<?xml version='1.0' encoding='utf-8'?>
<device schemaVersion="1.1" noNamespaceSchemaLocation="CMSIS-SVD.xsd">
  <vendor>PUYA Co.Ltd</vendor>
  <vendorID>PUYA</vendorID>
  <name>PY32E407xx</name>
  <series>PY32E4</series>
  <version>1.0.0</version>
  <cpu>
    <name>CM4</name>
    <revision>r0p1</revision>
    <endian>little</endian>
    <mpuPresent>true</mpuPresent>
    <fpuPresent>true</fpuPresent>
    <nvicPrioBits>4</nvicPrioBits>
    <vendorSystickConfig>false</vendorSystickConfig>
  </cpu>
  <addressUnitBits>8</addressUnitBits>
  <width>32</width>
  <size>32</size>
  <access>read-write</access>
  <resetValue>0x0</resetValue>
  <resetMask>0xFFFFFFFF</resetMask>
  <peripherals>
    <peripheral>
      <name>ADC1</name>
      <groupName>ADC</groupName>
      <baseAddress>0x40012400</baseAddress>
      <addressBlock>
        <offset>0x0</offset>
        <size>0x200</size>
        <usage>registers</usage>
      </addressBlock>
      <interrupt>
        <name>ADC1_2</name>
        <description>ADC1 and ADC2 global interrupt</description>
        <value>18</value>
      </interrupt>
      <registers>
        <register>
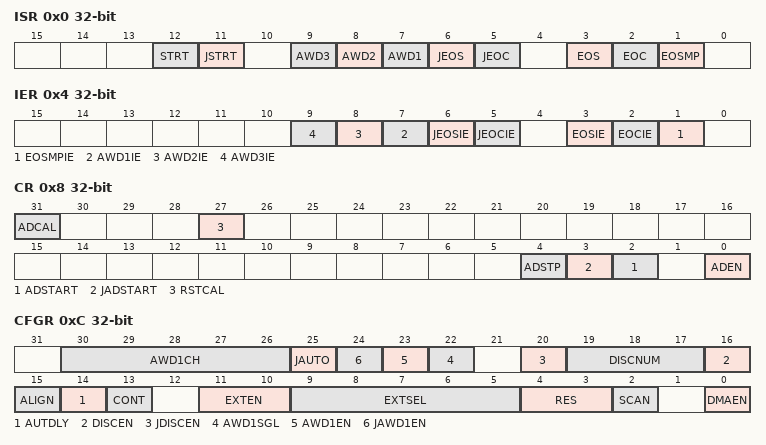
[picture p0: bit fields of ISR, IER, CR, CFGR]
          <name>ISR</name>
          <addressOffset>0x0</addressOffset>
          <fields>
            <field>
              <name>EOSMP</name>
              <bitRange>[1:1]</bitRange>
            </field>
            <field>
              <name>EOC</name>
              <bitRange>[2:2]</bitRange>
            </field>
            <field>
              <name>EOS</name>
              <bitRange>[3:3]</bitRange>
            </field>
            <field>
              <name>JEOC</name>
              <bitRange>[5:5]</bitRange>
            </field>
            <field>
              <name>JEOS</name>
              <bitRange>[6:6]</bitRange>
            </field>
            <field>
              <name>AWD1</name>
              <bitRange>[7:7]</bitRange>
            </field>
            <field>
              <name>AWD2</name>
              <bitRange>[8:8]</bitRange>
            </field>
            <field>
              <name>AWD3</name>
              <bitRange>[9:9]</bitRange>
            </field>
            <field>
              <name>JSTRT</name>
              <bitRange>[11:11]</bitRange>
            </field>
            <field>
              <name>STRT</name>
              <bitRange>[12:12]</bitRange>
            </field>
          </fields>
        </register>
        <register>
          <name>IER</name>
          <addressOffset>0x4</addressOffset>
          <fields>
            <field>
              <name>EOSMPIE</name>
              <bitRange>[1:1]</bitRange>
            </field>
            <field>
              <name>EOCIE</name>
              <bitRange>[2:2]</bitRange>
            </field>
            <field>
              <name>EOSIE</name>
              <bitRange>[3:3]</bitRange>
            </field>
            <field>
              <name>JEOCIE</name>
              <bitRange>[5:5]</bitRange>
            </field>
            <field>
              <name>JEOSIE</name>
              <bitRange>[6:6]</bitRange>
            </field>
            <field>
              <name>AWD1IE</name>
              <bitRange>[7:7]</bitRange>
            </field>
            <field>
              <name>AWD2IE</name>
              <bitRange>[8:8]</bitRange>
            </field>
            <field>
              <name>AWD3IE</name>
              <bitRange>[9:9]</bitRange>
            </field>
          </fields>
        </register>
        <register>
          <name>CR</name>
          <addressOffset>0x8</addressOffset>
          <fields>
            <field>
              <name>ADEN</name>
              <bitRange>[0:0]</bitRange>
            </field>
            <field>
              <name>ADSTART</name>
              <bitRange>[2:2]</bitRange>
            </field>
            <field>
              <name>JADSTART</name>
              <bitRange>[3:3]</bitRange>
            </field>
            <field>
              <name>ADSTP</name>
              <bitRange>[4:4]</bitRange>
            </field>
            <field>
              <name>RSTCAL</name>
              <bitRange>[27:27]</bitRange>
            </field>
            <field>
              <name>ADCAL</name>
              <bitRange>[31:31]</bitRange>
            </field>
          </fields>
        </register>
        <register>
          <name>CFGR</name>
          <addressOffset>0xC</addressOffset>
          <fields>
            <field>
              <name>DMAEN</name>
              <bitRange>[0:0]</bitRange>
            </field>
            <field>
              <name>SCAN</name>
              <bitRange>[2:2]</bitRange>
            </field>
            <field>
              <name>RES</name>
              <bitRange>[4:3]</bitRange>
            </field>
            <field>
              <name>EXTSEL</name>
              <bitRange>[9:5]</bitRange>
            </field>
            <field>
              <name>EXTEN</name>
              <bitRange>[11:10]</bitRange>
            </field>
            <field>
              <name>CONT</name>
              <bitRange>[13:13]</bitRange>
            </field>
            <field>
              <name>AUTDLY</name>
              <bitRange>[14:14]</bitRange>
            </field>
            <field>
              <name>ALIGN</name>
              <bitRange>[15:15]</bitRange>
            </field>
            <field>
              <name>DISCEN</name>
              <bitRange>[16:16]</bitRange>
            </field>
            <field>
              <name>DISCNUM</name>
              <bitRange>[19:17]</bitRange>
            </field>
            <field>
              <name>JDISCEN</name>
              <bitRange>[20:20]</bitRange>
            </field>
            <field>
              <name>AWD1SGL</name>
              <bitRange>[22:22]</bitRange>
            </field>
            <field>
              <name>AWD1EN</name>
              <bitRange>[23:23]</bitRange>
            </field>
            <field>
              <name>JAWD1EN</name>
              <bitRange>[24:24]</bitRange>
            </field>
            <field>
              <name>JAUTO</name>
              <bitRange>[25:25]</bitRange>
            </field>
            <field>
              <name>AWD1CH</name>
              <bitRange>[30:26]</bitRange>
            </field>
          </fields>
        </register>
        <register>
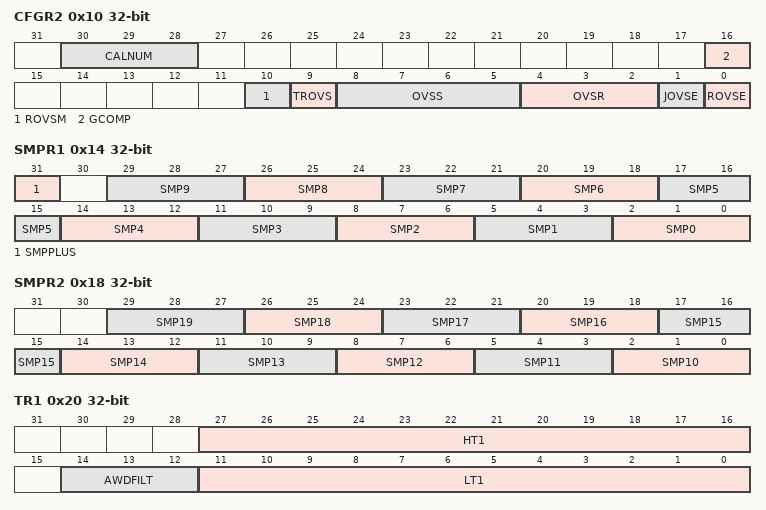
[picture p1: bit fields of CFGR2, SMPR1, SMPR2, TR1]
          <name>CFGR2</name>
          <addressOffset>0x10</addressOffset>
          <fields>
            <field>
              <name>ROVSE</name>
              <bitRange>[0:0]</bitRange>
            </field>
            <field>
              <name>JOVSE</name>
              <bitRange>[1:1]</bitRange>
            </field>
            <field>
              <name>OVSR</name>
              <bitRange>[4:2]</bitRange>
            </field>
            <field>
              <name>OVSS</name>
              <bitRange>[8:5]</bitRange>
            </field>
            <field>
              <name>TROVS</name>
              <bitRange>[9:9]</bitRange>
            </field>
            <field>
              <name>ROVSM</name>
              <bitRange>[10:10]</bitRange>
            </field>
            <field>
              <name>GCOMP</name>
              <bitRange>[16:16]</bitRange>
            </field>
            <field>
              <name>CALNUM</name>
              <bitRange>[30:28]</bitRange>
            </field>
          </fields>
        </register>
        <register>
          <name>SMPR1</name>
          <addressOffset>0x14</addressOffset>
          <fields>
            <field>
              <name>SMP0</name>
              <bitRange>[2:0]</bitRange>
            </field>
            <field>
              <name>SMP1</name>
              <bitRange>[5:3]</bitRange>
            </field>
            <field>
              <name>SMP2</name>
              <bitRange>[8:6]</bitRange>
            </field>
            <field>
              <name>SMP3</name>
              <bitRange>[11:9]</bitRange>
            </field>
            <field>
              <name>SMP4</name>
              <bitRange>[14:12]</bitRange>
            </field>
            <field>
              <name>SMP5</name>
              <bitRange>[17:15]</bitRange>
            </field>
            <field>
              <name>SMP6</name>
              <bitRange>[20:18]</bitRange>
            </field>
            <field>
              <name>SMP7</name>
              <bitRange>[23:21]</bitRange>
            </field>
            <field>
              <name>SMP8</name>
              <bitRange>[26:24]</bitRange>
            </field>
            <field>
              <name>SMP9</name>
              <bitRange>[29:27]</bitRange>
            </field>
          <field><name>SMPPLUS</name><description>SMPPLUS</description><bitRange>[31:31]</bitRange><access>read-write</access></field></fields>
        </register>
        <register>
          <name>SMPR2</name>
          <addressOffset>0x18</addressOffset>
          <fields>
            <field>
              <name>SMP10</name>
              <bitRange>[2:0]</bitRange>
            </field>
            <field>
              <name>SMP11</name>
              <bitRange>[5:3]</bitRange>
            </field>
            <field>
              <name>SMP12</name>
              <bitRange>[8:6]</bitRange>
            </field>
            <field>
              <name>SMP13</name>
              <bitRange>[11:9]</bitRange>
            </field>
            <field>
              <name>SMP14</name>
              <bitRange>[14:12]</bitRange>
            </field>
            <field>
              <name>SMP15</name>
              <bitRange>[17:15]</bitRange>
            </field>
            <field>
              <name>SMP16</name>
              <bitRange>[20:18]</bitRange>
            </field>
            <field>
              <name>SMP17</name>
              <bitRange>[23:21]</bitRange>
            </field>
            <field>
              <name>SMP18</name>
              <bitRange>[26:24]</bitRange>
            </field>
            <field>
              <name>SMP19</name>
              <bitRange>[29:27]</bitRange>
            </field>
          </fields>
        </register>
        <register>
          <name>TR1</name>
          <addressOffset>0x20</addressOffset>
          <fields>
            <field>
              <name>LT1</name>
              <bitRange>[11:0]</bitRange>
            </field>
            <field>
              <name>AWDFILT</name>
              <bitRange>[14:12]</bitRange>
            </field>
            <field>
              <name>HT1</name>
              <bitRange>[27:16]</bitRange>
            </field>
          </fields>
        </register>
        <register>
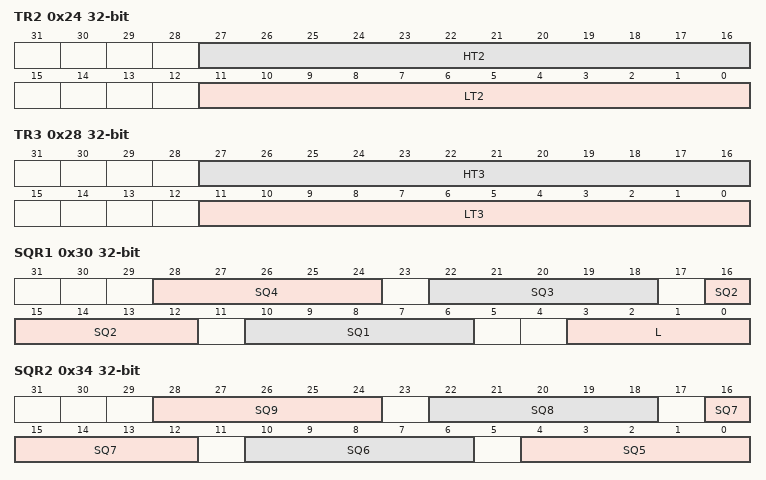
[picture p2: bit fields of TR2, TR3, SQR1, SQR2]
          <name>TR2</name>
          <addressOffset>0x24</addressOffset>
          <fields>
            <field>
              <name>LT2</name>
              <bitRange>[11:0]</bitRange>
            </field>
            <field>
              <name>HT2</name>
              <bitRange>[27:16]</bitRange>
            </field>
          </fields>
        </register>
        <register>
          <name>TR3</name>
          <addressOffset>0x28</addressOffset>
          <fields>
            <field>
              <name>LT3</name>
              <bitRange>[11:0]</bitRange>
            </field>
            <field>
              <name>HT3</name>
              <bitRange>[27:16]</bitRange>
            </field>
          </fields>
        </register>
        <register>
          <name>SQR1</name>
          <addressOffset>0x30</addressOffset>
          <fields>
            <field>
              <name>L</name>
              <bitRange>[3:0]</bitRange>
            </field>
            <field>
              <name>SQ1</name>
              <bitRange>[10:6]</bitRange>
            </field>
            <field>
              <name>SQ2</name>
              <bitRange>[16:12]</bitRange>
            </field>
            <field>
              <name>SQ3</name>
              <bitRange>[22:18]</bitRange>
            </field>
            <field>
              <name>SQ4</name>
              <bitRange>[28:24]</bitRange>
            </field>
          </fields>
        </register>
        <register>
          <name>SQR2</name>
          <addressOffset>0x34</addressOffset>
          <fields>
            <field>
              <name>SQ5</name>
              <bitRange>[4:0]</bitRange>
            </field>
            <field>
              <name>SQ6</name>
              <bitRange>[10:6]</bitRange>
            </field>
            <field>
              <name>SQ7</name>
              <bitRange>[16:12]</bitRange>
            </field>
            <field>
              <name>SQ8</name>
              <bitRange>[22:18]</bitRange>
            </field>
            <field>
              <name>SQ9</name>
              <bitRange>[28:24]</bitRange>
            </field>
          </fields>
        </register>
        <register>
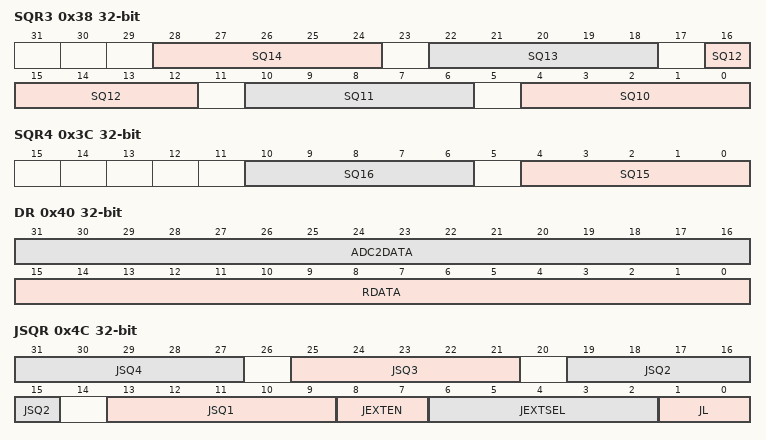
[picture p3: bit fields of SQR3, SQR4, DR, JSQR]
          <name>SQR3</name>
          <addressOffset>0x38</addressOffset>
          <fields>
            <field>
              <name>SQ10</name>
              <bitRange>[4:0]</bitRange>
            </field>
            <field>
              <name>SQ11</name>
              <bitRange>[10:6]</bitRange>
            </field>
            <field>
              <name>SQ12</name>
              <bitRange>[16:12]</bitRange>
            </field>
            <field>
              <name>SQ13</name>
              <bitRange>[22:18]</bitRange>
            </field>
            <field>
              <name>SQ14</name>
              <bitRange>[28:24]</bitRange>
            </field>
          </fields>
        </register>
        <register>
          <name>SQR4</name>
          <addressOffset>0x3C</addressOffset>
          <fields>
            <field>
              <name>SQ15</name>
              <bitRange>[4:0]</bitRange>
            </field>
            <field>
              <name>SQ16</name>
              <bitRange>[10:6]</bitRange>
            </field>
          </fields>
        </register>
        <register>
          <name>DR</name>
          <addressOffset>0x40</addressOffset>
          <fields>
            <field>
              <name>RDATA</name>
              <bitRange>[15:0]</bitRange>
              <access>read-only</access>
            </field>
            <field>
              <name>ADC2DATA</name>
              <bitRange>[31:16]</bitRange>
              <access>read-only</access>
            </field>
          </fields>
        </register>
        <register>
          <name>JSQR</name>
          <addressOffset>0x4C</addressOffset>
          <fields>
            <field>
              <name>JL</name>
              <bitRange>[1:0]</bitRange>
            </field>
            <field>
              <name>JEXTSEL</name>
              <bitRange>[6:2]</bitRange>
            </field>
            <field>
              <name>JSQ1</name>
              <bitRange>[13:9]</bitRange>
            </field>
            <field>
              <name>JSQ2</name>
              <bitRange>[19:15]</bitRange>
            </field>
            <field>
              <name>JSQ3</name>
              <bitRange>[25:21]</bitRange>
            </field>
            <field>
              <name>JSQ4</name>
              <bitRange>[31:27]</bitRange>
            </field>
          <field><name>JEXTEN</name><description>JEXTEN</description><bitRange>[8:7]</bitRange><access>read-write</access></field></fields>
        </register>
        <register>
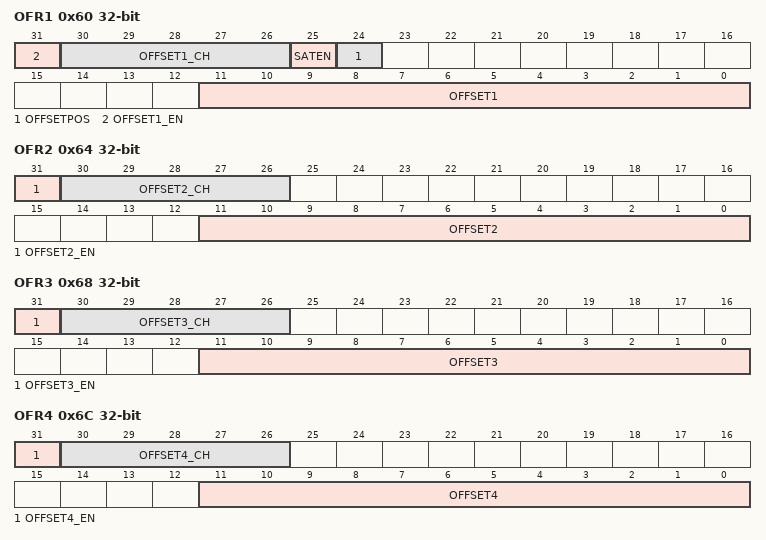
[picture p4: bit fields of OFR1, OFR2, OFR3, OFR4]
          <name>OFR1</name>
          <addressOffset>0x60</addressOffset>
          <fields>
            <field>
              <name>OFFSET1</name>
              <bitRange>[11:0]</bitRange>
            </field>
            <field>
              <name>OFFSETPOS</name>
              <bitRange>[24:24]</bitRange>
            </field>
            <field>
              <name>SATEN</name>
              <bitRange>[25:25]</bitRange>
            </field>
            <field>
              <name>OFFSET1_CH</name>
              <bitRange>[30:26]</bitRange>
            </field>
            <field>
              <name>OFFSET1_EN</name>
              <bitRange>[31:31]</bitRange>
            </field>
          </fields>
        </register>
        <register>
          <name>OFR2</name>
          <addressOffset>0x64</addressOffset>
          <fields>
            <field>
              <name>OFFSET2</name>
              <bitRange>[11:0]</bitRange>
            </field>
            <field>
              <name>OFFSET2_CH</name>
              <bitRange>[30:26]</bitRange>
            </field>
            <field>
              <name>OFFSET2_EN</name>
              <bitRange>[31:31]</bitRange>
            </field>
          </fields>
        </register>
        <register>
          <name>OFR3</name>
          <addressOffset>0x68</addressOffset>
          <fields>
            <field>
              <name>OFFSET3</name>
              <bitRange>[11:0]</bitRange>
            </field>
            <field>
              <name>OFFSET3_CH</name>
              <bitRange>[30:26]</bitRange>
            </field>
            <field>
              <name>OFFSET3_EN</name>
              <bitRange>[31:31]</bitRange>
            </field>
          </fields>
        </register>
        <register>
          <name>OFR4</name>
          <addressOffset>0x6C</addressOffset>
          <fields>
            <field>
              <name>OFFSET4</name>
              <bitRange>[11:0]</bitRange>
            </field>
            <field>
              <name>OFFSET4_CH</name>
              <bitRange>[30:26]</bitRange>
            </field>
            <field>
              <name>OFFSET4_EN</name>
              <bitRange>[31:31]</bitRange>
            </field>
          </fields>
        </register>
        <register>
          <name>JDR1</name>
          <addressOffset>0x80</addressOffset>
          <fields>
            <field>
              <name>JDATA</name>
              <bitRange>[15:0]</bitRange>
              <access>read-only</access>
            </field>
          </fields>
        </register>
        <register>
          <name>JDR2</name>
          <addressOffset>0x84</addressOffset>
          <fields>
            <field>
              <name>JDATA</name>
              <bitRange>[15:0]</bitRange>
              <access>read-only</access>
            </field>
          </fields>
        </register>
        <register>
          <name>JDR3</name>
          <addressOffset>0x88</addressOffset>
          <fields>
            <field>
              <name>JDATA</name>
              <bitRange>[15:0]</bitRange>
              <access>read-only</access>
            </field>
          </fields>
        </register>
        <register>
          <name>JDR4</name>
          <addressOffset>0x8C</addressOffset>
          <fields>
            <field>
              <name>JDATA</name>
              <bitRange>[15:0]</bitRange>
              <access>read-only</access>
            </field>
          </fields>
        </register>
        <register>
          <name>AWD2CR</name>
          <addressOffset>0xA0</addressOffset>
          <fields>
            <field>
              <name>AWD2CH</name>
              <bitRange>[19:0]</bitRange>
            </field>
          </fields>
        </register>
        <register>
          <name>AWD3CR</name>
          <addressOffset>0xA4</addressOffset>
          <fields>
            <field>
              <name>AWD3CH</name>
              <bitRange>[19:0]</bitRange>
            </field>
          </fields>
        </register>
        <register>
          <name>DIFSEL</name>
          <addressOffset>0xB0</addressOffset>
          <fields>
            <field>
              <name>DIFSEL</name>
              <bitRange>[19:0]</bitRange>
            </field>
          </fields>
        </register>
        <register>
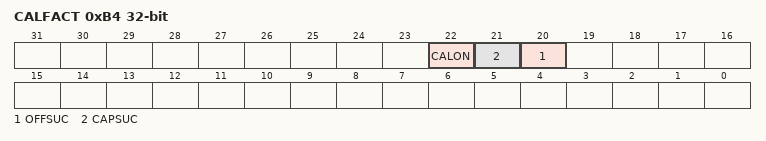
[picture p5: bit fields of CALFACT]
          <name>CALFACT</name>
          <addressOffset>0xB4</addressOffset>
          <fields>
            <field>
              <name>OFFSUC</name>
              <bitRange>[20:20]</bitRange>
            </field>
            <field>
              <name>CAPSUC</name>
              <bitRange>[21:21]</bitRange>
            </field>
            <field>
              <name>CALON</name>
              <bitRange>[22:22]</bitRange>
              <access>read-only</access>
            </field>
          </fields>
        </register>
        <register>
          <name>GCOMP</name>
          <addressOffset>0xC0</addressOffset>
          <fields>
            <field>
              <name>GCOMPCOEFF</name>
              <bitRange>[13:0]</bitRange>
            </field>
          </fields>
        </register>
      </registers>
    </peripheral>
    <peripheral derivedFrom="ADC1">
      <name>ADC2</name>
      <baseAddress>0x40012800</baseAddress>
    </peripheral>
    <peripheral derivedFrom="ADC1">
      <name>ADC3</name>
      <baseAddress>0x40013C00</baseAddress>
      <interrupt>
        <name>ADC3</name>
        <description>ADC3 global interrupt</description>
        <value>47</value>
      </interrupt>
    </peripheral>
    <peripheral>
      <name>ADC12_COMMON</name>
      <description>Analog-to-Digital Converter</description>
      <baseAddress>0x40012700</baseAddress>
      <addressBlock>
        <offset>0x0</offset>
        <size>0x10</size>
        <usage>registers</usage>
      </addressBlock>
      <registers>
        <register>
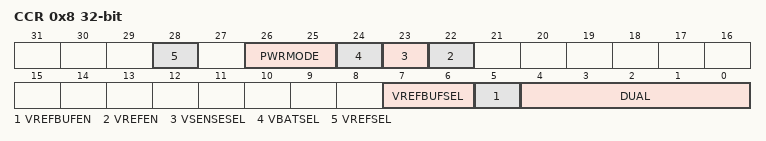
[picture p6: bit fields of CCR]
          <name>CCR</name>
          <description>ADC common control register</description>
          <addressOffset>0x8</addressOffset>
          <fields>
            <field>
              <name>DUAL</name>
              <description>Dual ADC mode selection</description>
              <bitRange>[4:0]</bitRange>
            </field>
            <field>
              <name>VREFBUFEN</name>
              <description>VrefBuffer enable</description>
              <bitRange>[5:5]</bitRange>
            </field>
            <field>
              <name>VREFBUFSEL</name>
              <description>VREFBUF output voltage select</description>
              <bitRange>[7:6]</bitRange>
            </field>
            <field>
              <name>VREFEN</name>
              <description>VREFINT enable</description>
              <bitRange>[22:22]</bitRange>
            </field>
            <field>
              <name>VSENSESEL</name>
              <description>VTS selection</description>
              <bitRange>[23:23]</bitRange>
            </field>
            <field>
              <name>VBATSEL</name>
              <description>VBAT selection</description>
              <bitRange>[24:24]</bitRange>
            </field>
            <field>
              <name>PWRMODE</name>
              <description>ADC power mode</description>
              <bitRange>[26:25]</bitRange>
            </field>
            <field>
              <name>VREFSEL</name>
              <description>ADC reference selection</description>
              <bitRange>[28:28]</bitRange>
            </field>
          </fields>
        </register>
      </registers>
    </peripheral>
    <peripheral>
      <name>AES</name>
      <baseAddress>0x48002400</baseAddress>
      <addressBlock>
        <offset>0x0</offset>
        <size>0xB0</size>
        <usage>registers</usage>
      </addressBlock>
      <interrupt>
        <name>AES</name>
        <description>AES global Interrupt</description>
        <value>70</value>
      </interrupt>
      <registers>
        <register>
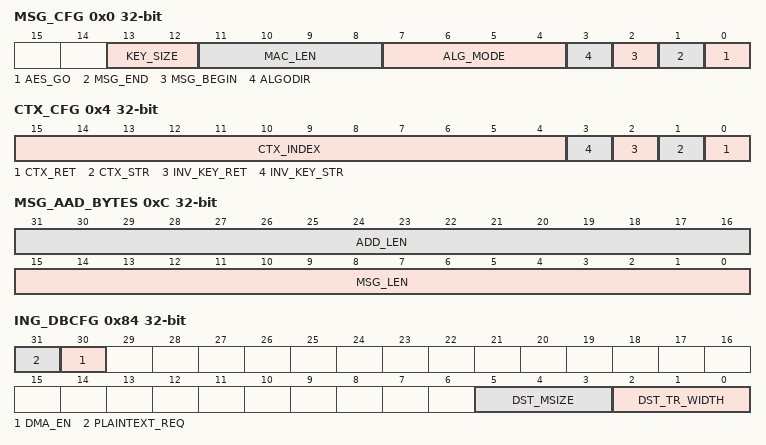
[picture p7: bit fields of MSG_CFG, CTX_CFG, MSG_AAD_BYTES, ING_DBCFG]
          <name>MSG_CFG</name>
          <addressOffset>0x0</addressOffset>
          <fields>
            <field>
              <name>AES_GO</name>
              <bitRange>[0:0]</bitRange>
            </field>
            <field>
              <name>MSG_END</name>
              <bitRange>[1:1]</bitRange>
            </field>
            <field>
              <name>MSG_BEGIN</name>
              <bitRange>[2:2]</bitRange>
            </field>
            <field>
              <name>ALGODIR</name>
              <bitRange>[3:3]</bitRange>
            </field>
            <field>
              <name>ALG_MODE</name>
              <bitRange>[7:4]</bitRange>
            </field>
            <field>
              <name>MAC_LEN</name>
              <bitRange>[11:8]</bitRange>
            </field>
            <field>
              <name>KEY_SIZE</name>
              <bitRange>[13:12]</bitRange>
            </field>
          </fields>
        </register>
        <register>
          <name>CTX_CFG</name>
          <addressOffset>0x4</addressOffset>
          <fields>
            <field>
              <name>CTX_RET</name>
              <bitRange>[0:0]</bitRange>
            </field>
            <field>
              <name>CTX_STR</name>
              <bitRange>[1:1]</bitRange>
            </field>
            <field>
              <name>INV_KEY_RET</name>
              <bitRange>[2:2]</bitRange>
            </field>
            <field>
              <name>INV_KEY_STR</name>
              <bitRange>[3:3]</bitRange>
            </field>
            <field>
              <name>CTX_INDEX</name>
              <bitRange>[15:4]</bitRange>
            </field>
          </fields>
        </register>
        <register>
          <name>MSG_TOTAL_BYTES</name>
          <addressOffset>0x8</addressOffset>
          <fields>
            <field>
              <name>TOTAL_BYTES</name>
              <bitRange>[27:0]</bitRange>
            </field>
          </fields>
        </register>
        <register>
          <name>MSG_AAD_BYTES</name>
          <addressOffset>0xC</addressOffset>
          <fields>
            <field>
              <name>MSG_LEN</name>
              <bitRange>[15:0]</bitRange>
            </field>
            <field>
              <name>ADD_LEN</name>
              <bitRange>[31:16]</bitRange>
            </field>
          </fields>
        </register>
        <register>
          <name>GCM_AAD_INFO</name>
          <addressOffset>0x10</addressOffset>
          <fields>
            <field>
              <name>ADD_LEN_TOT</name>
              <bitRange>[27:0]</bitRange>
            </field>
          </fields>
        </register>
        <register>
          <name>CTX_KEY0</name>
          <addressOffset>0x20</addressOffset>
          <fields>
            <field>
              <name>KEY0</name>
              <bitRange>[31:0]</bitRange>
            </field>
          </fields>
        </register>
        <register>
          <name>CTX_KEY1</name>
          <addressOffset>0x24</addressOffset>
          <fields>
            <field>
              <name>KEY1</name>
              <bitRange>[31:0]</bitRange>
            </field>
          </fields>
        </register>
        <register>
          <name>CTX_KEY2</name>
          <addressOffset>0x28</addressOffset>
          <fields>
            <field>
              <name>KEY2</name>
              <bitRange>[31:0]</bitRange>
            </field>
          </fields>
        </register>
        <register>
          <name>CTX_KEY3</name>
          <addressOffset>0x2C</addressOffset>
          <fields>
            <field>
              <name>KEY3</name>
              <bitRange>[31:0]</bitRange>
            </field>
          </fields>
        </register>
        <register>
          <name>CTX_KEY4</name>
          <addressOffset>0x30</addressOffset>
          <fields>
            <field>
              <name>KEY4</name>
              <bitRange>[31:0]</bitRange>
            </field>
          </fields>
        </register>
        <register>
          <name>CTX_KEY5</name>
          <addressOffset>0x34</addressOffset>
          <fields>
            <field>
              <name>KEY5</name>
              <bitRange>[31:0]</bitRange>
            </field>
          </fields>
        </register>
        <register>
          <name>CTX_KEY6</name>
          <addressOffset>0x38</addressOffset>
          <fields>
            <field>
              <name>KEY6</name>
              <bitRange>[31:0]</bitRange>
            </field>
          </fields>
        </register>
        <register>
          <name>CTX_KEY7</name>
          <addressOffset>0x3C</addressOffset>
          <fields>
            <field>
              <name>KEY7</name>
              <bitRange>[31:0]</bitRange>
            </field>
          </fields>
        </register>
        <register>
          <name>CTX_CBC_KEY0</name>
          <addressOffset>0x40</addressOffset>
          <fields>
            <field>
              <name>CBC_KEY0</name>
              <bitRange>[31:0]</bitRange>
            </field>
          </fields>
        </register>
        <register>
          <name>CTX_CBC_KEY1</name>
          <addressOffset>0x44</addressOffset>
          <fields>
            <field>
              <name>CBC_KEY1</name>
              <bitRange>[31:0]</bitRange>
            </field>
          </fields>
        </register>
        <register>
          <name>CTX_CBC_KEY2</name>
          <addressOffset>0x48</addressOffset>
          <fields>
            <field>
              <name>CBC_KEY2</name>
              <bitRange>[31:0]</bitRange>
            </field>
          </fields>
        </register>
        <register>
          <name>CTX_CBC_KEY3</name>
          <addressOffset>0x4C</addressOffset>
          <fields>
            <field>
              <name>CBC_KEY3</name>
              <bitRange>[31:0]</bitRange>
            </field>
          </fields>
        </register>
        <register>
          <name>CTX_CTR0</name>
          <addressOffset>0x50</addressOffset>
          <fields>
            <field>
              <name>CBC_KEY0</name>
              <bitRange>[31:0]</bitRange>
            </field>
          </fields>
        </register>
        <register>
          <name>CTX_CTR1</name>
          <addressOffset>0x54</addressOffset>
          <fields>
            <field>
              <name>CBC_KEY1</name>
              <bitRange>[31:0]</bitRange>
            </field>
          </fields>
        </register>
        <register>
          <name>CTX_CTR2</name>
          <addressOffset>0x58</addressOffset>
          <fields>
            <field>
              <name>CBC_KEY2</name>
              <bitRange>[31:0]</bitRange>
            </field>
          </fields>
        </register>
        <register>
          <name>CTX_CTR3</name>
          <addressOffset>0x5C</addressOffset>
          <fields>
            <field>
              <name>CBC_KEY3</name>
              <bitRange>[31:0]</bitRange>
            </field>
          </fields>
        </register>
        <register>
          <name>CTX_IV0</name>
          <addressOffset>0x60</addressOffset>
          <fields>
            <field>
              <name>IV0</name>
              <bitRange>[31:0]</bitRange>
            </field>
          </fields>
        </register>
        <register>
          <name>CTX_IV1</name>
          <addressOffset>0x64</addressOffset>
          <fields>
            <field>
              <name>IV1</name>
              <bitRange>[31:0]</bitRange>
            </field>
          </fields>
        </register>
        <register>
          <name>CTX_IV2</name>
          <addressOffset>0x68</addressOffset>
          <fields>
            <field>
              <name>IV2</name>
              <bitRange>[31:0]</bitRange>
            </field>
          </fields>
        </register>
        <register>
          <name>CTX_IV3</name>
          <addressOffset>0x6C</addressOffset>
          <fields>
            <field>
              <name>IV3</name>
              <bitRange>[31:0]</bitRange>
            </field>
          </fields>
        </register>
        <register>
          <name>CTX_MAC0</name>
          <addressOffset>0x70</addressOffset>
          <fields>
            <field>
              <name>MAC0</name>
              <bitRange>[31:0]</bitRange>
            </field>
          </fields>
        </register>
        <register>
          <name>CTX_MAC1</name>
          <addressOffset>0x74</addressOffset>
          <fields>
            <field>
              <name>MAC1</name>
              <bitRange>[31:0]</bitRange>
            </field>
          </fields>
        </register>
        <register>
          <name>CTX_MAC2</name>
          <addressOffset>0x78</addressOffset>
          <fields>
            <field>
              <name>MAC2</name>
              <bitRange>[31:0]</bitRange>
            </field>
          </fields>
        </register>
        <register>
          <name>CTX_MAC3</name>
          <addressOffset>0x7C</addressOffset>
          <fields>
            <field>
              <name>MAC3</name>
              <bitRange>[31:0]</bitRange>
            </field>
          </fields>
        </register>
        <register>
          <name>INGRESS_FIFO</name>
          <addressOffset>0x80</addressOffset>
          <fields>
            <field>
              <name>INGRESS_FIFO</name>
              <bitRange>[31:0]</bitRange>
            </field>
          </fields>
        </register>
        <register>
          <name>ING_DBCFG</name>
          <addressOffset>0x84</addressOffset>
          <fields>
            <field>
              <name>DST_TR_WIDTH</name>
              <bitRange>[2:0]</bitRange>
            </field>
            <field>
              <name>DST_MSIZE</name>
              <bitRange>[5:3]</bitRange>
            </field>
            <field>
              <name>DMA_EN</name>
              <bitRange>[30:30]</bitRange>
            </field>
            <field>
              <name>PLAINTEXT_REQ</name>
              <bitRange>[31:31]</bitRange>
            </field>
          </fields>
        </register>
        <register>
          <name>DMA_ENG_LEN</name>
          <addressOffset>0x88</addressOffset>
          <fields>
            <field>
              <name>ENGRESS_DMA_DATA_LENGTH</name>
              <bitRange>[31:0]</bitRange>
            </field>
          </fields>
        </register>
        <register>
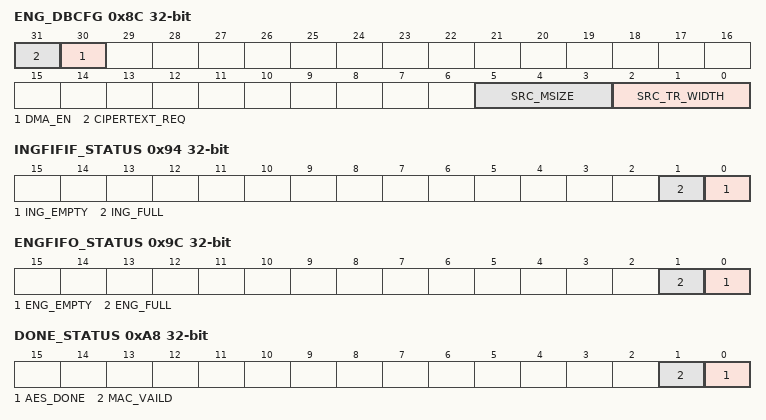
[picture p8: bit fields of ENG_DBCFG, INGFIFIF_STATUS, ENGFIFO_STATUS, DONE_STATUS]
          <name>ENG_DBCFG</name>
          <addressOffset>0x8C</addressOffset>
          <fields>
            <field>
              <name>SRC_TR_WIDTH</name>
              <bitRange>[2:0]</bitRange>
            </field>
            <field>
              <name>SRC_MSIZE</name>
              <bitRange>[5:3]</bitRange>
            </field>
            <field>
              <name>DMA_EN</name>
              <bitRange>[30:30]</bitRange>
            </field>
            <field>
              <name>CIPERTEXT_REQ</name>
              <bitRange>[31:31]</bitRange>
            </field>
          </fields>
        </register>
        <register>
          <name>DMA_ING_LEN</name>
          <addressOffset>0x90</addressOffset>
          <fields>
            <field>
              <name>INGRESS_DMA_DATA_LENGTH</name>
              <bitRange>[31:0]</bitRange>
            </field>
          </fields>
        </register>
        <register>
          <name>INGFIFIF_STATUS</name>
          <addressOffset>0x94</addressOffset>
          <fields>
            <field>
              <name>ING_EMPTY</name>
              <bitRange>[0:0]</bitRange>
              <access>read-only</access>
            </field>
            <field>
              <name>ING_FULL</name>
              <bitRange>[1:1]</bitRange>
              <access>read-only</access>
            </field>
          </fields>
        </register>
        <register>
          <name>ENGRESS_FIFO</name>
          <addressOffset>0x98</addressOffset>
          <fields>
            <field>
              <name>INGRESS_FIFO</name>
              <bitRange>[31:0]</bitRange>
              <access>read-only</access>
            </field>
          </fields>
        </register>
        <register>
          <name>ENGFIFO_STATUS</name>
          <addressOffset>0x9C</addressOffset>
          <fields>
            <field>
              <name>ENG_EMPTY</name>
              <bitRange>[0:0]</bitRange>
              <access>read-only</access>
            </field>
            <field>
              <name>ENG_FULL</name>
              <bitRange>[1:1]</bitRange>
              <access>read-only</access>
            </field>
          </fields>
        </register>
        <register>
          <name>ING_DMA_DONE</name>
          <addressOffset>0xA0</addressOffset>
          <fields>
            <field>
              <name>DMA_INGRESS_DONE</name>
              <bitRange>[0:0]</bitRange>
              <access>read-only</access>
            </field>
          </fields>
        </register>
        <register>
          <name>ENG_DMA_DONE</name>
          <addressOffset>0xA4</addressOffset>
          <fields>
            <field>
              <name>DMA_NGRESS_DONE</name>
              <bitRange>[0:0]</bitRange>
              <access>read-only</access>
            </field>
          </fields>
        </register>
        <register>
          <name>DONE_STATUS</name>
          <addressOffset>0xA8</addressOffset>
          <fields>
            <field>
              <name>AES_DONE</name>
              <bitRange>[0:0]</bitRange>
            </field>
            <field>
              <name>MAC_VAILD</name>
              <bitRange>[1:1]</bitRange>
            </field>
          </fields>
        </register>
      </registers>
    </peripheral>
    <peripheral>
      <name>BKP</name>
      <baseAddress>0x40006C00</baseAddress>
      <addressBlock>
        <offset>0x0</offset>
        <size>0x400</size>
        <usage>registers</usage>
      </addressBlock>
      <registers>
        <register>
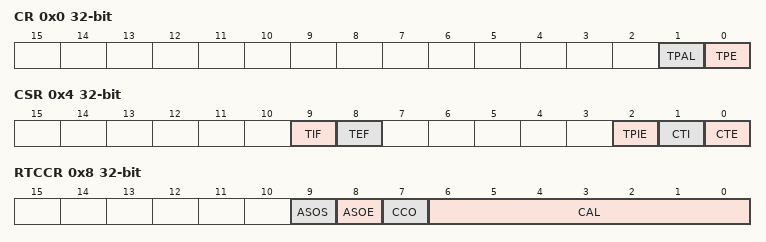
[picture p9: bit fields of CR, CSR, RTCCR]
          <name>CR</name>
          <addressOffset>0x0</addressOffset>
          <fields>
            <field>
              <name>TPE</name>
              <description>TAMP enable</description>
              <bitRange>[0:0]</bitRange>
            </field>
            <field>
              <name>TPAL</name>
              <description>TAMPER pin interrupt enable</description>
              <bitRange>[1:1]</bitRange>
            </field>
          </fields>
        </register>
        <register>
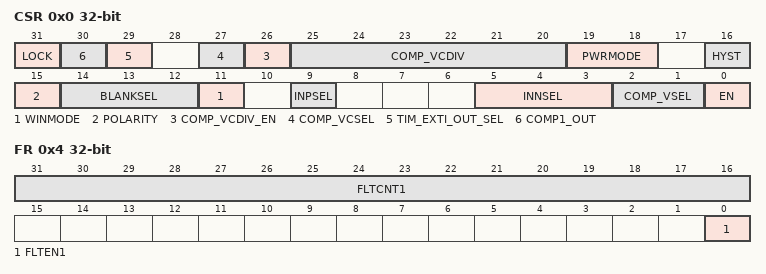
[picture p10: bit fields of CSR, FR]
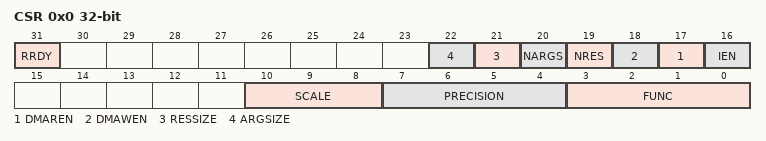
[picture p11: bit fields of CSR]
          <name>CSR</name>
          <addressOffset>0x4</addressOffset>
          <fields>
            <field>
              <name>CTE</name>
              <description>clear TAMP event</description>
              <bitRange>[0:0]</bitRange>
            </field>
            <field>
              <name>CTI</name>
              <description>clear TAMP interrupt</description>
              <bitRange>[1:1]</bitRange>
            </field>
            <field>
              <name>TPIE</name>
              <description>TAMP interrupt enable</description>
              <bitRange>[2:2]</bitRange>
            </field>
            <field>
              <name>TEF</name>
              <description>TAMP event flag</description>
              <bitRange>[8:8]</bitRange>
              <access>read-only</access>
            </field>
            <field>
              <name>TIF</name>
              <description>TAMP interrupt flag</description>
              <bitRange>[9:9]</bitRange>
              <access>read-only</access>
            </field>
          </fields>
        </register>
        <register>
          <name>RTCCR</name>
          <addressOffset>0x8</addressOffset>
          <fields>
            <field>
              <name>CAL</name>
              <description>RTC calibration value</description>
              <bitRange>[6:0]</bitRange>
            </field>
            <field>
              <name>CCO</name>
              <description>Calibration clock output</description>
              <bitRange>[7:7]</bitRange>
            </field>
            <field>
              <name>ASOE</name>
              <description>Alarm or second output enable</description>
              <bitRange>[8:8]</bitRange>
            </field>
            <field>
              <name>ASOS</name>
              <description>Alarm or second output selection</description>
              <bitRange>[9:9]</bitRange>
            </field>
          </fields>
        </register>
        <register>
          <name>DR0</name>
          <addressOffset>0x80</addressOffset>
          <fields>
            <field>
              <name>D</name>
              <description>bakeup data byte0</description>
              <bitRange>[31:0]</bitRange>
            </field>
          </fields>
        </register>
        <register>
          <name>DR1</name>
          <addressOffset>0x84</addressOffset>
          <fields>
            <field>
              <name>D</name>
              <description>bakeup data byte1</description>
              <bitRange>[31:0]</bitRange>
            </field>
          </fields>
        </register>
        <register>
          <name>DR2</name>
          <addressOffset>0x88</addressOffset>
          <fields>
            <field>
              <name>D</name>
              <description>bakeup data byte2</description>
              <bitRange>[31:0]</bitRange>
            </field>
          </fields>
        </register>
        <register>
          <name>DR3</name>
          <addressOffset>0x8C</addressOffset>
          <fields>
            <field>
              <name>D</name>
              <description>bakeup data byte3</description>
              <bitRange>[31:0]</bitRange>
            </field>
          </fields>
        </register>
        <register>
          <name>DR4</name>
          <addressOffset>0x90</addressOffset>
          <fields>
            <field>
              <name>D</name>
              <description>bakeup data byte4</description>
              <bitRange>[31:0]</bitRange>
            </field>
          </fields>
        </register>
        <register>
          <name>DR5</name>
          <addressOffset>0x94</addressOffset>
          <fields>
            <field>
              <name>D</name>
              <description>bakeup data byte5</description>
              <bitRange>[31:0]</bitRange>
            </field>
          </fields>
        </register>
        <register>
          <name>DR6</name>
          <addressOffset>0x98</addressOffset>
          <fields>
            <field>
              <name>D</name>
              <description>bakeup data byte6</description>
              <bitRange>[31:0]</bitRange>
            </field>
          </fields>
        </register>
        <register>
          <name>DR7</name>
          <addressOffset>0x9C</addressOffset>
          <fields>
            <field>
              <name>D</name>
              <description>bakeup data byte7</description>
              <bitRange>[31:0]</bitRange>
            </field>
          </fields>
        </register>
        <register>
          <name>DR8</name>
          <addressOffset>0xA0</addressOffset>
          <fields>
            <field>
              <name>D</name>
              <description>bakeup data byte8</description>
              <bitRange>[31:0]</bitRange>
            </field>
          </fields>
        </register>
        <register>
          <name>DR9</name>
          <addressOffset>0xA4</addressOffset>
          <fields>
            <field>
              <name>D</name>
              <description>bakeup data byte9</description>
              <bitRange>[31:0]</bitRange>
            </field>
          </fields>
        </register>
        <register>
          <name>DR10</name>
          <addressOffset>0xA8</addressOffset>
          <fields>
            <field>
              <name>D</name>
              <description>bakeup data byte10</description>
              <bitRange>[31:0]</bitRange>
            </field>
          </fields>
        </register>
        <register>
          <name>DR11</name>
          <addressOffset>0xAC</addressOffset>
          <fields>
            <field>
              <name>D</name>
              <description>bakeup data byte11</description>
              <bitRange>[31:0]</bitRange>
            </field>
          </fields>
        </register>
        <register>
          <name>DR12</name>
          <addressOffset>0xB0</addressOffset>
          <fields>
            <field>
              <name>D</name>
              <description>bakeup data byte12</description>
              <bitRange>[31:0]</bitRange>
            </field>
          </fields>
        </register>
        <register>
          <name>DR13</name>
          <addressOffset>0xB4</addressOffset>
          <fields>
            <field>
              <name>D</name>
              <description>bakeup data byte13</description>
              <bitRange>[31:0]</bitRange>
            </field>
          </fields>
        </register>
        <register>
          <name>DR14</name>
          <addressOffset>0xB8</addressOffset>
          <fields>
            <field>
              <name>D</name>
              <description>bakeup data byte14</description>
              <bitRange>[31:0]</bitRange>
            </field>
          </fields>
        </register>
        <register>
          <name>DR15</name>
          <addressOffset>0xBC</addressOffset>
          <fields>
            <field>
              <name>D</name>
              <description>bakeup data byte15</description>
              <bitRange>[31:0]</bitRange>
            </field>
          </fields>
        </register>
        <register>
          <name>DR16</name>
          <addressOffset>0xC0</addressOffset>
          <fields>
            <field>
              <name>D</name>
              <description>bakeup data byte16</description>
              <bitRange>[31:0]</bitRange>
            </field>
          </fields>
        </register>
        <register>
          <name>DR17</name>
          <addressOffset>0xC4</addressOffset>
          <fields>
            <field>
              <name>D</name>
              <description>bakeup data byte17</description>
              <bitRange>[31:0]</bitRange>
            </field>
          </fields>
        </register>
        <register>
          <name>DR18</name>
          <addressOffset>0xC8</addressOffset>
          <fields>
            <field>
              <name>D</name>
              <description>bakeup data byte18</description>
              <bitRange>[31:0]</bitRange>
            </field>
          </fields>
        </register>
        <register>
          <name>DR19</name>
          <addressOffset>0xCC</addressOffset>
          <fields>
            <field>
              <name>D</name>
              <description>bakeup data byte19</description>
              <bitRange>[31:0]</bitRange>
            </field>
          </fields>
        </register>
        <register>
          <name>DR20</name>
          <addressOffset>0xD0</addressOffset>
          <fields>
            <field>
              <name>D</name>
              <description>bakeup data byte20</description>
              <bitRange>[31:0]</bitRange>
            </field>
          </fields>
        </register>
        <register>
          <name>DR21</name>
          <addressOffset>0xD4</addressOffset>
          <fields>
            <field>
              <name>D</name>
              <description>bakeup data byte21</description>
              <bitRange>[31:0]</bitRange>
            </field>
          </fields>
        </register>
        <register>
          <name>DR22</name>
          <addressOffset>0xD8</addressOffset>
          <fields>
            <field>
              <name>D</name>
              <description>bakeup data byte22</description>
              <bitRange>[31:0]</bitRange>
            </field>
          </fields>
        </register>
        <register>
          <name>DR23</name>
          <addressOffset>0xDC</addressOffset>
          <fields>
            <field>
              <name>D</name>
              <description>bakeup data byte23</description>
              <bitRange>[31:0]</bitRange>
            </field>
          </fields>
        </register>
        <register>
          <name>DR24</name>
          <addressOffset>0xE0</addressOffset>
          <fields>
            <field>
              <name>D</name>
              <description>bakeup data byte24</description>
              <bitRange>[31:0]</bitRange>
            </field>
          </fields>
        </register>
        <register>
          <name>DR25</name>
          <addressOffset>0xE4</addressOffset>
          <fields>
            <field>
              <name>D</name>
              <description>bakeup data byte25</description>
              <bitRange>[31:0]</bitRange>
            </field>
          </fields>
        </register>
        <register>
          <name>DR26</name>
          <addressOffset>0xE8</addressOffset>
          <fields>
            <field>
              <name>D</name>
              <description>bakeup data byte26</description>
              <bitRange>[31:0]</bitRange>
            </field>
          </fields>
        </register>
        <register>
          <name>DR27</name>
          <addressOffset>0xEC</addressOffset>
          <fields>
            <field>
              <name>D</name>
              <description>bakeup data byte27</description>
              <bitRange>[31:0]</bitRange>
            </field>
          </fields>
        </register>
        <register>
          <name>DR28</name>
          <addressOffset>0xF0</addressOffset>
          <fields>
            <field>
              <name>D</name>
              <description>bakeup data byte28</description>
              <bitRange>[31:0]</bitRange>
            </field>
          </fields>
        </register>
        <register>
          <name>DR29</name>
          <addressOffset>0xF4</addressOffset>
          <fields>
            <field>
              <name>D</name>
              <description>bakeup data byte29</description>
              <bitRange>[31:0]</bitRange>
            </field>
          </fields>
        </register>
        <register>
          <name>DR30</name>
          <addressOffset>0xF8</addressOffset>
          <fields>
            <field>
              <name>D</name>
              <description>bakeup data byte30</description>
              <bitRange>[31:0]</bitRange>
            </field>
          </fields>
        </register>
        <register>
          <name>DR31</name>
          <addressOffset>0xFC</addressOffset>
          <fields>
            <field>
              <name>D</name>
              <description>bakeup data byte31</description>
              <bitRange>[31:0]</bitRange>
            </field>
          </fields>
        </register>
      </registers>
    </peripheral>
    <peripheral>
      <name>COMP1</name>
      <groupName>COMP</groupName>
      <baseAddress>0x40016C00</baseAddress>
      <addressBlock>
        <offset>0x0</offset>
        <size>0x10</size>
        <usage>registers</usage>
      </addressBlock>
      <interrupt>
        <name>COMP1</name>
        <description>COMP1 global Interrupt</description>
        <value>73</value>
      </interrupt>
      <registers>
        <register>
          <name>CSR</name>
          <addressOffset>0x0</addressOffset>
          <fields>
            <field>
              <name>EN</name>
              <description>COMP1 enable bit</description>
              <bitRange>[0:0]</bitRange>
            </field>
            <field>
              <name>COMP_VSEL</name>
              <description>VREFCMP DIV SOURCE voltage select</description>
              <bitRange>[2:1]</bitRange>
            </field>
            <field>
              <name>INNSEL</name>
              <description>COMP1 negative input select</description>
              <bitRange>[5:3]</bitRange>
            </field>
            <field>
              <name>INPSEL</name>
              <description>COMP1 positive input select</description>
              <bitRange>[9:9]</bitRange>
            </field>
            <field>
              <name>WINMODE</name>
              <description>COMP1 window mode enable</description>
              <bitRange>[11:11]</bitRange>
            </field>
            <field>
              <name>BLANKSEL</name>
              <description>Comparator 1 blanking signal selection</description>
              <bitRange>[14:12]</bitRange>
            </field>
            <field>
              <name>POLARITY</name>
              <description>COMP1 output polarity selection</description>
              <bitRange>[15:15]</bitRange>
            </field>
            <field>
              <name>HYST</name>
              <description>COMP1 hysteresis function enable control</description>
              <bitRange>[16:16]</bitRange>
            </field>
            <field>
              <name>PWRMODE</name>
              <description>COMP1 power mode selection</description>
              <bitRange>[19:18]</bitRange>
            </field>
            <field>
              <name>COMP_VCDIV</name>
              <description>COMP1, COMP2 partial voltage selection</description>
              <bitRange>[25:20]</bitRange>
            </field>
            <field>
              <name>COMP_VCDIV_EN</name>
              <description>VREFCMP voltage divider enable signal</description>
              <bitRange>[26:26]</bitRange>
            </field>
            <field>
              <name>COMP_VCSEL</name>
              <description>VREFCMP reference source selection</description>
              <bitRange>[27:27]</bitRange>
            </field>
            <field>
              <name>TIM_EXTI_OUT_SEL</name>
              <description>COMP1 output to TIM/EXTI selection</description>
              <bitRange>[29:29]</bitRange>
            </field>
            <field>
              <name>COMP1_OUT</name>
              <description>COMP1 output status</description>
              <bitRange>[30:30]</bitRange>
              <access>read-only</access>
            </field>
            <field>
              <name>LOCK</name>
              <description>COMP1_CSR registerlock</description>
              <bitRange>[31:31]</bitRange>
            </field>
          </fields>
        </register>
        <register>
          <name>FR</name>
          <addressOffset>0x4</addressOffset>
          <fields>
            <field>
              <name>FLTEN1</name>
              <description>Comparator 1 digital filter configuration</description>
              <bitRange>[0:0]</bitRange>
            </field>
            <field>
              <name>FLTCNT1</name>
              <description>Comparator 1 sampling filter counter</description>
              <bitRange>[31:16]</bitRange>
            </field>
          </fields>
        </register>
      </registers>
    </peripheral>
    <peripheral derivedFrom="COMP1">
      <name>COMP2</name>
      <baseAddress>0x40016C10</baseAddress>
      <interrupt>
        <name>COMP2</name>
        <description>COMP2 global Interrupt</description>
        <value>74</value>
      </interrupt>
    </peripheral>
    <peripheral derivedFrom="COMP1">
      <name>COMP3</name>
      <baseAddress>0x40016C20</baseAddress>
      <interrupt>
        <name>COMP3</name>
        <description>COMP3 global Interrupt</description>
        <value>75</value>
      </interrupt>
    </peripheral>
    <peripheral derivedFrom="COMP1">
      <name>COMP4</name>
      <baseAddress>0x40016C30</baseAddress>
      <interrupt>
        <name>COMP4</name>
        <description>COMP4 global Interrupt</description>
        <value>76</value>
      </interrupt>
    </peripheral>
    <peripheral>
      <name>CORDIC</name>
      <baseAddress>0x4002C000</baseAddress>
      <addressBlock>
        <offset>0x0</offset>
        <size>0x400</size>
        <usage>registers</usage>
      </addressBlock>
      <interrupt>
        <name>CORDIC</name>
        <description>CORDIC global Interrupt</description>
        <value>71</value>
      </interrupt>
      <registers>
        <register>
          <name>CSR</name>
          <addressOffset>0x0</addressOffset>
          <fields>
            <field>
              <name>FUNC</name>
              <description>Function</description>
              <bitRange>[3:0]</bitRange>
            </field>
            <field>
              <name>PRECISION</name>
              <description>Precision required (number of iterations)</description>
              <bitRange>[7:4]</bitRange>
            </field>
            <field>
              <name>SCALE</name>
              <description>Scaling factor</description>
              <bitRange>[10:8]</bitRange>
            </field>
            <field>
              <name>IEN</name>
              <description>Enable interrupt</description>
              <bitRange>[16:16]</bitRange>
            </field>
            <field>
              <name>DMAREN</name>
              <description>Enable DMA read channel</description>
              <bitRange>[17:17]</bitRange>
            </field>
            <field>
              <name>DMAWEN</name>
              <description>Enable DMA write channel</description>
              <bitRange>[18:18]</bitRange>
            </field>
            <field>
              <name>NRES</name>
              <description>Number of results in the CORDIC_RDATA register</description>
              <bitRange>[19:19]</bitRange>
            </field>
            <field>
              <name>NARGS</name>
              <description>Number of arguments expected by the CORDIC_WDATA register</description>
              <bitRange>[20:20]</bitRange>
            </field>
            <field>
              <name>RESSIZE</name>
              <description>Width of input data</description>
              <bitRange>[21:21]</bitRange>
            </field>
            <field>
              <name>ARGSIZE</name>
              <description>Width of input data</description>
              <bitRange>[22:22]</bitRange>
            </field>
            <field>
              <name>RRDY</name>
              <description>Result ready flag</description>
              <bitRange>[31:31]</bitRange>
              <access>read-only</access>
            </field>
          </fields>
        </register>
        <register>
          <name>WDATA</name>
          <addressOffset>0x4</addressOffset>
          <fields>
            <field>
              <name>ARG</name>
              <description>Function input arguments</description>
              <bitRange>[31:0]</bitRange>
            </field>
          </fields>
        </register>
        <register>
          <name>RDATA</name>
          <addressOffset>0x8</addressOffset>
          <fields>
            <field>
              <name>RES</name>
              <description>Function result</description>
              <bitRange>[31:0]</bitRange>
              <access>read-only</access>
            </field>
          </fields>
        </register>
      </registers>
    </peripheral>
    <peripheral>
      <name>CRC</name>
      <baseAddress>0x40023000</baseAddress>
      <addressBlock>
        <offset>0x0</offset>
        <size>0x400</size>
        <usage>registers</usage>
      </addressBlock>
      <registers>
        <register>
          <name>DR</name>
          <addressOffset>0x0</addressOffset>
          <fields>
            <field>
              <name>DR</name>
              <description>CRC data</description>
              <bitRange>[31:0]</bitRange>
            </field>
          </fields>
        </register>
        <register>
          <name>IDR</name>
          <addressOffset>0x4</addressOffset>
          <fields>
            <field>
              <name>IDR</name>
              <description>CRC independent data</description>
              <bitRange>[31:0]</bitRange>
            </field>
          </fields>
        </register>
        <register>
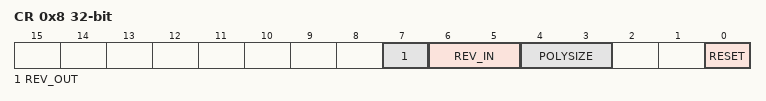
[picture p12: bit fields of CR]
          <name>CR</name>
          <addressOffset>0x8</addressOffset>
          <fields>
            <field>
              <name>RESET</name>
              <description>CRC software reset</description>
              <bitRange>[0:0]</bitRange>
            </field>
            <field>
              <name>POLYSIZE</name>
              <description>Polynomial size</description>
              <bitRange>[4:3]</bitRange>
            </field>
            <field>
              <name>REV_IN</name>
              <description>Reverse input data</description>
              <bitRange>[6:5]</bitRange>
            </field>
            <field>
              <name>REV_OUT</name>
              <description>Reverse output data</description>
              <bitRange>[7:7]</bitRange>
            </field>
          </fields>
        </register>
        <register>
          <name>INIT</name>
          <addressOffset>0x10</addressOffset>
          <fields>
            <field>
              <name>CRC_INIT</name>
              <description>initial value</description>
              <bitRange>[31:0]</bitRange>
            </field>
          </fields>
        </register>
        <register>
          <name>POL</name>
          <addressOffset>0x14</addressOffset>
          <fields>
            <field>
              <name>CRC_POL</name>
              <description>polynomial</description>
              <bitRange>[31:0]</bitRange>
            </field>
          </fields>
        </register>
      </registers>
    </peripheral>
    <peripheral>
      <name>CTC</name>
      <baseAddress>0x4000C800</baseAddress>
      <addressBlock>
        <offset>0x0</offset>
        <size>0x400</size>
        <usage>registers</usage>
      </addressBlock>
      <registers>
        <register>
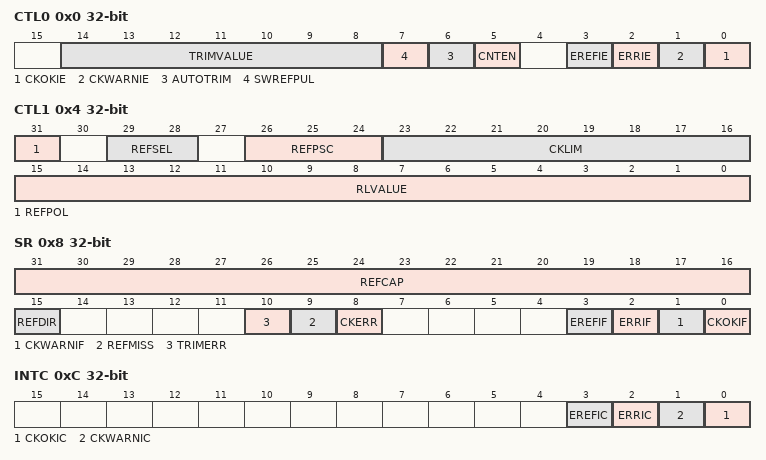
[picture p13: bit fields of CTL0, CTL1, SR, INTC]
          <name>CTL0</name>
          <addressOffset>0x0</addressOffset>
          <fields>
            <field>
              <name>CKOKIE</name>
              <description>Clock calibration completion interrupt enable</description>
              <bitRange>[0:0]</bitRange>
            </field>
            <field>
              <name>CKWARNIE</name>
              <description>Clock calibration warning interrupt enable</description>
              <bitRange>[1:1]</bitRange>
            </field>
            <field>
              <name>ERRIE</name>
              <description>Error interrupt enable</description>
              <bitRange>[2:2]</bitRange>
            </field>
            <field>
              <name>EREFIE</name>
              <description>Expected reference signal interrupt enable</description>
              <bitRange>[3:3]</bitRange>
            </field>
            <field>
              <name>CNTEN</name>
              <description>CTC count enable</description>
              <bitRange>[5:5]</bitRange>
            </field>
            <field>
              <name>AUTOTRIM</name>
              <description>Automatic trim mode</description>
              <bitRange>[6:6]</bitRange>
            </field>
            <field>
              <name>SWREFPUL</name>
              <description>Software generates synchronous reference signal pulses</description>
              <bitRange>[7:7]</bitRange>
            </field>
            <field>
              <name>TRIMVALUE</name>
              <description>Trim Value</description>
              <bitRange>[14:8]</bitRange>
            </field>
          </fields>
        </register>
        <register>
          <name>CTL1</name>
          <addressOffset>0x4</addressOffset>
          <fields>
            <field>
              <name>RLVALUE</name>
              <description>CTC counter reload value</description>
              <bitRange>[15:0]</bitRange>
            </field>
            <field>
              <name>CKLIM</name>
              <description>Clock calibration time base limit</description>
              <bitRange>[23:16]</bitRange>
            </field>
            <field>
              <name>REFPSC</name>
              <description>Reference signal source pre division</description>
              <bitRange>[26:24]</bitRange>
            </field>
            <field>
              <name>REFSEL</name>
              <description>Selection of reference signal source</description>
              <bitRange>[29:28]</bitRange>
            </field>
            <field>
              <name>REFPOL</name>
              <description>Reference signal source polarity</description>
              <bitRange>[31:31]</bitRange>
            </field>
          </fields>
        </register>
        <register>
          <name>SR</name>
          <addressOffset>0x8</addressOffset>
          <fields>
            <field>
              <name>CKOKIF</name>
              <description>Clock calibration successful interrupt flag bit</description>
              <bitRange>[0:0]</bitRange>
              <access>read-only</access>
            </field>
            <field>
              <name>CKWARNIF</name>
              <description>Clock calibration warning interrupt flag bit</description>
              <bitRange>[1:1]</bitRange>
              <access>read-only</access>
            </field>
            <field>
              <name>ERRIF</name>
              <description>Error interrupt flag bit</description>
              <bitRange>[2:2]</bitRange>
              <access>read-only</access>
            </field>
            <field>
              <name>EREFIF</name>
              <description>Expected reference interrupt flag bit</description>
              <bitRange>[3:3]</bitRange>
              <access>read-only</access>
            </field>
            <field>
              <name>CKERR</name>
              <description>Clock calibration error bit</description>
              <bitRange>[8:8]</bitRange>
              <access>read-only</access>
            </field>
            <field>
              <name>REFMISS</name>
              <description>Loss of synchronous reference pulse signal</description>
              <bitRange>[9:9]</bitRange>
              <access>read-only</access>
            </field>
            <field>
              <name>TRIMERR</name>
              <description>Calibration value error bit</description>
              <bitRange>[10:10]</bitRange>
              <access>read-only</access>
            </field>
            <field>
              <name>REFDIR</name>
              <description>CTC calibration clock counting direction</description>
              <bitRange>[15:15]</bitRange>
              <access>read-only</access>
            </field>
            <field>
              <name>REFCAP</name>
              <description>CTC counter capture value</description>
              <bitRange>[31:16]</bitRange>
              <access>read-only</access>
            </field>
          </fields>
        </register>
        <register>
          <name>INTC</name>
          <addressOffset>0xC</addressOffset>
          <fields>
            <field>
              <name>CKOKIC</name>
              <description>CKOKIF interrupt clear bit</description>
              <bitRange>[0:0]</bitRange>
            </field>
            <field>
              <name>CKWARNIC</name>
              <description>CKWARNIF interrupt clear bit</description>
              <bitRange>[1:1]</bitRange>
            </field>
            <field>
              <name>ERRIC</name>
              <description>ERRIF interrupt clear bit</description>
              <bitRange>[2:2]</bitRange>
            </field>
            <field>
              <name>EREFIC</name>
              <description>EREFIF interrupt clear bit</description>
              <bitRange>[3:3]</bitRange>
            </field>
          </fields>
        </register>
      </registers>
    </peripheral>
    <peripheral>
      <name>DAC</name>
      <baseAddress>0x40007400</baseAddress>
      <addressBlock>
        <offset>0x0</offset>
        <size>0x400</size>
        <usage>registers</usage>
      </addressBlock>
      <interrupt>
        <name>DAC</name>
        <description>DAC global Interrupt</description>
        <value>72</value>
      </interrupt>
      <registers>
        <register>
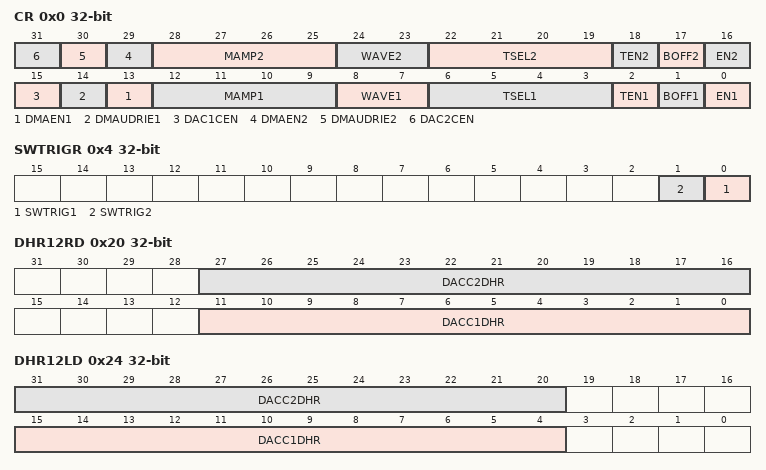
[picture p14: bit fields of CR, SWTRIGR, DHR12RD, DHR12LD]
          <name>CR</name>
          <addressOffset>0x0</addressOffset>
          <fields>
            <field>
              <name>EN1</name>
              <bitRange>[0:0]</bitRange>
            </field>
            <field>
              <name>BOFF1</name>
              <bitRange>[1:1]</bitRange>
            </field>
            <field>
              <name>TEN1</name>
              <bitRange>[2:2]</bitRange>
            </field>
            <field>
              <name>TSEL1</name>
              <bitRange>[6:3]</bitRange>
            </field>
            <field>
              <name>WAVE1</name>
              <bitRange>[8:7]</bitRange>
            </field>
            <field>
              <name>MAMP1</name>
              <bitRange>[12:9]</bitRange>
            </field>
            <field>
              <name>DMAEN1</name>
              <bitRange>[13:13]</bitRange>
            </field>
            <field>
              <name>DMAUDRIE1</name>
              <bitRange>[14:14]</bitRange>
            </field>
            <field>
              <name>DAC1CEN</name>
              <bitRange>[15:15]</bitRange>
            </field>
            <field>
              <name>EN2</name>
              <bitRange>[16:16]</bitRange>
            </field>
            <field>
              <name>BOFF2</name>
              <bitRange>[17:17]</bitRange>
            </field>
            <field>
              <name>TEN2</name>
              <bitRange>[18:18]</bitRange>
            </field>
            <field>
              <name>TSEL2</name>
              <bitRange>[22:19]</bitRange>
            </field>
            <field>
              <name>WAVE2</name>
              <bitRange>[24:23]</bitRange>
            </field>
            <field>
              <name>MAMP2</name>
              <bitRange>[28:25]</bitRange>
            </field>
            <field>
              <name>DMAEN2</name>
              <bitRange>[29:29]</bitRange>
            </field>
            <field>
              <name>DMAUDRIE2</name>
              <bitRange>[30:30]</bitRange>
            </field>
            <field>
              <name>DAC2CEN</name>
              <bitRange>[31:31]</bitRange>
            </field>
          </fields>
        </register>
        <register>
          <name>SWTRIGR</name>
          <addressOffset>0x4</addressOffset>
          <fields>
            <field>
              <name>SWTRIG1</name>
              <bitRange>[0:0]</bitRange>
            </field>
            <field>
              <name>SWTRIG2</name>
              <bitRange>[1:1]</bitRange>
            </field>
          </fields>
        </register>
        <register>
          <name>DHR12R1</name>
          <addressOffset>0x8</addressOffset>
          <fields>
            <field>
              <name>DACC1DHR</name>
              <bitRange>[11:0]</bitRange>
            </field>
          </fields>
        </register>
        <register>
          <name>DHR12L1</name>
          <addressOffset>0xC</addressOffset>
          <fields>
            <field>
              <name>DACC1DHR</name>
              <bitRange>[15:4]</bitRange>
            </field>
          </fields>
        </register>
        <register>
          <name>DHR8R1</name>
          <addressOffset>0x10</addressOffset>
          <fields>
            <field>
              <name>DACC1DHR</name>
              <bitRange>[7:0]</bitRange>
            </field>
          </fields>
        </register>
        <register>
          <name>DHR12R2</name>
          <addressOffset>0x14</addressOffset>
          <fields>
            <field>
              <name>DACC2DHR</name>
              <bitRange>[11:0]</bitRange>
            </field>
          </fields>
        </register>
        <register>
          <name>DHR12L2</name>
          <addressOffset>0x18</addressOffset>
          <fields>
            <field>
              <name>DACC2DHR</name>
              <bitRange>[15:4]</bitRange>
            </field>
          </fields>
        </register>
        <register>
          <name>DHR8R2</name>
          <addressOffset>0x1C</addressOffset>
          <fields>
            <field>
              <name>DACC2DHR</name>
              <bitRange>[7:0]</bitRange>
            </field>
          </fields>
        </register>
        <register>
          <name>DHR12RD</name>
          <addressOffset>0x20</addressOffset>
          <fields>
            <field>
              <name>DACC1DHR</name>
              <bitRange>[11:0]</bitRange>
            </field>
            <field>
              <name>DACC2DHR</name>
              <bitRange>[27:16]</bitRange>
            </field>
          </fields>
        </register>
        <register>
          <name>DHR12LD</name>
          <addressOffset>0x24</addressOffset>
          <fields>
            <field>
              <name>DACC1DHR</name>
              <bitRange>[15:4]</bitRange>
            </field>
            <field>
              <name>DACC2DHR</name>
              <bitRange>[31:20]</bitRange>
            </field>
          </fields>
        </register>
        <register>
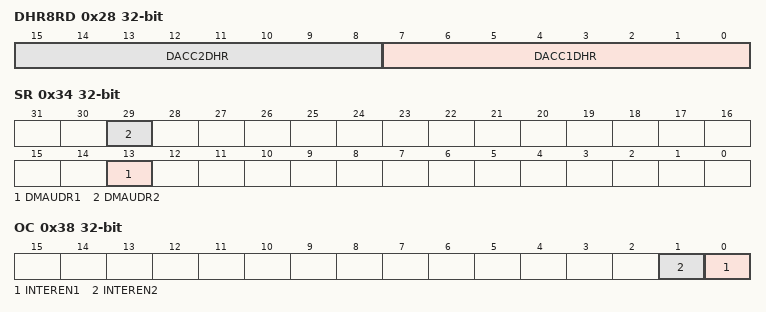
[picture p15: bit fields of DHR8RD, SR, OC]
          <name>DHR8RD</name>
          <addressOffset>0x28</addressOffset>
          <fields>
            <field>
              <name>DACC1DHR</name>
              <bitRange>[7:0]</bitRange>
            </field>
            <field>
              <name>DACC2DHR</name>
              <bitRange>[15:8]</bitRange>
            </field>
          </fields>
        </register>
        <register>
          <name>DOR1</name>
          <addressOffset>0x2C</addressOffset>
          <fields>
            <field>
              <name>DACC1DOR</name>
              <bitRange>[11:0]</bitRange>
            </field>
          </fields>
        </register>
        <register>
          <name>DOR2</name>
          <addressOffset>0x30</addressOffset>
          <fields>
            <field>
              <name>DACC2DOR</name>
              <bitRange>[11:0]</bitRange>
            </field>
          </fields>
        </register>
        <register>
          <name>SR</name>
          <addressOffset>0x34</addressOffset>
          <fields>
            <field>
              <name>DMAUDR1</name>
              <bitRange>[13:13]</bitRange>
            </field>
            <field>
              <name>DMAUDR2</name>
              <bitRange>[29:29]</bitRange>
            </field>
          </fields>
        </register>
        <register>
          <name>OC</name>
          <addressOffset>0x38</addressOffset>
          <fields>
            <field>
              <name>INTEREN1</name>
              <bitRange>[0:0]</bitRange>
            </field>
            <field>
              <name>INTEREN2</name>
              <bitRange>[1:1]</bitRange>
            </field>
          </fields>
        </register>
      </registers>
    </peripheral>
    <peripheral>
      <name>DBG</name>
      <baseAddress>0xE0042000</baseAddress>
      <addressBlock>
        <offset>0x0</offset>
        <size>0x400</size>
        <usage>registers</usage>
      </addressBlock>
      <registers>
        <register><name>IDCODE</name><description>DBGMCU IDCODE</description><addressOffset>0x0</addressOffset><fields><field><name>REV_ID</name><description>REV_ID</description><bitRange>[31:0]</bitRange><access>read-write</access></field></fields></register><register>
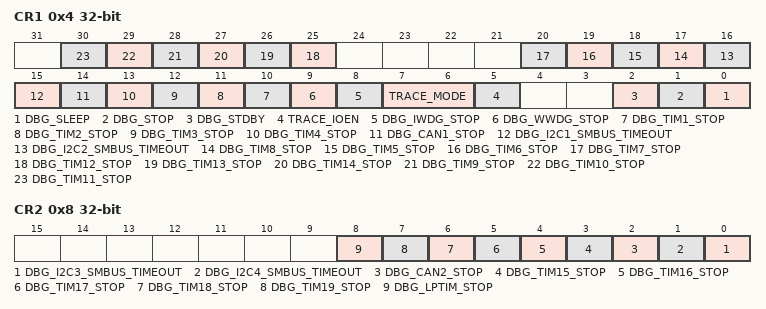
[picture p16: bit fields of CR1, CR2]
          <name>CR1</name>
          <addressOffset>0x4</addressOffset>
          <fields>
            <field>
              <name>DBG_SLEEP</name>
              <bitRange>[0:0]</bitRange>
            </field>
            <field>
              <name>DBG_STOP</name>
              <bitRange>[1:1]</bitRange>
            </field>
            <field>
              <name>DBG_STDBY</name>
              <bitRange>[2:2]</bitRange>
            </field>
            <field>
              <name>TRACE_IOEN</name>
              <bitRange>[5:5]</bitRange>
            </field>
            <field>
              <name>TRACE_MODE</name>
              <bitRange>[7:6]</bitRange>
            </field>
            <field>
              <name>DBG_IWDG_STOP</name>
              <bitRange>[8:8]</bitRange>
            </field>
            <field>
              <name>DBG_WWDG_STOP</name>
              <bitRange>[9:9]</bitRange>
            </field>
            <field>
              <name>DBG_TIM1_STOP</name>
              <bitRange>[10:10]</bitRange>
            </field>
            <field>
              <name>DBG_TIM2_STOP</name>
              <bitRange>[11:11]</bitRange>
            </field>
            <field>
              <name>DBG_TIM3_STOP</name>
              <bitRange>[12:12]</bitRange>
            </field>
            <field>
              <name>DBG_TIM4_STOP</name>
              <bitRange>[13:13]</bitRange>
            </field>
            <field>
              <name>DBG_CAN1_STOP</name>
              <bitRange>[14:14]</bitRange>
            </field>
            <field>
              <name>DBG_I2C1_SMBUS_TIMEOUT</name>
              <bitRange>[15:15]</bitRange>
            </field>
            <field>
              <name>DBG_I2C2_SMBUS_TIMEOUT</name>
              <bitRange>[16:16]</bitRange>
            </field>
            <field>
              <name>DBG_TIM8_STOP</name>
              <bitRange>[17:17]</bitRange>
            </field>
            <field>
              <name>DBG_TIM5_STOP</name>
              <bitRange>[18:18]</bitRange>
            </field>
            <field>
              <name>DBG_TIM6_STOP</name>
              <bitRange>[19:19]</bitRange>
            </field>
            <field>
              <name>DBG_TIM7_STOP</name>
              <bitRange>[20:20]</bitRange>
            </field>
            <field>
              <name>DBG_TIM12_STOP</name>
              <bitRange>[25:25]</bitRange>
            </field>
            <field>
              <name>DBG_TIM13_STOP</name>
              <bitRange>[26:26]</bitRange>
            </field>
            <field>
              <name>DBG_TIM14_STOP</name>
              <bitRange>[27:27]</bitRange>
            </field>
            <field>
              <name>DBG_TIM9_STOP</name>
              <bitRange>[28:28]</bitRange>
            </field>
            <field>
              <name>DBG_TIM10_STOP</name>
              <bitRange>[29:29]</bitRange>
            </field>
            <field>
              <name>DBG_TIM11_STOP</name>
              <bitRange>[30:30]</bitRange>
            </field>
          </fields>
        </register>
        <register>
          <name>CR2</name>
          <addressOffset>0x8</addressOffset>
          <fields>
            <field>
              <name>DBG_I2C3_SMBUS_TIMEOUT</name>
              <bitRange>[0:0]</bitRange>
            </field>
            <field>
              <name>DBG_I2C4_SMBUS_TIMEOUT</name>
              <bitRange>[1:1]</bitRange>
            </field>
            <field>
              <name>DBG_CAN2_STOP</name>
              <bitRange>[2:2]</bitRange>
            </field>
            <field>
              <name>DBG_TIM15_STOP</name>
              <bitRange>[3:3]</bitRange>
            </field>
            <field>
              <name>DBG_TIM16_STOP</name>
              <bitRange>[4:4]</bitRange>
            </field>
            <field>
              <name>DBG_TIM17_STOP</name>
              <bitRange>[5:5]</bitRange>
            </field>
            <field>
              <name>DBG_TIM18_STOP</name>
              <bitRange>[6:6]</bitRange>
            </field>
            <field>
              <name>DBG_TIM19_STOP</name>
              <bitRange>[7:7]</bitRange>
            </field>
            <field>
              <name>DBG_LPTIM_STOP</name>
              <bitRange>[8:8]</bitRange>
            </field>
          </fields>
        </register>
      </registers>
    </peripheral>
    <peripheral>
      <name>DMA1</name>
      <groupName>DMA</groupName>
      <baseAddress>0x40020000</baseAddress>
      <addressBlock>
        <offset>0x0</offset>
        <size>0x400</size>
        <usage>registers</usage>
      </addressBlock>
      <interrupt>
        <name>DMA1_Channel1</name>
        <description>DMA1 channel 1 global interrupt</description>
        <value>11</value>
      </interrupt>
      <interrupt>
        <name>DMA1_Channel2</name>
        <description>DMA1 channel 2 global interrupt</description>
        <value>12</value>
      </interrupt>
      <interrupt>
        <name>DMA1_Channel3</name>
        <description>DMA1 channel 3 global interrupt</description>
        <value>13</value>
      </interrupt>
      <interrupt>
        <name>DMA1_Channel4</name>
        <description>DMA1 channel 4 global interrupt</description>
        <value>14</value>
      </interrupt>
      <interrupt>
        <name>DMA1_Channel5</name>
        <description>DMA1 channel 5 global interrupt</description>
        <value>15</value>
      </interrupt>
      <interrupt>
        <name>DMA1_Channel6</name>
        <description>DMA1 channel 6 global interrupt</description>
        <value>16</value>
      </interrupt>
      <registers>
        <register>
          <name>EN</name>
          <addressOffset>0x0</addressOffset>
          <fields>
            <field>
              <name>DMA_EN</name>
              <description>DMA Enable bit</description>
              <bitRange>[0:0]</bitRange>
            </field>
          </fields>
        </register>
        <register>
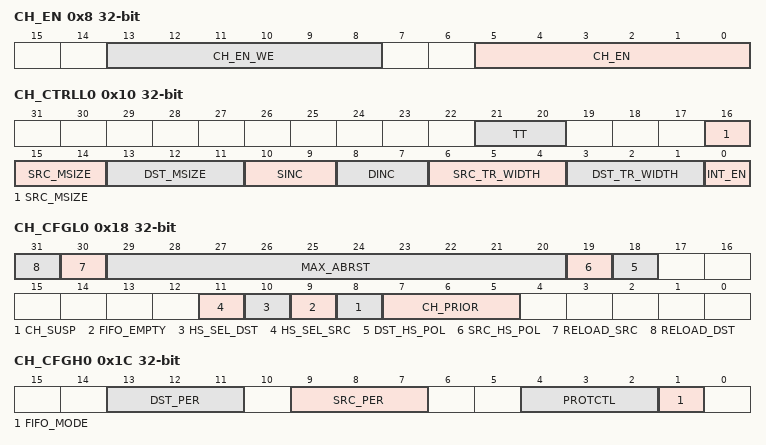
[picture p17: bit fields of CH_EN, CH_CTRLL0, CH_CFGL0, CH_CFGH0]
          <name>CH_EN</name>
          <addressOffset>0x8</addressOffset>
          <fields>
            <field>
              <name>CH_EN</name>
              <description>Channel enable</description>
              <bitRange>[5:0]</bitRange>
            </field>
            <field>
              <name>CH_EN_WE</name>
              <description>Channel enable register</description>
              <bitRange>[13:8]</bitRange>
            </field>
          </fields>
        </register>
        <register>
          <name>CH_CTRLL0</name>
          <addressOffset>0x10</addressOffset>
          <fields>
            <field>
              <name>INT_EN</name>
              <description>Interrupt Enable Bit</description>
              <bitRange>[0:0]</bitRange>
            </field>
            <field>
              <name>DST_TR_WIDTH</name>
              <description>Destination Transfer Width</description>
              <bitRange>[3:1]</bitRange>
            </field>
            <field>
              <name>SRC_TR_WIDTH</name>
              <description>Source Transfer Width</description>
              <bitRange>[6:4]</bitRange>
            </field>
            <field>
              <name>DINC</name>
              <description>Destination Address Increment</description>
              <bitRange>[8:7]</bitRange>
            </field>
            <field>
              <name>SINC</name>
              <description>Source Address Increment</description>
              <bitRange>[10:9]</bitRange>
            </field>
            <field>
              <name>DST_MSIZE</name>
              <description>Destination Burst Transaction Length</description>
              <bitRange>[13:11]</bitRange>
            </field>
            <field>
              <name>SRC_MSIZE</name>
              <description>Source Burst Transaction Length</description>
              <bitRange>[16:14]</bitRange>
            </field>
            <field>
              <name>TT</name>
              <description>Transfer Type</description>
              <bitRange>[21:20]</bitRange>
            </field>
          </fields>
        </register>
        <register>
          <name>CH_CTRLH0</name>
          <addressOffset>0x14</addressOffset>
          <fields>
            <field>
              <name>BLOCK_TS</name>
              <description>Block Transfer Size.</description>
              <bitRange>[11:0]</bitRange>
            </field>
          </fields>
        </register>
        <register>
          <name>CH_CFGL0</name>
          <addressOffset>0x18</addressOffset>
          <fields>
            <field>
              <name>CH_PRIOR</name>
              <description>Channel Priority</description>
              <bitRange>[7:5]</bitRange>
            </field>
            <field>
              <name>CH_SUSP</name>
              <description>Channel Suspend</description>
              <bitRange>[8:8]</bitRange>
            </field>
            <field>
              <name>FIFO_EMPTY</name>
              <description>Channel FIFO status</description>
              <bitRange>[9:9]</bitRange>
              <access>read-only</access>
            </field>
            <field>
              <name>HS_SEL_DST</name>
              <description>Destination Software or Hardware Handshaking Select</description>
              <bitRange>[10:10]</bitRange>
            </field>
            <field>
              <name>HS_SEL_SRC</name>
              <description>Source Software or Hardware Handshaking Select</description>
              <bitRange>[11:11]</bitRange>
            </field>
            <field>
              <name>DST_HS_POL</name>
              <description>Destination Handshaking Interface Polarity</description>
              <bitRange>[18:18]</bitRange>
            </field>
            <field>
              <name>SRC_HS_POL</name>
              <description>Source Handshaking Interface Polarity</description>
              <bitRange>[19:19]</bitRange>
            </field>
            <field>
              <name>MAX_ABRST</name>
              <description>Maximum AMBA Burst Length.</description>
              <bitRange>[29:20]</bitRange>
            </field>
            <field>
              <name>RELOAD_SRC</name>
              <description>Automatic Source Reload</description>
              <bitRange>[30:30]</bitRange>
            </field>
            <field>
              <name>RELOAD_DST</name>
              <description>Automatic Destination Reload</description>
              <bitRange>[31:31]</bitRange>
            </field>
          </fields>
        </register>
        <register>
          <name>CH_CFGH0</name>
          <addressOffset>0x1C</addressOffset>
          <fields>
            <field>
              <name>FIFO_MODE</name>
              <description>FIFO Mode Select</description>
              <bitRange>[1:1]</bitRange>
            </field>
            <field>
              <name>PROTCTL</name>
              <description>Protection Control</description>
              <bitRange>[4:2]</bitRange>
            </field>
            <field>
              <name>SRC_PER</name>
              <description>Source hardware interface</description>
              <bitRange>[9:7]</bitRange>
            </field>
            <field>
              <name>DST_PER</name>
              <description>Destination hardware interface</description>
              <bitRange>[13:11]</bitRange>
            </field>
          </fields>
        </register>
        <register>
          <name>SA0</name>
          <addressOffset>0x20</addressOffset>
          <fields>
            <field>
              <name>SA</name>
              <description>Source Address for Channel 0</description>
              <bitRange>[31:0]</bitRange>
            </field>
          </fields>
        </register>
        <register>
          <name>DA0</name>
          <addressOffset>0x28</addressOffset>
          <fields>
            <field>
              <name>DA</name>
              <description>Destination Address Register for Channel0</description>
              <bitRange>[31:0]</bitRange>
            </field>
          </fields>
        </register>
        <register>
          <name>CH_CTRLL1</name>
          <addressOffset>0x68</addressOffset>
          <fields>
            <field>
              <name>INT_EN</name>
              <description>Interrupt Enable Bit</description>
              <bitRange>[0:0]</bitRange>
            </field>
            <field>
              <name>DST_TR_WIDTH</name>
              <description>Destination Transfer Width</description>
              <bitRange>[3:1]</bitRange>
            </field>
            <field>
              <name>SRC_TR_WIDTH</name>
              <description>Source Transfer Width</description>
              <bitRange>[6:4]</bitRange>
            </field>
            <field>
              <name>DINC</name>
              <description>Destination Address Increment</description>
              <bitRange>[8:7]</bitRange>
            </field>
            <field>
              <name>SINC</name>
              <description>Source Address Increment</description>
              <bitRange>[10:9]</bitRange>
            </field>
            <field>
              <name>DST_MSIZE</name>
              <description>Destination Burst Transaction Length</description>
              <bitRange>[13:11]</bitRange>
            </field>
            <field>
              <name>SRC_MSIZE</name>
              <description>Source Burst Transaction Length</description>
              <bitRange>[16:14]</bitRange>
            </field>
            <field>
              <name>TT</name>
              <description>Transfer Type</description>
              <bitRange>[21:20]</bitRange>
            </field>
          </fields>
        </register>
        <register>
          <name>CH_CTRLH1</name>
          <addressOffset>0x6C</addressOffset>
          <fields>
            <field>
              <name>BLOCK_TS</name>
              <description>Block Transfer Size.</description>
              <bitRange>[11:0]</bitRange>
            </field>
          </fields>
        </register>
        <register>
          <name>CH_CFGL1</name>
          <addressOffset>0x70</addressOffset>
          <fields>
            <field>
              <name>CH_PRIOR</name>
              <description>Channel Priority</description>
              <bitRange>[7:5]</bitRange>
            </field>
            <field>
              <name>CH_SUSP</name>
              <description>Channel Suspend</description>
              <bitRange>[8:8]</bitRange>
            </field>
            <field>
              <name>FIFO_EMPTY</name>
              <description>Channel FIFO status</description>
              <bitRange>[9:9]</bitRange>
              <access>read-only</access>
            </field>
            <field>
              <name>HS_SEL_DST</name>
              <description>Destination Software or Hardware Handshaking Select</description>
              <bitRange>[10:10]</bitRange>
            </field>
            <field>
              <name>HS_SEL_SRC</name>
              <description>Source Software or Hardware Handshaking Select</description>
              <bitRange>[11:11]</bitRange>
            </field>
            <field>
              <name>DST_HS_POL</name>
              <description>Destination Handshaking Interface Polarity</description>
              <bitRange>[18:18]</bitRange>
            </field>
            <field>
              <name>SRC_HS_POL</name>
              <description>Source Handshaking Interface Polarity</description>
              <bitRange>[19:19]</bitRange>
            </field>
            <field>
              <name>MAX_ABRST</name>
              <description>Maximum AMBA Burst Length.</description>
              <bitRange>[29:20]</bitRange>
            </field>
            <field>
              <name>RELOAD_SRC</name>
              <description>Automatic Source Reload</description>
              <bitRange>[30:30]</bitRange>
            </field>
            <field>
              <name>RELOAD_DST</name>
              <description>Automatic Destination Reload</description>
              <bitRange>[31:31]</bitRange>
            </field>
          </fields>
        </register>
        <register>
          <name>CH_CFGH1</name>
          <addressOffset>0x74</addressOffset>
          <fields>
            <field>
              <name>FIFO_MODE</name>
              <description>FIFO Mode Select</description>
              <bitRange>[1:1]</bitRange>
            </field>
            <field>
              <name>PROTCTL</name>
              <description>Protection Control</description>
              <bitRange>[4:2]</bitRange>
            </field>
            <field>
              <name>SRC_PER</name>
              <description>Source hardware interface</description>
              <bitRange>[9:7]</bitRange>
            </field>
            <field>
              <name>DST_PER</name>
              <description>Destination hardware interface</description>
              <bitRange>[13:11]</bitRange>
            </field>
          </fields>
        </register>
        <register>
          <name>SA1</name>
          <addressOffset>0x78</addressOffset>
          <fields>
            <field>
              <name>SA</name>
              <description>Source Address for Channel 0</description>
              <bitRange>[31:0]</bitRange>
            </field>
          </fields>
        </register>
        <register>
          <name>DA1</name>
          <addressOffset>0x80</addressOffset>
          <fields>
            <field>
              <name>DA</name>
              <description>Destination Address Register for Channel0</description>
              <bitRange>[31:0]</bitRange>
            </field>
          </fields>
        </register>
        <register>
          <name>CH_CTRLL2</name>
          <addressOffset>0xC0</addressOffset>
          <fields>
            <field>
              <name>INT_EN</name>
              <description>Interrupt Enable Bit</description>
              <bitRange>[0:0]</bitRange>
            </field>
            <field>
              <name>DST_TR_WIDTH</name>
              <description>Destination Transfer Width</description>
              <bitRange>[3:1]</bitRange>
            </field>
            <field>
              <name>SRC_TR_WIDTH</name>
              <description>Source Transfer Width</description>
              <bitRange>[6:4]</bitRange>
            </field>
            <field>
              <name>DINC</name>
              <description>Destination Address Increment</description>
              <bitRange>[8:7]</bitRange>
            </field>
            <field>
              <name>SINC</name>
              <description>Source Address Increment</description>
              <bitRange>[10:9]</bitRange>
            </field>
            <field>
              <name>DST_MSIZE</name>
              <description>Destination Burst Transaction Length</description>
              <bitRange>[13:11]</bitRange>
            </field>
            <field>
              <name>SRC_MSIZE</name>
              <description>Source Burst Transaction Length</description>
              <bitRange>[16:14]</bitRange>
            </field>
            <field>
              <name>TT</name>
              <description>Transfer Type</description>
              <bitRange>[21:20]</bitRange>
            </field>
          </fields>
        </register>
        <register>
          <name>CH_CTRLH2</name>
          <addressOffset>0xC4</addressOffset>
          <fields>
            <field>
              <name>BLOCK_TS</name>
              <description>Block Transfer Size.</description>
              <bitRange>[11:0]</bitRange>
            </field>
          </fields>
        </register>
        <register>
          <name>CH_CFGL2</name>
          <addressOffset>0xC8</addressOffset>
          <fields>
            <field>
              <name>CH_PRIOR</name>
              <description>Channel Priority</description>
              <bitRange>[7:5]</bitRange>
            </field>
            <field>
              <name>CH_SUSP</name>
              <description>Channel Suspend</description>
              <bitRange>[8:8]</bitRange>
            </field>
            <field>
              <name>FIFO_EMPTY</name>
              <description>Channel FIFO status</description>
              <bitRange>[9:9]</bitRange>
              <access>read-only</access>
            </field>
            <field>
              <name>HS_SEL_DST</name>
              <description>Destination Software or Hardware Handshaking Select</description>
              <bitRange>[10:10]</bitRange>
            </field>
            <field>
              <name>HS_SEL_SRC</name>
              <description>Source Software or Hardware Handshaking Select</description>
              <bitRange>[11:11]</bitRange>
            </field>
            <field>
              <name>DST_HS_POL</name>
              <description>Destination Handshaking Interface Polarity</description>
              <bitRange>[18:18]</bitRange>
            </field>
            <field>
              <name>SRC_HS_POL</name>
              <description>Source Handshaking Interface Polarity</description>
              <bitRange>[19:19]</bitRange>
            </field>
            <field>
              <name>MAX_ABRST</name>
              <description>Maximum AMBA Burst Length.</description>
              <bitRange>[29:20]</bitRange>
            </field>
            <field>
              <name>RELOAD_SRC</name>
              <description>Automatic Source Reload</description>
              <bitRange>[30:30]</bitRange>
            </field>
            <field>
              <name>RELOAD_DST</name>
              <description>Automatic Destination Reload</description>
              <bitRange>[31:31]</bitRange>
            </field>
          </fields>
        </register>
        <register>
          <name>CH_CFGH2</name>
          <addressOffset>0xCC</addressOffset>
          <fields>
            <field>
              <name>FIFO_MODE</name>
              <description>FIFO Mode Select</description>
              <bitRange>[1:1]</bitRange>
            </field>
            <field>
              <name>PROTCTL</name>
              <description>Protection Control</description>
              <bitRange>[4:2]</bitRange>
            </field>
            <field>
              <name>SRC_PER</name>
              <description>Source hardware interface</description>
              <bitRange>[9:7]</bitRange>
            </field>
            <field>
              <name>DST_PER</name>
              <description>Destination hardware interface</description>
              <bitRange>[13:11]</bitRange>
            </field>
          </fields>
        </register>
        <register>
          <name>SA2</name>
          <addressOffset>0xD0</addressOffset>
          <fields>
            <field>
              <name>SA</name>
              <description>Source Address for Channel 0</description>
              <bitRange>[31:0]</bitRange>
            </field>
          </fields>
        </register>
        <register>
          <name>DA2</name>
          <addressOffset>0xD8</addressOffset>
          <fields>
            <field>
              <name>DA</name>
              <description>Destination Address Register for Channel0</description>
              <bitRange>[31:0]</bitRange>
            </field>
          </fields>
        </register>
        <register>
          <name>CH_CTRLL3</name>
          <addressOffset>0x118</addressOffset>
          <fields>
            <field>
              <name>INT_EN</name>
              <description>Interrupt Enable Bit</description>
              <bitRange>[0:0]</bitRange>
            </field>
            <field>
              <name>DST_TR_WIDTH</name>
              <description>Destination Transfer Width</description>
              <bitRange>[3:1]</bitRange>
            </field>
            <field>
              <name>SRC_TR_WIDTH</name>
              <description>Source Transfer Width</description>
              <bitRange>[6:4]</bitRange>
            </field>
            <field>
              <name>DINC</name>
              <description>Destination Address Increment</description>
              <bitRange>[8:7]</bitRange>
            </field>
            <field>
              <name>SINC</name>
              <description>Source Address Increment</description>
              <bitRange>[10:9]</bitRange>
            </field>
            <field>
              <name>DST_MSIZE</name>
              <description>Destination Burst Transaction Length</description>
              <bitRange>[13:11]</bitRange>
            </field>
            <field>
              <name>SRC_MSIZE</name>
              <description>Source Burst Transaction Length</description>
              <bitRange>[16:14]</bitRange>
            </field>
            <field>
              <name>TT</name>
              <description>Transfer Type</description>
              <bitRange>[21:20]</bitRange>
            </field>
          </fields>
        </register>
        <register>
          <name>CH_CTRLH3</name>
          <addressOffset>0x11C</addressOffset>
          <fields>
            <field>
              <name>BLOCK_TS</name>
              <description>Block Transfer Size.</description>
              <bitRange>[11:0]</bitRange>
            </field>
          </fields>
        </register>
        <register>
          <name>CH_CFGL3</name>
          <addressOffset>0x120</addressOffset>
          <fields>
            <field>
              <name>CH_PRIOR</name>
              <description>Channel Priority</description>
              <bitRange>[7:5]</bitRange>
            </field>
            <field>
              <name>CH_SUSP</name>
              <description>Channel Suspend</description>
              <bitRange>[8:8]</bitRange>
            </field>
            <field>
              <name>FIFO_EMPTY</name>
              <description>Channel FIFO status</description>
              <bitRange>[9:9]</bitRange>
              <access>read-only</access>
            </field>
            <field>
              <name>HS_SEL_DST</name>
              <description>Destination Software or Hardware Handshaking Select</description>
              <bitRange>[10:10]</bitRange>
            </field>
            <field>
              <name>HS_SEL_SRC</name>
              <description>Source Software or Hardware Handshaking Select</description>
              <bitRange>[11:11]</bitRange>
            </field>
            <field>
              <name>DST_HS_POL</name>
              <description>Destination Handshaking Interface Polarity</description>
              <bitRange>[18:18]</bitRange>
            </field>
            <field>
              <name>SRC_HS_POL</name>
              <description>Source Handshaking Interface Polarity</description>
              <bitRange>[19:19]</bitRange>
            </field>
            <field>
              <name>MAX_ABRST</name>
              <description>Maximum AMBA Burst Length.</description>
              <bitRange>[29:20]</bitRange>
            </field>
            <field>
              <name>RELOAD_SRC</name>
              <description>Automatic Source Reload</description>
              <bitRange>[30:30]</bitRange>
            </field>
            <field>
              <name>RELOAD_DST</name>
              <description>Automatic Destination Reload</description>
              <bitRange>[31:31]</bitRange>
            </field>
          </fields>
        </register>
        <register>
          <name>CH_CFGH3</name>
          <addressOffset>0x124</addressOffset>
          <fields>
            <field>
              <name>FIFO_MODE</name>
              <description>FIFO Mode Select</description>
              <bitRange>[1:1]</bitRange>
            </field>
            <field>
              <name>PROTCTL</name>
              <description>Protection Control</description>
              <bitRange>[4:2]</bitRange>
            </field>
            <field>
              <name>SRC_PER</name>
              <description>Source hardware interface</description>
              <bitRange>[9:7]</bitRange>
            </field>
            <field>
              <name>DST_PER</name>
              <description>Destination hardware interface</description>
              <bitRange>[13:11]</bitRange>
            </field>
          </fields>
        </register>
        <register>
          <name>SA3</name>
          <addressOffset>0x128</addressOffset>
          <fields>
            <field>
              <name>SA</name>
              <description>Source Address for Channel 0</description>
              <bitRange>[31:0]</bitRange>
            </field>
          </fields>
        </register>
        <register>
          <name>DA3</name>
          <addressOffset>0x130</addressOffset>
          <fields>
            <field>
              <name>DA</name>
              <description>Destination Address Register for Channel0</description>
              <bitRange>[31:0]</bitRange>
            </field>
          </fields>
        </register>
        <register>
          <name>CH_CTRLL4</name>
          <addressOffset>0x170</addressOffset>
          <fields>
            <field>
              <name>INT_EN</name>
              <description>Interrupt Enable Bit</description>
              <bitRange>[0:0]</bitRange>
            </field>
            <field>
              <name>DST_TR_WIDTH</name>
              <description>Destination Transfer Width</description>
              <bitRange>[3:1]</bitRange>
            </field>
            <field>
              <name>SRC_TR_WIDTH</name>
              <description>Source Transfer Width</description>
              <bitRange>[6:4]</bitRange>
            </field>
            <field>
              <name>DINC</name>
              <description>Destination Address Increment</description>
              <bitRange>[8:7]</bitRange>
            </field>
            <field>
              <name>SINC</name>
              <description>Source Address Increment</description>
              <bitRange>[10:9]</bitRange>
            </field>
            <field>
              <name>DST_MSIZE</name>
              <description>Destination Burst Transaction Length</description>
              <bitRange>[13:11]</bitRange>
            </field>
            <field>
              <name>SRC_MSIZE</name>
              <description>Source Burst Transaction Length</description>
              <bitRange>[16:14]</bitRange>
            </field>
            <field>
              <name>TT</name>
              <description>Transfer Type</description>
              <bitRange>[21:20]</bitRange>
            </field>
          </fields>
        </register>
        <register>
          <name>CH_CTRLH4</name>
          <addressOffset>0x174</addressOffset>
          <fields>
            <field>
              <name>BLOCK_TS</name>
              <description>Block Transfer Size.</description>
              <bitRange>[11:0]</bitRange>
            </field>
          </fields>
        </register>
        <register>
          <name>CH_CFGL4</name>
          <addressOffset>0x178</addressOffset>
          <fields>
            <field>
              <name>CH_PRIOR</name>
              <description>Channel Priority</description>
              <bitRange>[7:5]</bitRange>
            </field>
            <field>
              <name>CH_SUSP</name>
              <description>Channel Suspend</description>
              <bitRange>[8:8]</bitRange>
            </field>
            <field>
              <name>FIFO_EMPTY</name>
              <description>Channel FIFO status</description>
              <bitRange>[9:9]</bitRange>
              <access>read-only</access>
            </field>
            <field>
              <name>HS_SEL_DST</name>
              <description>Destination Software or Hardware Handshaking Select</description>
              <bitRange>[10:10]</bitRange>
            </field>
            <field>
              <name>HS_SEL_SRC</name>
              <description>Source Software or Hardware Handshaking Select</description>
              <bitRange>[11:11]</bitRange>
            </field>
            <field>
              <name>DST_HS_POL</name>
              <description>Destination Handshaking Interface Polarity</description>
              <bitRange>[18:18]</bitRange>
            </field>
            <field>
              <name>SRC_HS_POL</name>
              <description>Source Handshaking Interface Polarity</description>
              <bitRange>[19:19]</bitRange>
            </field>
            <field>
              <name>MAX_ABRST</name>
              <description>Maximum AMBA Burst Length.</description>
              <bitRange>[29:20]</bitRange>
            </field>
            <field>
              <name>RELOAD_SRC</name>
              <description>Automatic Source Reload</description>
              <bitRange>[30:30]</bitRange>
            </field>
            <field>
              <name>RELOAD_DST</name>
              <description>Automatic Destination Reload</description>
              <bitRange>[31:31]</bitRange>
            </field>
          </fields>
        </register>
        <register>
          <name>CH_CFGH4</name>
          <addressOffset>0x17C</addressOffset>
          <fields>
            <field>
              <name>FIFO_MODE</name>
              <description>FIFO Mode Select</description>
              <bitRange>[1:1]</bitRange>
            </field>
            <field>
              <name>PROTCTL</name>
              <description>Protection Control</description>
              <bitRange>[4:2]</bitRange>
            </field>
            <field>
              <name>SRC_PER</name>
              <description>Source hardware interface</description>
              <bitRange>[9:7]</bitRange>
            </field>
            <field>
              <name>DST_PER</name>
              <description>Destination hardware interface</description>
              <bitRange>[13:11]</bitRange>
            </field>
          </fields>
        </register>
        <register>
          <name>SA4</name>
          <addressOffset>0x180</addressOffset>
          <fields>
            <field>
              <name>SA</name>
              <description>Source Address for Channel 0</description>
              <bitRange>[31:0]</bitRange>
            </field>
          </fields>
        </register>
        <register>
          <name>DA4</name>
          <addressOffset>0x188</addressOffset>
          <fields>
            <field>
              <name>DA</name>
              <description>Destination Address Register for Channel0</description>
              <bitRange>[31:0]</bitRange>
            </field>
          </fields>
        </register>
        <register>
          <name>CH_CTRLL5</name>
          <addressOffset>0x1C8</addressOffset>
          <fields>
            <field>
              <name>INT_EN</name>
              <description>Interrupt Enable Bit</description>
              <bitRange>[0:0]</bitRange>
            </field>
            <field>
              <name>DST_TR_WIDTH</name>
              <description>Destination Transfer Width</description>
              <bitRange>[3:1]</bitRange>
            </field>
            <field>
              <name>SRC_TR_WIDTH</name>
              <description>Source Transfer Width</description>
              <bitRange>[6:4]</bitRange>
            </field>
            <field>
              <name>DINC</name>
              <description>Destination Address Increment</description>
              <bitRange>[8:7]</bitRange>
            </field>
            <field>
              <name>SINC</name>
              <description>Source Address Increment</description>
              <bitRange>[10:9]</bitRange>
            </field>
            <field>
              <name>DST_MSIZE</name>
              <description>Destination Burst Transaction Length</description>
              <bitRange>[13:11]</bitRange>
            </field>
            <field>
              <name>SRC_MSIZE</name>
              <description>Source Burst Transaction Length</description>
              <bitRange>[16:14]</bitRange>
            </field>
            <field>
              <name>TT</name>
              <description>Transfer Type</description>
              <bitRange>[21:20]</bitRange>
            </field>
          </fields>
        </register>
        <register>
          <name>CH_CTRLH5</name>
          <addressOffset>0x1CC</addressOffset>
          <fields>
            <field>
              <name>BLOCK_TS</name>
              <description>Block Transfer Size.</description>
              <bitRange>[11:0]</bitRange>
            </field>
          </fields>
        </register>
        <register>
          <name>CH_CFGL5</name>
          <addressOffset>0x1D0</addressOffset>
          <fields>
            <field>
              <name>CH_PRIOR</name>
              <description>Channel Priority</description>
              <bitRange>[7:5]</bitRange>
            </field>
            <field>
              <name>CH_SUSP</name>
              <description>Channel Suspend</description>
              <bitRange>[8:8]</bitRange>
            </field>
            <field>
              <name>FIFO_EMPTY</name>
              <description>Channel FIFO status</description>
              <bitRange>[9:9]</bitRange>
              <access>read-only</access>
            </field>
            <field>
              <name>HS_SEL_DST</name>
              <description>Destination Software or Hardware Handshaking Select</description>
              <bitRange>[10:10]</bitRange>
            </field>
            <field>
              <name>HS_SEL_SRC</name>
              <description>Source Software or Hardware Handshaking Select</description>
              <bitRange>[11:11]</bitRange>
            </field>
            <field>
              <name>DST_HS_POL</name>
              <description>Destination Handshaking Interface Polarity</description>
              <bitRange>[18:18]</bitRange>
            </field>
            <field>
              <name>SRC_HS_POL</name>
              <description>Source Handshaking Interface Polarity</description>
              <bitRange>[19:19]</bitRange>
            </field>
            <field>
              <name>MAX_ABRST</name>
              <description>Maximum AMBA Burst Length.</description>
              <bitRange>[29:20]</bitRange>
            </field>
            <field>
              <name>RELOAD_SRC</name>
              <description>Automatic Source Reload</description>
              <bitRange>[30:30]</bitRange>
            </field>
            <field>
              <name>RELOAD_DST</name>
              <description>Automatic Destination Reload</description>
              <bitRange>[31:31]</bitRange>
            </field>
          </fields>
        </register>
        <register>
          <name>CH_CFGH5</name>
          <addressOffset>0x1D4</addressOffset>
          <fields>
            <field>
              <name>FIFO_MODE</name>
              <description>FIFO Mode Select</description>
              <bitRange>[1:1]</bitRange>
            </field>
            <field>
              <name>PROTCTL</name>
              <description>Protection Control</description>
              <bitRange>[4:2]</bitRange>
            </field>
            <field>
              <name>SRC_PER</name>
              <description>Source hardware interface</description>
              <bitRange>[9:7]</bitRange>
            </field>
            <field>
              <name>DST_PER</name>
              <description>Destination hardware interface</description>
              <bitRange>[13:11]</bitRange>
            </field>
          </fields>
        </register>
        <register>
          <name>SA5</name>
          <addressOffset>0x1D8</addressOffset>
          <fields>
            <field>
              <name>SA</name>
              <description>Source Address for Channel 0</description>
              <bitRange>[31:0]</bitRange>
            </field>
          </fields>
        </register>
        <register>
          <name>DA5</name>
          <addressOffset>0x1E0</addressOffset>
          <fields>
            <field>
              <name>DA</name>
              <description>Destination Address Register for Channel0</description>
              <bitRange>[31:0]</bitRange>
            </field>
          </fields>
        </register>
        <register>
          <name>RAWHALFBLOCK</name>
          <addressOffset>0x2A0</addressOffset>
          <fields>
            <field>
              <name>RAW</name>
              <description>Raw Status for IntHalfBlock Interrupt</description>
              <bitRange>[5:0]</bitRange>
            </field>
          </fields>
        </register>
        <register>
          <name>STATUSHALFBLOCK</name>
          <addressOffset>0x2A8</addressOffset>
          <fields>
            <field>
              <name>STATUS</name>
              <description>Status for IntHalfBlock Interrupt</description>
              <bitRange>[5:0]</bitRange>
              <access>read-only</access>
            </field>
          </fields>
        </register>
        <register>
          <name>MASKHALFBLOCK</name>
          <addressOffset>0x2B0</addressOffset>
          <fields>
            <field>
              <name>INT_MASK</name>
              <description>Mask for IntHalfBlock Interrupt</description>
              <bitRange>[5:0]</bitRange>
            </field>
            <field>
              <name>INT_MASK_WE</name>
              <description>Interrupt Mask Write Enable</description>
              <bitRange>[13:8]</bitRange>
            </field>
          </fields>
        </register>
        <register>
          <name>CLEARHALFBLOCK</name>
          <addressOffset>0x2B8</addressOffset>
          <fields>
            <field>
              <name>CLEAR</name>
              <description>Clear for IntHalfBlock Interrupt</description>
              <bitRange>[5:0]</bitRange>
            </field>
          </fields>
        </register>
        <register>
          <name>RAWTFR</name>
          <addressOffset>0x2C0</addressOffset>
          <fields>
            <field>
              <name>RAW</name>
              <description>Raw Status for IntTfr Interrupt</description>
              <bitRange>[5:0]</bitRange>
            </field>
          </fields>
        </register>
        <register>
          <name>RAWBLOCK</name>
          <addressOffset>0x2C8</addressOffset>
          <fields>
            <field>
              <name>RAW</name>
              <description>Raw Status for IntBlock Interrupt</description>
              <bitRange>[5:0]</bitRange>
            </field>
          </fields>
        </register>
        <register>
          <name>RAWSRCTRAN</name>
          <addressOffset>0x2D0</addressOffset>
          <fields>
            <field>
              <name>RAW</name>
              <description>Raw Status for IntSrcTran Interrupt</description>
              <bitRange>[5:0]</bitRange>
            </field>
          </fields>
        </register>
        <register>
          <name>RAWDSTTRAN</name>
          <addressOffset>0x2D8</addressOffset>
          <fields>
            <field>
              <name>RAW</name>
              <description>Raw Status for IntDstTran Interrupt</description>
              <bitRange>[5:0]</bitRange>
            </field>
          </fields>
        </register>
        <register>
          <name>RAWERR</name>
          <addressOffset>0x2E0</addressOffset>
          <fields>
            <field>
              <name>RAW</name>
              <description>Raw Status for IntErr Interrupt</description>
              <bitRange>[5:0]</bitRange>
            </field>
          </fields>
        </register>
        <register>
          <name>STATUSTFR</name>
          <addressOffset>0x2E8</addressOffset>
          <fields>
            <field>
              <name>STATUS</name>
              <description>Status for IntTfr Interrupt</description>
              <bitRange>[5:0]</bitRange>
              <access>read-only</access>
            </field>
          </fields>
        </register>
        <register>
          <name>STATUSBLOCK</name>
          <addressOffset>0x2F0</addressOffset>
          <fields>
            <field>
              <name>STATUS</name>
              <description>Status for IntBlock Interrupt</description>
              <bitRange>[5:0]</bitRange>
              <access>read-only</access>
            </field>
          </fields>
        </register>
        <register>
          <name>STATUSSRCTRAN</name>
          <addressOffset>0x2F8</addressOffset>
          <fields>
            <field>
              <name>STATUS</name>
              <description>Status for IntSrcTran Interrupt</description>
              <bitRange>[5:0]</bitRange>
              <access>read-only</access>
            </field>
          </fields>
        </register>
        <register>
          <name>STATUSDSTTRAN</name>
          <addressOffset>0x300</addressOffset>
          <fields>
            <field>
              <name>STATUS</name>
              <description>Status for IntDstTran Interrupt</description>
              <bitRange>[5:0]</bitRange>
              <access>read-only</access>
            </field>
          </fields>
        </register>
        <register>
          <name>STATUSERR</name>
          <addressOffset>0x308</addressOffset>
          <fields>
            <field>
              <name>STATUS</name>
              <description>Status for IntErr Interrupt</description>
              <bitRange>[5:0]</bitRange>
              <access>read-only</access>
            </field>
          </fields>
        </register>
        <register>
          <name>MASKTFR</name>
          <addressOffset>0x310</addressOffset>
          <fields>
            <field>
              <name>INT_MASK</name>
              <description>Mask for IntTfr Interrupt</description>
              <bitRange>[5:0]</bitRange>
            </field>
            <field>
              <name>INT_MASK_WE</name>
              <description>Interrupt Mask Write Enable</description>
              <bitRange>[13:8]</bitRange>
            </field>
          </fields>
        </register>
        <register>
          <name>MASKBLOCK</name>
          <addressOffset>0x318</addressOffset>
          <fields>
            <field>
              <name>INT_MASK</name>
              <description>Mask for IntBlock Interrupt</description>
              <bitRange>[5:0]</bitRange>
            </field>
            <field>
              <name>INT_MASK_WE</name>
              <description>Interrupt Mask Write Enable</description>
              <bitRange>[13:8]</bitRange>
            </field>
          </fields>
        </register>
        <register>
          <name>MASKSRCTRAN</name>
          <addressOffset>0x320</addressOffset>
          <fields>
            <field>
              <name>INT_MASK</name>
              <description>Mask for IntSrcTran Interrupt</description>
              <bitRange>[5:0]</bitRange>
            </field>
            <field>
              <name>INT_MASK_WE</name>
              <description>Interrupt Mask Write Enable</description>
              <bitRange>[13:8]</bitRange>
            </field>
          </fields>
        </register>
        <register>
          <name>MASKDSTTRAN</name>
          <addressOffset>0x328</addressOffset>
          <fields>
            <field>
              <name>INT_MASK</name>
              <description>Mask for IntDstTran Interrupt</description>
              <bitRange>[5:0]</bitRange>
            </field>
            <field>
              <name>INT_MASK_WE</name>
              <description>Interrupt Mask Write Enable</description>
              <bitRange>[13:8]</bitRange>
            </field>
          </fields>
        </register>
        <register>
          <name>MASKERR</name>
          <addressOffset>0x330</addressOffset>
          <fields>
            <field>
              <name>INT_MASK</name>
              <description>Mask for IntErr Interrupt</description>
              <bitRange>[5:0]</bitRange>
            </field>
            <field>
              <name>INT_MASK_WE</name>
              <description>Interrupt Mask Write Enable</description>
              <bitRange>[13:8]</bitRange>
            </field>
          </fields>
        </register>
        <register>
          <name>CLEARTFR</name>
          <addressOffset>0x338</addressOffset>
          <fields>
            <field>
              <name>CLEAR</name>
              <description>Clear for IntTfr Interrupt</description>
              <bitRange>[5:0]</bitRange>
            </field>
          </fields>
        </register>
        <register>
          <name>CLEARBLOCK</name>
          <addressOffset>0x340</addressOffset>
          <fields>
            <field>
              <name>CLEAR</name>
              <description>Clear for IntBlock Interrupt</description>
              <bitRange>[5:0]</bitRange>
            </field>
          </fields>
        </register>
        <register>
          <name>CLEARSRCTRAN</name>
          <addressOffset>0x348</addressOffset>
          <fields>
            <field>
              <name>CLEAR</name>
              <description>Clear for IntSrcTran Interrupt</description>
              <bitRange>[5:0]</bitRange>
            </field>
          </fields>
        </register>
        <register>
          <name>CLEARDSTTRAN</name>
          <addressOffset>0x350</addressOffset>
          <fields>
            <field>
              <name>CLEAR</name>
              <description>Clear for IntDstTran Interrupt</description>
              <bitRange>[5:0]</bitRange>
            </field>
          </fields>
        </register>
        <register>
          <name>CLEARERR</name>
          <addressOffset>0x358</addressOffset>
          <fields>
            <field>
              <name>CLEAR</name>
              <description>Clear for IntErr Interrupt</description>
              <bitRange>[5:0]</bitRange>
            </field>
          </fields>
        </register>
        <register>
          <name>STATUSINT</name>
          <addressOffset>0x360</addressOffset>
          <fields>
            <field>
              <name>TFR</name>
              <description>OR of the contents of StatusTfr</description>
              <bitRange>[0:0]</bitRange>
              <access>read-only</access>
            </field>
            <field>
              <name>BLOCK</name>
              <description>OR of the contents of StatusBlock</description>
              <bitRange>[1:1]</bitRange>
              <access>read-only</access>
            </field>
            <field>
              <name>SRCT</name>
              <description>OR of the contents of StatusSrcTran</description>
              <bitRange>[2:2]</bitRange>
              <access>read-only</access>
            </field>
            <field>
              <name>DSTT</name>
              <description>OR of the contents of StatusDstTran</description>
              <bitRange>[3:3]</bitRange>
              <access>read-only</access>
            </field>
            <field>
              <name>ERR</name>
              <description>OR of the contents of StatusErr</description>
              <bitRange>[4:4]</bitRange>
              <access>read-only</access>
            </field>
            <field>
              <name>HALFBLOCK</name>
              <description>OR of the contents of StatusHalfBlock</description>
              <bitRange>[5:5]</bitRange>
              <access>read-only</access>
            </field>
          </fields>
        </register>
        <register>
          <name>REQSRC</name>
          <addressOffset>0x368</addressOffset>
          <fields>
            <field>
              <name>SRC_REQ</name>
              <description>Source Software Transaction Request</description>
              <bitRange>[5:0]</bitRange>
            </field>
            <field>
              <name>SRC_REQ_WE</name>
              <description>Source Software Transaction Request write enable</description>
              <bitRange>[13:8]</bitRange>
            </field>
          </fields>
        </register>
        <register>
          <name>REQDST</name>
          <addressOffset>0x370</addressOffset>
          <fields>
            <field>
              <name>DST_REQ</name>
              <description>Destination Software Transaction Request</description>
              <bitRange>[5:0]</bitRange>
            </field>
            <field>
              <name>DST_REQ_WE</name>
              <description>Destination Software Transaction Request write enable</description>
              <bitRange>[13:8]</bitRange>
            </field>
          </fields>
        </register>
        <register>
          <name>SGLRQSRC</name>
          <addressOffset>0x378</addressOffset>
          <fields>
            <field>
              <name>SRC_SGLREQ</name>
              <description>Source Single Transaction Request</description>
              <bitRange>[5:0]</bitRange>
            </field>
            <field>
              <name>SRC_SGLREQ_WE</name>
              <description>Source Single Transaction Request write enable</description>
              <bitRange>[13:8]</bitRange>
            </field>
          </fields>
        </register>
        <register>
          <name>SGLRQDST</name>
          <addressOffset>0x380</addressOffset>
          <fields>
            <field>
              <name>DST_SGLREQ</name>
              <description>Destination Single Transaction Request</description>
              <bitRange>[5:0]</bitRange>
            </field>
            <field>
              <name>DST_SGLREQ_WE</name>
              <description>Destination Single Transaction Request write enable</description>
              <bitRange>[13:8]</bitRange>
            </field>
          </fields>
        </register>
      </registers>
    </peripheral>
    <peripheral derivedFrom="DMA1">
      <name>DMA2</name>
      <baseAddress>0x40020400</baseAddress>
      <interrupt>
        <name>DMA2_Channel6</name>
        <description>DMA2 channel 6 global interrupt</description>
        <value>17</value>
      </interrupt>
      <interrupt>
        <name>DMA2_Channel1</name>
        <description>DMA2 channel 1 global interrupt</description>
        <value>56</value>
      </interrupt>
      <interrupt>
        <name>DMA2_Channel2</name>
        <description>DMA2 channel 2 global interrupt</description>
        <value>57</value>
      </interrupt>
      <interrupt>
        <name>DMA2_Channel3</name>
        <description>DMA2 channel 3 global interrupt</description>
        <value>58</value>
      </interrupt>
      <interrupt>
        <name>DMA2_Channel4_5</name>
        <description>DMA2 channel 4_5 global interrupt</description>
        <value>59</value>
      </interrupt>
    </peripheral>
    <peripheral>
      <name>ESMC</name>
      <baseAddress>0xA0001000</baseAddress>
      <addressBlock>
        <offset>0x0</offset>
        <size>0x400</size>
        <usage>registers</usage>
      </addressBlock>
      <interrupt>
        <name>ESMC</name>
        <description>ESMC global interrupt</description>
        <value>48</value>
      </interrupt>
      <registers>
        <register>
          <name>CR</name>
          <addressOffset>0x0</addressOffset>
          <size>8</size>
          <fields>
            <field>
              <name>SOFTRST</name>
              <description>Software Reset</description>
              <bitRange>[0:0]</bitRange>
            </field>
            <field>
              <name>2QSPI</name>
              <description>Dual Flash Mode</description>
              <bitRange>[2:2]</bitRange>
            </field>
            <field>
              <name>DMAEN</name>
              <description>dma en</description>
              <bitRange>[3:3]</bitRange>
            </field>
            <field>
              <name>GIE</name>
              <description>globle interrupt enable</description>
              <bitRange>[4:4]</bitRange>
            </field>
            <field>
              <name>XIPEN</name>
              <description>xip mode en</description>
              <bitRange>[6:6]</bitRange>
            </field>
            <field>
              <name>SPIEN</name>
              <description>spi en</description>
              <bitRange>[7:7]</bitRange>
            </field>
          </fields>
        </register>
        <register>
          <name>CR2</name>
          <addressOffset>0x1</addressOffset>
          <size>8</size>
          <fields>
            <field>
              <name>CPHA</name>
              <description>clock phase</description>
              <bitRange>[0:0]</bitRange>
            </field>
            <field>
              <name>CPOL</name>
              <description>clock polarity</description>
              <bitRange>[1:1]</bitRange>
            </field>
            <field>
              <name>TXFIFO_CLR</name>
              <description>txfifo clear</description>
              <bitRange>[3:3]</bitRange>
            </field>
            <field>
              <name>RXFIFO_CLR</name>
              <description>rxfifo clear</description>
              <bitRange>[4:4]</bitRange>
            </field>
            <field>
              <name>XSPI_DUAL_LAT_OFF</name>
              <description>xspi dual latency off enable</description>
              <bitRange>[7:7]</bitRange>
            </field>
          </fields>
        </register>
        <register>
          <name>TCR</name>
          <addressOffset>0x2</addressOffset>
          <size>8</size>
          <fields>
            <field>
              <name>HOLD</name>
              <description>setup/hold time</description>
              <bitRange>[3:0]</bitRange>
            </field>
            <field>
              <name>HIGH</name>
              <description>high time</description>
              <bitRange>[7:4]</bitRange>
            </field>
          </fields>
        </register>
        <register>
          <name>BAUD</name>
          <addressOffset>0x3</addressOffset>
          <size>8</size>
          <fields>
            <field>
              <name>BAUD</name>
              <description>baud set</description>
              <bitRange>[7:0]</bitRange>
            </field>
          </fields>
        </register>
        <register>
          <name>SFCR</name>
          <addressOffset>0x4</addressOffset>
          <size>8</size>
          <fields>
            <field>
              <name>SFCR0</name>
              <description>Command Only</description>
              <bitRange>[7:0]</bitRange>
            </field>
          </fields>
        </register>
        <register>
          <name>SOCR</name>
          <addressOffset>0x5</addressOffset>
          <size>8</size>
          <fields>
            <field>
              <name>SPIMODE</name>
              <description>spi mode</description>
              <bitRange>[1:0]</bitRange>
            </field>
            <field>
              <name>SENM</name>
              <description>send mode enable</description>
              <bitRange>[2:2]</bitRange>
            </field>
            <field>
              <name>MULTICMD</name>
              <description>muti command</description>
              <bitRange>[3:3]</bitRange>
            </field>
            <field>
              <name>MULTIADDR</name>
              <description>muti address</description>
              <bitRange>[4:4]</bitRange>
            </field>
            <field>
              <name>DDRCMD</name>
              <description>ddr command</description>
              <bitRange>[5:5]</bitRange>
            </field>
            <field>
              <name>DDRADDR</name>
              <description>ddr address</description>
              <bitRange>[6:6]</bitRange>
            </field>
            <field>
              <name>DDRDATA</name>
              <description>ddr data</description>
              <bitRange>[7:7]</bitRange>
            </field>
          </fields>
        </register>
        <register>
          <name>DCR</name>
          <addressOffset>0x6</addressOffset>
          <size>8</size>
          <fields>
            <field>
              <name>DUMMY</name>
              <description>dummy cycyle set</description>
              <bitRange>[5:0]</bitRange>
            </field>
            <field>
              <name>NO_CMD</name>
              <description>no command</description>
              <bitRange>[6:6]</bitRange>
            </field>
            <field>
              <name>REC</name>
              <description>receive enable</description>
              <bitRange>[7:7]</bitRange>
            </field>
          </fields>
        </register>
        <register>
          <name>CR3</name>
          <addressOffset>0x7</addressOffset>
          <size>8</size>
          <fields>
            <field>
              <name>ADDR8BIT</name>
              <description>8bit address</description>
              <bitRange>[0:0]</bitRange>
            </field>
            <field>
              <name>ADDR16BIT</name>
              <description>16bit address</description>
              <bitRange>[1:1]</bitRange>
            </field>
            <field>
              <name>ADDR32BIT</name>
              <description>32bit address</description>
              <bitRange>[2:2]</bitRange>
            </field>
            <field>
              <name>NO_ADDR</name>
              <description>no address enable</description>
              <bitRange>[3:3]</bitRange>
            </field>
            <field>
              <name>XSPI_RWDS</name>
              <description>xSPI RWDS enable</description>
              <bitRange>[4:4]</bitRange>
            </field>
            <field>
              <name>CMD_EXT</name>
              <description>command extend enable</description>
              <bitRange>[5:5]</bitRange>
            </field>
            <field>
              <name>NO_DATA</name>
              <description>no data enable</description>
              <bitRange>[7:7]</bitRange>
            </field>
          </fields>
        </register>
        <register>
          <name>ADDR24</name>
          <addressOffset>0x8</addressOffset>
          <fields>
            <field>
              <name>INS1</name>
              <description>command1</description>
              <bitRange>[7:0]</bitRange>
            </field>
            <field>
              <name>ADDR0</name>
              <description>address0</description>
              <bitRange>[15:8]</bitRange>
            </field>
            <field>
              <name>ADDR1</name>
              <description>address1</description>
              <bitRange>[23:16]</bitRange>
            </field>
            <field>
              <name>ADDR2</name>
              <description>address2</description>
              <bitRange>[31:24]</bitRange>
            </field>
          </fields>
        </register>
        <register>
          <name>ADDR32</name>
          <addressOffset>0xC</addressOffset>
          <fields>
            <field>
              <name>ADDR3</name>
              <description>address3</description>
              <bitRange>[7:0]</bitRange>
            </field>
            <field>
              <name>MREG</name>
              <description>Mode register</description>
              <bitRange>[15:8]</bitRange>
            </field>
            <field>
              <name>SSXO</name>
              <description>Slave select enable</description>
              <bitRange>[21:16]</bitRange>
            </field>
            <field>
              <name>SS_CLR</name>
              <description>Slave select clear</description>
              <bitRange>[22:22]</bitRange>
            </field>
            <field>
              <name>SS_SET</name>
              <description>Slave select set</description>
              <bitRange>[23:23]</bitRange>
            </field>
          </fields>
        </register>
        <register>
          <name>DATA</name>
          <addressOffset>0x10</addressOffset>
          <fields>
            <field>
              <name>DATA0</name>
              <description>data0</description>
              <bitRange>[7:0]</bitRange>
            </field>
            <field>
              <name>DATA1</name>
              <description>data1</description>
              <bitRange>[15:8]</bitRange>
            </field>
            <field>
              <name>DATA2</name>
              <description>data2</description>
              <bitRange>[23:16]</bitRange>
            </field>
            <field>
              <name>DATA3</name>
              <description>data3</description>
              <bitRange>[31:24]</bitRange>
            </field>
          </fields>
        </register>
        <register>
          <name>SR</name>
          <addressOffset>0x14</addressOffset>
          <size>8</size>
          <fields>
            <field>
              <name>SSACTIVE</name>
              <description>slave select active</description>
              <bitRange>[0:0]</bitRange>
              <access>read-only</access>
            </field>
            <field>
              <name>RXBUSY</name>
              <description>rx busy state</description>
              <bitRange>[1:1]</bitRange>
              <access>read-only</access>
            </field>
            <field>
              <name>TXBUSY</name>
              <description>tx busy state</description>
              <bitRange>[2:2]</bitRange>
              <access>read-only</access>
            </field>
            <field>
              <name>XIPBUSY</name>
              <description>xip busy state</description>
              <bitRange>[3:3]</bitRange>
              <access>read-only</access>
            </field>
            <field>
              <name>IDLE_STATE</name>
              <description>idle state</description>
              <bitRange>[4:4]</bitRange>
              <access>read-only</access>
            </field>
            <field>
              <name>TXFIFOOV</name>
              <description>txfifo overflow state</description>
              <bitRange>[5:5]</bitRange>
              <access>read-only</access>
            </field>
            <field>
              <name>DATAWAIT</name>
              <description>data wait</description>
              <bitRange>[6:6]</bitRange>
              <access>read-only</access>
            </field>
            <field>
              <name>SPIF</name>
              <description>spi interrupt flag</description>
              <bitRange>[7:7]</bitRange>
              <access>read-only</access>
            </field>
          </fields>
        </register>
        <register>
          <name>SR1</name>
          <addressOffset>0x15</addressOffset>
          <size>8</size>
          <fields>
            <field>
              <name>RWDSI_ND</name>
              <description>rwdsi not detect</description>
              <bitRange>[0:0]</bitRange>
              <access>read-only</access>
            </field>
            <field>
              <name>XSPI_DUAL_LATENCY</name>
              <description>xspi dual latency flag</description>
              <bitRange>[1:1]</bitRange>
            </field>
          </fields>
        </register>
        <register>
          <name>RXSTAT</name>
          <addressOffset>0x16</addressOffset>
          <size>8</size>
          <fields>
            <field>
              <name>RXSTAT</name>
              <description>rx state</description>
              <bitRange>[7:0]</bitRange>
              <access>read-only</access>
            </field>
          </fields>
        </register>
        <register>
          <name>IFR1</name>
          <addressOffset>0x18</addressOffset>
          <size>8</size>
          <fields>
            <field>
              <name>CMDIF</name>
              <description>command done interrupt flag</description>
              <bitRange>[0:0]</bitRange>
            </field>
            <field>
              <name>RXFIFONEIF</name>
              <description>rxfifo not empty interrupt flag</description>
              <bitRange>[1:1]</bitRange>
              <access>read-only</access>
            </field>
            <field>
              <name>RXFIFOHFIF</name>
              <description>rxfifo half full interrupt flag</description>
              <bitRange>[2:2]</bitRange>
              <access>read-only</access>
            </field>
            <field>
              <name>RXFIFOFIF</name>
              <description>rxfifo full interrupt flag</description>
              <bitRange>[3:3]</bitRange>
              <access>read-only</access>
            </field>
            <field>
              <name>IDLEDONEIF</name>
              <description>idle interrupt flag</description>
              <bitRange>[4:4]</bitRange>
              <access>read-only</access>
            </field>
            <field>
              <name>DATAWAITIF</name>
              <description>data wait interrupt flag</description>
              <bitRange>[5:5]</bitRange>
              <access>read-only</access>
            </field>
            <field>
              <name>RXFIFOWIF</name>
              <description>rx fifo word interrupt flag</description>
              <bitRange>[6:6]</bitRange>
              <access>read-only</access>
            </field>
            <field>
              <name>ADDRDONEIF</name>
              <description>address done interrupt flag</description>
              <bitRange>[7:7]</bitRange>
            </field>
          </fields>
        </register>
        <register>
          <name>IER1</name>
          <addressOffset>0x19</addressOffset>
          <size>8</size>
          <fields>
            <field>
              <name>CMDIE</name>
              <description>command done interrupt enable</description>
              <bitRange>[0:0]</bitRange>
            </field>
            <field>
              <name>RXFIFONEIE</name>
              <description>rx fifo not empty interrupt enable</description>
              <bitRange>[1:1]</bitRange>
            </field>
            <field>
              <name>RXFIFOHFIE</name>
              <description>rx fifo half interrupt enable</description>
              <bitRange>[2:2]</bitRange>
            </field>
            <field>
              <name>RXFIFOFIE</name>
              <description>rx fifo full interrupt enable</description>
              <bitRange>[3:3]</bitRange>
            </field>
            <field>
              <name>IDLEDONEIE</name>
              <description>idle interrupt enable</description>
              <bitRange>[4:4]</bitRange>
            </field>
            <field>
              <name>DATAWAITIE</name>
              <description>busy interrupt enable</description>
              <bitRange>[5:5]</bitRange>
            </field>
            <field>
              <name>RXFIFOWIE</name>
              <description>rx fifo word interrupt enable</description>
              <bitRange>[6:6]</bitRange>
            </field>
            <field>
              <name>ADDRDONEIE</name>
              <description>address done interrupt enable</description>
              <bitRange>[7:7]</bitRange>
            </field>
          </fields>
        </register>
        <register>
          <name>IFR2</name>
          <addressOffset>0x1A</addressOffset>
          <size>8</size>
          <fields>
            <field>
              <name>XIPRDINSTRSETIF</name>
              <description>xip read instr set interrupt flag</description>
              <bitRange>[0:0]</bitRange>
              <access>read-only</access>
            </field>
            <field>
              <name>TXFIFOEIF</name>
              <description>tx fifo empty interrupt flag</description>
              <bitRange>[1:1]</bitRange>
              <access>read-only</access>
            </field>
            <field>
              <name>TXFIFOHEIF</name>
              <description>tx fifo half empty interrupt flag</description>
              <bitRange>[2:2]</bitRange>
              <access>read-only</access>
            </field>
            <field>
              <name>TXFIFOFIF</name>
              <description>tx fifo full interrupt flag</description>
              <bitRange>[3:3]</bitRange>
              <access>read-only</access>
            </field>
            <field>
              <name>TXFIFOOVIF</name>
              <description>tx fifo overflow interrupt flag</description>
              <bitRange>[4:4]</bitRange>
              <access>read-only</access>
            </field>
            <field>
              <name>TXWORDOVIF</name>
              <description>txfifo word interrupt flag</description>
              <bitRange>[5:5]</bitRange>
            </field>
            <field>
              <name>XIPWEINSTRSETIF</name>
              <description>xip write instr set interrupt flag</description>
              <bitRange>[6:6]</bitRange>
              <access>read-only</access>
            </field>
            <field>
              <name>RXTOUTIF</name>
              <description>rx timeout interrupt flag</description>
              <bitRange>[7:7]</bitRange>
              <access>read-only</access>
            </field>
          </fields>
        </register>
        <register>
          <name>IER2</name>
          <addressOffset>0x1B</addressOffset>
          <size>8</size>
          <fields>
            <field>
              <name>TXFIFOEIE</name>
              <description>tx fifo empty interrupt enable</description>
              <bitRange>[1:1]</bitRange>
            </field>
            <field>
              <name>TXFIFOHEIE</name>
              <description>tx fifo half full interrupt enable</description>
              <bitRange>[2:2]</bitRange>
            </field>
            <field>
              <name>TXFIFOFIE</name>
              <description>tx fifo full interrupt enable</description>
              <bitRange>[3:3]</bitRange>
            </field>
            <field>
              <name>TXFIFOOVIE</name>
              <description>tx fifo overflow interrupt enable</description>
              <bitRange>[4:4]</bitRange>
            </field>
            <field>
              <name>TXWORDOVIE</name>
              <description>txfifo word interrupt enable</description>
              <bitRange>[5:5]</bitRange>
            </field>
          </fields>
        </register>
        <register>
          <name>STRR</name>
          <addressOffset>0x1C</addressOffset>
          <size>8</size>
          <fields>
            <field>
              <name>SMP</name>
              <description>sample</description>
              <bitRange>[5:0]</bitRange>
            </field>
          </fields>
        </register>
        <register>
          <name>XSFCR</name>
          <addressOffset>0x20</addressOffset>
          <size>8</size>
          <fields>
            <field>
              <name>XINS</name>
              <description>XIP read command</description>
              <bitRange>[7:0]</bitRange>
            </field>
          </fields>
        </register>
        <register>
          <name>XSOCR</name>
          <addressOffset>0x21</addressOffset>
          <size>8</size>
          <fields>
            <field>
              <name>SPI_MODE</name>
              <description>xip read spi mode</description>
              <bitRange>[1:0]</bitRange>
            </field>
            <field>
              <name>SEND_M</name>
              <description>xip read send mode enable</description>
              <bitRange>[2:2]</bitRange>
            </field>
            <field>
              <name>MULTICMD</name>
              <description>xip read muti command</description>
              <bitRange>[3:3]</bitRange>
            </field>
            <field>
              <name>MULTIADDR</name>
              <description>xip read muti address</description>
              <bitRange>[4:4]</bitRange>
            </field>
            <field>
              <name>DDRCMD</name>
              <description>xip read ddr command</description>
              <bitRange>[5:5]</bitRange>
            </field>
            <field>
              <name>DDRADDR</name>
              <description>xip read ddr address</description>
              <bitRange>[6:6]</bitRange>
            </field>
            <field>
              <name>DDRDATA</name>
              <description>xip read ddr data</description>
              <bitRange>[7:7]</bitRange>
            </field>
          </fields>
        </register>
        <register>
          <name>XDCR</name>
          <addressOffset>0x22</addressOffset>
          <size>8</size>
          <fields>
            <field>
              <name>XDUMMY</name>
              <description>xip read dummy cycle set</description>
              <bitRange>[5:0]</bitRange>
            </field>
            <field>
              <name>NO_CMD</name>
              <description>xip read no command</description>
              <bitRange>[6:6]</bitRange>
            </field>
          </fields>
        </register>
        <register>
          <name>XCR3</name>
          <addressOffset>0x23</addressOffset>
          <size>8</size>
          <fields>
            <field>
              <name>ADDR8BIT</name>
              <description>xip read 8bit address</description>
              <bitRange>[0:0]</bitRange>
            </field>
            <field>
              <name>ADDR16BIT</name>
              <description>xip read 16bit address</description>
              <bitRange>[1:1]</bitRange>
            </field>
            <field>
              <name>ADDR32BIT</name>
              <description>xip read 32bit address</description>
              <bitRange>[2:2]</bitRange>
            </field>
            <field>
              <name>NO_ADDR</name>
              <description>xip read no address enable</description>
              <bitRange>[3:3]</bitRange>
            </field>
            <field>
              <name>XSPI_RWDS</name>
              <description>xip read xSPI RWDS enable</description>
              <bitRange>[4:4]</bitRange>
            </field>
            <field>
              <name>CMD_EXT</name>
              <description>xip read command extend enable</description>
              <bitRange>[5:5]</bitRange>
            </field>
          </fields>
        </register>
        <register>
          <name>XMODE</name>
          <addressOffset>0x24</addressOffset>
          <size>8</size>
          <fields>
            <field>
              <name>XMODE</name>
              <description>xip send modereg</description>
              <bitRange>[7:0]</bitRange>
            </field>
          </fields>
        </register>
        <register>
          <name>XMODE_WE</name>
          <addressOffset>0x25</addressOffset>
          <size>8</size>
          <fields>
            <field>
              <name>XMODE_WE</name>
              <description>xip send modereg_we</description>
              <bitRange>[7:0]</bitRange>
            </field>
          </fields>
        </register>
        <register>
          <name>XSSOCR</name>
          <addressOffset>0x26</addressOffset>
          <size>8</size>
          <fields>
            <field>
              <name>SSXO</name>
              <description>xip read Slave select enable</description>
              <bitRange>[5:0]</bitRange>
            </field>
            <field>
              <name>SS_CLR_RQ</name>
              <description>xip read Slave select clear</description>
              <bitRange>[6:6]</bitRange>
            </field>
          </fields>
        </register>
        <register>
          <name>XSSOCR_WE</name>
          <addressOffset>0x27</addressOffset>
          <size>8</size>
          <fields>
            <field>
              <name>SSXO</name>
              <description>xip write Slave select enable</description>
              <bitRange>[5:0]</bitRange>
            </field>
            <field>
              <name>SS_CLR_RQ</name>
              <description>xip write Slave select clear</description>
              <bitRange>[6:6]</bitRange>
            </field>
          </fields>
        </register>
        <register>
          <name>XSFCR_WE</name>
          <addressOffset>0x28</addressOffset>
          <size>8</size>
          <fields>
            <field>
              <name>XINS_WE</name>
              <description>XIP write command</description>
              <bitRange>[7:0]</bitRange>
            </field>
          </fields>
        </register>
        <register>
          <name>XSOCR_WE</name>
          <addressOffset>0x29</addressOffset>
          <size>8</size>
          <fields>
            <field>
              <name>SPI_MODE</name>
              <description>xip write spi mode</description>
              <bitRange>[1:0]</bitRange>
            </field>
            <field>
              <name>SEND_M</name>
              <description>xip write send mode enable</description>
              <bitRange>[2:2]</bitRange>
            </field>
            <field>
              <name>MULTICMD</name>
              <description>xip write muti command</description>
              <bitRange>[3:3]</bitRange>
            </field>
            <field>
              <name>MULTIADDR</name>
              <description>xip write muti address</description>
              <bitRange>[4:4]</bitRange>
            </field>
            <field>
              <name>DDRCMD</name>
              <description>xip write ddr command</description>
              <bitRange>[5:5]</bitRange>
            </field>
            <field>
              <name>DDRADDR</name>
              <description>xip write ddr address</description>
              <bitRange>[6:6]</bitRange>
            </field>
            <field>
              <name>DDRDATA</name>
              <description>xip write ddr data</description>
              <bitRange>[7:7]</bitRange>
            </field>
          </fields>
        </register>
        <register>
          <name>XDCR_WE</name>
          <addressOffset>0x2A</addressOffset>
          <size>8</size>
          <fields>
            <field>
              <name>XDUMMY</name>
              <description>xip write dummy cycle set</description>
              <bitRange>[5:0]</bitRange>
            </field>
            <field>
              <name>NO_CMD</name>
              <description>xip write no command</description>
              <bitRange>[6:6]</bitRange>
            </field>
          </fields>
        </register>
        <register>
          <name>XCR3_WE</name>
          <addressOffset>0x2B</addressOffset>
          <size>8</size>
          <fields>
            <field>
              <name>ADDR8BIT</name>
              <description>xip write 8bit address</description>
              <bitRange>[0:0]</bitRange>
            </field>
            <field>
              <name>ADDR16BIT</name>
              <description>xip write 16bit address</description>
              <bitRange>[1:1]</bitRange>
            </field>
            <field>
              <name>ADDR32BIT</name>
              <description>xip write 32bit address</description>
              <bitRange>[2:2]</bitRange>
            </field>
            <field>
              <name>NO_ADDR</name>
              <description>xip write no address enable</description>
              <bitRange>[3:3]</bitRange>
            </field>
            <field>
              <name>XSPI_RWDS</name>
              <description>xip write xSPI RWDS enable</description>
              <bitRange>[4:4]</bitRange>
            </field>
            <field>
              <name>CMD_EXT</name>
              <description>xip write command extend enable</description>
              <bitRange>[5:5]</bitRange>
            </field>
          </fields>
        </register>
        <register>
          <name>BCR</name>
          <addressOffset>0x2C</addressOffset>
          <fields>
            <field>
              <name>BCR</name>
              <description>bit control register</description>
              <bitRange>[31:0]</bitRange>
            </field>
          </fields>
        </register>
        <register>
          <name>RXTOUT</name>
          <addressOffset>0x30</addressOffset>
          <size>8</size>
          <fields>
            <field>
              <name>RXTOUT</name>
              <description>rx timeout</description>
              <bitRange>[7:0]</bitRange>
            </field>
          </fields>
        </register>
        <register>
          <name>XSTRR</name>
          <addressOffset>0x31</addressOffset>
          <size>8</size>
          <fields>
            <field>
              <name>XSMP</name>
              <description>xip sample sample</description>
              <bitRange>[5:0]</bitRange>
            </field>
          </fields>
        </register>
      </registers>
    </peripheral>
    <peripheral>
      <name>ETHERNET_DMA</name>
      <description>Ethernet: DMA controller operation</description>
      <baseAddress>0x480C1000</baseAddress>
      <addressBlock>
        <offset>0x0</offset>
        <size>0x400</size>
        <usage>registers</usage>
      </addressBlock>
      <registers>
        <register>
          <name>DMABMR</name>
          <description>Ethernet DMA bus mode register</description>
          <addressOffset>0x0</addressOffset>
          <fields>
            <field>
              <name>SR</name>
              <description>Software reset</description>
              <bitRange>[0:0]</bitRange>
            </field>
            <field>
              <name>DA</name>
              <description>DMA Arbitration</description>
              <bitRange>[1:1]</bitRange>
            </field>
            <field>
              <name>DSL</name>
              <description>Descriptor skip length</description>
              <bitRange>[6:2]</bitRange>
            </field>
            <field>
              <name>PBL</name>
              <description>Programmable burst length</description>
              <bitRange>[13:8]</bitRange>
            </field>
            <field>
              <name>RTPR</name>
              <description>Rx Tx priority ratio</description>
              <bitRange>[15:14]</bitRange>
            </field>
            <field>
              <name>FB</name>
              <description>Fixed burst</description>
              <bitRange>[16:16]</bitRange>
            </field>
            <field>
              <name>RDP</name>
              <description>Rx DMA PBL</description>
              <bitRange>[22:17]</bitRange>
            </field>
            <field>
              <name>USP</name>
              <description>Use separate PBL</description>
              <bitRange>[23:23]</bitRange>
            </field>
            <field>
              <name>FPM</name>
              <description>4xPBL mode</description>
              <bitRange>[24:24]</bitRange>
            </field>
            <field>
              <name>AAB</name>
              <description>Address-aligned beats</description>
              <bitRange>[25:25]</bitRange>
            </field>
          </fields>
        </register>
        <register>
          <name>DMATPDR</name>
          <description>Ethernet DMA transmit poll demand register</description>
          <addressOffset>0x4</addressOffset>
          <fields>
            <field>
              <name>TPD</name>
              <description>Transmit poll demand</description>
              <bitRange>[31:0]</bitRange>
            </field>
          </fields>
        </register>
        <register>
          <name>DMARPDR</name>
          <description>EHERNET DMA receive poll demand register</description>
          <addressOffset>0x8</addressOffset>
          <fields>
            <field>
              <name>RPD</name>
              <description>Receive poll demand</description>
              <bitRange>[31:0]</bitRange>
            </field>
          </fields>
        </register>
        <register>
          <name>DMARDLAR</name>
          <description>Ethernet DMA receive descriptor list address register</description>
          <addressOffset>0xC</addressOffset>
          <fields>
            <field>
              <name>SRL</name>
              <description>Start of receive list</description>
              <bitRange>[31:0]</bitRange>
            </field>
          </fields>
        </register>
        <register>
          <name>DMATDLAR</name>
          <description>Ethernet DMA transmit descriptor list address register</description>
          <addressOffset>0x10</addressOffset>
          <fields>
            <field>
              <name>STL</name>
              <description>Start of transmit list</description>
              <bitRange>[31:0]</bitRange>
            </field>
          </fields>
        </register>
        <register>
          <name>DMASR</name>
          <description>Ethernet DMA status register</description>
          <addressOffset>0x14</addressOffset>
          <fields>
            <field>
              <name>TS</name>
              <description>Transmit status</description>
              <bitRange>[0:0]</bitRange>
            </field>
            <field>
              <name>TPSS</name>
              <description>Transmit process stopped status</description>
              <bitRange>[1:1]</bitRange>
            </field>
            <field>
              <name>TBUS</name>
              <description>Transmit buffer unavailable status</description>
              <bitRange>[2:2]</bitRange>
            </field>
            <field>
              <name>TJTS</name>
              <description>Transmit jabber timeout status</description>
              <bitRange>[3:3]</bitRange>
            </field>
            <field>
              <name>ROS</name>
              <description>Receive overflow status</description>
              <bitRange>[4:4]</bitRange>
            </field>
            <field>
              <name>TUS</name>
              <description>Transmit underflow status</description>
              <bitRange>[5:5]</bitRange>
            </field>
            <field>
              <name>RS</name>
              <description>Receive status</description>
              <bitRange>[6:6]</bitRange>
            </field>
            <field>
              <name>RBUS</name>
              <description>Receive buffer unavailable status</description>
              <bitRange>[7:7]</bitRange>
            </field>
            <field>
              <name>RPSS</name>
              <description>Receive process stopped status</description>
              <bitRange>[8:8]</bitRange>
            </field>
            <field>
              <name>PWTS</name>
              <description>Receive watchdog timeout status</description>
              <bitRange>[9:9]</bitRange>
            </field>
            <field>
              <name>ETS</name>
              <description>Early transmit status</description>
              <bitRange>[10:10]</bitRange>
            </field>
            <field>
              <name>FBES</name>
              <description>Fatal bus error status</description>
              <bitRange>[13:13]</bitRange>
            </field>
            <field>
              <name>ERS</name>
              <description>Early receive status</description>
              <bitRange>[14:14]</bitRange>
            </field>
            <field>
              <name>AIS</name>
              <description>Abnormal interrupt summary</description>
              <bitRange>[15:15]</bitRange>
            </field>
            <field>
              <name>NIS</name>
              <description>Normal interrupt summary</description>
              <bitRange>[16:16]</bitRange>
            </field>
            <field>
              <name>RPS</name>
              <description>Receive process state</description>
              <bitRange>[19:17]</bitRange>
              <access>read-only</access>
            </field>
            <field>
              <name>TPS</name>
              <description>Transmit process state</description>
              <bitRange>[22:20]</bitRange>
              <access>read-only</access>
            </field>
            <field>
              <name>EBS</name>
              <description>Error bits status</description>
              <bitRange>[25:23]</bitRange>
              <access>read-only</access>
            </field>
            <field>
              <name>MMCS</name>
              <description>MMC status</description>
              <bitRange>[27:27]</bitRange>
              <access>read-only</access>
            </field>
            <field>
              <name>PMTS</name>
              <description>PMT status</description>
              <bitRange>[28:28]</bitRange>
              <access>read-only</access>
            </field>
            <field>
              <name>TSTS</name>
              <description>Time stamp trigger status</description>
              <bitRange>[29:29]</bitRange>
              <access>read-only</access>
            </field>
          </fields>
        </register>
        <register>
          <name>DMAOMR</name>
          <description>Ethernet DMA operation mode register</description>
          <addressOffset>0x18</addressOffset>
          <fields>
            <field>
              <name>SR</name>
              <description>SR</description>
              <bitRange>[1:1]</bitRange>
            </field>
            <field>
              <name>OSF</name>
              <description>OSF</description>
              <bitRange>[2:2]</bitRange>
            </field>
            <field>
              <name>RTC</name>
              <description>RTC</description>
              <bitRange>[4:3]</bitRange>
            </field>
            <field>
              <name>FUGF</name>
              <description>FUGF</description>
              <bitRange>[6:6]</bitRange>
            </field>
            <field>
              <name>FEF</name>
              <description>FEF</description>
              <bitRange>[7:7]</bitRange>
            </field>
            <field>
              <name>ST</name>
              <description>ST</description>
              <bitRange>[13:13]</bitRange>
            </field>
            <field>
              <name>TTC</name>
              <description>TTC</description>
              <bitRange>[16:14]</bitRange>
            </field>
            <field>
              <name>FTF</name>
              <description>FTF</description>
              <bitRange>[20:20]</bitRange>
            </field>
            <field>
              <name>TSF</name>
              <description>TSF</description>
              <bitRange>[21:21]</bitRange>
            </field>
            <field>
              <name>DFRF</name>
              <description>DFRF</description>
              <bitRange>[24:24]</bitRange>
            </field>
            <field>
              <name>RSF</name>
              <description>RSF</description>
              <bitRange>[25:25]</bitRange>
            </field>
            <field>
              <name>DTCEFD</name>
              <description>DTCEFD</description>
              <bitRange>[26:26]</bitRange>
            </field>
          </fields>
        </register>
        <register>
          <name>DMAIER</name>
          <description>Ethernet DMA interrupt enable register</description>
          <addressOffset>0x1C</addressOffset>
          <fields>
            <field>
              <name>TIE</name>
              <description>Transmit interrupt enable</description>
              <bitRange>[0:0]</bitRange>
            </field>
            <field>
              <name>TPSIE</name>
              <description>Transmit process stopped interrupt enable</description>
              <bitRange>[1:1]</bitRange>
            </field>
            <field>
              <name>TBUIE</name>
              <description>Transmit buffer unavailable interrupt enable</description>
              <bitRange>[2:2]</bitRange>
            </field>
            <field>
              <name>TJTIE</name>
              <description>Transmit jabber timeout interrupt enable</description>
              <bitRange>[3:3]</bitRange>
            </field>
            <field>
              <name>ROIE</name>
              <description>Overflow interrupt enable</description>
              <bitRange>[4:4]</bitRange>
            </field>
            <field>
              <name>TUIE</name>
              <description>Underflow interrupt enable</description>
              <bitRange>[5:5]</bitRange>
            </field>
            <field>
              <name>RIE</name>
              <description>Receive interrupt enable</description>
              <bitRange>[6:6]</bitRange>
            </field>
            <field>
              <name>RBUIE</name>
              <description>Receive buffer unavailable interrupt enable</description>
              <bitRange>[7:7]</bitRange>
            </field>
            <field>
              <name>RPSIE</name>
              <description>Receive process stopped interrupt enable</description>
              <bitRange>[8:8]</bitRange>
            </field>
            <field>
              <name>RWTIE</name>
              <description>receive watchdog timeout interrupt enable</description>
              <bitRange>[9:9]</bitRange>
            </field>
            <field>
              <name>ETIE</name>
              <description>Early transmit interrupt enable</description>
              <bitRange>[10:10]</bitRange>
            </field>
            <field>
              <name>FBEIE</name>
              <description>Fatal bus error interrupt enable</description>
              <bitRange>[13:13]</bitRange>
            </field>
            <field>
              <name>ERIE</name>
              <description>Early receive interrupt enable</description>
              <bitRange>[14:14]</bitRange>
            </field>
            <field>
              <name>AISE</name>
              <description>Abnormal interrupt summary enable</description>
              <bitRange>[15:15]</bitRange>
            </field>
            <field>
              <name>NISE</name>
              <description>Normal interrupt summary enable</description>
              <bitRange>[16:16]</bitRange>
            </field>
          </fields>
        </register>
        <register>
          <name>DMAMFBOCR</name>
          <description>Ethernet DMA missed frame and buffer overflow counter register</description>
          <addressOffset>0x20</addressOffset>
          <fields>
            <field>
              <name>MFC</name>
              <description>Missed frames by the controller</description>
              <bitRange>[15:0]</bitRange>
              <access>read-only</access>
            </field>
            <field>
              <name>OMFC</name>
              <description>Overflow bit for missed frame counter</description>
              <bitRange>[16:16]</bitRange>
              <access>read-only</access>
            </field>
            <field>
              <name>MFA</name>
              <description>Missed frames by the application</description>
              <bitRange>[27:17]</bitRange>
              <access>read-only</access>
            </field>
            <field>
              <name>OFOC</name>
              <description>Overflow bit for FIFO overflow counter</description>
              <bitRange>[28:28]</bitRange>
              <access>read-only</access>
            </field>
          </fields>
        </register>
        <register><name>DMARIWT</name><description>ETH DMA receive interrupt watchdog timer</description><addressOffset>0x24</addressOffset><fields><field><name>RIWT</name><description>RIWT</description><bitRange>[7:0]</bitRange><access>read-write</access></field></fields></register><register>
          <name>DMACHTDR</name>
          <description>Ethernet DMA current host transmit descriptor register</description>
          <addressOffset>0x48</addressOffset>
          <fields>
            <field>
              <name>HTDAP</name>
              <description>Host transmit descriptor address pointer</description>
              <bitRange>[31:0]</bitRange>
              <access>read-only</access>
            </field>
          </fields>
        </register>
        <register>
          <name>DMACHRDR</name>
          <description>Ethernet DMA current host receive descriptor register</description>
          <addressOffset>0x4C</addressOffset>
          <fields>
            <field>
              <name>HRDAP</name>
              <description>Host receive descriptor address pointer</description>
              <bitRange>[31:0]</bitRange>
              <access>read-only</access>
            </field>
          </fields>
        </register>
        <register>
          <name>DMACHTBAR</name>
          <description>Ethernet DMA current host transmit buffer address register</description>
          <addressOffset>0x50</addressOffset>
          <fields>
            <field>
              <name>HTBAP</name>
              <description>Host transmit buffer address pointer</description>
              <bitRange>[31:0]</bitRange>
              <access>read-only</access>
            </field>
          </fields>
        </register>
        <register>
          <name>DMACHRBAR</name>
          <description>Ethernet DMA current host receive buffer address register</description>
          <addressOffset>0x54</addressOffset>
          <fields>
            <field>
              <name>HRBAP</name>
              <description>Host receive buffer address pointer</description>
              <bitRange>[31:0]</bitRange>
              <access>read-only</access>
            </field>
          </fields>
        </register>
      </registers>
    </peripheral>
    <peripheral>
      <name>ETHERNET_MAC</name>
      <description>Ethernet: media access control</description>
      <baseAddress>0x480C0000</baseAddress>
      <addressBlock>
        <offset>0x0</offset>
        <size>0x100</size>
        <usage>registers</usage>
      </addressBlock>
      <interrupt>
        <name>ETH</name>
        <description>Ethernet global interrupt</description>
        <value>67</value>
      </interrupt>
      <interrupt>
        <name>ETH_WKUP</name>
        <description>Ethernet Wakeup through EXTI line
        interrupt</description>
        <value>68</value>
      </interrupt>
      <registers>
        <register>
          <name>MACCR</name>
          <description>Ethernet MAC configuration register (ETH_MACCR)</description>
          <addressOffset>0x0</addressOffset>
          <fields>
            <field>
              <name>RE</name>
              <description>Receiver enable</description>
              <bitRange>[2:2]</bitRange>
            </field>
            <field>
              <name>TE</name>
              <description>Transmitter enable</description>
              <bitRange>[3:3]</bitRange>
            </field>
            <field>
              <name>DC</name>
              <description>Deferral check</description>
              <bitRange>[4:4]</bitRange>
            </field>
            <field>
              <name>BL</name>
              <description>Back-off limit</description>
              <bitRange>[6:5]</bitRange>
            </field>
            <field>
              <name>APCS</name>
              <description>Automatic pad/CRC stripping</description>
              <bitRange>[7:7]</bitRange>
            </field>
            <field>
              <name>RD</name>
              <description>Retry disable</description>
              <bitRange>[9:9]</bitRange>
            </field>
            <field>
              <name>IPCO</name>
              <description>IPv4 checksum offload</description>
              <bitRange>[10:10]</bitRange>
            </field>
            <field>
              <name>DM</name>
              <description>Duplex mode</description>
              <bitRange>[11:11]</bitRange>
            </field>
            <field>
              <name>LM</name>
              <description>Loopback mode</description>
              <bitRange>[12:12]</bitRange>
            </field>
            <field>
              <name>ROD</name>
              <description>Receive own disable</description>
              <bitRange>[13:13]</bitRange>
            </field>
            <field>
              <name>FES</name>
              <description>Fast Ethernet speed</description>
              <bitRange>[14:14]</bitRange>
            </field>
            <field>
              <name>CSD</name>
              <description>Carrier sense disable</description>
              <bitRange>[16:16]</bitRange>
            </field>
            <field>
              <name>IFG</name>
              <description>Interframe gap</description>
              <bitRange>[19:17]</bitRange>
            </field>
            <field>
              <name>JD</name>
              <description>Jabber disable</description>
              <bitRange>[22:22]</bitRange>
            </field>
            <field>
              <name>WD</name>
              <description>Watchdog disable</description>
              <bitRange>[23:23]</bitRange>
            </field>
          </fields>
        </register>
        <register>
          <name>MACFFR</name>
          <description>Ethernet MAC frame filter register (ETH_MACCFFR)</description>
          <addressOffset>0x4</addressOffset>
          <fields>
            <field>
              <name>PM</name>
              <description>Promiscuous mode</description>
              <bitRange>[0:0]</bitRange>
            </field>
            <field>
              <name>HU</name>
              <description>Hash unicast</description>
              <bitRange>[1:1]</bitRange>
            </field>
            <field>
              <name>HM</name>
              <description>Hash multicast</description>
              <bitRange>[2:2]</bitRange>
            </field>
            <field>
              <name>DAIF</name>
              <description>Destination address inverse filtering</description>
              <bitRange>[3:3]</bitRange>
            </field>
            <field>
              <name>PAM</name>
              <description>Pass all multicast</description>
              <bitRange>[4:4]</bitRange>
            </field>
            <field>
              <name>BFD</name>
              <description>Broadcast frames disable</description>
              <bitRange>[5:5]</bitRange>
            </field>
            <field>
              <name>PCF</name>
              <description>Pass control frames</description>
              <bitRange>[7:6]</bitRange>
            </field>
            <field>
              <name>SAIF</name>
              <description>Source address inverse filtering</description>
              <bitRange>[8:8]</bitRange>
            </field>
            <field>
              <name>SAF</name>
              <description>Source address filter</description>
              <bitRange>[9:9]</bitRange>
            </field>
            <field>
              <name>HPF</name>
              <description>Hash or perfect filter</description>
              <bitRange>[10:10]</bitRange>
            </field>
            <field>
              <name>RA</name>
              <description>Receive all</description>
              <bitRange>[31:31]</bitRange>
            </field>
          <field><name>VTFE</name><description>VTFE</description><bitRange>[16:16]</bitRange><access>read-write</access></field></fields>
        </register>
        <register>
          <name>MACHTHR</name>
          <description>Ethernet MAC hash table high register</description>
          <addressOffset>0x8</addressOffset>
          <fields>
            <field>
              <name>HTH</name>
              <description>Hash table high</description>
              <bitRange>[31:0]</bitRange>
            </field>
          </fields>
        </register>
        <register>
          <name>MACHTLR</name>
          <description>Ethernet MAC hash table low register</description>
          <addressOffset>0xC</addressOffset>
          <fields>
            <field>
              <name>HTL</name>
              <description>Hash table low</description>
              <bitRange>[31:0]</bitRange>
            </field>
          </fields>
        </register>
        <register>
          <name>MACMIIAR</name>
          <description>Ethernet MAC MII address register (ETH_MACMIIAR)</description>
          <addressOffset>0x10</addressOffset>
          <fields>
            <field>
              <name>MB</name>
              <description>MII busy</description>
              <bitRange>[0:0]</bitRange>
            </field>
            <field>
              <name>MW</name>
              <description>MII write</description>
              <bitRange>[1:1]</bitRange>
            </field>
            <field>
              <name>CR</name>
              <description>Clock range</description>
              <bitRange>[4:2]</bitRange>
            </field>
            <field>
              <name>MR</name>
              <description>MII register</description>
              <bitRange>[10:6]</bitRange>
            </field>
            <field>
              <name>PA</name>
              <description>PHY address</description>
              <bitRange>[15:11]</bitRange>
            </field>
          </fields>
        </register>
        <register>
          <name>MACMIIDR</name>
          <description>Ethernet MAC MII data register (ETH_MACMIIDR)</description>
          <addressOffset>0x14</addressOffset>
          <fields>
            <field>
              <name>MD</name>
              <description>MII data</description>
              <bitRange>[15:0]</bitRange>
            </field>
          </fields>
        </register>
        <register>
          <name>MACFCR</name>
          <description>Ethernet MAC flow control register (ETH_MACFCR)</description>
          <addressOffset>0x18</addressOffset>
          <fields>
            <field>
              <name>FCB_BPA</name>
              <description>Flow control busy/back pressure activate</description>
              <bitRange>[0:0]</bitRange>
            </field>
            <field>
              <name>TFCE</name>
              <description>Transmit flow control enable</description>
              <bitRange>[1:1]</bitRange>
            </field>
            <field>
              <name>RFCE</name>
              <description>Receive flow control enable</description>
              <bitRange>[2:2]</bitRange>
            </field>
            <field>
              <name>UPFD</name>
              <description>Unicast pause frame detect</description>
              <bitRange>[3:3]</bitRange>
            </field>
            <field>
              <name>PLT</name>
              <description>Pause low threshold</description>
              <bitRange>[5:4]</bitRange>
            </field>
            <field>
              <name>ZQPD</name>
              <description>Zero-quanta pause disable</description>
              <bitRange>[7:7]</bitRange>
            </field>
            <field>
              <name>PT</name>
              <description>Pass control frames</description>
              <bitRange>[31:16]</bitRange>
            </field>
          </fields>
        </register>
        <register>
          <name>MACVLANTR</name>
          <description>Ethernet MAC VLAN tag register (ETH_MACVLANTR)</description>
          <addressOffset>0x1C</addressOffset>
          <fields>
            <field>
              <name>VLANTI</name>
              <description>VLAN tag identifier (for receive frames)</description>
              <bitRange>[15:0]</bitRange>
            </field>
            <field>
              <name>VLANTC</name>
              <description>12-bit VLAN tag comparison</description>
              <bitRange>[16:16]</bitRange>
            </field>
          </fields>
        </register>
        <register><name>MACRWUFFR</name><description>ETH remote wakeup frame filter register</description><addressOffset>0x28</addressOffset><fields><field><name>D</name><description>D</description><bitRange>[31:0]</bitRange><access>read-write</access></field></fields></register><register>
          <name>MACPMTCSR</name>
          <description>Ethernet MAC PMT control and status register (ETH_MACPMTCSR)</description>
          <addressOffset>0x2C</addressOffset>
          <fields>
            <field>
              <name>PD</name>
              <description>Power down</description>
              <bitRange>[0:0]</bitRange>
            </field>
            <field>
              <name>MPE</name>
              <description>Magic Packet enable</description>
              <bitRange>[1:1]</bitRange>
            </field>
            <field>
              <name>WFE</name>
              <description>Wakeup frame enable</description>
              <bitRange>[2:2]</bitRange>
            </field>
            <field>
              <name>MPR</name>
              <description>Magic packet received</description>
              <bitRange>[5:5]</bitRange>
            </field>
            <field>
              <name>WFR</name>
              <description>Wakeup frame received</description>
              <bitRange>[6:6]</bitRange>
            </field>
            <field>
              <name>GU</name>
              <description>Global unicast</description>
              <bitRange>[9:9]</bitRange>
            </field>
            <field>
              <name>WFFRPR</name>
              <description>Wakeup frame filter register pointer reset</description>
              <bitRange>[31:31]</bitRange>
            </field>
          </fields>
        </register>
        <register>
          <name>MACSR</name>
          <description>Ethernet MAC interrupt status register (ETH_MACSR)</description>
          <addressOffset>0x38</addressOffset>
          <fields>
            <field>
              <name>PMTS</name>
              <description>PMT status</description>
              <bitRange>[3:3]</bitRange>
            </field>
            <field>
              <name>MMCS</name>
              <description>MMC status</description>
              <bitRange>[4:4]</bitRange>
            </field>
            <field>
              <name>MMCRS</name>
              <description>MMC receive status</description>
              <bitRange>[5:5]</bitRange>
            </field>
            <field>
              <name>MMCTS</name>
              <description>MMC transmit status</description>
              <bitRange>[6:6]</bitRange>
            </field>
            <field>
              <name>TSTS</name>
              <description>Time stamp trigger status</description>
              <bitRange>[9:9]</bitRange>
            </field>
          </fields>
        </register>
        <register>
          <name>MACIMR</name>
          <description>Ethernet MAC interrupt mask register (ETH_MACIMR)</description>
          <addressOffset>0x3C</addressOffset>
          <fields>
            <field>
              <name>PMTIM</name>
              <description>PMT interrupt mask</description>
              <bitRange>[3:3]</bitRange>
            </field>
            <field>
              <name>TSTIM</name>
              <description>Time stamp trigger interrupt mask</description>
              <bitRange>[9:9]</bitRange>
            </field>
          </fields>
        </register>
        <register>
          <name>MACA0HR</name>
          <description>Ethernet MAC address 0 high register (ETH_MACA0HR)</description>
          <addressOffset>0x40</addressOffset>
          <fields>
            <field>
              <name>MACA0H</name>
              <description>MAC address0 high</description>
              <bitRange>[15:0]</bitRange>
            </field>
            <field>
              <name>MO</name>
              <description>Always 1</description>
              <bitRange>[31:31]</bitRange>
              <access>read-only</access>
            </field>
          </fields>
        </register>
        <register>
          <name>MACA0LR</name>
          <description>Ethernet MAC address 0 low register</description>
          <addressOffset>0x44</addressOffset>
          <fields>
            <field>
              <name>MACA0L</name>
              <description>MAC address0 low</description>
              <bitRange>[31:0]</bitRange>
            </field>
          </fields>
        </register>
        <register>
          <name>MACA1HR</name>
          <description>Ethernet MAC address 1 high register (ETH_MACA1HR)</description>
          <addressOffset>0x48</addressOffset>
          <fields>
            <field>
              <name>MACA1H</name>
              <description>MAC address1 high</description>
              <bitRange>[15:0]</bitRange>
            </field>
            <field>
              <name>MBC</name>
              <description>Mask byte control</description>
              <bitRange>[29:24]</bitRange>
            </field>
            <field>
              <name>SA</name>
              <description>Source address</description>
              <bitRange>[30:30]</bitRange>
            </field>
            <field>
              <name>AE</name>
              <description>Address enable</description>
              <bitRange>[31:31]</bitRange>
            </field>
          </fields>
        </register>
        <register>
          <name>MACA1LR</name>
          <description>Ethernet MAC address1 low register</description>
          <addressOffset>0x4C</addressOffset>
          <fields>
            <field>
              <name>MACA1L</name>
              <description>MAC address1 low</description>
              <bitRange>[31:0]</bitRange>
            </field>
          </fields>
        </register>
        <register>
          <name>MACA2HR</name>
          <description>Ethernet MAC address 2 high register (ETH_MACA2HR)</description>
          <addressOffset>0x50</addressOffset>
          <fields>
            <field>
              <name>ETH_MACA2HR</name>
              <description>Ethernet MAC address 2 high register</description>
              <bitRange>[15:0]</bitRange>
            </field>
            <field>
              <name>MBC</name>
              <description>Mask byte control</description>
              <bitRange>[29:24]</bitRange>
            </field>
            <field>
              <name>SA</name>
              <description>Source address</description>
              <bitRange>[30:30]</bitRange>
            </field>
            <field>
              <name>AE</name>
              <description>Address enable</description>
              <bitRange>[31:31]</bitRange>
            </field>
          </fields>
        </register>
        <register>
          <name>MACA2LR</name>
          <description>Ethernet MAC address 2 low register</description>
          <addressOffset>0x54</addressOffset>
          <fields>
            <field>
              <name>MACA2L</name>
              <description>MAC address2 low</description>
              <bitRange>[30:0]</bitRange>
            </field>
          </fields>
        </register>
        <register>
          <name>MACA3HR</name>
          <description>Ethernet MAC address 3 high register (ETH_MACA3HR)</description>
          <addressOffset>0x58</addressOffset>
          <fields>
            <field>
              <name>MACA3H</name>
              <description>MAC address3 high</description>
              <bitRange>[15:0]</bitRange>
            </field>
            <field>
              <name>MBC</name>
              <description>Mask byte control</description>
              <bitRange>[29:24]</bitRange>
            </field>
            <field>
              <name>SA</name>
              <description>Source address</description>
              <bitRange>[30:30]</bitRange>
            </field>
            <field>
              <name>AE</name>
              <description>Address enable</description>
              <bitRange>[31:31]</bitRange>
            </field>
          </fields>
        </register>
        <register>
          <name>MACA3LR</name>
          <description>Ethernet MAC address 3 low register</description>
          <addressOffset>0x5C</addressOffset>
          <fields>
            <field>
              <name>MBCA3L</name>
              <description>MAC address3 low</description>
              <bitRange>[31:0]</bitRange>
            </field>
          </fields>
        </register>
      </registers>
    </peripheral>
    <peripheral>
      <name>ETHERNET_MMC</name>
      <description>Ethernet: MAC management counters</description>
      <baseAddress>0x480C0100</baseAddress>
      <addressBlock>
        <offset>0x0</offset>
        <size>0x400</size>
        <usage>registers</usage>
      </addressBlock>
      <registers>
        <register>
          <name>MMCCR</name>
          <description>Ethernet MMC control register (ETH_MMCCR)</description>
          <addressOffset>0x0</addressOffset>
          <fields>
            <field>
              <name>CR</name>
              <description>Counter reset</description>
              <bitRange>[0:0]</bitRange>
            </field>
            <field>
              <name>CSR</name>
              <description>Counter stop rollover</description>
              <bitRange>[1:1]</bitRange>
            </field>
            <field>
              <name>ROR</name>
              <description>Reset on read</description>
              <bitRange>[2:2]</bitRange>
            </field>
            <field>
              <name>MCF</name>
              <description>MMC counter freeze</description>
              <bitRange>[31:31]</bitRange>
            </field>
          </fields>
        </register>
        <register>
          <name>MMCRIR</name>
          <description>Ethernet MMC receive interrupt register (ETH_MMCRIR)</description>
          <addressOffset>0x4</addressOffset>
          <fields>
            <field>
              <name>RFCES</name>
              <description>Received frames CRC error status</description>
              <bitRange>[5:5]</bitRange>
            </field>
            <field>
              <name>RFAES</name>
              <description>Received frames alignment error status</description>
              <bitRange>[6:6]</bitRange>
            </field>
            <field>
              <name>RGUFS</name>
              <description>Received Good Unicast Frames Status</description>
              <bitRange>[17:17]</bitRange>
            </field>
          </fields>
        </register>
        <register>
          <name>MMCTIR</name>
          <description>Ethernet MMC transmit interrupt register (ETH_MMCTIR)</description>
          <addressOffset>0x8</addressOffset>
          <fields>
            <field>
              <name>TGFSCS</name>
              <description>Transmitted good frames single collision status</description>
              <bitRange>[14:14]</bitRange>
            </field>
            <field>
              <name>TGFMSCS</name>
              <description>Transmitted good frames more single collision status</description>
              <bitRange>[15:15]</bitRange>
            </field>
            <field>
              <name>TGFS</name>
              <description>Transmitted good frames status</description>
              <bitRange>[21:21]</bitRange>
            </field>
          </fields>
        </register>
        <register>
          <name>MMCRIMR</name>
          <description>Ethernet MMC receive interrupt mask register (ETH_MMCRIMR)</description>
          <addressOffset>0xC</addressOffset>
          <fields>
            <field>
              <name>RFCEM</name>
              <description>Received frame CRC error mask</description>
              <bitRange>[5:5]</bitRange>
            </field>
            <field>
              <name>RFAEM</name>
              <description>Received frames alignment error mask</description>
              <bitRange>[6:6]</bitRange>
            </field>
            <field>
              <name>RGUFM</name>
              <description>Received good unicast frames mask</description>
              <bitRange>[17:17]</bitRange>
            </field>
          </fields>
        </register>
        <register>
          <name>MMCTIMR</name>
          <description>Ethernet MMC transmit interrupt mask register (ETH_MMCTIMR)</description>
          <addressOffset>0x10</addressOffset>
          <fields>
            <field>
              <name>TGFSCM</name>
              <description>Transmitted good frames single collision mask</description>
              <bitRange>[14:14]</bitRange>
            </field>
            <field>
              <name>TGFMSCM</name>
              <description>Transmitted good frames more single collision mask</description>
              <bitRange>[15:15]</bitRange>
            </field>
            <field>
              <name>TGFM</name>
              <description>Transmitted good frames mask</description>
              <bitRange>[21:21]</bitRange>
            </field>
          </fields>
        </register>
        <register>
          <name>MMCTGFSCCR</name>
          <description>Ethernet MMC transmitted good frames after a single collision counter</description>
          <addressOffset>0x4C</addressOffset>
          <fields>
            <field>
              <name>TGFSCC</name>
              <description>Transmitted good frames after a single collision counter</description>
              <bitRange>[31:0]</bitRange>
              <access>read-only</access>
            </field>
          </fields>
        </register>
        <register>
          <name>MMCTGFMSCCR</name>
          <description>Ethernet MMC transmitted good frames after more than a single collision</description>
          <addressOffset>0x50</addressOffset>
          <fields>
            <field>
              <name>TGFMSCC</name>
              <description>Transmitted good frames after more than a single collision counter</description>
              <bitRange>[31:0]</bitRange>
              <access>read-only</access>
            </field>
          </fields>
        </register>
        <register>
          <name>MMCTGFCR</name>
          <description>Ethernet MMC transmitted good frames counter register</description>
          <addressOffset>0x68</addressOffset>
          <fields>
            <field>
              <name>TGFC</name>
              <description>Transmitted good frames counter</description>
              <bitRange>[31:0]</bitRange>
              <access>read-only</access>
            </field>
          </fields>
        </register>
        <register>
          <name>MMCRFCECR</name>
          <description>Ethernet MMC received frames with CRC error counter register</description>
          <addressOffset>0x94</addressOffset>
          <fields>
            <field>
              <name>RFCFC</name>
              <description>Received frames with CRC error counter</description>
              <bitRange>[31:0]</bitRange>
              <access>read-only</access>
            </field>
          </fields>
        </register>
        <register>
          <name>MMCRFAECR</name>
          <description>Ethernet MMC received frames with alignment error counter register</description>
          <addressOffset>0x98</addressOffset>
          <fields>
            <field>
              <name>RFAEC</name>
              <description>Received frames with alignment error counter</description>
              <bitRange>[31:0]</bitRange>
              <access>read-only</access>
            </field>
          </fields>
        </register>
        <register>
          <name>MMCRGUFCR</name>
          <description>MMC received good unicast frames counter register</description>
          <addressOffset>0xC4</addressOffset>
          <fields>
            <field>
              <name>RGUFC</name>
              <description>Received good unicast frames counter</description>
              <bitRange>[31:0]</bitRange>
              <access>read-only</access>
            </field>
          </fields>
        </register>
      </registers>
    </peripheral>
    <peripheral>
      <name>ETHERNET_PTP</name>
      <description>Ethernet: Precision time protocol</description>
      <baseAddress>0x480C0700</baseAddress>
      <addressBlock>
        <offset>0x0</offset>
        <size>0x400</size>
        <usage>registers</usage>
      </addressBlock>
      <registers>
        <register>
          <name>PTPTSCR</name>
          <description>Ethernet PTP time stamp control register (ETH_PTPTSCR)</description>
          <addressOffset>0x0</addressOffset>
          <fields>
            <field>
              <name>TSE</name>
              <description>Time stamp enable</description>
              <bitRange>[0:0]</bitRange>
            </field>
            <field>
              <name>TSFCU</name>
              <description>Time stamp fine or coarse update</description>
              <bitRange>[1:1]</bitRange>
            </field>
            <field>
              <name>TSSTI</name>
              <description>Time stamp system time initialize</description>
              <bitRange>[2:2]</bitRange>
            </field>
            <field>
              <name>TSSTU</name>
              <description>Time stamp system time update</description>
              <bitRange>[3:3]</bitRange>
            </field>
            <field>
              <name>TSITE</name>
              <description>Time stamp interrupt trigger enable</description>
              <bitRange>[4:4]</bitRange>
            </field>
            <field>
              <name>TSARU</name>
              <description>Time stamp addend register update</description>
              <bitRange>[5:5]</bitRange>
            </field>
          </fields>
        </register>
        <register>
          <name>PTPSSIR</name>
          <description>Ethernet PTP subsecond increment register</description>
          <addressOffset>0x4</addressOffset>
          <fields>
            <field>
              <name>STSSI</name>
              <description>System time subsecond increment</description>
              <bitRange>[7:0]</bitRange>
            </field>
          </fields>
        </register>
        <register>
          <name>PTPTSHR</name>
          <description>Ethernet PTP time stamp high register</description>
          <addressOffset>0x8</addressOffset>
          <fields>
            <field>
              <name>STS</name>
              <description>System time second</description>
              <bitRange>[31:0]</bitRange>
              <access>read-only</access>
            </field>
          </fields>
        </register>
        <register>
          <name>PTPTSLR</name>
          <description>Ethernet PTP time stamp low register (ETH_PTPTSLR)</description>
          <addressOffset>0xC</addressOffset>
          <fields>
            <field>
              <name>STSS</name>
              <description>System time subseconds</description>
              <bitRange>[30:0]</bitRange>
              <access>read-only</access>
            </field>
            <field>
              <name>STPNS</name>
              <description>System time positive or negative sign</description>
              <bitRange>[31:31]</bitRange>
              <access>read-only</access>
            </field>
          </fields>
        </register>
        <register>
          <name>PTPTSHUR</name>
          <description>Ethernet PTP time stamp high update register</description>
          <addressOffset>0x10</addressOffset>
          <fields>
            <field>
              <name>TSUS</name>
              <description>Time stamp update second</description>
              <bitRange>[31:0]</bitRange>
            </field>
          </fields>
        </register>
        <register>
          <name>PTPTSLUR</name>
          <description>Ethernet PTP time stamp low update register (ETH_PTPTSLUR)</description>
          <addressOffset>0x14</addressOffset>
          <fields>
            <field>
              <name>TSUSS</name>
              <description>Time stamp update subseconds</description>
              <bitRange>[30:0]</bitRange>
            </field>
            <field>
              <name>TSUPNS</name>
              <description>Time stamp update positive or negative sign</description>
              <bitRange>[31:31]</bitRange>
            </field>
          </fields>
        </register>
        <register>
          <name>PTPTSAR</name>
          <description>Ethernet PTP time stamp addend register</description>
          <addressOffset>0x18</addressOffset>
          <fields>
            <field>
              <name>TSA</name>
              <description>Time stamp addend</description>
              <bitRange>[31:0]</bitRange>
            </field>
          </fields>
        </register>
        <register>
          <name>PTPTTHR</name>
          <description>Ethernet PTP target time high register</description>
          <addressOffset>0x1C</addressOffset>
          <fields>
            <field>
              <name>TTSH</name>
              <description>Target time stamp high</description>
              <bitRange>[31:0]</bitRange>
            </field>
          </fields>
        </register>
        <register>
          <name>PTPTTLR</name>
          <description>Ethernet PTP target time low register</description>
          <addressOffset>0x20</addressOffset>
          <fields>
            <field>
              <name>TTSL</name>
              <description>Target time stamp low</description>
              <bitRange>[31:0]</bitRange>
            </field>
          </fields>
        </register>
      </registers>
    </peripheral>
    <peripheral>
      <name>EXTI</name>
      <baseAddress>0x40010400</baseAddress>
      <addressBlock>
        <offset>0x0</offset>
        <size>0x400</size>
        <usage>registers</usage>
      </addressBlock>
      <interrupt>
        <name>EXTI0</name>
        <description>EXTI Line0 interrupt</description>
        <value>6</value>
      </interrupt>
      <interrupt>
        <name>EXTI1</name>
        <description>EXTI Line1 interrupt</description>
        <value>7</value>
      </interrupt>
      <interrupt>
        <name>EXTI2</name>
        <description>EXTI Line2 interrupt</description>
        <value>8</value>
      </interrupt>
      <interrupt>
        <name>EXTI3</name>
        <description>EXTI Line3 interrupt</description>
        <value>9</value>
      </interrupt>
      <interrupt>
        <name>EXTI4</name>
        <description>EXTI Line4 interrupt</description>
        <value>10</value>
      </interrupt>
      <interrupt>
        <name>OTG1_FS_WKUP</name>
        <description>USB1 OTG FS wakeup via EXTI interrupt</description>
        <value>19</value>
      </interrupt>
      <interrupt>
        <name>EXTI9_5</name>
        <description>EXTI Line9_5 interrupt</description>
        <value>23</value>
      </interrupt>
      <interrupt>
        <name>EXTI15_10</name>
        <description>EXTI Line15_10 interrupt</description>
        <value>40</value>
      </interrupt>
      <interrupt>
        <name>RTC_Alarm</name>
        <description>RTC_Alarm EXTI interrupt</description>
        <value>41</value>
      </interrupt>
      <registers>
        <register>
          <name>IMR1</name>
          <addressOffset>0x0</addressOffset>
          <fields>
            <field>
              <name>IMR0</name>
              <bitRange>[0:0]</bitRange>
            </field>
            <field>
              <name>IMR1</name>
              <bitRange>[1:1]</bitRange>
            </field>
            <field>
              <name>IMR2</name>
              <bitRange>[2:2]</bitRange>
            </field>
            <field>
              <name>IMR3</name>
              <bitRange>[3:3]</bitRange>
            </field>
            <field>
              <name>IMR4</name>
              <bitRange>[4:4]</bitRange>
            </field>
            <field>
              <name>IMR5</name>
              <bitRange>[5:5]</bitRange>
            </field>
            <field>
              <name>IMR6</name>
              <bitRange>[6:6]</bitRange>
            </field>
            <field>
              <name>IMR7</name>
              <bitRange>[7:7]</bitRange>
            </field>
            <field>
              <name>IMR8</name>
              <bitRange>[8:8]</bitRange>
            </field>
            <field>
              <name>IMR9</name>
              <bitRange>[9:9]</bitRange>
            </field>
            <field>
              <name>IMR10</name>
              <bitRange>[10:10]</bitRange>
            </field>
            <field>
              <name>IMR11</name>
              <bitRange>[11:11]</bitRange>
            </field>
            <field>
              <name>IMR12</name>
              <bitRange>[12:12]</bitRange>
            </field>
            <field>
              <name>IMR13</name>
              <bitRange>[13:13]</bitRange>
            </field>
            <field>
              <name>IMR14</name>
              <bitRange>[14:14]</bitRange>
            </field>
            <field>
              <name>IMR15</name>
              <bitRange>[15:15]</bitRange>
            </field>
            <field>
              <name>IMR16</name>
              <bitRange>[16:16]</bitRange>
            </field>
            <field>
              <name>IMR17</name>
              <bitRange>[17:17]</bitRange>
            </field>
            <field>
              <name>IMR18</name>
              <bitRange>[18:18]</bitRange>
            </field>
            <field>
              <name>IMR19</name>
              <bitRange>[19:19]</bitRange>
            </field>
            <field>
              <name>IMR20</name>
              <bitRange>[20:20]</bitRange>
            </field>
            <field>
              <name>IMR21</name>
              <bitRange>[21:21]</bitRange>
            </field>
            <field>
              <name>IMR22</name>
              <bitRange>[22:22]</bitRange>
            </field>
            <field>
              <name>IMR23</name>
              <bitRange>[23:23]</bitRange>
            </field>
            <field>
              <name>IMR24</name>
              <bitRange>[24:24]</bitRange>
            </field>
            <field>
              <name>IMR25</name>
              <bitRange>[25:25]</bitRange>
            </field>
            <field>
              <name>IMR26</name>
              <bitRange>[26:26]</bitRange>
            </field>
            <field>
              <name>IMR27</name>
              <bitRange>[27:27]</bitRange>
            </field>
            <field>
              <name>IMR28</name>
              <bitRange>[28:28]</bitRange>
            </field>
            <field>
              <name>IMR29</name>
              <bitRange>[29:29]</bitRange>
            </field>
            <field>
              <name>IMR30</name>
              <bitRange>[30:30]</bitRange>
            </field>
            <field>
              <name>IMR31</name>
              <bitRange>[31:31]</bitRange>
            </field>
          </fields>
        </register>
        <register>
          <name>EMR1</name>
          <addressOffset>0x4</addressOffset>
          <fields>
            <field>
              <name>EMR0</name>
              <bitRange>[0:0]</bitRange>
            </field>
            <field>
              <name>EMR1</name>
              <bitRange>[1:1]</bitRange>
            </field>
            <field>
              <name>EMR2</name>
              <bitRange>[2:2]</bitRange>
            </field>
            <field>
              <name>EMR3</name>
              <bitRange>[3:3]</bitRange>
            </field>
            <field>
              <name>EMR4</name>
              <bitRange>[4:4]</bitRange>
            </field>
            <field>
              <name>EMR5</name>
              <bitRange>[5:5]</bitRange>
            </field>
            <field>
              <name>EMR6</name>
              <bitRange>[6:6]</bitRange>
            </field>
            <field>
              <name>EMR7</name>
              <bitRange>[7:7]</bitRange>
            </field>
            <field>
              <name>EMR8</name>
              <bitRange>[8:8]</bitRange>
            </field>
            <field>
              <name>EMR9</name>
              <bitRange>[9:9]</bitRange>
            </field>
            <field>
              <name>EMR10</name>
              <bitRange>[10:10]</bitRange>
            </field>
            <field>
              <name>EMR11</name>
              <bitRange>[11:11]</bitRange>
            </field>
            <field>
              <name>EMR12</name>
              <bitRange>[12:12]</bitRange>
            </field>
            <field>
              <name>EMR13</name>
              <bitRange>[13:13]</bitRange>
            </field>
            <field>
              <name>EMR14</name>
              <bitRange>[14:14]</bitRange>
            </field>
            <field>
              <name>EMR15</name>
              <bitRange>[15:15]</bitRange>
            </field>
            <field>
              <name>EMR16</name>
              <bitRange>[16:16]</bitRange>
            </field>
            <field>
              <name>EMR17</name>
              <bitRange>[17:17]</bitRange>
            </field>
            <field>
              <name>EMR18</name>
              <bitRange>[18:18]</bitRange>
            </field>
            <field>
              <name>EMR19</name>
              <bitRange>[19:19]</bitRange>
            </field>
            <field>
              <name>EMR20</name>
              <bitRange>[20:20]</bitRange>
            </field>
            <field>
              <name>EMR21</name>
              <bitRange>[21:21]</bitRange>
            </field>
            <field>
              <name>EMR22</name>
              <bitRange>[22:22]</bitRange>
            </field>
            <field>
              <name>EMR23</name>
              <bitRange>[23:23]</bitRange>
            </field>
            <field>
              <name>EMR24</name>
              <bitRange>[24:24]</bitRange>
            </field>
            <field>
              <name>EMR25</name>
              <bitRange>[25:25]</bitRange>
            </field>
            <field>
              <name>EMR26</name>
              <bitRange>[26:26]</bitRange>
            </field>
            <field>
              <name>EMR27</name>
              <bitRange>[27:27]</bitRange>
            </field>
            <field>
              <name>EMR28</name>
              <bitRange>[28:28]</bitRange>
            </field>
            <field>
              <name>EMR29</name>
              <bitRange>[29:29]</bitRange>
            </field>
            <field>
              <name>EMR30</name>
              <bitRange>[30:30]</bitRange>
            </field>
            <field>
              <name>EMR31</name>
              <bitRange>[31:31]</bitRange>
            </field>
          </fields>
        </register>
        <register>
          <name>RTSR</name>
          <addressOffset>0x8</addressOffset>
          <fields>
            <field>
              <name>RTSR0</name>
              <bitRange>[0:0]</bitRange>
            </field>
            <field>
              <name>RTSR1</name>
              <bitRange>[1:1]</bitRange>
            </field>
            <field>
              <name>RTSR2</name>
              <bitRange>[2:2]</bitRange>
            </field>
            <field>
              <name>RTSR3</name>
              <bitRange>[3:3]</bitRange>
            </field>
            <field>
              <name>RTSR4</name>
              <bitRange>[4:4]</bitRange>
            </field>
            <field>
              <name>RTSR5</name>
              <bitRange>[5:5]</bitRange>
            </field>
            <field>
              <name>RTSR6</name>
              <bitRange>[6:6]</bitRange>
            </field>
            <field>
              <name>RTSR7</name>
              <bitRange>[7:7]</bitRange>
            </field>
            <field>
              <name>RTSR8</name>
              <bitRange>[8:8]</bitRange>
            </field>
            <field>
              <name>RTSR9</name>
              <bitRange>[9:9]</bitRange>
            </field>
            <field>
              <name>RTSR10</name>
              <bitRange>[10:10]</bitRange>
            </field>
            <field>
              <name>RTSR11</name>
              <bitRange>[11:11]</bitRange>
            </field>
            <field>
              <name>RTSR12</name>
              <bitRange>[12:12]</bitRange>
            </field>
            <field>
              <name>RTSR13</name>
              <bitRange>[13:13]</bitRange>
            </field>
            <field>
              <name>RTSR14</name>
              <bitRange>[14:14]</bitRange>
            </field>
            <field>
              <name>RTSR15</name>
              <bitRange>[15:15]</bitRange>
            </field>
            <field>
              <name>RTSR16</name>
              <bitRange>[16:16]</bitRange>
            </field>
            <field>
              <name>RTSR17</name>
              <bitRange>[17:17]</bitRange>
            </field>
            <field>
              <name>RTSR18</name>
              <bitRange>[18:18]</bitRange>
            </field>
            <field>
              <name>RTSR19</name>
              <bitRange>[19:19]</bitRange>
            </field>
            <field>
              <name>RTSR20</name>
              <bitRange>[20:20]</bitRange>
            </field>
            <field>
              <name>RTSR21</name>
              <bitRange>[21:21]</bitRange>
            </field>
          </fields>
        </register>
        <register>
          <name>FTSR</name>
          <addressOffset>0xC</addressOffset>
          <fields>
            <field>
              <name>FTSR0</name>
              <bitRange>[0:0]</bitRange>
            </field>
            <field>
              <name>FTSR1</name>
              <bitRange>[1:1]</bitRange>
            </field>
            <field>
              <name>FTSR2</name>
              <bitRange>[2:2]</bitRange>
            </field>
            <field>
              <name>FTSR3</name>
              <bitRange>[3:3]</bitRange>
            </field>
            <field>
              <name>FTSR4</name>
              <bitRange>[4:4]</bitRange>
            </field>
            <field>
              <name>FTSR5</name>
              <bitRange>[5:5]</bitRange>
            </field>
            <field>
              <name>FTSR6</name>
              <bitRange>[6:6]</bitRange>
            </field>
            <field>
              <name>FTSR7</name>
              <bitRange>[7:7]</bitRange>
            </field>
            <field>
              <name>FTSR8</name>
              <bitRange>[8:8]</bitRange>
            </field>
            <field>
              <name>FTSR9</name>
              <bitRange>[9:9]</bitRange>
            </field>
            <field>
              <name>FTSR10</name>
              <bitRange>[10:10]</bitRange>
            </field>
            <field>
              <name>FTSR11</name>
              <bitRange>[11:11]</bitRange>
            </field>
            <field>
              <name>FTSR12</name>
              <bitRange>[12:12]</bitRange>
            </field>
            <field>
              <name>FTSR13</name>
              <bitRange>[13:13]</bitRange>
            </field>
            <field>
              <name>FTSR14</name>
              <bitRange>[14:14]</bitRange>
            </field>
            <field>
              <name>FTSR15</name>
              <bitRange>[15:15]</bitRange>
            </field>
            <field>
              <name>FTSR16</name>
              <bitRange>[16:16]</bitRange>
            </field>
            <field>
              <name>FTSR17</name>
              <bitRange>[17:17]</bitRange>
            </field>
            <field>
              <name>FTSR18</name>
              <bitRange>[18:18]</bitRange>
            </field>
            <field>
              <name>FTSR19</name>
              <bitRange>[19:19]</bitRange>
            </field>
            <field>
              <name>FTSR20</name>
              <bitRange>[20:20]</bitRange>
            </field>
            <field>
              <name>FTSR21</name>
              <bitRange>[21:21]</bitRange>
            </field>
          </fields>
        </register>
        <register>
          <name>SWIER</name>
          <addressOffset>0x10</addressOffset>
          <fields>
            <field>
              <name>SWIER0</name>
              <bitRange>[0:0]</bitRange>
            </field>
            <field>
              <name>SWIER1</name>
              <bitRange>[1:1]</bitRange>
            </field>
            <field>
              <name>SWIER2</name>
              <bitRange>[2:2]</bitRange>
            </field>
            <field>
              <name>SWIER3</name>
              <bitRange>[3:3]</bitRange>
            </field>
            <field>
              <name>SWIER4</name>
              <bitRange>[4:4]</bitRange>
            </field>
            <field>
              <name>SWIER5</name>
              <bitRange>[5:5]</bitRange>
            </field>
            <field>
              <name>SWIER6</name>
              <bitRange>[6:6]</bitRange>
            </field>
            <field>
              <name>SWIER7</name>
              <bitRange>[7:7]</bitRange>
            </field>
            <field>
              <name>SWIER8</name>
              <bitRange>[8:8]</bitRange>
            </field>
            <field>
              <name>SWIER9</name>
              <bitRange>[9:9]</bitRange>
            </field>
            <field>
              <name>SWIER10</name>
              <bitRange>[10:10]</bitRange>
            </field>
            <field>
              <name>SWIER11</name>
              <bitRange>[11:11]</bitRange>
            </field>
            <field>
              <name>SWIER12</name>
              <bitRange>[12:12]</bitRange>
            </field>
            <field>
              <name>SWIER13</name>
              <bitRange>[13:13]</bitRange>
            </field>
            <field>
              <name>SWIER14</name>
              <bitRange>[14:14]</bitRange>
            </field>
            <field>
              <name>SWIER15</name>
              <bitRange>[15:15]</bitRange>
            </field>
            <field>
              <name>SWIER16</name>
              <bitRange>[16:16]</bitRange>
            </field>
            <field>
              <name>SWIER17</name>
              <bitRange>[17:17]</bitRange>
            </field>
            <field>
              <name>SWIER18</name>
              <bitRange>[18:18]</bitRange>
            </field>
            <field>
              <name>SWIER19</name>
              <bitRange>[19:19]</bitRange>
            </field>
            <field>
              <name>SWIER20</name>
              <bitRange>[20:20]</bitRange>
            </field>
            <field>
              <name>SWIER21</name>
              <bitRange>[21:21]</bitRange>
            </field>
          </fields>
        </register>
        <register>
          <name>PR</name>
          <addressOffset>0x14</addressOffset>
          <fields>
            <field>
              <name>PR0</name>
              <bitRange>[0:0]</bitRange>
            </field>
            <field>
              <name>PR1</name>
              <bitRange>[1:1]</bitRange>
            </field>
            <field>
              <name>PR2</name>
              <bitRange>[2:2]</bitRange>
            </field>
            <field>
              <name>PR3</name>
              <bitRange>[3:3]</bitRange>
            </field>
            <field>
              <name>PR4</name>
              <bitRange>[4:4]</bitRange>
            </field>
            <field>
              <name>PR5</name>
              <bitRange>[5:5]</bitRange>
            </field>
            <field>
              <name>PR6</name>
              <bitRange>[6:6]</bitRange>
            </field>
            <field>
              <name>PR7</name>
              <bitRange>[7:7]</bitRange>
            </field>
            <field>
              <name>PR8</name>
              <bitRange>[8:8]</bitRange>
            </field>
            <field>
              <name>PR9</name>
              <bitRange>[9:9]</bitRange>
            </field>
            <field>
              <name>PR10</name>
              <bitRange>[10:10]</bitRange>
            </field>
            <field>
              <name>PR11</name>
              <bitRange>[11:11]</bitRange>
            </field>
            <field>
              <name>PR12</name>
              <bitRange>[12:12]</bitRange>
            </field>
            <field>
              <name>PR13</name>
              <bitRange>[13:13]</bitRange>
            </field>
            <field>
              <name>PR14</name>
              <bitRange>[14:14]</bitRange>
            </field>
            <field>
              <name>PR15</name>
              <bitRange>[15:15]</bitRange>
            </field>
            <field>
              <name>PR16</name>
              <bitRange>[16:16]</bitRange>
            </field>
            <field>
              <name>PR17</name>
              <bitRange>[17:17]</bitRange>
            </field>
            <field>
              <name>PR18</name>
              <bitRange>[18:18]</bitRange>
            </field>
            <field>
              <name>PR19</name>
              <bitRange>[19:19]</bitRange>
            </field>
            <field>
              <name>PR20</name>
              <bitRange>[20:20]</bitRange>
            </field>
            <field>
              <name>PR21</name>
              <bitRange>[21:21]</bitRange>
            </field>
          </fields>
        </register>
        <register>
          <name>IMR2</name>
          <addressOffset>0x18</addressOffset>
          <fields>
            <field>
              <name>IMR32</name>
              <bitRange>[0:0]</bitRange>
            </field>
            <field>
              <name>IMR33</name>
              <bitRange>[1:1]</bitRange>
            </field>
            <field>
              <name>IMR34</name>
              <bitRange>[2:2]</bitRange>
            </field>
          </fields>
        </register>
        <register>
          <name>EMR2</name>
          <addressOffset>0x1C</addressOffset>
          <fields>
            <field>
              <name>EMR32</name>
              <bitRange>[0:0]</bitRange>
            </field>
            <field>
              <name>EMR33</name>
              <bitRange>[1:1]</bitRange>
            </field>
            <field>
              <name>EMR34</name>
              <bitRange>[2:2]</bitRange>
            </field>
          </fields>
        </register>
      </registers>
    </peripheral>
    <peripheral>
      <name>FDCAN1</name>
      <groupName>FDCAN</groupName>
      <baseAddress>0x4000CC00</baseAddress>
      <addressBlock>
        <offset>0x0</offset>
        <size>0x400</size>
        <usage>registers</usage>
      </addressBlock>
      <interrupt>
        <name>CAN1_INT0</name>
        <description>CAN1_INT0 interrupt</description>
        <value>20</value>
      </interrupt>
      <interrupt>
        <name>CAN1_INT1</name>
        <description>CAN1_INT1 interrupt</description>
        <value>83</value>
      </interrupt>
      <registers>
        <register>
          <name>CREL</name>
          <addressOffset>0x0</addressOffset>
          <fields>
            <field>
              <name>DAY</name>
              <description>-</description>
              <bitRange>[7:0]</bitRange>
              <access>read-only</access>
            </field>
            <field>
              <name>MON</name>
              <description>-</description>
              <bitRange>[15:8]</bitRange>
              <access>read-only</access>
            </field>
            <field>
              <name>YEAR</name>
              <description>-</description>
              <bitRange>[19:16]</bitRange>
              <access>read-only</access>
            </field>
            <field>
              <name>SUBSTEP</name>
              <description>-</description>
              <bitRange>[23:20]</bitRange>
              <access>read-only</access>
            </field>
            <field>
              <name>STEP</name>
              <description>-</description>
              <bitRange>[27:24]</bitRange>
              <access>read-only</access>
            </field>
            <field>
              <name>REL</name>
              <description>-</description>
              <bitRange>[31:28]</bitRange>
              <access>read-only</access>
            </field>
          </fields>
        </register>
        <register>
          <name>ENDN</name>
          <addressOffset>0x4</addressOffset>
          <fields>
            <field>
              <name>ETV</name>
              <description>Endian Register</description>
              <bitRange>[31:0]</bitRange>
              <access>read-only</access>
            </field>
          </fields>
        </register>
        <register>
          <name>DBTP</name>
          <addressOffset>0xC</addressOffset>
          <fields>
            <field>
              <name>DSJW</name>
              <description>Data (Re)Synchronization Jump Width</description>
              <bitRange>[3:0]</bitRange>
            </field>
            <field>
              <name>DTSEG2</name>
              <description>Data time segment after sample point</description>
              <bitRange>[7:4]</bitRange>
            </field>
            <field>
              <name>DTSEG1</name>
              <description>Data time segment before sample point</description>
              <bitRange>[12:8]</bitRange>
            </field>
            <field>
              <name>DBRP</name>
              <description>Data Bit Rate Prescaler</description>
              <bitRange>[20:16]</bitRange>
            </field>
            <field>
              <name>TDC</name>
              <description>Transmitter Delay Compensation</description>
              <bitRange>[23:23]</bitRange>
            </field>
          </fields>
        </register>
        <register>
          <name>TEST</name>
          <addressOffset>0x10</addressOffset>
          <fields>
            <field>
              <name>LBCK</name>
              <description>Loop Back Mode</description>
              <bitRange>[4:4]</bitRange>
            </field>
            <field>
              <name>TX</name>
              <description>Control of Transmit Pin</description>
              <bitRange>[6:5]</bitRange>
            </field>
            <field>
              <name>RX</name>
              <description>Receive Pin</description>
              <bitRange>[7:7]</bitRange>
            </field>
            <field>
              <name>TXBNP</name>
              <description>Tx Buffer Number Prepared</description>
              <bitRange>[12:8]</bitRange>
            </field>
            <field>
              <name>PVAL</name>
              <description>Prepared Valid</description>
              <bitRange>[13:13]</bitRange>
            </field>
            <field>
              <name>TXBNS</name>
              <description>Tx Buffer Number Started</description>
              <bitRange>[20:16]</bitRange>
            </field>
            <field>
              <name>SVAL</name>
              <description>Started Valid</description>
              <bitRange>[21:21]</bitRange>
            </field>
          </fields>
        </register>
        <register>
          <name>RWD</name>
          <addressOffset>0x14</addressOffset>
          <fields>
            <field>
              <name>WDC</name>
              <description>Watchdog Configuration</description>
              <bitRange>[7:0]</bitRange>
            </field>
            <field>
              <name>WDV</name>
              <description>Watchdog Value</description>
              <bitRange>[15:8]</bitRange>
            </field>
          </fields>
        </register>
        <register>
          <name>CCCR</name>
          <addressOffset>0x18</addressOffset>
          <fields>
            <field>
              <name>INIT</name>
              <description>Initialization</description>
              <bitRange>[0:0]</bitRange>
            </field>
            <field>
              <name>CCE</name>
              <description>Configuration Change Enable</description>
              <bitRange>[1:1]</bitRange>
            </field>
            <field>
              <name>ASM</name>
              <description>Restricted Operation Mode</description>
              <bitRange>[2:2]</bitRange>
            </field>
            <field>
              <name>CSA</name>
              <description>Clock Stop Acknowledge</description>
              <bitRange>[3:3]</bitRange>
            </field>
            <field>
              <name>CSR</name>
              <description>Clock Stop Request</description>
              <bitRange>[4:4]</bitRange>
            </field>
            <field>
              <name>MON</name>
              <description>Bus Monitoring Mode</description>
              <bitRange>[5:5]</bitRange>
            </field>
            <field>
              <name>DAR</name>
              <description>Disable Automatic Retransmission</description>
              <bitRange>[6:6]</bitRange>
            </field>
            <field>
              <name>TEST</name>
              <description>Test Mode Enable</description>
              <bitRange>[7:7]</bitRange>
            </field>
            <field>
              <name>FDOE</name>
              <description>FD Operation Enable</description>
              <bitRange>[8:8]</bitRange>
            </field>
            <field>
              <name>BRSE</name>
              <description>Bit Rate Switch Enable</description>
              <bitRange>[9:9]</bitRange>
            </field>
            <field>
              <name>WMM</name>
              <description>Wide Message Marker</description>
              <bitRange>[11:11]</bitRange>
            </field>
            <field>
              <name>PXHD</name>
              <description>Protocol Exception Handling Disable</description>
              <bitRange>[12:12]</bitRange>
            </field>
            <field>
              <name>EFBI</name>
              <description>Edge Filtering during Bus Integration</description>
              <bitRange>[13:13]</bitRange>
            </field>
            <field>
              <name>TXP</name>
              <description>Transmit Pause</description>
              <bitRange>[14:14]</bitRange>
            </field>
            <field>
              <name>NISO</name>
              <description>Non ISO Operation</description>
              <bitRange>[15:15]</bitRange>
            </field>
          </fields>
        </register>
        <register>
          <name>NBTP</name>
          <addressOffset>0x1C</addressOffset>
          <fields>
            <field>
              <name>NTSEG2</name>
              <description>Nominal Time segment after sample point</description>
              <bitRange>[6:0]</bitRange>
              <access>read-only</access>
            </field>
            <field>
              <name>NTSEG1</name>
              <description>Nominal Time segment before sample point</description>
              <bitRange>[15:8]</bitRange>
              <access>read-only</access>
            </field>
            <field>
              <name>NBRP</name>
              <description>Nominal Bit Rate Prescaler</description>
              <bitRange>[24:16]</bitRange>
              <access>read-only</access>
            </field>
            <field>
              <name>NSJW</name>
              <description>Nominal (Re)Synchronization Jump Width</description>
              <bitRange>[31:25]</bitRange>
              <access>read-only</access>
            </field>
          </fields>
        </register>
        <register>
          <name>TSCC</name>
          <addressOffset>0x20</addressOffset>
          <fields>
            <field>
              <name>TSS</name>
              <description>Timestamp Select</description>
              <bitRange>[1:0]</bitRange>
            </field>
            <field>
              <name>TCP</name>
              <description>Timestamp Counter Prescaler</description>
              <bitRange>[19:16]</bitRange>
            </field>
          </fields>
        </register>
        <register>
          <name>TSCV</name>
          <addressOffset>0x24</addressOffset>
          <fields>
            <field>
              <name>TSC</name>
              <description>Timestamp Counter</description>
              <bitRange>[15:0]</bitRange>
            </field>
          </fields>
        </register>
        <register>
          <name>TOCC</name>
          <addressOffset>0x28</addressOffset>
          <fields>
            <field>
              <name>ETOC</name>
              <description>Enable Timeout Counter</description>
              <bitRange>[0:0]</bitRange>
            </field>
            <field>
              <name>TOS</name>
              <description>Timeout Select</description>
              <bitRange>[2:1]</bitRange>
            </field>
            <field>
              <name>TOP</name>
              <description>Timeout Period</description>
              <bitRange>[31:16]</bitRange>
            </field>
          </fields>
        </register>
        <register>
          <name>TOCV</name>
          <addressOffset>0x2C</addressOffset>
          <fields>
            <field>
              <name>TOC</name>
              <description>Timeout Counter</description>
              <bitRange>[15:0]</bitRange>
            </field>
          </fields>
        </register>
        <register>
          <name>ECR</name>
          <addressOffset>0x40</addressOffset>
          <fields>
            <field>
              <name>TEC</name>
              <description>Transmit Error Counter</description>
              <bitRange>[7:0]</bitRange>
            </field>
            <field>
              <name>REC</name>
              <description>Receive Error Counter</description>
              <bitRange>[14:8]</bitRange>
            </field>
            <field>
              <name>RP</name>
              <description>Receive Error Passive</description>
              <bitRange>[15:15]</bitRange>
            </field>
            <field>
              <name>CEL</name>
              <description>CAN Error Logging</description>
              <bitRange>[23:16]</bitRange>
            </field>
          </fields>
        </register>
        <register>
          <name>PSR</name>
          <addressOffset>0x44</addressOffset>
          <fields>
            <field>
              <name>LEC</name>
              <description>Last Error Code</description>
              <bitRange>[2:0]</bitRange>
            </field>
            <field>
              <name>ACT</name>
              <description>Activity</description>
              <bitRange>[4:3]</bitRange>
            </field>
            <field>
              <name>EP</name>
              <description>Error Passive</description>
              <bitRange>[5:5]</bitRange>
            </field>
            <field>
              <name>EW</name>
              <description>Warning Status</description>
              <bitRange>[6:6]</bitRange>
            </field>
            <field>
              <name>BO</name>
              <description>Bus_Off Status</description>
              <bitRange>[7:7]</bitRange>
            </field>
            <field>
              <name>DLEC</name>
              <description>Data Phase Last Error Code</description>
              <bitRange>[10:8]</bitRange>
            </field>
            <field>
              <name>RESI</name>
              <description>ESI flag of last received CAN FD Message</description>
              <bitRange>[11:11]</bitRange>
            </field>
            <field>
              <name>RBRS</name>
              <description>BRS flag of last received CAN FD Message</description>
              <bitRange>[12:12]</bitRange>
            </field>
            <field>
              <name>RFDF</name>
              <description>Received a CAN FD Message</description>
              <bitRange>[13:13]</bitRange>
            </field>
            <field>
              <name>PXE</name>
              <description>Protocol Exception Event</description>
              <bitRange>[14:14]</bitRange>
            </field>
            <field>
              <name>TDCV</name>
              <description>Transmitter Delay Compensation Value</description>
              <bitRange>[22:16]</bitRange>
            </field>
          </fields>
        </register>
        <register>
          <name>TDCR</name>
          <addressOffset>0x48</addressOffset>
          <fields>
            <field>
              <name>TDCF</name>
              <description>Transmitter Delay Compensation Filter Window Length</description>
              <bitRange>[6:0]</bitRange>
            </field>
            <field>
              <name>TDCO</name>
              <description>Transmitter Delay Compensation SSP Offset</description>
              <bitRange>[14:8]</bitRange>
            </field>
          </fields>
        </register>
        <register>
          <name>IR</name>
          <addressOffset>0x50</addressOffset>
          <fields>
            <field>
              <name>RF0N</name>
              <description>Rx FIFO 0 New Message</description>
              <bitRange>[0:0]</bitRange>
            </field>
            <field>
              <name>RF0W</name>
              <description>Rx FIFO 0 Watermark Reached</description>
              <bitRange>[1:1]</bitRange>
            </field>
            <field>
              <name>RF0F</name>
              <description>Rx FIFO 0 Full</description>
              <bitRange>[2:2]</bitRange>
            </field>
            <field>
              <name>RF0L</name>
              <description>Rx FIFO 0 Message Lost</description>
              <bitRange>[3:3]</bitRange>
            </field>
            <field>
              <name>RF1N</name>
              <description>Rx FIFO 1 New Message</description>
              <bitRange>[4:4]</bitRange>
            </field>
            <field>
              <name>RF1W</name>
              <description>Rx FIFO 1 Watermark Reached</description>
              <bitRange>[5:5]</bitRange>
            </field>
            <field>
              <name>RF1F</name>
              <description>Rx FIFO 1 Full</description>
              <bitRange>[6:6]</bitRange>
            </field>
            <field>
              <name>RF1L</name>
              <description>Rx FIFO 1 Message Lost</description>
              <bitRange>[7:7]</bitRange>
            </field>
            <field>
              <name>HPM</name>
              <description>High Priority Message</description>
              <bitRange>[8:8]</bitRange>
            </field>
            <field>
              <name>TC</name>
              <description>Transmission Completed</description>
              <bitRange>[9:9]</bitRange>
            </field>
            <field>
              <name>TCF</name>
              <description>Transmission Cancellation Finished</description>
              <bitRange>[10:10]</bitRange>
            </field>
            <field>
              <name>TFE</name>
              <description>Tx FIFO Empty</description>
              <bitRange>[11:11]</bitRange>
            </field>
            <field>
              <name>TEFN</name>
              <description>Tx Event FIFO New Entry</description>
              <bitRange>[12:12]</bitRange>
            </field>
            <field>
              <name>TEFW</name>
              <description>Tx Event FIFO Watermark Reached</description>
              <bitRange>[13:13]</bitRange>
            </field>
            <field>
              <name>TEFF</name>
              <description>Tx Event FIFO Full</description>
              <bitRange>[14:14]</bitRange>
            </field>
            <field>
              <name>TEFL</name>
              <description>Tx Event FIFO Element Lost</description>
              <bitRange>[15:15]</bitRange>
            </field>
            <field>
              <name>TSW</name>
              <description>Timestamp Wraparound</description>
              <bitRange>[16:16]</bitRange>
            </field>
            <field>
              <name>MRAF</name>
              <description>Message RAM Access Failure</description>
              <bitRange>[17:17]</bitRange>
            </field>
            <field>
              <name>TOO</name>
              <description>Timeout Occurred</description>
              <bitRange>[18:18]</bitRange>
            </field>
            <field>
              <name>DRX</name>
              <description>Message stored to Dedicated Rx Buffer</description>
              <bitRange>[19:19]</bitRange>
            </field>
            <field>
              <name>BEC</name>
              <description>Bit Error Corrected</description>
              <bitRange>[20:20]</bitRange>
            </field>
            <field>
              <name>BEU</name>
              <description>Bit Error Uncorrected</description>
              <bitRange>[21:21]</bitRange>
            </field>
            <field>
              <name>ELO</name>
              <description>Error Logging Overflow</description>
              <bitRange>[22:22]</bitRange>
            </field>
            <field>
              <name>EP</name>
              <description>Error Passive</description>
              <bitRange>[23:23]</bitRange>
            </field>
            <field>
              <name>EW</name>
              <description>Warning Status</description>
              <bitRange>[24:24]</bitRange>
            </field>
            <field>
              <name>BO</name>
              <description>Bus_Off Status</description>
              <bitRange>[25:25]</bitRange>
            </field>
            <field>
              <name>WDI</name>
              <description>Watchdog Interrupt</description>
              <bitRange>[26:26]</bitRange>
            </field>
            <field>
              <name>PEA</name>
              <description>Protocol Error in Arbitration Phase</description>
              <bitRange>[27:27]</bitRange>
            </field>
            <field>
              <name>PED</name>
              <description>Protocol Error in Data Phase (Data Bit Time is used)</description>
              <bitRange>[28:28]</bitRange>
            </field>
            <field>
              <name>ARA</name>
              <description>Access to Reserved Address</description>
              <bitRange>[29:29]</bitRange>
            </field>
          </fields>
        </register>
        <register>
          <name>IE</name>
          <addressOffset>0x54</addressOffset>
          <fields>
            <field>
              <name>RF0NE</name>
              <description>Rx FIFO 1 New Message Interrupt Enable</description>
              <bitRange>[0:0]</bitRange>
            </field>
            <field>
              <name>RF0WE</name>
              <description>Rx FIFO 1 Watermark Reached Interrupt Enable</description>
              <bitRange>[1:1]</bitRange>
            </field>
            <field>
              <name>RF0FE</name>
              <description>Rx FIFO 1 Full Interrupt Enable</description>
              <bitRange>[2:2]</bitRange>
            </field>
            <field>
              <name>RF0LE</name>
              <description>Rx FIFO 1 Message Lost Interrupt Enable</description>
              <bitRange>[3:3]</bitRange>
            </field>
            <field>
              <name>RF1NE</name>
              <description>Rx FIFO 2 New Message Interrupt Enable</description>
              <bitRange>[4:4]</bitRange>
            </field>
            <field>
              <name>RF1WE</name>
              <description>Rx FIFO 2 Watermark Reached Interrupt Enable</description>
              <bitRange>[5:5]</bitRange>
            </field>
            <field>
              <name>RF1FE</name>
              <description>Rx FIFO 2 Full Interrupt Enable</description>
              <bitRange>[6:6]</bitRange>
            </field>
            <field>
              <name>RF1LE</name>
              <description>Rx FIFO 2 Message Lost Interrupt Enable</description>
              <bitRange>[7:7]</bitRange>
            </field>
            <field>
              <name>HPME</name>
              <description>High Priority Message Interrupt Enable</description>
              <bitRange>[8:8]</bitRange>
            </field>
            <field>
              <name>TCE</name>
              <description>Transmission Completed Interrupt Enable</description>
              <bitRange>[9:9]</bitRange>
            </field>
            <field>
              <name>TCFE</name>
              <description>Transmission Cancellation Finished Interrupt Enable</description>
              <bitRange>[10:10]</bitRange>
            </field>
            <field>
              <name>TFEE</name>
              <description>Tx FIFO Empty Interrupt Enable</description>
              <bitRange>[11:11]</bitRange>
            </field>
            <field>
              <name>TEFNE</name>
              <description>Tx Event FIFO New Entry Interrupt Enable</description>
              <bitRange>[12:12]</bitRange>
            </field>
            <field>
              <name>TEFWE</name>
              <description>Tx Event FIFO Watermark Reached Interrupt Enable</description>
              <bitRange>[13:13]</bitRange>
            </field>
            <field>
              <name>TEFFE</name>
              <description>Tx Event FIFO Full Interrupt Enable</description>
              <bitRange>[14:14]</bitRange>
            </field>
            <field>
              <name>TEFLE</name>
              <description>Tx Event FIFO Event Lost Interrupt Enable</description>
              <bitRange>[15:15]</bitRange>
            </field>
            <field>
              <name>TSWE</name>
              <description>Timestamp Wraparound Interrupt Enable</description>
              <bitRange>[16:16]</bitRange>
            </field>
            <field>
              <name>MRAFE</name>
              <description>Message RAM Access Failure Interrupt Enable</description>
              <bitRange>[17:17]</bitRange>
            </field>
            <field>
              <name>TOOE</name>
              <description>Timeout Occurred Interrupt Enable</description>
              <bitRange>[18:18]</bitRange>
            </field>
            <field>
              <name>DRXE</name>
              <description>Message stored to Dedicated Rx Buffer Interrupt Enable</description>
              <bitRange>[19:19]</bitRange>
            </field>
            <field>
              <name>BECE</name>
              <description>Bit Error Corrected Interrupt Enable</description>
              <bitRange>[20:20]</bitRange>
            </field>
            <field>
              <name>BEUE</name>
              <description>Bit Error Uncorrected Interrupt Enable</description>
              <bitRange>[21:21]</bitRange>
            </field>
            <field>
              <name>ELOE</name>
              <description>Error Logging Overflow Interrupt Enable</description>
              <bitRange>[22:22]</bitRange>
            </field>
            <field>
              <name>EPE</name>
              <description>Error Passive Interrupt Enable</description>
              <bitRange>[23:23]</bitRange>
            </field>
            <field>
              <name>EWE</name>
              <description>Warning Status Interrupt Enable</description>
              <bitRange>[24:24]</bitRange>
            </field>
            <field>
              <name>BOE</name>
              <description>Bus_Off Status Interrupt Enable</description>
              <bitRange>[25:25]</bitRange>
            </field>
            <field>
              <name>WDIE</name>
              <description>Watchdog Interrupt Enable</description>
              <bitRange>[26:26]</bitRange>
            </field>
            <field>
              <name>PEAE</name>
              <description>Protocol Error in Arbitration Phase Enable</description>
              <bitRange>[27:27]</bitRange>
            </field>
            <field>
              <name>PEDE</name>
              <description>Protocol Error in Data Phase Enable</description>
              <bitRange>[28:28]</bitRange>
            </field>
            <field>
              <name>ARAE</name>
              <description>Access to Reserved Address Enable</description>
              <bitRange>[29:29]</bitRange>
            </field>
          </fields>
        </register>
        <register>
          <name>ILS</name>
          <addressOffset>0x58</addressOffset>
          <fields>
            <field>
              <name>RF0NL</name>
              <description>Rx FIFO 1 New Message Interrupt Line</description>
              <bitRange>[0:0]</bitRange>
            </field>
            <field>
              <name>RF0WL</name>
              <description>Rx FIFO 1 Watermark Reached Interrupt Line</description>
              <bitRange>[1:1]</bitRange>
            </field>
            <field>
              <name>RF0FL</name>
              <description>Rx FIFO 1 Full Interrupt Line</description>
              <bitRange>[2:2]</bitRange>
            </field>
            <field>
              <name>RF0LL</name>
              <description>Rx FIFO 1 Message Lost Interrupt Line</description>
              <bitRange>[3:3]</bitRange>
            </field>
            <field>
              <name>RF1NL</name>
              <description>Rx FIFO 2 New Message Interrupt Line</description>
              <bitRange>[4:4]</bitRange>
            </field>
            <field>
              <name>RF1WL</name>
              <description>Rx FIFO 2 Watermark Reached Interrupt Line</description>
              <bitRange>[5:5]</bitRange>
            </field>
            <field>
              <name>RF1FL</name>
              <description>Rx FIFO 2 Full Interrupt Line</description>
              <bitRange>[6:6]</bitRange>
            </field>
            <field>
              <name>RF1LL</name>
              <description>Rx FIFO 2 Message Lost Interrupt Line</description>
              <bitRange>[7:7]</bitRange>
            </field>
            <field>
              <name>HPML</name>
              <description>High Priority Message Interrupt Line</description>
              <bitRange>[8:8]</bitRange>
            </field>
            <field>
              <name>TCL</name>
              <description>Transmission Completed Interrupt Line</description>
              <bitRange>[9:9]</bitRange>
            </field>
            <field>
              <name>TCFL</name>
              <description>Transmission Cancellation Finished Interrupt Line</description>
              <bitRange>[10:10]</bitRange>
            </field>
            <field>
              <name>TFEL</name>
              <description>Tx FIFO Empty Interrupt Line</description>
              <bitRange>[11:11]</bitRange>
            </field>
            <field>
              <name>TEFNL</name>
              <description>Tx Event FIFO New Entry Interrupt Line</description>
              <bitRange>[12:12]</bitRange>
            </field>
            <field>
              <name>TEFWL</name>
              <description>Tx Event FIFO Watermark Reached Interrupt Line</description>
              <bitRange>[13:13]</bitRange>
            </field>
            <field>
              <name>TEFFL</name>
              <description>Tx Event FIFO Full Interrupt Line</description>
              <bitRange>[14:14]</bitRange>
            </field>
            <field>
              <name>TEFLL</name>
              <description>Tx Event FIFO Event Lost Interrupt Line</description>
              <bitRange>[15:15]</bitRange>
            </field>
            <field>
              <name>TSWL</name>
              <description>Timestamp Wraparound Interrupt Line</description>
              <bitRange>[16:16]</bitRange>
            </field>
            <field>
              <name>MRAFL</name>
              <description>Message RAM Access Failure Interrupt Line</description>
              <bitRange>[17:17]</bitRange>
            </field>
            <field>
              <name>TOOL</name>
              <description>Timeout Occurred Interrupt Line</description>
              <bitRange>[18:18]</bitRange>
            </field>
            <field>
              <name>DRXL</name>
              <description>Message stored to Dedicated Rx Buffer Interrupt Line</description>
              <bitRange>[19:19]</bitRange>
            </field>
            <field>
              <name>BECL</name>
              <description>Bit Error Corrected Interrupt Line</description>
              <bitRange>[20:20]</bitRange>
            </field>
            <field>
              <name>BEUL</name>
              <description>Bit Error Uncorrected Interrupt Line</description>
              <bitRange>[21:21]</bitRange>
            </field>
            <field>
              <name>ELOL</name>
              <description>Error Logging Overflow Interrupt Line</description>
              <bitRange>[22:22]</bitRange>
            </field>
            <field>
              <name>EPL</name>
              <description>Error Passive Interrupt Line</description>
              <bitRange>[23:23]</bitRange>
            </field>
            <field>
              <name>EWL</name>
              <description>Warning Status Interrupt Line</description>
              <bitRange>[24:24]</bitRange>
            </field>
            <field>
              <name>BOL</name>
              <description>Bus_Off Status Interrupt Line</description>
              <bitRange>[25:25]</bitRange>
            </field>
            <field>
              <name>WDIL</name>
              <description>Watchdog Interrupt Line</description>
              <bitRange>[26:26]</bitRange>
            </field>
            <field>
              <name>PEAL</name>
              <description>Protocol Error in Arbitration Phase Line</description>
              <bitRange>[27:27]</bitRange>
            </field>
            <field>
              <name>PEDL</name>
              <description>Protocol Error in Data Phase Line</description>
              <bitRange>[28:28]</bitRange>
            </field>
            <field>
              <name>ARAL</name>
              <description>Access to Reserved Address Line</description>
              <bitRange>[29:29]</bitRange>
            </field>
          </fields>
        </register>
        <register>
          <name>ILE</name>
          <addressOffset>0x5C</addressOffset>
          <fields>
            <field>
              <name>EINT0</name>
              <description>Enable Interrupt Line 0</description>
              <bitRange>[0:0]</bitRange>
              <access>read-only</access>
            </field>
            <field>
              <name>EINT1</name>
              <description>Enable Interrupt Line 1</description>
              <bitRange>[1:1]</bitRange>
            </field>
          </fields>
        </register>
        <register>
          <name>GFC</name>
          <addressOffset>0x80</addressOffset>
          <fields>
            <field>
              <name>RRFE</name>
              <description>Reject Remote Frames Extended</description>
              <bitRange>[0:0]</bitRange>
            </field>
            <field>
              <name>RRFS</name>
              <description>Reject Remote Frames Standard</description>
              <bitRange>[1:1]</bitRange>
            </field>
            <field>
              <name>ANFE</name>
              <description>Accept Non-matching Frames Extended</description>
              <bitRange>[3:2]</bitRange>
            </field>
            <field>
              <name>ANFS</name>
              <description>Accept Non-matching Frames Standard</description>
              <bitRange>[5:4]</bitRange>
            </field>
          </fields>
        </register>
        <register>
          <name>SIDFC</name>
          <addressOffset>0x84</addressOffset>
          <fields>
            <field>
              <name>FLSSA</name>
              <description>Filter List Standard Start Address</description>
              <bitRange>[15:2]</bitRange>
            </field>
            <field>
              <name>LSS</name>
              <description>List Size Standard</description>
              <bitRange>[23:16]</bitRange>
            </field>
          </fields>
        </register>
        <register>
          <name>XIDFC</name>
          <addressOffset>0x88</addressOffset>
          <fields>
            <field>
              <name>FLESA</name>
              <description>Filter List Extended Start Address</description>
              <bitRange>[15:2]</bitRange>
            </field>
            <field>
              <name>LSE</name>
              <description>List Size Extended</description>
              <bitRange>[22:16]</bitRange>
            </field>
          </fields>
        </register>
        <register>
          <name>XIDAM</name>
          <addressOffset>0x90</addressOffset>
          <fields>
            <field>
              <name>EIDM</name>
              <description>Extended ID Mask</description>
              <bitRange>[28:0]</bitRange>
            </field>
          </fields>
        </register>
        <register>
          <name>HPMS</name>
          <addressOffset>0x94</addressOffset>
          <fields>
            <field>
              <name>BIDX</name>
              <description>Buffer Index</description>
              <bitRange>[5:0]</bitRange>
              <access>read-only</access>
            </field>
            <field>
              <name>MSI</name>
              <description>Message Storage Indicator</description>
              <bitRange>[7:6]</bitRange>
              <access>read-only</access>
            </field>
            <field>
              <name>FIDX</name>
              <description>Filter Index</description>
              <bitRange>[14:8]</bitRange>
              <access>read-only</access>
            </field>
            <field>
              <name>FLST</name>
              <description>Filter List</description>
              <bitRange>[15:15]</bitRange>
              <access>read-only</access>
            </field>
          </fields>
        </register>
        <register>
          <name>NDAT1</name>
          <addressOffset>0x98</addressOffset>
          <fields>
            <field>
              <name>ND0</name>
              <description>New Data0</description>
              <bitRange>[0:0]</bitRange>
            </field>
            <field>
              <name>ND1</name>
              <description>New Data1</description>
              <bitRange>[1:1]</bitRange>
            </field>
            <field>
              <name>ND2</name>
              <description>New Data2</description>
              <bitRange>[2:2]</bitRange>
            </field>
            <field>
              <name>ND3</name>
              <description>New Data3</description>
              <bitRange>[3:3]</bitRange>
            </field>
            <field>
              <name>ND4</name>
              <description>New Data4</description>
              <bitRange>[4:4]</bitRange>
            </field>
            <field>
              <name>ND5</name>
              <description>New Data5</description>
              <bitRange>[5:5]</bitRange>
            </field>
            <field>
              <name>ND6</name>
              <description>New Data6</description>
              <bitRange>[6:6]</bitRange>
            </field>
            <field>
              <name>ND7</name>
              <description>New Data7</description>
              <bitRange>[7:7]</bitRange>
            </field>
            <field>
              <name>ND8</name>
              <description>New Data8</description>
              <bitRange>[8:8]</bitRange>
            </field>
            <field>
              <name>ND9</name>
              <description>New Data9</description>
              <bitRange>[9:9]</bitRange>
            </field>
            <field>
              <name>ND10</name>
              <description>New Data10</description>
              <bitRange>[10:10]</bitRange>
            </field>
            <field>
              <name>ND11</name>
              <description>New Data11</description>
              <bitRange>[11:11]</bitRange>
            </field>
            <field>
              <name>ND12</name>
              <description>New Data12</description>
              <bitRange>[12:12]</bitRange>
            </field>
            <field>
              <name>ND13</name>
              <description>New Data13</description>
              <bitRange>[13:13]</bitRange>
            </field>
            <field>
              <name>ND14</name>
              <description>New Data14</description>
              <bitRange>[14:14]</bitRange>
            </field>
            <field>
              <name>ND15</name>
              <description>New Data15</description>
              <bitRange>[15:15]</bitRange>
            </field>
            <field>
              <name>ND16</name>
              <description>New Data16</description>
              <bitRange>[16:16]</bitRange>
            </field>
            <field>
              <name>ND17</name>
              <description>New Data17</description>
              <bitRange>[17:17]</bitRange>
            </field>
            <field>
              <name>ND18</name>
              <description>New Data18</description>
              <bitRange>[18:18]</bitRange>
            </field>
            <field>
              <name>ND19</name>
              <description>New Data19</description>
              <bitRange>[19:19]</bitRange>
            </field>
            <field>
              <name>ND20</name>
              <description>New Data20</description>
              <bitRange>[20:20]</bitRange>
            </field>
            <field>
              <name>ND21</name>
              <description>New Data21</description>
              <bitRange>[21:21]</bitRange>
            </field>
            <field>
              <name>ND22</name>
              <description>New Data22</description>
              <bitRange>[22:22]</bitRange>
            </field>
            <field>
              <name>ND23</name>
              <description>New Data23</description>
              <bitRange>[23:23]</bitRange>
            </field>
            <field>
              <name>ND24</name>
              <description>New Data24</description>
              <bitRange>[24:24]</bitRange>
            </field>
            <field>
              <name>ND25</name>
              <description>New Data25</description>
              <bitRange>[25:25]</bitRange>
            </field>
            <field>
              <name>ND26</name>
              <description>New Data26</description>
              <bitRange>[26:26]</bitRange>
            </field>
            <field>
              <name>ND27</name>
              <description>New Data27</description>
              <bitRange>[27:27]</bitRange>
            </field>
            <field>
              <name>ND28</name>
              <description>New Data28</description>
              <bitRange>[28:28]</bitRange>
            </field>
            <field>
              <name>ND29</name>
              <description>New Data29</description>
              <bitRange>[29:29]</bitRange>
            </field>
            <field>
              <name>ND30</name>
              <description>New Data30</description>
              <bitRange>[30:30]</bitRange>
            </field>
            <field>
              <name>ND31</name>
              <description>New Data31</description>
              <bitRange>[31:31]</bitRange>
            </field>
          </fields>
        </register>
        <register>
          <name>NDAT2</name>
          <addressOffset>0x9C</addressOffset>
          <fields>
            <field>
              <name>ND32</name>
              <description>New Data32</description>
              <bitRange>[0:0]</bitRange>
            </field>
            <field>
              <name>ND33</name>
              <description>New Data33</description>
              <bitRange>[1:1]</bitRange>
            </field>
            <field>
              <name>ND34</name>
              <description>New Data34</description>
              <bitRange>[2:2]</bitRange>
            </field>
            <field>
              <name>ND35</name>
              <description>New Data35</description>
              <bitRange>[3:3]</bitRange>
            </field>
            <field>
              <name>ND36</name>
              <description>New Data36</description>
              <bitRange>[4:4]</bitRange>
            </field>
            <field>
              <name>ND37</name>
              <description>New Data37</description>
              <bitRange>[5:5]</bitRange>
            </field>
            <field>
              <name>ND38</name>
              <description>New Data38</description>
              <bitRange>[6:6]</bitRange>
            </field>
            <field>
              <name>ND39</name>
              <description>New Data39</description>
              <bitRange>[7:7]</bitRange>
            </field>
            <field>
              <name>ND40</name>
              <description>New Data40</description>
              <bitRange>[8:8]</bitRange>
            </field>
            <field>
              <name>ND41</name>
              <description>New Data41</description>
              <bitRange>[9:9]</bitRange>
            </field>
            <field>
              <name>ND42</name>
              <description>New Data42</description>
              <bitRange>[10:10]</bitRange>
            </field>
            <field>
              <name>ND43</name>
              <description>New Data43</description>
              <bitRange>[11:11]</bitRange>
            </field>
            <field>
              <name>ND44</name>
              <description>New Data44</description>
              <bitRange>[12:12]</bitRange>
            </field>
            <field>
              <name>ND45</name>
              <description>New Data45</description>
              <bitRange>[13:13]</bitRange>
            </field>
            <field>
              <name>ND46</name>
              <description>New Data46</description>
              <bitRange>[14:14]</bitRange>
            </field>
            <field>
              <name>ND47</name>
              <description>New Data47</description>
              <bitRange>[15:15]</bitRange>
            </field>
            <field>
              <name>ND48</name>
              <description>New Data48</description>
              <bitRange>[16:16]</bitRange>
            </field>
            <field>
              <name>ND49</name>
              <description>New Data49</description>
              <bitRange>[17:17]</bitRange>
            </field>
            <field>
              <name>ND50</name>
              <description>New Data50</description>
              <bitRange>[18:18]</bitRange>
            </field>
            <field>
              <name>ND51</name>
              <description>New Data51</description>
              <bitRange>[19:19]</bitRange>
            </field>
            <field>
              <name>ND52</name>
              <description>New Data52</description>
              <bitRange>[20:20]</bitRange>
            </field>
            <field>
              <name>ND53</name>
              <description>New Data53</description>
              <bitRange>[21:21]</bitRange>
            </field>
            <field>
              <name>ND54</name>
              <description>New Data54</description>
              <bitRange>[22:22]</bitRange>
            </field>
            <field>
              <name>ND55</name>
              <description>New Data55</description>
              <bitRange>[23:23]</bitRange>
            </field>
            <field>
              <name>ND56</name>
              <description>New Data56</description>
              <bitRange>[24:24]</bitRange>
            </field>
            <field>
              <name>ND57</name>
              <description>New Data57</description>
              <bitRange>[25:25]</bitRange>
            </field>
            <field>
              <name>ND58</name>
              <description>New Data58</description>
              <bitRange>[26:26]</bitRange>
            </field>
            <field>
              <name>ND59</name>
              <description>New Data59</description>
              <bitRange>[27:27]</bitRange>
            </field>
            <field>
              <name>ND60</name>
              <description>New Data60</description>
              <bitRange>[28:28]</bitRange>
            </field>
            <field>
              <name>ND61</name>
              <description>New Data61</description>
              <bitRange>[29:29]</bitRange>
            </field>
            <field>
              <name>ND62</name>
              <description>New Data62</description>
              <bitRange>[30:30]</bitRange>
            </field>
            <field>
              <name>ND63</name>
              <description>New Data63</description>
              <bitRange>[31:31]</bitRange>
            </field>
          </fields>
        </register>
        <register>
          <name>RXF0C</name>
          <addressOffset>0xA0</addressOffset>
          <fields>
            <field>
              <name>F0SA</name>
              <description>Rx FIFO 0 Start Address</description>
              <bitRange>[5:2]</bitRange>
              <access>read-only</access>
            </field>
            <field>
              <name>F0S</name>
              <description>Rx FIFO 0 Size</description>
              <bitRange>[22:16]</bitRange>
              <access>read-only</access>
            </field>
            <field>
              <name>F0WM</name>
              <description>Rx FIFO 0 Watermark</description>
              <bitRange>[30:24]</bitRange>
              <access>read-only</access>
            </field>
            <field>
              <name>F0OM</name>
              <description>FIFO 0 Operation Mode</description>
              <bitRange>[31:31]</bitRange>
              <access>read-only</access>
            </field>
          </fields>
        </register>
        <register>
          <name>RXF0S</name>
          <addressOffset>0xA4</addressOffset>
          <fields>
            <field>
              <name>F0FL</name>
              <description>Rx FIFO 0 Fill Level</description>
              <bitRange>[6:0]</bitRange>
              <access>read-only</access>
            </field>
            <field>
              <name>F0GI</name>
              <description>Rx FIFO 0 Get Index</description>
              <bitRange>[13:8]</bitRange>
              <access>read-only</access>
            </field>
            <field>
              <name>F0PI</name>
              <description>Rx FIFO 0 Put Index</description>
              <bitRange>[21:16]</bitRange>
              <access>read-only</access>
            </field>
            <field>
              <name>F0F</name>
              <description>Rx FIFO 0 Full</description>
              <bitRange>[24:24]</bitRange>
              <access>read-only</access>
            </field>
            <field>
              <name>RF0L</name>
              <description>Rx FIFO 0 Message Lost</description>
              <bitRange>[25:25]</bitRange>
              <access>read-only</access>
            </field>
          </fields>
        </register>
        <register>
          <name>RXF0A</name>
          <addressOffset>0xA8</addressOffset>
          <fields>
            <field>
              <name>F0AI</name>
              <description>Rx FIFO 0 Acknowledge Index</description>
              <bitRange>[5:0]</bitRange>
              <access>read-only</access>
            </field>
          </fields>
        </register>
        <register>
          <name>RXBC</name>
          <addressOffset>0xAC</addressOffset>
          <fields>
            <field>
              <name>RBSA</name>
              <description>Rx Buffer Start Address</description>
              <bitRange>[15:2]</bitRange>
              <access>read-only</access>
            </field>
          </fields>
        </register>
        <register>
          <name>RXF1C</name>
          <addressOffset>0xB0</addressOffset>
          <fields>
            <field>
              <name>F1SA</name>
              <description>Rx FIFO 1 Start Address</description>
              <bitRange>[5:2]</bitRange>
              <access>read-only</access>
            </field>
            <field>
              <name>F1S</name>
              <description>Rx FIFO 1 Size</description>
              <bitRange>[22:16]</bitRange>
              <access>read-only</access>
            </field>
            <field>
              <name>F1WM</name>
              <description>Rx FIFO 1 Watermark</description>
              <bitRange>[30:24]</bitRange>
              <access>read-only</access>
            </field>
            <field>
              <name>F1OM</name>
              <description>FIFO 1 Operation Mode</description>
              <bitRange>[31:31]</bitRange>
              <access>read-only</access>
            </field>
          </fields>
        </register>
        <register>
          <name>RXF1S</name>
          <addressOffset>0xB4</addressOffset>
          <fields>
            <field>
              <name>F1FL</name>
              <description>Rx FIFO 1 Fill Level</description>
              <bitRange>[6:0]</bitRange>
              <access>read-only</access>
            </field>
            <field>
              <name>F1GI</name>
              <description>Rx FIFO 1 Get Index</description>
              <bitRange>[13:8]</bitRange>
              <access>read-only</access>
            </field>
            <field>
              <name>F1PI</name>
              <description>Rx FIFO 1 Put Index</description>
              <bitRange>[21:16]</bitRange>
              <access>read-only</access>
            </field>
            <field>
              <name>F1F</name>
              <description>Rx FIFO 1 Full</description>
              <bitRange>[24:24]</bitRange>
              <access>read-only</access>
            </field>
            <field>
              <name>RF1L</name>
              <description>Rx FIFO 1 Message Lost</description>
              <bitRange>[25:25]</bitRange>
              <access>read-only</access>
            </field>
            <field>
              <name>DMS</name>
              <description>Debug Message Status</description>
              <bitRange>[31:30]</bitRange>
              <access>read-only</access>
            </field>
          </fields>
        </register>
        <register>
          <name>RXF1A</name>
          <addressOffset>0xB8</addressOffset>
          <fields>
            <field>
              <name>F1AI</name>
              <description>Rx FIFO 1 Acknowledge Index</description>
              <bitRange>[5:0]</bitRange>
              <access>read-only</access>
            </field>
          </fields>
        </register>
        <register>
          <name>RXESC</name>
          <addressOffset>0xBC</addressOffset>
          <fields>
            <field>
              <name>F0DS</name>
              <description>Rx FIFO 0 Data Field Size</description>
              <bitRange>[2:0]</bitRange>
              <access>read-only</access>
            </field>
            <field>
              <name>F1DS</name>
              <description>Rx FIFO 1 Data Field Size</description>
              <bitRange>[6:4]</bitRange>
              <access>read-only</access>
            </field>
            <field>
              <name>RBDS</name>
              <description>Rx Buffer Data Field Size</description>
              <bitRange>[10:8]</bitRange>
              <access>read-only</access>
            </field>
          </fields>
        </register>
        <register>
          <name>TXBC</name>
          <addressOffset>0xC0</addressOffset>
          <fields>
            <field>
              <name>TBSA</name>
              <description>Tx Buffers Start Address</description>
              <bitRange>[15:2]</bitRange>
              <access>read-only</access>
            </field>
            <field>
              <name>NDTB</name>
              <description>Number of Dedicated Transmit Buffers</description>
              <bitRange>[21:16]</bitRange>
              <access>read-only</access>
            </field>
            <field>
              <name>TFQS</name>
              <description>Transmit FIFO/Queue Size</description>
              <bitRange>[29:24]</bitRange>
              <access>read-only</access>
            </field>
            <field>
              <name>TFQM</name>
              <description>Tx FIFO/Queue Mode</description>
              <bitRange>[30:30]</bitRange>
              <access>read-only</access>
            </field>
          </fields>
        </register>
        <register>
          <name>TXFQS</name>
          <addressOffset>0xC4</addressOffset>
          <fields>
            <field>
              <name>TFFL</name>
              <description>Tx FIFO Free Level</description>
              <bitRange>[5:0]</bitRange>
              <access>read-only</access>
            </field>
            <field>
              <name>TFGI</name>
              <description>Tx FIFO Get Index</description>
              <bitRange>[12:8]</bitRange>
              <access>read-only</access>
            </field>
            <field>
              <name>TFQPI</name>
              <description>Tx FIFO/Queue Put Index</description>
              <bitRange>[20:16]</bitRange>
              <access>read-only</access>
            </field>
            <field>
              <name>TFQF</name>
              <description>Tx FIFO/Queue Full</description>
              <bitRange>[21:21]</bitRange>
              <access>read-only</access>
            </field>
          </fields>
        </register>
        <register>
          <name>TXESC</name>
          <addressOffset>0xC8</addressOffset>
          <fields>
            <field>
              <name>TBDS</name>
              <description>Tx Buffer Data Field Size</description>
              <bitRange>[2:0]</bitRange>
              <access>read-only</access>
            </field>
          </fields>
        </register>
        <register>
          <name>TXBRP</name>
          <addressOffset>0xCC</addressOffset>
          <fields>
            <field>
              <name>TRP0</name>
              <description>Transmission Request Pending</description>
              <bitRange>[0:0]</bitRange>
              <access>read-only</access>
            </field>
            <field>
              <name>TRP1</name>
              <description>Transmission Request Pending</description>
              <bitRange>[1:1]</bitRange>
              <access>read-only</access>
            </field>
            <field>
              <name>TRP2</name>
              <description>Transmission Request Pending</description>
              <bitRange>[2:2]</bitRange>
              <access>read-only</access>
            </field>
            <field>
              <name>TRP3</name>
              <description>Transmission Request Pending</description>
              <bitRange>[3:3]</bitRange>
              <access>read-only</access>
            </field>
            <field>
              <name>TRP4</name>
              <description>Transmission Request Pending</description>
              <bitRange>[4:4]</bitRange>
              <access>read-only</access>
            </field>
            <field>
              <name>TRP5</name>
              <description>Transmission Request Pending</description>
              <bitRange>[5:5]</bitRange>
              <access>read-only</access>
            </field>
            <field>
              <name>TRP6</name>
              <description>Transmission Request Pending</description>
              <bitRange>[6:6]</bitRange>
              <access>read-only</access>
            </field>
            <field>
              <name>TRP7</name>
              <description>Transmission Request Pending</description>
              <bitRange>[7:7]</bitRange>
              <access>read-only</access>
            </field>
            <field>
              <name>TRP8</name>
              <description>Transmission Request Pending</description>
              <bitRange>[8:8]</bitRange>
              <access>read-only</access>
            </field>
            <field>
              <name>TRP9</name>
              <description>Transmission Request Pending</description>
              <bitRange>[9:9]</bitRange>
              <access>read-only</access>
            </field>
            <field>
              <name>TRP10</name>
              <description>Transmission Request Pending</description>
              <bitRange>[10:10]</bitRange>
              <access>read-only</access>
            </field>
            <field>
              <name>TRP11</name>
              <description>Transmission Request Pending</description>
              <bitRange>[11:11]</bitRange>
              <access>read-only</access>
            </field>
            <field>
              <name>TRP12</name>
              <description>Transmission Request Pending</description>
              <bitRange>[12:12]</bitRange>
              <access>read-only</access>
            </field>
            <field>
              <name>TRP13</name>
              <description>Transmission Request Pending</description>
              <bitRange>[13:13]</bitRange>
              <access>read-only</access>
            </field>
            <field>
              <name>TRP14</name>
              <description>Transmission Request Pending</description>
              <bitRange>[14:14]</bitRange>
              <access>read-only</access>
            </field>
            <field>
              <name>TRP15</name>
              <description>Transmission Request Pending</description>
              <bitRange>[15:15]</bitRange>
              <access>read-only</access>
            </field>
            <field>
              <name>TRP16</name>
              <description>Transmission Request Pending</description>
              <bitRange>[16:16]</bitRange>
              <access>read-only</access>
            </field>
            <field>
              <name>TRP17</name>
              <description>Transmission Request Pending</description>
              <bitRange>[17:17]</bitRange>
              <access>read-only</access>
            </field>
            <field>
              <name>TRP18</name>
              <description>Transmission Request Pending</description>
              <bitRange>[18:18]</bitRange>
              <access>read-only</access>
            </field>
            <field>
              <name>TRP19</name>
              <description>Transmission Request Pending</description>
              <bitRange>[19:19]</bitRange>
              <access>read-only</access>
            </field>
            <field>
              <name>TRP20</name>
              <description>Transmission Request Pending</description>
              <bitRange>[20:20]</bitRange>
              <access>read-only</access>
            </field>
            <field>
              <name>TRP21</name>
              <description>Transmission Request Pending</description>
              <bitRange>[21:21]</bitRange>
              <access>read-only</access>
            </field>
            <field>
              <name>TRP22</name>
              <description>Transmission Request Pending</description>
              <bitRange>[22:22]</bitRange>
              <access>read-only</access>
            </field>
            <field>
              <name>TRP23</name>
              <description>Transmission Request Pending</description>
              <bitRange>[23:23]</bitRange>
              <access>read-only</access>
            </field>
            <field>
              <name>TRP24</name>
              <description>Transmission Request Pending</description>
              <bitRange>[24:24]</bitRange>
              <access>read-only</access>
            </field>
            <field>
              <name>TRP25</name>
              <description>Transmission Request Pending</description>
              <bitRange>[25:25]</bitRange>
              <access>read-only</access>
            </field>
            <field>
              <name>TRP26</name>
              <description>Transmission Request Pending</description>
              <bitRange>[26:26]</bitRange>
              <access>read-only</access>
            </field>
            <field>
              <name>TRP27</name>
              <description>Transmission Request Pending</description>
              <bitRange>[27:27]</bitRange>
              <access>read-only</access>
            </field>
            <field>
              <name>TRP28</name>
              <description>Transmission Request Pending</description>
              <bitRange>[28:28]</bitRange>
              <access>read-only</access>
            </field>
            <field>
              <name>TRP29</name>
              <description>Transmission Request Pending</description>
              <bitRange>[29:29]</bitRange>
              <access>read-only</access>
            </field>
            <field>
              <name>TRP30</name>
              <description>Transmission Request Pending</description>
              <bitRange>[30:30]</bitRange>
              <access>read-only</access>
            </field>
            <field>
              <name>TRP31</name>
              <description>Transmission Request Pending</description>
              <bitRange>[31:31]</bitRange>
              <access>read-only</access>
            </field>
          </fields>
        </register>
        <register>
          <name>TXBAR</name>
          <addressOffset>0xD0</addressOffset>
          <fields>
            <field>
              <name>AR0</name>
              <description>Add Request</description>
              <bitRange>[0:0]</bitRange>
            </field>
            <field>
              <name>AR1</name>
              <description>Add Request</description>
              <bitRange>[1:1]</bitRange>
            </field>
            <field>
              <name>AR2</name>
              <description>Add Request</description>
              <bitRange>[2:2]</bitRange>
            </field>
            <field>
              <name>AR3</name>
              <description>Add Request</description>
              <bitRange>[3:3]</bitRange>
            </field>
            <field>
              <name>AR4</name>
              <description>Add Request</description>
              <bitRange>[4:4]</bitRange>
            </field>
            <field>
              <name>AR5</name>
              <description>Add Request</description>
              <bitRange>[5:5]</bitRange>
            </field>
            <field>
              <name>AR6</name>
              <description>Add Request</description>
              <bitRange>[6:6]</bitRange>
            </field>
            <field>
              <name>AR7</name>
              <description>Add Request</description>
              <bitRange>[7:7]</bitRange>
            </field>
            <field>
              <name>AR8</name>
              <description>Add Request</description>
              <bitRange>[8:8]</bitRange>
            </field>
            <field>
              <name>AR9</name>
              <description>Add Request</description>
              <bitRange>[9:9]</bitRange>
            </field>
            <field>
              <name>AR10</name>
              <description>Add Request</description>
              <bitRange>[10:10]</bitRange>
            </field>
            <field>
              <name>AR11</name>
              <description>Add Request</description>
              <bitRange>[11:11]</bitRange>
            </field>
            <field>
              <name>AR12</name>
              <description>Add Request</description>
              <bitRange>[12:12]</bitRange>
            </field>
            <field>
              <name>AR13</name>
              <description>Add Request</description>
              <bitRange>[13:13]</bitRange>
            </field>
            <field>
              <name>AR14</name>
              <description>Add Request</description>
              <bitRange>[14:14]</bitRange>
            </field>
            <field>
              <name>AR15</name>
              <description>Add Request</description>
              <bitRange>[15:15]</bitRange>
            </field>
            <field>
              <name>AR16</name>
              <description>Add Request</description>
              <bitRange>[16:16]</bitRange>
            </field>
            <field>
              <name>AR17</name>
              <description>Add Request</description>
              <bitRange>[17:17]</bitRange>
            </field>
            <field>
              <name>AR18</name>
              <description>Add Request</description>
              <bitRange>[18:18]</bitRange>
            </field>
            <field>
              <name>AR19</name>
              <description>Add Request</description>
              <bitRange>[19:19]</bitRange>
            </field>
            <field>
              <name>AR20</name>
              <description>Add Request</description>
              <bitRange>[20:20]</bitRange>
            </field>
            <field>
              <name>AR21</name>
              <description>Add Request</description>
              <bitRange>[21:21]</bitRange>
            </field>
            <field>
              <name>AR22</name>
              <description>Add Request</description>
              <bitRange>[22:22]</bitRange>
            </field>
            <field>
              <name>AR23</name>
              <description>Add Request</description>
              <bitRange>[23:23]</bitRange>
            </field>
            <field>
              <name>AR24</name>
              <description>Add Request</description>
              <bitRange>[24:24]</bitRange>
            </field>
            <field>
              <name>AR25</name>
              <description>Add Request</description>
              <bitRange>[25:25]</bitRange>
            </field>
            <field>
              <name>AR26</name>
              <description>Add Request</description>
              <bitRange>[26:26]</bitRange>
            </field>
            <field>
              <name>AR27</name>
              <description>Add Request</description>
              <bitRange>[27:27]</bitRange>
            </field>
            <field>
              <name>AR28</name>
              <description>Add Request</description>
              <bitRange>[28:28]</bitRange>
            </field>
            <field>
              <name>AR29</name>
              <description>Add Request</description>
              <bitRange>[29:29]</bitRange>
            </field>
            <field>
              <name>AR30</name>
              <description>Add Request</description>
              <bitRange>[30:30]</bitRange>
            </field>
            <field>
              <name>AR31</name>
              <description>Add Request</description>
              <bitRange>[31:31]</bitRange>
            </field>
          </fields>
        </register>
        <register>
          <name>TXBCR</name>
          <addressOffset>0xD4</addressOffset>
          <fields>
            <field>
              <name>CR0</name>
              <description>Cancellation Request</description>
              <bitRange>[0:0]</bitRange>
            </field>
            <field>
              <name>CR1</name>
              <description>Cancellation Request</description>
              <bitRange>[1:1]</bitRange>
            </field>
            <field>
              <name>CR2</name>
              <description>Cancellation Request</description>
              <bitRange>[2:2]</bitRange>
            </field>
            <field>
              <name>CR3</name>
              <description>Cancellation Request</description>
              <bitRange>[3:3]</bitRange>
            </field>
            <field>
              <name>CR4</name>
              <description>Cancellation Request</description>
              <bitRange>[4:4]</bitRange>
            </field>
            <field>
              <name>CR5</name>
              <description>Cancellation Request</description>
              <bitRange>[5:5]</bitRange>
            </field>
            <field>
              <name>CR6</name>
              <description>Cancellation Request</description>
              <bitRange>[6:6]</bitRange>
            </field>
            <field>
              <name>CR7</name>
              <description>Cancellation Request</description>
              <bitRange>[7:7]</bitRange>
            </field>
            <field>
              <name>CR8</name>
              <description>Cancellation Request</description>
              <bitRange>[8:8]</bitRange>
            </field>
            <field>
              <name>CR9</name>
              <description>Cancellation Request</description>
              <bitRange>[9:9]</bitRange>
            </field>
            <field>
              <name>CR10</name>
              <description>Cancellation Request</description>
              <bitRange>[10:10]</bitRange>
            </field>
            <field>
              <name>CR11</name>
              <description>Cancellation Request</description>
              <bitRange>[11:11]</bitRange>
            </field>
            <field>
              <name>CR12</name>
              <description>Cancellation Request</description>
              <bitRange>[12:12]</bitRange>
            </field>
            <field>
              <name>CR13</name>
              <description>Cancellation Request</description>
              <bitRange>[13:13]</bitRange>
            </field>
            <field>
              <name>CR14</name>
              <description>Cancellation Request</description>
              <bitRange>[14:14]</bitRange>
            </field>
            <field>
              <name>CR15</name>
              <description>Cancellation Request</description>
              <bitRange>[15:15]</bitRange>
            </field>
            <field>
              <name>CR16</name>
              <description>Cancellation Request</description>
              <bitRange>[16:16]</bitRange>
            </field>
            <field>
              <name>CR17</name>
              <description>Cancellation Request</description>
              <bitRange>[17:17]</bitRange>
            </field>
            <field>
              <name>CR18</name>
              <description>Cancellation Request</description>
              <bitRange>[18:18]</bitRange>
            </field>
            <field>
              <name>CR19</name>
              <description>Cancellation Request</description>
              <bitRange>[19:19]</bitRange>
            </field>
            <field>
              <name>CR20</name>
              <description>Cancellation Request</description>
              <bitRange>[20:20]</bitRange>
            </field>
            <field>
              <name>CR21</name>
              <description>Cancellation Request</description>
              <bitRange>[21:21]</bitRange>
            </field>
            <field>
              <name>CR22</name>
              <description>Cancellation Request</description>
              <bitRange>[22:22]</bitRange>
            </field>
            <field>
              <name>CR23</name>
              <description>Cancellation Request</description>
              <bitRange>[23:23]</bitRange>
            </field>
            <field>
              <name>CR24</name>
              <description>Cancellation Request</description>
              <bitRange>[24:24]</bitRange>
            </field>
            <field>
              <name>CR25</name>
              <description>Cancellation Request</description>
              <bitRange>[25:25]</bitRange>
            </field>
            <field>
              <name>CR26</name>
              <description>Cancellation Request</description>
              <bitRange>[26:26]</bitRange>
            </field>
            <field>
              <name>CR27</name>
              <description>Cancellation Request</description>
              <bitRange>[27:27]</bitRange>
            </field>
            <field>
              <name>CR28</name>
              <description>Cancellation Request</description>
              <bitRange>[28:28]</bitRange>
            </field>
            <field>
              <name>CR29</name>
              <description>Cancellation Request</description>
              <bitRange>[29:29]</bitRange>
            </field>
            <field>
              <name>CR30</name>
              <description>Cancellation Request</description>
              <bitRange>[30:30]</bitRange>
            </field>
            <field>
              <name>CR31</name>
              <description>Cancellation Request</description>
              <bitRange>[31:31]</bitRange>
            </field>
          </fields>
        </register>
        <register>
          <name>TXBTO</name>
          <addressOffset>0xD8</addressOffset>
          <fields>
            <field>
              <name>TO0</name>
              <description>Transmission Occurred</description>
              <bitRange>[0:0]</bitRange>
              <access>read-only</access>
            </field>
            <field>
              <name>TO1</name>
              <description>Transmission Occurred</description>
              <bitRange>[1:1]</bitRange>
              <access>read-only</access>
            </field>
            <field>
              <name>TO2</name>
              <description>Transmission Occurred</description>
              <bitRange>[2:2]</bitRange>
              <access>read-only</access>
            </field>
            <field>
              <name>TO3</name>
              <description>Transmission Occurred</description>
              <bitRange>[3:3]</bitRange>
              <access>read-only</access>
            </field>
            <field>
              <name>TO4</name>
              <description>Transmission Occurred</description>
              <bitRange>[4:4]</bitRange>
              <access>read-only</access>
            </field>
            <field>
              <name>TO5</name>
              <description>Transmission Occurred</description>
              <bitRange>[5:5]</bitRange>
              <access>read-only</access>
            </field>
            <field>
              <name>TO6</name>
              <description>Transmission Occurred</description>
              <bitRange>[6:6]</bitRange>
              <access>read-only</access>
            </field>
            <field>
              <name>TO7</name>
              <description>Transmission Occurred</description>
              <bitRange>[7:7]</bitRange>
              <access>read-only</access>
            </field>
            <field>
              <name>TO8</name>
              <description>Transmission Occurred</description>
              <bitRange>[8:8]</bitRange>
              <access>read-only</access>
            </field>
            <field>
              <name>TO9</name>
              <description>Transmission Occurred</description>
              <bitRange>[9:9]</bitRange>
              <access>read-only</access>
            </field>
            <field>
              <name>TO10</name>
              <description>Transmission Occurred</description>
              <bitRange>[10:10]</bitRange>
              <access>read-only</access>
            </field>
            <field>
              <name>TO11</name>
              <description>Transmission Occurred</description>
              <bitRange>[11:11]</bitRange>
              <access>read-only</access>
            </field>
            <field>
              <name>TO12</name>
              <description>Transmission Occurred</description>
              <bitRange>[12:12]</bitRange>
              <access>read-only</access>
            </field>
            <field>
              <name>TO13</name>
              <description>Transmission Occurred</description>
              <bitRange>[13:13]</bitRange>
              <access>read-only</access>
            </field>
            <field>
              <name>TO14</name>
              <description>Transmission Occurred</description>
              <bitRange>[14:14]</bitRange>
              <access>read-only</access>
            </field>
            <field>
              <name>TO15</name>
              <description>Transmission Occurred</description>
              <bitRange>[15:15]</bitRange>
              <access>read-only</access>
            </field>
            <field>
              <name>TO16</name>
              <description>Transmission Occurred</description>
              <bitRange>[16:16]</bitRange>
              <access>read-only</access>
            </field>
            <field>
              <name>TO17</name>
              <description>Transmission Occurred</description>
              <bitRange>[17:17]</bitRange>
              <access>read-only</access>
            </field>
            <field>
              <name>TO18</name>
              <description>Transmission Occurred</description>
              <bitRange>[18:18]</bitRange>
              <access>read-only</access>
            </field>
            <field>
              <name>TO19</name>
              <description>Transmission Occurred</description>
              <bitRange>[19:19]</bitRange>
              <access>read-only</access>
            </field>
            <field>
              <name>TO20</name>
              <description>Transmission Occurred</description>
              <bitRange>[20:20]</bitRange>
              <access>read-only</access>
            </field>
            <field>
              <name>TO21</name>
              <description>Transmission Occurred</description>
              <bitRange>[21:21]</bitRange>
              <access>read-only</access>
            </field>
            <field>
              <name>TO22</name>
              <description>Transmission Occurred</description>
              <bitRange>[22:22]</bitRange>
              <access>read-only</access>
            </field>
            <field>
              <name>TO23</name>
              <description>Transmission Occurred</description>
              <bitRange>[23:23]</bitRange>
              <access>read-only</access>
            </field>
            <field>
              <name>TO24</name>
              <description>Transmission Occurred</description>
              <bitRange>[24:24]</bitRange>
              <access>read-only</access>
            </field>
            <field>
              <name>TO25</name>
              <description>Transmission Occurred</description>
              <bitRange>[25:25]</bitRange>
              <access>read-only</access>
            </field>
            <field>
              <name>TO26</name>
              <description>Transmission Occurred</description>
              <bitRange>[26:26]</bitRange>
              <access>read-only</access>
            </field>
            <field>
              <name>TO27</name>
              <description>Transmission Occurred</description>
              <bitRange>[27:27]</bitRange>
              <access>read-only</access>
            </field>
            <field>
              <name>TO28</name>
              <description>Transmission Occurred</description>
              <bitRange>[28:28]</bitRange>
              <access>read-only</access>
            </field>
            <field>
              <name>TO29</name>
              <description>Transmission Occurred</description>
              <bitRange>[29:29]</bitRange>
              <access>read-only</access>
            </field>
            <field>
              <name>TO30</name>
              <description>Transmission Occurred</description>
              <bitRange>[30:30]</bitRange>
              <access>read-only</access>
            </field>
            <field>
              <name>TO31</name>
              <description>Transmission Occurred</description>
              <bitRange>[31:31]</bitRange>
              <access>read-only</access>
            </field>
          </fields>
        </register>
        <register>
          <name>TXBCF</name>
          <addressOffset>0xDC</addressOffset>
          <fields>
            <field>
              <name>CF0</name>
              <description>Cancellation Finished</description>
              <bitRange>[0:0]</bitRange>
              <access>read-only</access>
            </field>
            <field>
              <name>CF1</name>
              <description>Cancellation Finished</description>
              <bitRange>[1:1]</bitRange>
              <access>read-only</access>
            </field>
            <field>
              <name>CF2</name>
              <description>Cancellation Finished</description>
              <bitRange>[2:2]</bitRange>
              <access>read-only</access>
            </field>
            <field>
              <name>CF3</name>
              <description>Cancellation Finished</description>
              <bitRange>[3:3]</bitRange>
              <access>read-only</access>
            </field>
            <field>
              <name>CF4</name>
              <description>Cancellation Finished</description>
              <bitRange>[4:4]</bitRange>
              <access>read-only</access>
            </field>
            <field>
              <name>CF5</name>
              <description>Cancellation Finished</description>
              <bitRange>[5:5]</bitRange>
              <access>read-only</access>
            </field>
            <field>
              <name>CF6</name>
              <description>Cancellation Finished</description>
              <bitRange>[6:6]</bitRange>
              <access>read-only</access>
            </field>
            <field>
              <name>CF7</name>
              <description>Cancellation Finished</description>
              <bitRange>[7:7]</bitRange>
              <access>read-only</access>
            </field>
            <field>
              <name>CF8</name>
              <description>Cancellation Finished</description>
              <bitRange>[8:8]</bitRange>
              <access>read-only</access>
            </field>
            <field>
              <name>CF9</name>
              <description>Cancellation Finished</description>
              <bitRange>[9:9]</bitRange>
              <access>read-only</access>
            </field>
            <field>
              <name>CF10</name>
              <description>Cancellation Finished</description>
              <bitRange>[10:10]</bitRange>
              <access>read-only</access>
            </field>
            <field>
              <name>CF11</name>
              <description>Cancellation Finished</description>
              <bitRange>[11:11]</bitRange>
              <access>read-only</access>
            </field>
            <field>
              <name>CF12</name>
              <description>Cancellation Finished</description>
              <bitRange>[12:12]</bitRange>
              <access>read-only</access>
            </field>
            <field>
              <name>CF13</name>
              <description>Cancellation Finished</description>
              <bitRange>[13:13]</bitRange>
              <access>read-only</access>
            </field>
            <field>
              <name>CF14</name>
              <description>Cancellation Finished</description>
              <bitRange>[14:14]</bitRange>
              <access>read-only</access>
            </field>
            <field>
              <name>CF15</name>
              <description>Cancellation Finished</description>
              <bitRange>[15:15]</bitRange>
              <access>read-only</access>
            </field>
            <field>
              <name>CF16</name>
              <description>Cancellation Finished</description>
              <bitRange>[16:16]</bitRange>
              <access>read-only</access>
            </field>
            <field>
              <name>CF17</name>
              <description>Cancellation Finished</description>
              <bitRange>[17:17]</bitRange>
              <access>read-only</access>
            </field>
            <field>
              <name>CF18</name>
              <description>Cancellation Finished</description>
              <bitRange>[18:18]</bitRange>
              <access>read-only</access>
            </field>
            <field>
              <name>CF19</name>
              <description>Cancellation Finished</description>
              <bitRange>[19:19]</bitRange>
              <access>read-only</access>
            </field>
            <field>
              <name>CF20</name>
              <description>Cancellation Finished</description>
              <bitRange>[20:20]</bitRange>
              <access>read-only</access>
            </field>
            <field>
              <name>CF21</name>
              <description>Cancellation Finished</description>
              <bitRange>[21:21]</bitRange>
              <access>read-only</access>
            </field>
            <field>
              <name>CF22</name>
              <description>Cancellation Finished</description>
              <bitRange>[22:22]</bitRange>
              <access>read-only</access>
            </field>
            <field>
              <name>CF23</name>
              <description>Cancellation Finished</description>
              <bitRange>[23:23]</bitRange>
              <access>read-only</access>
            </field>
            <field>
              <name>CF24</name>
              <description>Cancellation Finished</description>
              <bitRange>[24:24]</bitRange>
              <access>read-only</access>
            </field>
            <field>
              <name>CF25</name>
              <description>Cancellation Finished</description>
              <bitRange>[25:25]</bitRange>
              <access>read-only</access>
            </field>
            <field>
              <name>CF26</name>
              <description>Cancellation Finished</description>
              <bitRange>[26:26]</bitRange>
              <access>read-only</access>
            </field>
            <field>
              <name>CF27</name>
              <description>Cancellation Finished</description>
              <bitRange>[27:27]</bitRange>
              <access>read-only</access>
            </field>
            <field>
              <name>CF28</name>
              <description>Cancellation Finished</description>
              <bitRange>[28:28]</bitRange>
              <access>read-only</access>
            </field>
            <field>
              <name>CF29</name>
              <description>Cancellation Finished</description>
              <bitRange>[29:29]</bitRange>
              <access>read-only</access>
            </field>
            <field>
              <name>CF30</name>
              <description>Cancellation Finished</description>
              <bitRange>[30:30]</bitRange>
              <access>read-only</access>
            </field>
            <field>
              <name>CF31</name>
              <description>Cancellation Finished</description>
              <bitRange>[31:31]</bitRange>
              <access>read-only</access>
            </field>
          </fields>
        </register>
        <register>
          <name>TXBTIE</name>
          <addressOffset>0xE0</addressOffset>
          <fields>
            <field>
              <name>TIE0</name>
              <description>Transmission Interrupt Enable</description>
              <bitRange>[0:0]</bitRange>
            </field>
            <field>
              <name>TIE1</name>
              <description>Transmission Interrupt Enable</description>
              <bitRange>[1:1]</bitRange>
            </field>
            <field>
              <name>TIE2</name>
              <description>Transmission Interrupt Enable</description>
              <bitRange>[2:2]</bitRange>
            </field>
            <field>
              <name>TIE3</name>
              <description>Transmission Interrupt Enable</description>
              <bitRange>[3:3]</bitRange>
            </field>
            <field>
              <name>TIE4</name>
              <description>Transmission Interrupt Enable</description>
              <bitRange>[4:4]</bitRange>
            </field>
            <field>
              <name>TIE5</name>
              <description>Transmission Interrupt Enable</description>
              <bitRange>[5:5]</bitRange>
            </field>
            <field>
              <name>TIE6</name>
              <description>Transmission Interrupt Enable</description>
              <bitRange>[6:6]</bitRange>
            </field>
            <field>
              <name>TIE7</name>
              <description>Transmission Interrupt Enable</description>
              <bitRange>[7:7]</bitRange>
            </field>
            <field>
              <name>TIE8</name>
              <description>Transmission Interrupt Enable</description>
              <bitRange>[8:8]</bitRange>
            </field>
            <field>
              <name>TIE9</name>
              <description>Transmission Interrupt Enable</description>
              <bitRange>[9:9]</bitRange>
            </field>
            <field>
              <name>TIE10</name>
              <description>Transmission Interrupt Enable</description>
              <bitRange>[10:10]</bitRange>
            </field>
            <field>
              <name>TIE11</name>
              <description>Transmission Interrupt Enable</description>
              <bitRange>[11:11]</bitRange>
            </field>
            <field>
              <name>TIE12</name>
              <description>Transmission Interrupt Enable</description>
              <bitRange>[12:12]</bitRange>
            </field>
            <field>
              <name>TIE13</name>
              <description>Transmission Interrupt Enable</description>
              <bitRange>[13:13]</bitRange>
            </field>
            <field>
              <name>TIE14</name>
              <description>Transmission Interrupt Enable</description>
              <bitRange>[14:14]</bitRange>
            </field>
            <field>
              <name>TIE15</name>
              <description>Transmission Interrupt Enable</description>
              <bitRange>[15:15]</bitRange>
            </field>
            <field>
              <name>TIE16</name>
              <description>Transmission Interrupt Enable</description>
              <bitRange>[16:16]</bitRange>
            </field>
            <field>
              <name>TIE17</name>
              <description>Transmission Interrupt Enable</description>
              <bitRange>[17:17]</bitRange>
            </field>
            <field>
              <name>TIE18</name>
              <description>Transmission Interrupt Enable</description>
              <bitRange>[18:18]</bitRange>
            </field>
            <field>
              <name>TIE19</name>
              <description>Transmission Interrupt Enable</description>
              <bitRange>[19:19]</bitRange>
            </field>
            <field>
              <name>TIE20</name>
              <description>Transmission Interrupt Enable</description>
              <bitRange>[20:20]</bitRange>
            </field>
            <field>
              <name>TIE21</name>
              <description>Transmission Interrupt Enable</description>
              <bitRange>[21:21]</bitRange>
            </field>
            <field>
              <name>TIE22</name>
              <description>Transmission Interrupt Enable</description>
              <bitRange>[22:22]</bitRange>
            </field>
            <field>
              <name>TIE23</name>
              <description>Transmission Interrupt Enable</description>
              <bitRange>[23:23]</bitRange>
            </field>
            <field>
              <name>TIE24</name>
              <description>Transmission Interrupt Enable</description>
              <bitRange>[24:24]</bitRange>
            </field>
            <field>
              <name>TIE25</name>
              <description>Transmission Interrupt Enable</description>
              <bitRange>[25:25]</bitRange>
            </field>
            <field>
              <name>TIE26</name>
              <description>Transmission Interrupt Enable</description>
              <bitRange>[26:26]</bitRange>
            </field>
            <field>
              <name>TIE27</name>
              <description>Transmission Interrupt Enable</description>
              <bitRange>[27:27]</bitRange>
            </field>
            <field>
              <name>TIE28</name>
              <description>Transmission Interrupt Enable</description>
              <bitRange>[28:28]</bitRange>
            </field>
            <field>
              <name>TIE29</name>
              <description>Transmission Interrupt Enable</description>
              <bitRange>[29:29]</bitRange>
            </field>
            <field>
              <name>TIE30</name>
              <description>Transmission Interrupt Enable</description>
              <bitRange>[30:30]</bitRange>
            </field>
            <field>
              <name>TIE31</name>
              <description>Transmission Interrupt Enable</description>
              <bitRange>[31:31]</bitRange>
            </field>
          </fields>
        </register>
        <register>
          <name>TXBCIE</name>
          <addressOffset>0xE4</addressOffset>
          <fields>
            <field>
              <name>CFIE0</name>
              <description>Cancellation Finished Interrupt Enable</description>
              <bitRange>[0:0]</bitRange>
            </field>
            <field>
              <name>CFIE1</name>
              <description>Cancellation Finished Interrupt Enable</description>
              <bitRange>[1:1]</bitRange>
            </field>
            <field>
              <name>CFIE2</name>
              <description>Cancellation Finished Interrupt Enable</description>
              <bitRange>[2:2]</bitRange>
            </field>
            <field>
              <name>CFIE3</name>
              <description>Cancellation Finished Interrupt Enable</description>
              <bitRange>[3:3]</bitRange>
            </field>
            <field>
              <name>CFIE4</name>
              <description>Cancellation Finished Interrupt Enable</description>
              <bitRange>[4:4]</bitRange>
            </field>
            <field>
              <name>CFIE5</name>
              <description>Cancellation Finished Interrupt Enable</description>
              <bitRange>[5:5]</bitRange>
            </field>
            <field>
              <name>CFIE6</name>
              <description>Cancellation Finished Interrupt Enable</description>
              <bitRange>[6:6]</bitRange>
            </field>
            <field>
              <name>CFIE7</name>
              <description>Cancellation Finished Interrupt Enable</description>
              <bitRange>[7:7]</bitRange>
            </field>
            <field>
              <name>CFIE8</name>
              <description>Cancellation Finished Interrupt Enable</description>
              <bitRange>[8:8]</bitRange>
            </field>
            <field>
              <name>CFIE9</name>
              <description>Cancellation Finished Interrupt Enable</description>
              <bitRange>[9:9]</bitRange>
            </field>
            <field>
              <name>CFIE10</name>
              <description>Cancellation Finished Interrupt Enable</description>
              <bitRange>[10:10]</bitRange>
            </field>
            <field>
              <name>CFIE11</name>
              <description>Cancellation Finished Interrupt Enable</description>
              <bitRange>[11:11]</bitRange>
            </field>
            <field>
              <name>CFIE12</name>
              <description>Cancellation Finished Interrupt Enable</description>
              <bitRange>[12:12]</bitRange>
            </field>
            <field>
              <name>CFIE13</name>
              <description>Cancellation Finished Interrupt Enable</description>
              <bitRange>[13:13]</bitRange>
            </field>
            <field>
              <name>CFIE14</name>
              <description>Cancellation Finished Interrupt Enable</description>
              <bitRange>[14:14]</bitRange>
            </field>
            <field>
              <name>CFIE15</name>
              <description>Cancellation Finished Interrupt Enable</description>
              <bitRange>[15:15]</bitRange>
            </field>
            <field>
              <name>CFIE16</name>
              <description>Cancellation Finished Interrupt Enable</description>
              <bitRange>[16:16]</bitRange>
            </field>
            <field>
              <name>CFIE17</name>
              <description>Cancellation Finished Interrupt Enable</description>
              <bitRange>[17:17]</bitRange>
            </field>
            <field>
              <name>CFIE18</name>
              <description>Cancellation Finished Interrupt Enable</description>
              <bitRange>[18:18]</bitRange>
            </field>
            <field>
              <name>CFIE19</name>
              <description>Cancellation Finished Interrupt Enable</description>
              <bitRange>[19:19]</bitRange>
            </field>
            <field>
              <name>CFIE20</name>
              <description>Cancellation Finished Interrupt Enable</description>
              <bitRange>[20:20]</bitRange>
            </field>
            <field>
              <name>CFIE21</name>
              <description>Cancellation Finished Interrupt Enable</description>
              <bitRange>[21:21]</bitRange>
            </field>
            <field>
              <name>CFIE22</name>
              <description>Cancellation Finished Interrupt Enable</description>
              <bitRange>[22:22]</bitRange>
            </field>
            <field>
              <name>CFIE23</name>
              <description>Cancellation Finished Interrupt Enable</description>
              <bitRange>[23:23]</bitRange>
            </field>
            <field>
              <name>CFIE24</name>
              <description>Cancellation Finished Interrupt Enable</description>
              <bitRange>[24:24]</bitRange>
            </field>
            <field>
              <name>CFIE25</name>
              <description>Cancellation Finished Interrupt Enable</description>
              <bitRange>[25:25]</bitRange>
            </field>
            <field>
              <name>CFIE26</name>
              <description>Cancellation Finished Interrupt Enable</description>
              <bitRange>[26:26]</bitRange>
            </field>
            <field>
              <name>CFIE27</name>
              <description>Cancellation Finished Interrupt Enable</description>
              <bitRange>[27:27]</bitRange>
            </field>
            <field>
              <name>CFIE28</name>
              <description>Cancellation Finished Interrupt Enable</description>
              <bitRange>[28:28]</bitRange>
            </field>
            <field>
              <name>CFIE29</name>
              <description>Cancellation Finished Interrupt Enable</description>
              <bitRange>[29:29]</bitRange>
            </field>
            <field>
              <name>CFIE30</name>
              <description>Cancellation Finished Interrupt Enable</description>
              <bitRange>[30:30]</bitRange>
            </field>
            <field>
              <name>CFIE31</name>
              <description>Cancellation Finished Interrupt Enable</description>
              <bitRange>[31:31]</bitRange>
            </field>
          </fields>
        </register>
        <register>
          <name>TXEFC</name>
          <addressOffset>0xF0</addressOffset>
          <fields>
            <field>
              <name>EFSA</name>
              <description>Event FIFO Start Address</description>
              <bitRange>[15:2]</bitRange>
              <access>read-only</access>
            </field>
            <field>
              <name>EFS</name>
              <description>Event FIFO Size</description>
              <bitRange>[21:16]</bitRange>
              <access>read-only</access>
            </field>
            <field>
              <name>EFWM</name>
              <description>Event FIFO Watermark</description>
              <bitRange>[29:24]</bitRange>
              <access>read-only</access>
            </field>
          </fields>
        </register>
        <register>
          <name>TXEFS</name>
          <addressOffset>0xF4</addressOffset>
          <fields>
            <field>
              <name>EFFL</name>
              <description>Event FIFO Fill Level</description>
              <bitRange>[5:0]</bitRange>
              <access>read-only</access>
            </field>
            <field>
              <name>EFGI</name>
              <description>Event FIFO Get Index</description>
              <bitRange>[12:8]</bitRange>
              <access>read-only</access>
            </field>
            <field>
              <name>EFPI</name>
              <description>Event FIFO Put Index</description>
              <bitRange>[20:16]</bitRange>
              <access>read-only</access>
            </field>
            <field>
              <name>EFF</name>
              <description>Event FIFO Full</description>
              <bitRange>[24:24]</bitRange>
              <access>read-only</access>
            </field>
            <field>
              <name>TEFL</name>
              <description>Tx Event FIFO Element Lost</description>
              <bitRange>[25:25]</bitRange>
              <access>read-only</access>
            </field>
          </fields>
        </register>
        <register>
          <name>TXEFA</name>
          <addressOffset>0xF8</addressOffset>
          <fields>
            <field>
              <name>EFAI</name>
              <description>Event FIFO Acknowledge Index</description>
              <bitRange>[4:0]</bitRange>
            </field>
          </fields>
        </register>
      </registers>
    </peripheral>
    <peripheral derivedFrom="FDCAN1">
      <name>FDCAN2</name>
      <baseAddress>0x4000E000</baseAddress>
      <interrupt>
        <name>CAN2_INT0</name>
        <description>CAN2_INT0 interrupt</description>
        <value>84</value>
      </interrupt>
      <interrupt>
        <name>CAN2_INT1</name>
        <description>CAN2_INT1 interrupt</description>
        <value>85</value>
      </interrupt>
    </peripheral>
    <peripheral>
      <name>FLASH</name>
      <baseAddress>0x40022000</baseAddress>
      <addressBlock>
        <offset>0x0</offset>
        <size>0x400</size>
        <usage>registers</usage>
      </addressBlock>
      <interrupt>
        <name>FLASH</name>
        <description>FLASH global Interrupt</description>
        <value>4</value>
      </interrupt>
      <registers>
        <register>
          <name>ACR</name>
          <addressOffset>0x0</addressOffset>
          <fields>
            <field>
              <name>LATENCY</name>
              <description>Latency</description>
              <bitRange>[3:0]</bitRange>
            </field>
          </fields>
        </register>
        <register>
          <name>KEYR</name>
          <addressOffset>0x8</addressOffset>
          <fields>
            <field>
              <name>KEY</name>
              <description>Flash CR key</description>
              <bitRange>[31:0]</bitRange>
            </field>
          </fields>
        </register>
        <register>
          <name>OPTKEYR</name>
          <addressOffset>0xC</addressOffset>
          <fields>
            <field>
              <name>OPTKEY</name>
              <description>Flash Option key</description>
              <bitRange>[31:0]</bitRange>
            </field>
          </fields>
        </register>
        <register>
          <name>SR</name>
          <addressOffset>0x10</addressOffset>
          <fields>
            <field>
              <name>EOP</name>
              <description>End of operation</description>
              <bitRange>[0:0]</bitRange>
            </field>
            <field>
              <name>WRPERR</name>
              <description>Write protection error</description>
              <bitRange>[4:4]</bitRange>
            </field>
            <field>
              <name>USRLOCK</name>
              <description>Userdata Lock</description>
              <bitRange>[13:13]</bitRange>
              <access>read-only</access>
            </field>
            <field>
              <name>RDERR</name>
              <bitRange>[14:14]</bitRange>
            </field>
            <field>
              <name>OPTVERR</name>
              <description>Option and trimming bits loading validity error</description>
              <bitRange>[15:15]</bitRange>
            </field>
            <field>
              <name>BSY0</name>
              <description>Bank0 Busy</description>
              <bitRange>[16:16]</bitRange>
              <access>read-only</access>
            </field>
            <field>
              <name>BSY1</name>
              <description>Bank1 Busy</description>
              <bitRange>[17:17]</bitRange>
              <access>read-only</access>
            </field>
          </fields>
        </register>
        <register>
          <name>CR</name>
          <addressOffset>0x14</addressOffset>
          <fields>
            <field>
              <name>PG</name>
              <description>Page Program</description>
              <bitRange>[0:0]</bitRange>
            </field>
            <field>
              <name>PER</name>
              <description>Page Erase</description>
              <bitRange>[1:1]</bitRange>
            </field>
            <field>
              <name>MER0</name>
              <description>Bank 0 Mass Erase</description>
              <bitRange>[2:2]</bitRange>
            </field>
            <field>
              <name>MER1</name>
              <description>Bank 1 Mass Erase</description>
              <bitRange>[3:3]</bitRange>
            </field>
            <field>
              <name>SER</name>
              <description>Sector Erase</description>
              <bitRange>[11:11]</bitRange>
            </field>
            <field>
              <name>BER</name>
              <description>Block Erase</description>
              <bitRange>[12:12]</bitRange>
            </field>
            <field>
              <name>OPTSTRT</name>
              <description>Option bytes Programming Start</description>
              <bitRange>[17:17]</bitRange>
            </field>
            <field>
              <name>PGSTRT</name>
              <description>Programming Start</description>
              <bitRange>[19:19]</bitRange>
            </field>
            <field>
              <name>EOPIE</name>
              <description>End of operation interrupt enable</description>
              <bitRange>[24:24]</bitRange>
            </field>
            <field>
              <name>ERRIE</name>
              <description>Error interrupt enable</description>
              <bitRange>[25:25]</bitRange>
            </field>
            <field>
              <name>RDERRIE</name>
              <bitRange>[26:26]</bitRange>
            </field>
            <field>
              <name>OBL_LAUNCH</name>
              <description>Force the option bytes loading</description>
              <bitRange>[27:27]</bitRange>
            </field>
            <field>
              <name>OPTLOCK</name>
              <description>Option Lock</description>
              <bitRange>[30:30]</bitRange>
            </field>
            <field>
              <name>LOCK</name>
              <description>Lock</description>
              <bitRange>[31:31]</bitRange>
            </field>
          </fields>
        </register>
        <register>
          <name>ECCR</name>
          <addressOffset>0x18</addressOffset>
          <fields>
            <field>
              <name>ADDR_ECC</name>
              <bitRange>[17:0]</bitRange>
              <access>read-only</access>
            </field>
            <field>
              <name>BK_ECC</name>
              <bitRange>[21:21]</bitRange>
              <access>read-only</access>
            </field>
            <field>
              <name>SYSF_ECC</name>
              <bitRange>[22:22]</bitRange>
              <access>read-only</access>
            </field>
            <field>
              <name>ECCCIE</name>
              <bitRange>[24:24]</bitRange>
            </field>
            <field>
              <name>ECCC</name>
              <bitRange>[30:30]</bitRange>
            </field>
            <field>
              <name>ECCD</name>
              <bitRange>[31:31]</bitRange>
            </field>
          </fields>
        </register>
        <register>
          <name>OPTR1</name>
          <addressOffset>0x20</addressOffset>
          <fields>
            <field>
              <name>RDP</name>
              <description>Read Protection</description>
              <bitRange>[7:0]</bitRange>
            </field>
            <field>
              <name>BFB</name>
              <bitRange>[11:11]</bitRange>
            </field>
            <field>
              <name>IWDG_SW</name>
              <description>IWDG Software Enable</description>
              <bitRange>[12:12]</bitRange>
            </field>
            <field>
              <name>NRST_STOP</name>
              <bitRange>[13:13]</bitRange>
            </field>
            <field>
              <name>NRST_STDBY</name>
              <bitRange>[14:14]</bitRange>
            </field>
          <field><name>IWDG_STOP</name><description>IWDG_STOP</description><bitRange>[9:9]</bitRange><access>read-write</access></field><field><name>IWDG_STDBY</name><description>IWDG_STDBY</description><bitRange>[10:10]</bitRange><access>read-write</access></field><field><name>WWDG_SW</name><description>WWDG_SW</description><bitRange>[15:15]</bitRange><access>read-write</access></field></fields>
        </register>
        <register>
          <name>OPTR2</name>
          <addressOffset>0x24</addressOffset>
          <fields>
            <field>
              <name>NBOOT1</name>
              <bitRange>[8:8]</bitRange>
            </field>
            <field>
              <name>NRST_MODE</name>
              <bitRange>[10:9]</bitRange>
            </field>
            <field>
              <name>SRAM_PE</name>
              <bitRange>[11:11]</bitRange>
            </field>
            <field>
              <name>CCMSRAM_RST</name>
              <bitRange>[12:12]</bitRange>
            </field>
            <field>
              <name>NSWBOOT0</name>
              <bitRange>[13:13]</bitRange>
            </field>
            <field>
              <name>NBOOT0</name>
              <bitRange>[14:14]</bitRange>
            </field>
            <field>
              <name>BOOT_LOCK</name>
              <bitRange>[15:15]</bitRange>
              <access>read-only</access>
            </field>
          </fields>
        </register>
        <register>
          <name>WRPR</name>
          <addressOffset>0x2C</addressOffset>
          <fields>
            <field>
              <name>WRP</name>
              <description>Write Protection Disable</description>
              <bitRange>[7:0]</bitRange>
            </field>
          </fields>
        </register>
        <register>
          <name>PCROP0SR</name>
          <addressOffset>0x30</addressOffset>
          <fields>
            <field>
              <name>PCROP0SR</name>
              <bitRange>[8:0]</bitRange>
            </field>
          </fields>
        </register>
        <register>
          <name>PCROP0ER</name>
          <addressOffset>0x34</addressOffset>
          <fields>
            <field>
              <name>PCROP0ER</name>
              <bitRange>[8:0]</bitRange>
            </field>
          </fields>
        </register>
        <register>
          <name>PCROP1SR</name>
          <addressOffset>0x38</addressOffset>
          <fields>
            <field>
              <name>PCROP1SR</name>
              <bitRange>[8:0]</bitRange>
            </field>
          </fields>
        </register>
        <register>
          <name>PCROP1ER</name>
          <addressOffset>0x3C</addressOffset>
          <fields>
            <field>
              <name>PCROP1ER</name>
              <bitRange>[8:0]</bitRange>
            </field>
          </fields>
        </register>
      </registers>
    </peripheral>
    <peripheral>
      <name>GPIOA</name>
      <baseAddress>0x48000000</baseAddress>
      <addressBlock>
        <offset>0x0</offset>
        <size>0x400</size>
        <usage>registers</usage>
      </addressBlock>
      <registers>
        <register>
          <name>MODER</name>
          <addressOffset>0x0</addressOffset>
          <fields>
            <field>
              <name>MODER0</name>
              <description>GPIOA0 MODE</description>
              <bitRange>[1:0]</bitRange>
            </field>
            <field>
              <name>MODER1</name>
              <description>GPIOA1 MODE</description>
              <bitRange>[3:2]</bitRange>
            </field>
            <field>
              <name>MODER2</name>
              <description>GPIOA2 MODE</description>
              <bitRange>[5:4]</bitRange>
            </field>
            <field>
              <name>MODER3</name>
              <description>GPIOA3 MODE</description>
              <bitRange>[7:6]</bitRange>
            </field>
            <field>
              <name>MODER4</name>
              <description>GPIOA4 MODE</description>
              <bitRange>[9:8]</bitRange>
            </field>
            <field>
              <name>MODER5</name>
              <description>GPIOA5 MODE</description>
              <bitRange>[11:10]</bitRange>
            </field>
            <field>
              <name>MODER6</name>
              <description>GPIOA6 MODE</description>
              <bitRange>[13:12]</bitRange>
            </field>
            <field>
              <name>MODER7</name>
              <description>GPIOA7 MODE</description>
              <bitRange>[15:14]</bitRange>
            </field>
            <field>
              <name>MODER8</name>
              <description>GPIOA8 MODE</description>
              <bitRange>[17:16]</bitRange>
            </field>
            <field>
              <name>MODER9</name>
              <description>GPIOA9 MODE</description>
              <bitRange>[19:18]</bitRange>
            </field>
            <field>
              <name>MODER10</name>
              <description>GPIOA10 MODE</description>
              <bitRange>[21:20]</bitRange>
            </field>
            <field>
              <name>MODER11</name>
              <description>GPIOA11 MODE</description>
              <bitRange>[23:22]</bitRange>
            </field>
            <field>
              <name>MODER12</name>
              <description>GPIOA12 MODE</description>
              <bitRange>[25:24]</bitRange>
            </field>
            <field>
              <name>MODER13</name>
              <description>GPIOA13 MODE</description>
              <bitRange>[27:26]</bitRange>
            </field>
            <field>
              <name>MODER14</name>
              <description>GPIOA14 MODE</description>
              <bitRange>[29:28]</bitRange>
            </field>
            <field>
              <name>MODER15</name>
              <description>GPIOA15 MODE</description>
              <bitRange>[31:30]</bitRange>
            </field>
          </fields>
        </register>
        <register>
          <name>OTYPER</name>
          <addressOffset>0x4</addressOffset>
          <fields>
            <field>
              <name>OT0</name>
              <description>GPIOA0 Output type</description>
              <bitRange>[0:0]</bitRange>
            </field>
            <field>
              <name>OT1</name>
              <description>GPIOA1 Output type</description>
              <bitRange>[1:1]</bitRange>
            </field>
            <field>
              <name>OT2</name>
              <description>GPIOA2 Output type</description>
              <bitRange>[2:2]</bitRange>
            </field>
            <field>
              <name>OT3</name>
              <description>GPIOA3 Output type</description>
              <bitRange>[3:3]</bitRange>
            </field>
            <field>
              <name>OT4</name>
              <description>GPIOA4 Output type</description>
              <bitRange>[4:4]</bitRange>
            </field>
            <field>
              <name>OT5</name>
              <description>GPIOA5 Output type</description>
              <bitRange>[5:5]</bitRange>
            </field>
            <field>
              <name>OT6</name>
              <description>GPIOA6 Output type</description>
              <bitRange>[6:6]</bitRange>
            </field>
            <field>
              <name>OT7</name>
              <description>GPIOA7 Output type</description>
              <bitRange>[7:7]</bitRange>
            </field>
            <field>
              <name>OT8</name>
              <description>GPIOA8 Output type</description>
              <bitRange>[8:8]</bitRange>
            </field>
            <field>
              <name>OT9</name>
              <description>GPIOA9 Output type</description>
              <bitRange>[9:9]</bitRange>
            </field>
            <field>
              <name>OT10</name>
              <description>GPIOA10 Output type</description>
              <bitRange>[10:10]</bitRange>
            </field>
            <field>
              <name>OT11</name>
              <description>GPIOA11 Output type</description>
              <bitRange>[11:11]</bitRange>
            </field>
            <field>
              <name>OT12</name>
              <description>GPIOA12 Output type</description>
              <bitRange>[12:12]</bitRange>
            </field>
            <field>
              <name>OT13</name>
              <description>GPIOA13 Output type</description>
              <bitRange>[13:13]</bitRange>
            </field>
            <field>
              <name>OT14</name>
              <description>GPIOA14 Output type</description>
              <bitRange>[14:14]</bitRange>
            </field>
            <field>
              <name>OT15</name>
              <description>GPIOA15 Output type</description>
              <bitRange>[15:15]</bitRange>
            </field>
          </fields>
        </register>
        <register>
          <name>OSPDDER</name>
          <addressOffset>0x8</addressOffset>
          <fields>
            <field>
              <name>OSPEED0</name>
              <description>GPIOA0 output speed</description>
              <bitRange>[1:0]</bitRange>
            </field>
            <field>
              <name>OSPEED1</name>
              <description>GPIOA1 output speed</description>
              <bitRange>[3:2]</bitRange>
            </field>
            <field>
              <name>OSPEED2</name>
              <description>GPIOA2 output speed</description>
              <bitRange>[5:4]</bitRange>
            </field>
            <field>
              <name>OSPEED3</name>
              <description>GPIOA3 output speed</description>
              <bitRange>[7:6]</bitRange>
            </field>
            <field>
              <name>OSPEED4</name>
              <description>GPIOA4 output speed</description>
              <bitRange>[9:8]</bitRange>
            </field>
            <field>
              <name>OSPEED5</name>
              <description>GPIOA5 output speed</description>
              <bitRange>[11:10]</bitRange>
            </field>
            <field>
              <name>OSPEED6</name>
              <description>GPIOA6 output speed</description>
              <bitRange>[13:12]</bitRange>
            </field>
            <field>
              <name>OSPEED7</name>
              <description>GPIOA7 output speed</description>
              <bitRange>[15:14]</bitRange>
            </field>
            <field>
              <name>OSPEED8</name>
              <description>GPIOA8 output speed</description>
              <bitRange>[17:16]</bitRange>
            </field>
            <field>
              <name>OSPEED9</name>
              <description>GPIOA9 output speed</description>
              <bitRange>[19:18]</bitRange>
            </field>
            <field>
              <name>OSPEED10</name>
              <description>GPIOA10 output speed</description>
              <bitRange>[21:20]</bitRange>
            </field>
            <field>
              <name>OSPEED11</name>
              <description>GPIOA11 output speed</description>
              <bitRange>[23:22]</bitRange>
            </field>
            <field>
              <name>OSPEED12</name>
              <description>GPIOA12 output speed</description>
              <bitRange>[25:24]</bitRange>
            </field>
            <field>
              <name>OSPEED13</name>
              <description>GPIOA13 output speed</description>
              <bitRange>[27:26]</bitRange>
            </field>
            <field>
              <name>OSPEED14</name>
              <description>GPIOA14 output speed</description>
              <bitRange>[29:28]</bitRange>
            </field>
            <field>
              <name>OSPEED15</name>
              <description>GPIOA15 output speed</description>
              <bitRange>[31:30]</bitRange>
            </field>
          </fields>
        </register>
        <register>
          <name>PUPDR</name>
          <addressOffset>0xC</addressOffset>
          <fields>
            <field>
              <name>PUPD0</name>
              <description>GPIOA0 pull up/pull down</description>
              <bitRange>[1:0]</bitRange>
            </field>
            <field>
              <name>PUPD1</name>
              <description>GPIOA1 pull up/pull down</description>
              <bitRange>[3:2]</bitRange>
            </field>
            <field>
              <name>PUPD2</name>
              <description>GPIOA2 pull up/pull down</description>
              <bitRange>[5:4]</bitRange>
            </field>
            <field>
              <name>PUPD3</name>
              <description>GPIOA3 pull up/pull down</description>
              <bitRange>[7:6]</bitRange>
            </field>
            <field>
              <name>PUPD4</name>
              <description>GPIOA4 pull up/pull down</description>
              <bitRange>[9:8]</bitRange>
            </field>
            <field>
              <name>PUPD5</name>
              <description>GPIOA5 pull up/pull down</description>
              <bitRange>[11:10]</bitRange>
            </field>
            <field>
              <name>PUPD6</name>
              <description>GPIOA6 pull up/pull down</description>
              <bitRange>[13:12]</bitRange>
            </field>
            <field>
              <name>PUPD7</name>
              <description>GPIOA7 pull up/pull down</description>
              <bitRange>[15:14]</bitRange>
            </field>
            <field>
              <name>PUPD8</name>
              <description>GPIOA8 pull up/pull down</description>
              <bitRange>[17:16]</bitRange>
            </field>
            <field>
              <name>PUPD9</name>
              <description>GPIOA9 pull up/pull down</description>
              <bitRange>[19:18]</bitRange>
            </field>
            <field>
              <name>PUPD10</name>
              <description>GPIOA10 pull up/pull down</description>
              <bitRange>[21:20]</bitRange>
            </field>
            <field>
              <name>PUPD11</name>
              <description>GPIOA11 pull up/pull down</description>
              <bitRange>[23:22]</bitRange>
            </field>
            <field>
              <name>PUPD12</name>
              <description>GPIOA12 pull up/pull down</description>
              <bitRange>[25:24]</bitRange>
            </field>
            <field>
              <name>PUPD13</name>
              <description>GPIOA13 pull up/pull down</description>
              <bitRange>[27:26]</bitRange>
            </field>
            <field>
              <name>PUPD14</name>
              <description>GPIOA14 pull up/pull down</description>
              <bitRange>[29:28]</bitRange>
            </field>
            <field>
              <name>PUPD15</name>
              <description>GPIOA15 pull up/pull down</description>
              <bitRange>[31:30]</bitRange>
            </field>
          </fields>
        </register>
        <register>
          <name>IDR</name>
          <addressOffset>0x10</addressOffset>
          <fields>
            <field>
              <name>ID0</name>
              <description>GPIOA0 input data</description>
              <bitRange>[0:0]</bitRange>
              <access>read-only</access>
            </field>
            <field>
              <name>ID1</name>
              <description>GPIOA1 input data</description>
              <bitRange>[1:1]</bitRange>
              <access>read-only</access>
            </field>
            <field>
              <name>ID2</name>
              <description>GPIOA2 input data</description>
              <bitRange>[2:2]</bitRange>
              <access>read-only</access>
            </field>
            <field>
              <name>ID3</name>
              <description>GPIOA3 input data</description>
              <bitRange>[3:3]</bitRange>
              <access>read-only</access>
            </field>
            <field>
              <name>ID4</name>
              <description>GPIOA4 input data</description>
              <bitRange>[4:4]</bitRange>
              <access>read-only</access>
            </field>
            <field>
              <name>ID5</name>
              <description>GPIOA5 input data</description>
              <bitRange>[5:5]</bitRange>
              <access>read-only</access>
            </field>
            <field>
              <name>ID6</name>
              <description>GPIOA6 input data</description>
              <bitRange>[6:6]</bitRange>
              <access>read-only</access>
            </field>
            <field>
              <name>ID7</name>
              <description>GPIOA7 input data</description>
              <bitRange>[7:7]</bitRange>
              <access>read-only</access>
            </field>
            <field>
              <name>ID8</name>
              <description>GPIOA8 input data</description>
              <bitRange>[8:8]</bitRange>
              <access>read-only</access>
            </field>
            <field>
              <name>ID9</name>
              <description>GPIOA9 input data</description>
              <bitRange>[9:9]</bitRange>
              <access>read-only</access>
            </field>
            <field>
              <name>ID10</name>
              <description>GPIOA10 input data</description>
              <bitRange>[10:10]</bitRange>
              <access>read-only</access>
            </field>
            <field>
              <name>ID11</name>
              <description>GPIOA11 input data</description>
              <bitRange>[11:11]</bitRange>
              <access>read-only</access>
            </field>
            <field>
              <name>ID12</name>
              <description>GPIOA12 input data</description>
              <bitRange>[12:12]</bitRange>
              <access>read-only</access>
            </field>
            <field>
              <name>ID13</name>
              <description>GPIOA13 input data</description>
              <bitRange>[13:13]</bitRange>
              <access>read-only</access>
            </field>
            <field>
              <name>ID14</name>
              <description>GPIOA14 input data</description>
              <bitRange>[14:14]</bitRange>
              <access>read-only</access>
            </field>
            <field>
              <name>ID15</name>
              <description>GPIOA15 input data</description>
              <bitRange>[15:15]</bitRange>
              <access>read-only</access>
            </field>
          </fields>
        </register>
        <register>
          <name>ODR</name>
          <addressOffset>0x14</addressOffset>
          <fields>
            <field>
              <name>OD0</name>
              <description>GPIOA0 output data</description>
              <bitRange>[0:0]</bitRange>
            </field>
            <field>
              <name>OD1</name>
              <description>GPIOA1 output data</description>
              <bitRange>[1:1]</bitRange>
            </field>
            <field>
              <name>OD2</name>
              <description>GPIOA2 output data</description>
              <bitRange>[2:2]</bitRange>
            </field>
            <field>
              <name>OD3</name>
              <description>GPIOA3 output data</description>
              <bitRange>[3:3]</bitRange>
            </field>
            <field>
              <name>OD4</name>
              <description>GPIOA4 output data</description>
              <bitRange>[4:4]</bitRange>
            </field>
            <field>
              <name>OD5</name>
              <description>GPIOA5 output data</description>
              <bitRange>[5:5]</bitRange>
            </field>
            <field>
              <name>OD6</name>
              <description>GPIOA6 output data</description>
              <bitRange>[6:6]</bitRange>
            </field>
            <field>
              <name>OD7</name>
              <description>GPIOA7 output data</description>
              <bitRange>[7:7]</bitRange>
            </field>
            <field>
              <name>OD8</name>
              <description>GPIOA8 output data</description>
              <bitRange>[8:8]</bitRange>
            </field>
            <field>
              <name>OD9</name>
              <description>GPIOA9 output data</description>
              <bitRange>[9:9]</bitRange>
            </field>
            <field>
              <name>OD10</name>
              <description>GPIOA10 output data</description>
              <bitRange>[10:10]</bitRange>
            </field>
            <field>
              <name>OD11</name>
              <description>GPIOA11 output data</description>
              <bitRange>[11:11]</bitRange>
            </field>
            <field>
              <name>OD12</name>
              <description>GPIOA12 output data</description>
              <bitRange>[12:12]</bitRange>
            </field>
            <field>
              <name>OD13</name>
              <description>GPIOA13 output data</description>
              <bitRange>[13:13]</bitRange>
            </field>
            <field>
              <name>OD14</name>
              <description>GPIOA14 output data</description>
              <bitRange>[14:14]</bitRange>
            </field>
            <field>
              <name>OD15</name>
              <description>GPIOA15 output data</description>
              <bitRange>[15:15]</bitRange>
            </field>
          </fields>
        </register>
        <register>
          <name>BSRR</name>
          <addressOffset>0x18</addressOffset>
          <fields>
            <field>
              <name>BS0</name>
              <description>GPIOA0 output set</description>
              <bitRange>[0:0]</bitRange>
            </field>
            <field>
              <name>BS1</name>
              <description>GPIOA1 output set</description>
              <bitRange>[1:1]</bitRange>
            </field>
            <field>
              <name>BS2</name>
              <description>GPIOA2 output set</description>
              <bitRange>[2:2]</bitRange>
            </field>
            <field>
              <name>BS3</name>
              <description>GPIOA3 output set</description>
              <bitRange>[3:3]</bitRange>
            </field>
            <field>
              <name>BS4</name>
              <description>GPIOA4 output set</description>
              <bitRange>[4:4]</bitRange>
            </field>
            <field>
              <name>BS5</name>
              <description>GPIOA5 output set</description>
              <bitRange>[5:5]</bitRange>
            </field>
            <field>
              <name>BS6</name>
              <description>GPIOA6 output set</description>
              <bitRange>[6:6]</bitRange>
            </field>
            <field>
              <name>BS7</name>
              <description>GPIOA7 output set</description>
              <bitRange>[7:7]</bitRange>
            </field>
            <field>
              <name>BS8</name>
              <description>GPIOA8 output set</description>
              <bitRange>[8:8]</bitRange>
            </field>
            <field>
              <name>BS9</name>
              <description>GPIOA9 output set</description>
              <bitRange>[9:9]</bitRange>
            </field>
            <field>
              <name>BS10</name>
              <description>GPIOA10 output set</description>
              <bitRange>[10:10]</bitRange>
            </field>
            <field>
              <name>BS11</name>
              <description>GPIOA11 output set</description>
              <bitRange>[11:11]</bitRange>
            </field>
            <field>
              <name>BS12</name>
              <description>GPIOA12 output set</description>
              <bitRange>[12:12]</bitRange>
            </field>
            <field>
              <name>BS13</name>
              <description>GPIOA13 output set</description>
              <bitRange>[13:13]</bitRange>
            </field>
            <field>
              <name>BS14</name>
              <description>GPIOA14 output set</description>
              <bitRange>[14:14]</bitRange>
            </field>
            <field>
              <name>BS15</name>
              <description>GPIOA15 output set</description>
              <bitRange>[15:15]</bitRange>
            </field>
            <field>
              <name>BR0</name>
              <description>GPIOA0 outut reset</description>
              <bitRange>[16:16]</bitRange>
            </field>
            <field>
              <name>BR1</name>
              <description>GPIOA1 outut reset</description>
              <bitRange>[17:17]</bitRange>
            </field>
            <field>
              <name>BR2</name>
              <description>GPIOA2 outut reset</description>
              <bitRange>[18:18]</bitRange>
            </field>
            <field>
              <name>BR3</name>
              <description>GPIOA3 outut reset</description>
              <bitRange>[19:19]</bitRange>
            </field>
            <field>
              <name>BR4</name>
              <description>GPIOA4 outut reset</description>
              <bitRange>[20:20]</bitRange>
            </field>
            <field>
              <name>BR5</name>
              <description>GPIOA5 outut reset</description>
              <bitRange>[21:21]</bitRange>
            </field>
            <field>
              <name>BR6</name>
              <description>GPIOA6 outut reset</description>
              <bitRange>[22:22]</bitRange>
            </field>
            <field>
              <name>BR7</name>
              <description>GPIOA7 outut reset</description>
              <bitRange>[23:23]</bitRange>
            </field>
            <field>
              <name>BR8</name>
              <description>GPIOA8 outut reset</description>
              <bitRange>[24:24]</bitRange>
            </field>
            <field>
              <name>BR9</name>
              <description>GPIOA9 outut reset</description>
              <bitRange>[25:25]</bitRange>
            </field>
            <field>
              <name>BR10</name>
              <description>GPIOA10 outut reset</description>
              <bitRange>[26:26]</bitRange>
            </field>
            <field>
              <name>BR11</name>
              <description>GPIOA11 outut reset</description>
              <bitRange>[27:27]</bitRange>
            </field>
            <field>
              <name>BR12</name>
              <description>GPIOA12 outut reset</description>
              <bitRange>[28:28]</bitRange>
            </field>
            <field>
              <name>BR13</name>
              <description>GPIOA13 outut reset</description>
              <bitRange>[29:29]</bitRange>
            </field>
            <field>
              <name>BR14</name>
              <description>GPIOA14 outut reset</description>
              <bitRange>[30:30]</bitRange>
            </field>
            <field>
              <name>BR15</name>
              <description>GPIOA15 outut reset</description>
              <bitRange>[31:31]</bitRange>
            </field>
          </fields>
        </register>
        <register>
          <name>LCKR</name>
          <addressOffset>0x1C</addressOffset>
          <fields>
            <field>
              <name>LCK0</name>
              <description>GPIOA lock(bit0)</description>
              <bitRange>[0:0]</bitRange>
            </field>
            <field>
              <name>LCK1</name>
              <description>GPIOA lock(bit1)</description>
              <bitRange>[1:1]</bitRange>
            </field>
            <field>
              <name>LCK2</name>
              <description>GPIOA lock(bit2)</description>
              <bitRange>[2:2]</bitRange>
            </field>
            <field>
              <name>LCK3</name>
              <description>GPIOA lock(bit3)</description>
              <bitRange>[3:3]</bitRange>
            </field>
            <field>
              <name>LCK4</name>
              <description>GPIOA lock(bit4)</description>
              <bitRange>[4:4]</bitRange>
            </field>
            <field>
              <name>LCK5</name>
              <description>GPIOA lock(bit5)</description>
              <bitRange>[5:5]</bitRange>
            </field>
            <field>
              <name>LCK6</name>
              <description>GPIOA lock(bit6)</description>
              <bitRange>[6:6]</bitRange>
            </field>
            <field>
              <name>LCK7</name>
              <description>GPIOA lock(bit7)</description>
              <bitRange>[7:7]</bitRange>
            </field>
            <field>
              <name>LCK8</name>
              <description>GPIOA lock(bit8)</description>
              <bitRange>[8:8]</bitRange>
            </field>
            <field>
              <name>LCK9</name>
              <description>GPIOA lock(bit9)</description>
              <bitRange>[9:9]</bitRange>
            </field>
            <field>
              <name>LCK10</name>
              <description>GPIOA lock(bit10)</description>
              <bitRange>[10:10]</bitRange>
            </field>
            <field>
              <name>LCK11</name>
              <description>GPIOA lock(bit11)</description>
              <bitRange>[11:11]</bitRange>
            </field>
            <field>
              <name>LCK12</name>
              <description>GPIOA lock(bit12)</description>
              <bitRange>[12:12]</bitRange>
            </field>
            <field>
              <name>LCK13</name>
              <description>GPIOA lock(bit13)</description>
              <bitRange>[13:13]</bitRange>
            </field>
            <field>
              <name>LCK14</name>
              <description>GPIOA lock(bit14)</description>
              <bitRange>[14:14]</bitRange>
            </field>
            <field>
              <name>LCK15</name>
              <description>GPIOA lock(bit15)</description>
              <bitRange>[15:15]</bitRange>
            </field>
            <field>
              <name>LCKK</name>
              <description>GPIOA lock key</description>
              <bitRange>[16:16]</bitRange>
            </field>
          </fields>
        </register>
        <register>
          <name>AFRL</name>
          <addressOffset>0x20</addressOffset>
          <fields>
            <field>
              <name>AFSEL0</name>
              <description>GPIOA0 AF select</description>
              <bitRange>[3:0]</bitRange>
            </field>
            <field>
              <name>AFSEL1</name>
              <description>GPIOA1 AF select</description>
              <bitRange>[7:4]</bitRange>
            </field>
            <field>
              <name>AFSEL2</name>
              <description>GPIOA2 AF select</description>
              <bitRange>[11:8]</bitRange>
            </field>
            <field>
              <name>AFSEL3</name>
              <description>GPIOA3 AF select</description>
              <bitRange>[15:12]</bitRange>
            </field>
            <field>
              <name>AFSEL4</name>
              <description>GPIOA4 AF select</description>
              <bitRange>[19:16]</bitRange>
            </field>
            <field>
              <name>AFSEL5</name>
              <description>GPIOA5 AF select</description>
              <bitRange>[23:20]</bitRange>
            </field>
            <field>
              <name>AFSEL6</name>
              <description>GPIOA6 AF select</description>
              <bitRange>[27:24]</bitRange>
            </field>
            <field>
              <name>AFSEL7</name>
              <description>GPIOA7 AF select</description>
              <bitRange>[31:28]</bitRange>
            </field>
          </fields>
        </register>
        <register>
          <name>AFRH</name>
          <addressOffset>0x24</addressOffset>
          <fields>
            <field>
              <name>AFSEL8</name>
              <description>GPIOA8 AF select</description>
              <bitRange>[3:0]</bitRange>
            </field>
            <field>
              <name>AFSEL9</name>
              <description>GPIOA9 AF select</description>
              <bitRange>[7:4]</bitRange>
            </field>
            <field>
              <name>AFSEL10</name>
              <description>GPIOA10 AF select</description>
              <bitRange>[11:8]</bitRange>
            </field>
            <field>
              <name>AFSEL11</name>
              <description>GPIOA11 AF select</description>
              <bitRange>[15:12]</bitRange>
            </field>
            <field>
              <name>AFSEL12</name>
              <description>GPIOA12 AF select</description>
              <bitRange>[19:16]</bitRange>
            </field>
            <field>
              <name>AFSEL13</name>
              <description>GPIOA13 AF select</description>
              <bitRange>[23:20]</bitRange>
            </field>
            <field>
              <name>AFSEL14</name>
              <description>GPIOA14 AF select</description>
              <bitRange>[27:24]</bitRange>
            </field>
            <field>
              <name>AFSEL15</name>
              <description>GPIOA15 AF select</description>
              <bitRange>[31:28]</bitRange>
            </field>
          </fields>
        </register>
        <register>
          <name>BRR</name>
          <addressOffset>0x28</addressOffset>
          <fields>
            <field>
              <name>BR0</name>
              <description>GPIOA 0 output pin reset</description>
              <bitRange>[0:0]</bitRange>
            </field>
            <field>
              <name>BR1</name>
              <description>GPIOA 1 output pin reset</description>
              <bitRange>[1:1]</bitRange>
            </field>
            <field>
              <name>BR2</name>
              <description>GPIOA 2 output pin reset</description>
              <bitRange>[2:2]</bitRange>
            </field>
            <field>
              <name>BR3</name>
              <description>GPIOA 3 output pin reset</description>
              <bitRange>[3:3]</bitRange>
            </field>
            <field>
              <name>BR4</name>
              <description>GPIOA 4 output pin reset</description>
              <bitRange>[4:4]</bitRange>
            </field>
            <field>
              <name>BR5</name>
              <description>GPIOA 5 output pin reset</description>
              <bitRange>[5:5]</bitRange>
            </field>
            <field>
              <name>BR6</name>
              <description>GPIOA 6 output pin reset</description>
              <bitRange>[6:6]</bitRange>
            </field>
            <field>
              <name>BR7</name>
              <description>GPIOA 7 output pin reset</description>
              <bitRange>[7:7]</bitRange>
            </field>
            <field>
              <name>BR8</name>
              <description>GPIOA 8 output pin reset</description>
              <bitRange>[8:8]</bitRange>
            </field>
            <field>
              <name>BR9</name>
              <description>GPIOA 9 output pin reset</description>
              <bitRange>[9:9]</bitRange>
            </field>
            <field>
              <name>BR10</name>
              <description>GPIOA 10 output pin reset</description>
              <bitRange>[10:10]</bitRange>
            </field>
            <field>
              <name>BR11</name>
              <description>GPIOA 11 output pin reset</description>
              <bitRange>[11:11]</bitRange>
            </field>
            <field>
              <name>BR12</name>
              <description>GPIOA 12 output pin reset</description>
              <bitRange>[12:12]</bitRange>
            </field>
            <field>
              <name>BR13</name>
              <description>GPIOA 13 output pin reset</description>
              <bitRange>[13:13]</bitRange>
            </field>
            <field>
              <name>BR14</name>
              <description>GPIOA 14 output pin reset</description>
              <bitRange>[14:14]</bitRange>
            </field>
            <field>
              <name>BR15</name>
              <description>GPIOA 15 output pin reset</description>
              <bitRange>[15:15]</bitRange>
            </field>
          </fields>
        </register>
      </registers>
    </peripheral>
    <peripheral>
      <name>GPIOB</name>
      <baseAddress>0x48000400</baseAddress>
      <addressBlock>
        <offset>0x0</offset>
        <size>0x400</size>
        <usage>registers</usage>
      </addressBlock>
      <registers>
        <register>
          <name>MODER</name>
          <addressOffset>0x0</addressOffset>
          <fields>
            <field>
              <name>MODER0</name>
              <description>GPIOB0 MODE</description>
              <bitRange>[1:0]</bitRange>
            </field>
            <field>
              <name>MODER1</name>
              <description>GPIOB1 MODE</description>
              <bitRange>[3:2]</bitRange>
            </field>
            <field>
              <name>MODER2</name>
              <description>GPIOB2 MODE</description>
              <bitRange>[5:4]</bitRange>
            </field>
            <field>
              <name>MODER3</name>
              <description>GPIOB3 MODE</description>
              <bitRange>[7:6]</bitRange>
            </field>
            <field>
              <name>MODER4</name>
              <description>GPIOB4 MODE</description>
              <bitRange>[9:8]</bitRange>
            </field>
            <field>
              <name>MODER5</name>
              <description>GPIOB5 MODE</description>
              <bitRange>[11:10]</bitRange>
            </field>
            <field>
              <name>MODER6</name>
              <description>GPIOB6 MODE</description>
              <bitRange>[13:12]</bitRange>
            </field>
            <field>
              <name>MODER7</name>
              <description>GPIOB7 MODE</description>
              <bitRange>[15:14]</bitRange>
            </field>
            <field>
              <name>MODER8</name>
              <description>GPIOB8 MODE</description>
              <bitRange>[17:16]</bitRange>
            </field>
            <field>
              <name>MODER9</name>
              <description>GPIOB9 MODE</description>
              <bitRange>[19:18]</bitRange>
            </field>
            <field>
              <name>MODER10</name>
              <description>GPIOB10 MODE</description>
              <bitRange>[21:20]</bitRange>
            </field>
            <field>
              <name>MODER11</name>
              <description>GPIOB11 MODE</description>
              <bitRange>[23:22]</bitRange>
            </field>
            <field>
              <name>MODER12</name>
              <description>GPIOB12 MODE</description>
              <bitRange>[25:24]</bitRange>
            </field>
            <field>
              <name>MODER13</name>
              <description>GPIOB13 MODE</description>
              <bitRange>[27:26]</bitRange>
            </field>
            <field>
              <name>MODER14</name>
              <description>GPIOB14 MODE</description>
              <bitRange>[29:28]</bitRange>
            </field>
            <field>
              <name>MODER15</name>
              <description>GPIOB15 MODE</description>
              <bitRange>[31:30]</bitRange>
            </field>
          </fields>
        </register>
        <register>
          <name>OTYPER</name>
          <addressOffset>0x4</addressOffset>
          <fields>
            <field>
              <name>OT0</name>
              <description>GPIOB0 Output type</description>
              <bitRange>[0:0]</bitRange>
            </field>
            <field>
              <name>OT1</name>
              <description>GPIOB1 Output type</description>
              <bitRange>[1:1]</bitRange>
            </field>
            <field>
              <name>OT2</name>
              <description>GPIOB2 Output type</description>
              <bitRange>[2:2]</bitRange>
            </field>
            <field>
              <name>OT3</name>
              <description>GPIOB3 Output type</description>
              <bitRange>[3:3]</bitRange>
            </field>
            <field>
              <name>OT4</name>
              <description>GPIOB4 Output type</description>
              <bitRange>[4:4]</bitRange>
            </field>
            <field>
              <name>OT5</name>
              <description>GPIOB5 Output type</description>
              <bitRange>[5:5]</bitRange>
            </field>
            <field>
              <name>OT6</name>
              <description>GPIOB6 Output type</description>
              <bitRange>[6:6]</bitRange>
            </field>
            <field>
              <name>OT7</name>
              <description>GPIOB7 Output type</description>
              <bitRange>[7:7]</bitRange>
            </field>
            <field>
              <name>OT8</name>
              <description>GPIOB8 Output type</description>
              <bitRange>[8:8]</bitRange>
            </field>
            <field>
              <name>OT9</name>
              <description>GPIOB9 Output type</description>
              <bitRange>[9:9]</bitRange>
            </field>
            <field>
              <name>OT10</name>
              <description>GPIOB10 Output type</description>
              <bitRange>[10:10]</bitRange>
            </field>
            <field>
              <name>OT11</name>
              <description>GPIOB11 Output type</description>
              <bitRange>[11:11]</bitRange>
            </field>
            <field>
              <name>OT12</name>
              <description>GPIOB12 Output type</description>
              <bitRange>[12:12]</bitRange>
            </field>
            <field>
              <name>OT13</name>
              <description>GPIOB13 Output type</description>
              <bitRange>[13:13]</bitRange>
            </field>
            <field>
              <name>OT14</name>
              <description>GPIOB14 Output type</description>
              <bitRange>[14:14]</bitRange>
            </field>
            <field>
              <name>OT15</name>
              <description>GPIOB15 Output type</description>
              <bitRange>[15:15]</bitRange>
            </field>
          </fields>
        </register>
        <register>
          <name>OSPDDER</name>
          <addressOffset>0x8</addressOffset>
          <fields>
            <field>
              <name>OSPEED0</name>
              <description>GPIOB0 output speed</description>
              <bitRange>[1:0]</bitRange>
            </field>
            <field>
              <name>OSPEED1</name>
              <description>GPIOB1 output speed</description>
              <bitRange>[3:2]</bitRange>
            </field>
            <field>
              <name>OSPEED2</name>
              <description>GPIOB2 output speed</description>
              <bitRange>[5:4]</bitRange>
            </field>
            <field>
              <name>OSPEED3</name>
              <description>GPIOB3 output speed</description>
              <bitRange>[7:6]</bitRange>
            </field>
            <field>
              <name>OSPEED4</name>
              <description>GPIOB4 output speed</description>
              <bitRange>[9:8]</bitRange>
            </field>
            <field>
              <name>OSPEED5</name>
              <description>GPIOB5 output speed</description>
              <bitRange>[11:10]</bitRange>
            </field>
            <field>
              <name>OSPEED6</name>
              <description>GPIOB6 output speed</description>
              <bitRange>[13:12]</bitRange>
            </field>
            <field>
              <name>OSPEED7</name>
              <description>GPIOB7 output speed</description>
              <bitRange>[15:14]</bitRange>
            </field>
            <field>
              <name>OSPEED8</name>
              <description>GPIOB8 output speed</description>
              <bitRange>[17:16]</bitRange>
            </field>
            <field>
              <name>OSPEED9</name>
              <description>GPIOB9 output speed</description>
              <bitRange>[19:18]</bitRange>
            </field>
            <field>
              <name>OSPEED10</name>
              <description>GPIOB10 output speed</description>
              <bitRange>[21:20]</bitRange>
            </field>
            <field>
              <name>OSPEED11</name>
              <description>GPIOB11 output speed</description>
              <bitRange>[23:22]</bitRange>
            </field>
            <field>
              <name>OSPEED12</name>
              <description>GPIOB12 output speed</description>
              <bitRange>[25:24]</bitRange>
            </field>
            <field>
              <name>OSPEED13</name>
              <description>GPIOB13 output speed</description>
              <bitRange>[27:26]</bitRange>
            </field>
            <field>
              <name>OSPEED14</name>
              <description>GPIOB14 output speed</description>
              <bitRange>[29:28]</bitRange>
            </field>
            <field>
              <name>OSPEED15</name>
              <description>GPIOB15 output speed</description>
              <bitRange>[31:30]</bitRange>
            </field>
          </fields>
        </register>
        <register>
          <name>PUPDR</name>
          <addressOffset>0xC</addressOffset>
          <fields>
            <field>
              <name>PUPD0</name>
              <description>GPIOB0 pull up/pull down</description>
              <bitRange>[1:0]</bitRange>
            </field>
            <field>
              <name>PUPD1</name>
              <description>GPIOB1 pull up/pull down</description>
              <bitRange>[3:2]</bitRange>
            </field>
            <field>
              <name>PUPD2</name>
              <description>GPIOB2 pull up/pull down</description>
              <bitRange>[5:4]</bitRange>
            </field>
            <field>
              <name>PUPD3</name>
              <description>GPIOB3 pull up/pull down</description>
              <bitRange>[7:6]</bitRange>
            </field>
            <field>
              <name>PUPD4</name>
              <description>GPIOB4 pull up/pull down</description>
              <bitRange>[9:8]</bitRange>
            </field>
            <field>
              <name>PUPD5</name>
              <description>GPIOB5 pull up/pull down</description>
              <bitRange>[11:10]</bitRange>
            </field>
            <field>
              <name>PUPD6</name>
              <description>GPIOB6 pull up/pull down</description>
              <bitRange>[13:12]</bitRange>
            </field>
            <field>
              <name>PUPD7</name>
              <description>GPIOB7 pull up/pull down</description>
              <bitRange>[15:14]</bitRange>
            </field>
            <field>
              <name>PUPD8</name>
              <description>GPIOB8 pull up/pull down</description>
              <bitRange>[17:16]</bitRange>
            </field>
            <field>
              <name>PUPD9</name>
              <description>GPIOB9 pull up/pull down</description>
              <bitRange>[19:18]</bitRange>
            </field>
            <field>
              <name>PUPD10</name>
              <description>GPIOB10 pull up/pull down</description>
              <bitRange>[21:20]</bitRange>
            </field>
            <field>
              <name>PUPD11</name>
              <description>GPIOB11 pull up/pull down</description>
              <bitRange>[23:22]</bitRange>
            </field>
            <field>
              <name>PUPD12</name>
              <description>GPIOB12 pull up/pull down</description>
              <bitRange>[25:24]</bitRange>
            </field>
            <field>
              <name>PUPD13</name>
              <description>GPIOB13 pull up/pull down</description>
              <bitRange>[27:26]</bitRange>
            </field>
            <field>
              <name>PUPD14</name>
              <description>GPIOB14 pull up/pull down</description>
              <bitRange>[29:28]</bitRange>
            </field>
            <field>
              <name>PUPD15</name>
              <description>GPIOB15 pull up/pull down</description>
              <bitRange>[31:30]</bitRange>
            </field>
          </fields>
        </register>
        <register>
          <name>IDR</name>
          <addressOffset>0x10</addressOffset>
          <fields>
            <field>
              <name>ID0</name>
              <description>GPIOB0 input data</description>
              <bitRange>[0:0]</bitRange>
              <access>read-only</access>
            </field>
            <field>
              <name>ID1</name>
              <description>GPIOB1 input data</description>
              <bitRange>[1:1]</bitRange>
              <access>read-only</access>
            </field>
            <field>
              <name>ID2</name>
              <description>GPIOB2 input data</description>
              <bitRange>[2:2]</bitRange>
              <access>read-only</access>
            </field>
            <field>
              <name>ID3</name>
              <description>GPIOB3 input data</description>
              <bitRange>[3:3]</bitRange>
              <access>read-only</access>
            </field>
            <field>
              <name>ID4</name>
              <description>GPIOB4 input data</description>
              <bitRange>[4:4]</bitRange>
              <access>read-only</access>
            </field>
            <field>
              <name>ID5</name>
              <description>GPIOB5 input data</description>
              <bitRange>[5:5]</bitRange>
              <access>read-only</access>
            </field>
            <field>
              <name>ID6</name>
              <description>GPIOB6 input data</description>
              <bitRange>[6:6]</bitRange>
              <access>read-only</access>
            </field>
            <field>
              <name>ID7</name>
              <description>GPIOB7 input data</description>
              <bitRange>[7:7]</bitRange>
              <access>read-only</access>
            </field>
            <field>
              <name>ID8</name>
              <description>GPIOB8 input data</description>
              <bitRange>[8:8]</bitRange>
              <access>read-only</access>
            </field>
            <field>
              <name>ID9</name>
              <description>GPIOB9 input data</description>
              <bitRange>[9:9]</bitRange>
              <access>read-only</access>
            </field>
            <field>
              <name>ID10</name>
              <description>GPIOB10 input data</description>
              <bitRange>[10:10]</bitRange>
              <access>read-only</access>
            </field>
            <field>
              <name>ID11</name>
              <description>GPIOB11 input data</description>
              <bitRange>[11:11]</bitRange>
              <access>read-only</access>
            </field>
            <field>
              <name>ID12</name>
              <description>GPIOB12 input data</description>
              <bitRange>[12:12]</bitRange>
              <access>read-only</access>
            </field>
            <field>
              <name>ID13</name>
              <description>GPIOB13 input data</description>
              <bitRange>[13:13]</bitRange>
              <access>read-only</access>
            </field>
            <field>
              <name>ID14</name>
              <description>GPIOB14 input data</description>
              <bitRange>[14:14]</bitRange>
              <access>read-only</access>
            </field>
            <field>
              <name>ID15</name>
              <description>GPIOB15 input data</description>
              <bitRange>[15:15]</bitRange>
              <access>read-only</access>
            </field>
          </fields>
        </register>
        <register>
          <name>ODR</name>
          <addressOffset>0x14</addressOffset>
          <fields>
            <field>
              <name>OD0</name>
              <description>GPIOB0 output data</description>
              <bitRange>[0:0]</bitRange>
            </field>
            <field>
              <name>OD1</name>
              <description>GPIOB1 output data</description>
              <bitRange>[1:1]</bitRange>
            </field>
            <field>
              <name>OD2</name>
              <description>GPIOB2 output data</description>
              <bitRange>[2:2]</bitRange>
            </field>
            <field>
              <name>OD3</name>
              <description>GPIOB3 output data</description>
              <bitRange>[3:3]</bitRange>
            </field>
            <field>
              <name>OD4</name>
              <description>GPIOB4 output data</description>
              <bitRange>[4:4]</bitRange>
            </field>
            <field>
              <name>OD5</name>
              <description>GPIOB5 output data</description>
              <bitRange>[5:5]</bitRange>
            </field>
            <field>
              <name>OD6</name>
              <description>GPIOB6 output data</description>
              <bitRange>[6:6]</bitRange>
            </field>
            <field>
              <name>OD7</name>
              <description>GPIOB7 output data</description>
              <bitRange>[7:7]</bitRange>
            </field>
            <field>
              <name>OD8</name>
              <description>GPIOB8 output data</description>
              <bitRange>[8:8]</bitRange>
            </field>
            <field>
              <name>OD9</name>
              <description>GPIOB9 output data</description>
              <bitRange>[9:9]</bitRange>
            </field>
            <field>
              <name>OD10</name>
              <description>GPIOB10 output data</description>
              <bitRange>[10:10]</bitRange>
            </field>
            <field>
              <name>OD11</name>
              <description>GPIOB11 output data</description>
              <bitRange>[11:11]</bitRange>
            </field>
            <field>
              <name>OD12</name>
              <description>GPIOB12 output data</description>
              <bitRange>[12:12]</bitRange>
            </field>
            <field>
              <name>OD13</name>
              <description>GPIOB13 output data</description>
              <bitRange>[13:13]</bitRange>
            </field>
            <field>
              <name>OD14</name>
              <description>GPIOB14 output data</description>
              <bitRange>[14:14]</bitRange>
            </field>
            <field>
              <name>OD15</name>
              <description>GPIOB15 output data</description>
              <bitRange>[15:15]</bitRange>
            </field>
          </fields>
        </register>
        <register>
          <name>BSRR</name>
          <addressOffset>0x18</addressOffset>
          <fields>
            <field>
              <name>BS0</name>
              <description>GPIOB0 output set</description>
              <bitRange>[0:0]</bitRange>
            </field>
            <field>
              <name>BS1</name>
              <description>GPIOB1 output set</description>
              <bitRange>[1:1]</bitRange>
            </field>
            <field>
              <name>BS2</name>
              <description>GPIOB2 output set</description>
              <bitRange>[2:2]</bitRange>
            </field>
            <field>
              <name>BS3</name>
              <description>GPIOB3 output set</description>
              <bitRange>[3:3]</bitRange>
            </field>
            <field>
              <name>BS4</name>
              <description>GPIOB4 output set</description>
              <bitRange>[4:4]</bitRange>
            </field>
            <field>
              <name>BS5</name>
              <description>GPIOB5 output set</description>
              <bitRange>[5:5]</bitRange>
            </field>
            <field>
              <name>BS6</name>
              <description>GPIOB6 output set</description>
              <bitRange>[6:6]</bitRange>
            </field>
            <field>
              <name>BS7</name>
              <description>GPIOB7 output set</description>
              <bitRange>[7:7]</bitRange>
            </field>
            <field>
              <name>BS8</name>
              <description>GPIOB8 output set</description>
              <bitRange>[8:8]</bitRange>
            </field>
            <field>
              <name>BS9</name>
              <description>GPIOB9 output set</description>
              <bitRange>[9:9]</bitRange>
            </field>
            <field>
              <name>BS10</name>
              <description>GPIOB10 output set</description>
              <bitRange>[10:10]</bitRange>
            </field>
            <field>
              <name>BS11</name>
              <description>GPIOB11 output set</description>
              <bitRange>[11:11]</bitRange>
            </field>
            <field>
              <name>BS12</name>
              <description>GPIOB12 output set</description>
              <bitRange>[12:12]</bitRange>
            </field>
            <field>
              <name>BS13</name>
              <description>GPIOB13 output set</description>
              <bitRange>[13:13]</bitRange>
            </field>
            <field>
              <name>BS14</name>
              <description>GPIOB14 output set</description>
              <bitRange>[14:14]</bitRange>
            </field>
            <field>
              <name>BS15</name>
              <description>GPIOB15 output set</description>
              <bitRange>[15:15]</bitRange>
            </field>
            <field>
              <name>BR0</name>
              <description>GPIOB0 outut reset</description>
              <bitRange>[16:16]</bitRange>
            </field>
            <field>
              <name>BR1</name>
              <description>GPIOB1 outut reset</description>
              <bitRange>[17:17]</bitRange>
            </field>
            <field>
              <name>BR2</name>
              <description>GPIOB2 outut reset</description>
              <bitRange>[18:18]</bitRange>
            </field>
            <field>
              <name>BR3</name>
              <description>GPIOB3 outut reset</description>
              <bitRange>[19:19]</bitRange>
            </field>
            <field>
              <name>BR4</name>
              <description>GPIOB4 outut reset</description>
              <bitRange>[20:20]</bitRange>
            </field>
            <field>
              <name>BR5</name>
              <description>GPIOB5 outut reset</description>
              <bitRange>[21:21]</bitRange>
            </field>
            <field>
              <name>BR6</name>
              <description>GPIOB6 outut reset</description>
              <bitRange>[22:22]</bitRange>
            </field>
            <field>
              <name>BR7</name>
              <description>GPIOB7 outut reset</description>
              <bitRange>[23:23]</bitRange>
            </field>
            <field>
              <name>BR8</name>
              <description>GPIOB8 outut reset</description>
              <bitRange>[24:24]</bitRange>
            </field>
            <field>
              <name>BR9</name>
              <description>GPIOB9 outut reset</description>
              <bitRange>[25:25]</bitRange>
            </field>
            <field>
              <name>BR10</name>
              <description>GPIOB10 outut reset</description>
              <bitRange>[26:26]</bitRange>
            </field>
            <field>
              <name>BR11</name>
              <description>GPIOB11 outut reset</description>
              <bitRange>[27:27]</bitRange>
            </field>
            <field>
              <name>BR12</name>
              <description>GPIOB12 outut reset</description>
              <bitRange>[28:28]</bitRange>
            </field>
            <field>
              <name>BR13</name>
              <description>GPIOB13 outut reset</description>
              <bitRange>[29:29]</bitRange>
            </field>
            <field>
              <name>BR14</name>
              <description>GPIOB14 outut reset</description>
              <bitRange>[30:30]</bitRange>
            </field>
            <field>
              <name>BR15</name>
              <description>GPIOB15 outut reset</description>
              <bitRange>[31:31]</bitRange>
            </field>
          </fields>
        </register>
        <register>
          <name>LCKR</name>
          <addressOffset>0x1C</addressOffset>
          <fields>
            <field>
              <name>LCK0</name>
              <description>GPIOB lock(bit0)</description>
              <bitRange>[0:0]</bitRange>
            </field>
            <field>
              <name>LCK1</name>
              <description>GPIOB lock(bit1)</description>
              <bitRange>[1:1]</bitRange>
            </field>
            <field>
              <name>LCK2</name>
              <description>GPIOB lock(bit2)</description>
              <bitRange>[2:2]</bitRange>
            </field>
            <field>
              <name>LCK3</name>
              <description>GPIOB lock(bit3)</description>
              <bitRange>[3:3]</bitRange>
            </field>
            <field>
              <name>LCK4</name>
              <description>GPIOB lock(bit4)</description>
              <bitRange>[4:4]</bitRange>
            </field>
            <field>
              <name>LCK5</name>
              <description>GPIOB lock(bit5)</description>
              <bitRange>[5:5]</bitRange>
            </field>
            <field>
              <name>LCK6</name>
              <description>GPIOB lock(bit6)</description>
              <bitRange>[6:6]</bitRange>
            </field>
            <field>
              <name>LCK7</name>
              <description>GPIOB lock(bit7)</description>
              <bitRange>[7:7]</bitRange>
            </field>
            <field>
              <name>LCK8</name>
              <description>GPIOB lock(bit8)</description>
              <bitRange>[8:8]</bitRange>
            </field>
            <field>
              <name>LCK9</name>
              <description>GPIOB lock(bit9)</description>
              <bitRange>[9:9]</bitRange>
            </field>
            <field>
              <name>LCK10</name>
              <description>GPIOB lock(bit10)</description>
              <bitRange>[10:10]</bitRange>
            </field>
            <field>
              <name>LCK11</name>
              <description>GPIOB lock(bit11)</description>
              <bitRange>[11:11]</bitRange>
            </field>
            <field>
              <name>LCK12</name>
              <description>GPIOB lock(bit12)</description>
              <bitRange>[12:12]</bitRange>
            </field>
            <field>
              <name>LCK13</name>
              <description>GPIOB lock(bit13)</description>
              <bitRange>[13:13]</bitRange>
            </field>
            <field>
              <name>LCK14</name>
              <description>GPIOB lock(bit14)</description>
              <bitRange>[14:14]</bitRange>
            </field>
            <field>
              <name>LCK15</name>
              <description>GPIOB lock(bit15)</description>
              <bitRange>[15:15]</bitRange>
            </field>
            <field>
              <name>LCKK</name>
              <description>GPIOB lock key</description>
              <bitRange>[16:16]</bitRange>
            </field>
          </fields>
        </register>
        <register>
          <name>AFRL</name>
          <addressOffset>0x20</addressOffset>
          <fields>
            <field>
              <name>AFSEL0</name>
              <description>GPIOB0 AF select</description>
              <bitRange>[3:0]</bitRange>
            </field>
            <field>
              <name>AFSEL1</name>
              <description>GPIOB1 AF select</description>
              <bitRange>[7:4]</bitRange>
            </field>
            <field>
              <name>AFSEL2</name>
              <description>GPIOB2 AF select</description>
              <bitRange>[11:8]</bitRange>
            </field>
            <field>
              <name>AFSEL3</name>
              <description>GPIOB3 AF select</description>
              <bitRange>[15:12]</bitRange>
            </field>
            <field>
              <name>AFSEL4</name>
              <description>GPIOB4 AF select</description>
              <bitRange>[19:16]</bitRange>
            </field>
            <field>
              <name>AFSEL5</name>
              <description>GPIOB5 AF select</description>
              <bitRange>[23:20]</bitRange>
            </field>
            <field>
              <name>AFSEL6</name>
              <description>GPIOB6 AF select</description>
              <bitRange>[27:24]</bitRange>
            </field>
            <field>
              <name>AFSEL7</name>
              <description>GPIOB7 AF select</description>
              <bitRange>[31:28]</bitRange>
            </field>
          </fields>
        </register>
        <register>
          <name>AFRH</name>
          <addressOffset>0x24</addressOffset>
          <fields>
            <field>
              <name>AFSEL8</name>
              <description>GPIOB8 AF select</description>
              <bitRange>[3:0]</bitRange>
            </field>
            <field>
              <name>AFSEL9</name>
              <description>GPIOB9 AF select</description>
              <bitRange>[7:4]</bitRange>
            </field>
            <field>
              <name>AFSEL10</name>
              <description>GPIOB10 AF select</description>
              <bitRange>[11:8]</bitRange>
            </field>
            <field>
              <name>AFSEL11</name>
              <description>GPIOB11 AF select</description>
              <bitRange>[15:12]</bitRange>
            </field>
            <field>
              <name>AFSEL12</name>
              <description>GPIOB12 AF select</description>
              <bitRange>[19:16]</bitRange>
            </field>
            <field>
              <name>AFSEL13</name>
              <description>GPIOB13 AF select</description>
              <bitRange>[23:20]</bitRange>
            </field>
            <field>
              <name>AFSEL14</name>
              <description>GPIOB14 AF select</description>
              <bitRange>[27:24]</bitRange>
            </field>
            <field>
              <name>AFSEL15</name>
              <description>GPIOB15 AF select</description>
              <bitRange>[31:28]</bitRange>
            </field>
          </fields>
        </register>
        <register>
          <name>BRR</name>
          <addressOffset>0x28</addressOffset>
          <fields>
            <field>
              <name>BR0</name>
              <description>GPIOB 0 output pin reset</description>
              <bitRange>[0:0]</bitRange>
            </field>
            <field>
              <name>BR1</name>
              <description>GPIOB 1 output pin reset</description>
              <bitRange>[1:1]</bitRange>
            </field>
            <field>
              <name>BR2</name>
              <description>GPIOB 2 output pin reset</description>
              <bitRange>[2:2]</bitRange>
            </field>
            <field>
              <name>BR3</name>
              <description>GPIOB 3 output pin reset</description>
              <bitRange>[3:3]</bitRange>
            </field>
            <field>
              <name>BR4</name>
              <description>GPIOB 4 output pin reset</description>
              <bitRange>[4:4]</bitRange>
            </field>
            <field>
              <name>BR5</name>
              <description>GPIOB 5 output pin reset</description>
              <bitRange>[5:5]</bitRange>
            </field>
            <field>
              <name>BR6</name>
              <description>GPIOB 6 output pin reset</description>
              <bitRange>[6:6]</bitRange>
            </field>
            <field>
              <name>BR7</name>
              <description>GPIOB 7 output pin reset</description>
              <bitRange>[7:7]</bitRange>
            </field>
            <field>
              <name>BR8</name>
              <description>GPIOB 8 output pin reset</description>
              <bitRange>[8:8]</bitRange>
            </field>
            <field>
              <name>BR9</name>
              <description>GPIOB 9 output pin reset</description>
              <bitRange>[9:9]</bitRange>
            </field>
            <field>
              <name>BR10</name>
              <description>GPIOB 10 output pin reset</description>
              <bitRange>[10:10]</bitRange>
            </field>
            <field>
              <name>BR11</name>
              <description>GPIOB 11 output pin reset</description>
              <bitRange>[11:11]</bitRange>
            </field>
            <field>
              <name>BR12</name>
              <description>GPIOB 12 output pin reset</description>
              <bitRange>[12:12]</bitRange>
            </field>
            <field>
              <name>BR13</name>
              <description>GPIOB 13 output pin reset</description>
              <bitRange>[13:13]</bitRange>
            </field>
            <field>
              <name>BR14</name>
              <description>GPIOB 14 output pin reset</description>
              <bitRange>[14:14]</bitRange>
            </field>
            <field>
              <name>BR15</name>
              <description>GPIOB 15 output pin reset</description>
              <bitRange>[15:15]</bitRange>
            </field>
          </fields>
        </register>
      </registers>
    </peripheral>
    <peripheral>
      <name>GPIOC</name>
      <baseAddress>0x48000800</baseAddress>
      <addressBlock>
        <offset>0x0</offset>
        <size>0x400</size>
        <usage>registers</usage>
      </addressBlock>
      <registers>
        <register>
          <name>MODER</name>
          <addressOffset>0x0</addressOffset>
          <fields>
            <field>
              <name>MODER0</name>
              <description>GPIOC0 MODE</description>
              <bitRange>[1:0]</bitRange>
            </field>
            <field>
              <name>MODER1</name>
              <description>GPIOC1 MODE</description>
              <bitRange>[3:2]</bitRange>
            </field>
            <field>
              <name>MODER2</name>
              <description>GPIOC2 MODE</description>
              <bitRange>[5:4]</bitRange>
            </field>
            <field>
              <name>MODER3</name>
              <description>GPIOC3 MODE</description>
              <bitRange>[7:6]</bitRange>
            </field>
            <field>
              <name>MODER4</name>
              <description>GPIOC4 MODE</description>
              <bitRange>[9:8]</bitRange>
            </field>
            <field>
              <name>MODER5</name>
              <description>GPIOC5 MODE</description>
              <bitRange>[11:10]</bitRange>
            </field>
            <field>
              <name>MODER6</name>
              <description>GPIOC6 MODE</description>
              <bitRange>[13:12]</bitRange>
            </field>
            <field>
              <name>MODER7</name>
              <description>GPIOC7 MODE</description>
              <bitRange>[15:14]</bitRange>
            </field>
            <field>
              <name>MODER8</name>
              <description>GPIOC8 MODE</description>
              <bitRange>[17:16]</bitRange>
            </field>
            <field>
              <name>MODER9</name>
              <description>GPIOC9 MODE</description>
              <bitRange>[19:18]</bitRange>
            </field>
            <field>
              <name>MODER10</name>
              <description>GPIOC10 MODE</description>
              <bitRange>[21:20]</bitRange>
            </field>
            <field>
              <name>MODER11</name>
              <description>GPIOC11 MODE</description>
              <bitRange>[23:22]</bitRange>
            </field>
            <field>
              <name>MODER12</name>
              <description>GPIOC12 MODE</description>
              <bitRange>[25:24]</bitRange>
            </field>
            <field>
              <name>MODER13</name>
              <description>GPIOC13 MODE</description>
              <bitRange>[27:26]</bitRange>
            </field>
            <field>
              <name>MODER14</name>
              <description>GPIOC14 MODE</description>
              <bitRange>[29:28]</bitRange>
            </field>
            <field>
              <name>MODER15</name>
              <description>GPIOC15 MODE</description>
              <bitRange>[31:30]</bitRange>
            </field>
          </fields>
        </register>
        <register>
          <name>OTYPER</name>
          <addressOffset>0x4</addressOffset>
          <fields>
            <field>
              <name>OT0</name>
              <description>GPIOC0 Output type</description>
              <bitRange>[0:0]</bitRange>
            </field>
            <field>
              <name>OT1</name>
              <description>GPIOC1 Output type</description>
              <bitRange>[1:1]</bitRange>
            </field>
            <field>
              <name>OT2</name>
              <description>GPIOC2 Output type</description>
              <bitRange>[2:2]</bitRange>
            </field>
            <field>
              <name>OT3</name>
              <description>GPIOC3 Output type</description>
              <bitRange>[3:3]</bitRange>
            </field>
            <field>
              <name>OT4</name>
              <description>GPIOC4 Output type</description>
              <bitRange>[4:4]</bitRange>
            </field>
            <field>
              <name>OT5</name>
              <description>GPIOC5 Output type</description>
              <bitRange>[5:5]</bitRange>
            </field>
            <field>
              <name>OT6</name>
              <description>GPIOC6 Output type</description>
              <bitRange>[6:6]</bitRange>
            </field>
            <field>
              <name>OT7</name>
              <description>GPIOC7 Output type</description>
              <bitRange>[7:7]</bitRange>
            </field>
            <field>
              <name>OT8</name>
              <description>GPIOC8 Output type</description>
              <bitRange>[8:8]</bitRange>
            </field>
            <field>
              <name>OT9</name>
              <description>GPIOC9 Output type</description>
              <bitRange>[9:9]</bitRange>
            </field>
            <field>
              <name>OT10</name>
              <description>GPIOC10 Output type</description>
              <bitRange>[10:10]</bitRange>
            </field>
            <field>
              <name>OT11</name>
              <description>GPIOC11 Output type</description>
              <bitRange>[11:11]</bitRange>
            </field>
            <field>
              <name>OT12</name>
              <description>GPIOC12 Output type</description>
              <bitRange>[12:12]</bitRange>
            </field>
            <field>
              <name>OT13</name>
              <description>GPIOC13 Output type</description>
              <bitRange>[13:13]</bitRange>
            </field>
            <field>
              <name>OT14</name>
              <description>GPIOC14 Output type</description>
              <bitRange>[14:14]</bitRange>
            </field>
            <field>
              <name>OT15</name>
              <description>GPIOC15 Output type</description>
              <bitRange>[15:15]</bitRange>
            </field>
          </fields>
        </register>
        <register>
          <name>OSPDDER</name>
          <addressOffset>0x8</addressOffset>
          <fields>
            <field>
              <name>OSPEED0</name>
              <description>GPIOC0 output speed</description>
              <bitRange>[1:0]</bitRange>
            </field>
            <field>
              <name>OSPEED1</name>
              <description>GPIOC1 output speed</description>
              <bitRange>[3:2]</bitRange>
            </field>
            <field>
              <name>OSPEED2</name>
              <description>GPIOC2 output speed</description>
              <bitRange>[5:4]</bitRange>
            </field>
            <field>
              <name>OSPEED3</name>
              <description>GPIOC3 output speed</description>
              <bitRange>[7:6]</bitRange>
            </field>
            <field>
              <name>OSPEED4</name>
              <description>GPIOC4 output speed</description>
              <bitRange>[9:8]</bitRange>
            </field>
            <field>
              <name>OSPEED5</name>
              <description>GPIOC5 output speed</description>
              <bitRange>[11:10]</bitRange>
            </field>
            <field>
              <name>OSPEED6</name>
              <description>GPIOC6 output speed</description>
              <bitRange>[13:12]</bitRange>
            </field>
            <field>
              <name>OSPEED7</name>
              <description>GPIOC7 output speed</description>
              <bitRange>[15:14]</bitRange>
            </field>
            <field>
              <name>OSPEED8</name>
              <description>GPIOC8 output speed</description>
              <bitRange>[17:16]</bitRange>
            </field>
            <field>
              <name>OSPEED9</name>
              <description>GPIOC9 output speed</description>
              <bitRange>[19:18]</bitRange>
            </field>
            <field>
              <name>OSPEED10</name>
              <description>GPIOC10 output speed</description>
              <bitRange>[21:20]</bitRange>
            </field>
            <field>
              <name>OSPEED11</name>
              <description>GPIOC11 output speed</description>
              <bitRange>[23:22]</bitRange>
            </field>
            <field>
              <name>OSPEED12</name>
              <description>GPIOC12 output speed</description>
              <bitRange>[25:24]</bitRange>
            </field>
            <field>
              <name>OSPEED13</name>
              <description>GPIOC13 output speed</description>
              <bitRange>[27:26]</bitRange>
            </field>
            <field>
              <name>OSPEED14</name>
              <description>GPIOC14 output speed</description>
              <bitRange>[29:28]</bitRange>
            </field>
            <field>
              <name>OSPEED15</name>
              <description>GPIOC15 output speed</description>
              <bitRange>[31:30]</bitRange>
            </field>
          </fields>
        </register>
        <register>
          <name>PUPDR</name>
          <addressOffset>0xC</addressOffset>
          <fields>
            <field>
              <name>PUPD0</name>
              <description>GPIOC0 pull up/pull down</description>
              <bitRange>[1:0]</bitRange>
            </field>
            <field>
              <name>PUPD1</name>
              <description>GPIOC1 pull up/pull down</description>
              <bitRange>[3:2]</bitRange>
            </field>
            <field>
              <name>PUPD2</name>
              <description>GPIOC2 pull up/pull down</description>
              <bitRange>[5:4]</bitRange>
            </field>
            <field>
              <name>PUPD3</name>
              <description>GPIOC3 pull up/pull down</description>
              <bitRange>[7:6]</bitRange>
            </field>
            <field>
              <name>PUPD4</name>
              <description>GPIOC4 pull up/pull down</description>
              <bitRange>[9:8]</bitRange>
            </field>
            <field>
              <name>PUPD5</name>
              <description>GPIOC5 pull up/pull down</description>
              <bitRange>[11:10]</bitRange>
            </field>
            <field>
              <name>PUPD6</name>
              <description>GPIOC6 pull up/pull down</description>
              <bitRange>[13:12]</bitRange>
            </field>
            <field>
              <name>PUPD7</name>
              <description>GPIOC7 pull up/pull down</description>
              <bitRange>[15:14]</bitRange>
            </field>
            <field>
              <name>PUPD8</name>
              <description>GPIOC8 pull up/pull down</description>
              <bitRange>[17:16]</bitRange>
            </field>
            <field>
              <name>PUPD9</name>
              <description>GPIOC9 pull up/pull down</description>
              <bitRange>[19:18]</bitRange>
            </field>
            <field>
              <name>PUPD10</name>
              <description>GPIOC10 pull up/pull down</description>
              <bitRange>[21:20]</bitRange>
            </field>
            <field>
              <name>PUPD11</name>
              <description>GPIOC11 pull up/pull down</description>
              <bitRange>[23:22]</bitRange>
            </field>
            <field>
              <name>PUPD12</name>
              <description>GPIOC12 pull up/pull down</description>
              <bitRange>[25:24]</bitRange>
            </field>
            <field>
              <name>PUPD13</name>
              <description>GPIOC13 pull up/pull down</description>
              <bitRange>[27:26]</bitRange>
            </field>
            <field>
              <name>PUPD14</name>
              <description>GPIOC14 pull up/pull down</description>
              <bitRange>[29:28]</bitRange>
            </field>
            <field>
              <name>PUPD15</name>
              <description>GPIOC15 pull up/pull down</description>
              <bitRange>[31:30]</bitRange>
            </field>
          </fields>
        </register>
        <register>
          <name>IDR</name>
          <addressOffset>0x10</addressOffset>
          <fields>
            <field>
              <name>ID0</name>
              <description>GPIOC0 input data</description>
              <bitRange>[0:0]</bitRange>
              <access>read-only</access>
            </field>
            <field>
              <name>ID1</name>
              <description>GPIOC1 input data</description>
              <bitRange>[1:1]</bitRange>
              <access>read-only</access>
            </field>
            <field>
              <name>ID2</name>
              <description>GPIOC2 input data</description>
              <bitRange>[2:2]</bitRange>
              <access>read-only</access>
            </field>
            <field>
              <name>ID3</name>
              <description>GPIOC3 input data</description>
              <bitRange>[3:3]</bitRange>
              <access>read-only</access>
            </field>
            <field>
              <name>ID4</name>
              <description>GPIOC4 input data</description>
              <bitRange>[4:4]</bitRange>
              <access>read-only</access>
            </field>
            <field>
              <name>ID5</name>
              <description>GPIOC5 input data</description>
              <bitRange>[5:5]</bitRange>
              <access>read-only</access>
            </field>
            <field>
              <name>ID6</name>
              <description>GPIOC6 input data</description>
              <bitRange>[6:6]</bitRange>
              <access>read-only</access>
            </field>
            <field>
              <name>ID7</name>
              <description>GPIOC7 input data</description>
              <bitRange>[7:7]</bitRange>
              <access>read-only</access>
            </field>
            <field>
              <name>ID8</name>
              <description>GPIOC8 input data</description>
              <bitRange>[8:8]</bitRange>
              <access>read-only</access>
            </field>
            <field>
              <name>ID9</name>
              <description>GPIOC9 input data</description>
              <bitRange>[9:9]</bitRange>
              <access>read-only</access>
            </field>
            <field>
              <name>ID10</name>
              <description>GPIOC10 input data</description>
              <bitRange>[10:10]</bitRange>
              <access>read-only</access>
            </field>
            <field>
              <name>ID11</name>
              <description>GPIOC11 input data</description>
              <bitRange>[11:11]</bitRange>
              <access>read-only</access>
            </field>
            <field>
              <name>ID12</name>
              <description>GPIOC12 input data</description>
              <bitRange>[12:12]</bitRange>
              <access>read-only</access>
            </field>
            <field>
              <name>ID13</name>
              <description>GPIOC13 input data</description>
              <bitRange>[13:13]</bitRange>
              <access>read-only</access>
            </field>
            <field>
              <name>ID14</name>
              <description>GPIOC14 input data</description>
              <bitRange>[14:14]</bitRange>
              <access>read-only</access>
            </field>
            <field>
              <name>ID15</name>
              <description>GPIOC15 input data</description>
              <bitRange>[15:15]</bitRange>
              <access>read-only</access>
            </field>
          </fields>
        </register>
        <register>
          <name>ODR</name>
          <addressOffset>0x14</addressOffset>
          <fields>
            <field>
              <name>OD0</name>
              <description>GPIOC0 output data</description>
              <bitRange>[0:0]</bitRange>
            </field>
            <field>
              <name>OD1</name>
              <description>GPIOC1 output data</description>
              <bitRange>[1:1]</bitRange>
            </field>
            <field>
              <name>OD2</name>
              <description>GPIOC2 output data</description>
              <bitRange>[2:2]</bitRange>
            </field>
            <field>
              <name>OD3</name>
              <description>GPIOC3 output data</description>
              <bitRange>[3:3]</bitRange>
            </field>
            <field>
              <name>OD4</name>
              <description>GPIOC4 output data</description>
              <bitRange>[4:4]</bitRange>
            </field>
            <field>
              <name>OD5</name>
              <description>GPIOC5 output data</description>
              <bitRange>[5:5]</bitRange>
            </field>
            <field>
              <name>OD6</name>
              <description>GPIOC6 output data</description>
              <bitRange>[6:6]</bitRange>
            </field>
            <field>
              <name>OD7</name>
              <description>GPIOC7 output data</description>
              <bitRange>[7:7]</bitRange>
            </field>
            <field>
              <name>OD8</name>
              <description>GPIOC8 output data</description>
              <bitRange>[8:8]</bitRange>
            </field>
            <field>
              <name>OD9</name>
              <description>GPIOC9 output data</description>
              <bitRange>[9:9]</bitRange>
            </field>
            <field>
              <name>OD10</name>
              <description>GPIOC10 output data</description>
              <bitRange>[10:10]</bitRange>
            </field>
            <field>
              <name>OD11</name>
              <description>GPIOC11 output data</description>
              <bitRange>[11:11]</bitRange>
            </field>
            <field>
              <name>OD12</name>
              <description>GPIOC12 output data</description>
              <bitRange>[12:12]</bitRange>
            </field>
            <field>
              <name>OD13</name>
              <description>GPIOC13 output data</description>
              <bitRange>[13:13]</bitRange>
            </field>
            <field>
              <name>OD14</name>
              <description>GPIOC14 output data</description>
              <bitRange>[14:14]</bitRange>
            </field>
            <field>
              <name>OD15</name>
              <description>GPIOC15 output data</description>
              <bitRange>[15:15]</bitRange>
            </field>
          </fields>
        </register>
        <register>
          <name>BSRR</name>
          <addressOffset>0x18</addressOffset>
          <fields>
            <field>
              <name>BS0</name>
              <description>GPIOC0 output set</description>
              <bitRange>[0:0]</bitRange>
            </field>
            <field>
              <name>BS1</name>
              <description>GPIOC1 output set</description>
              <bitRange>[1:1]</bitRange>
            </field>
            <field>
              <name>BS2</name>
              <description>GPIOC2 output set</description>
              <bitRange>[2:2]</bitRange>
            </field>
            <field>
              <name>BS3</name>
              <description>GPIOC3 output set</description>
              <bitRange>[3:3]</bitRange>
            </field>
            <field>
              <name>BS4</name>
              <description>GPIOC4 output set</description>
              <bitRange>[4:4]</bitRange>
            </field>
            <field>
              <name>BS5</name>
              <description>GPIOC5 output set</description>
              <bitRange>[5:5]</bitRange>
            </field>
            <field>
              <name>BS6</name>
              <description>GPIOC6 output set</description>
              <bitRange>[6:6]</bitRange>
            </field>
            <field>
              <name>BS7</name>
              <description>GPIOC7 output set</description>
              <bitRange>[7:7]</bitRange>
            </field>
            <field>
              <name>BS8</name>
              <description>GPIOC8 output set</description>
              <bitRange>[8:8]</bitRange>
            </field>
            <field>
              <name>BS9</name>
              <description>GPIOC9 output set</description>
              <bitRange>[9:9]</bitRange>
            </field>
            <field>
              <name>BS10</name>
              <description>GPIOC10 output set</description>
              <bitRange>[10:10]</bitRange>
            </field>
            <field>
              <name>BS11</name>
              <description>GPIOC11 output set</description>
              <bitRange>[11:11]</bitRange>
            </field>
            <field>
              <name>BS12</name>
              <description>GPIOC12 output set</description>
              <bitRange>[12:12]</bitRange>
            </field>
            <field>
              <name>BS13</name>
              <description>GPIOC13 output set</description>
              <bitRange>[13:13]</bitRange>
            </field>
            <field>
              <name>BS14</name>
              <description>GPIOC14 output set</description>
              <bitRange>[14:14]</bitRange>
            </field>
            <field>
              <name>BS15</name>
              <description>GPIOC15 output set</description>
              <bitRange>[15:15]</bitRange>
            </field>
            <field>
              <name>BR0</name>
              <description>GPIOC0 outut reset</description>
              <bitRange>[16:16]</bitRange>
            </field>
            <field>
              <name>BR1</name>
              <description>GPIOC1 outut reset</description>
              <bitRange>[17:17]</bitRange>
            </field>
            <field>
              <name>BR2</name>
              <description>GPIOC2 outut reset</description>
              <bitRange>[18:18]</bitRange>
            </field>
            <field>
              <name>BR3</name>
              <description>GPIOC3 outut reset</description>
              <bitRange>[19:19]</bitRange>
            </field>
            <field>
              <name>BR4</name>
              <description>GPIOC4 outut reset</description>
              <bitRange>[20:20]</bitRange>
            </field>
            <field>
              <name>BR5</name>
              <description>GPIOC5 outut reset</description>
              <bitRange>[21:21]</bitRange>
            </field>
            <field>
              <name>BR6</name>
              <description>GPIOC6 outut reset</description>
              <bitRange>[22:22]</bitRange>
            </field>
            <field>
              <name>BR7</name>
              <description>GPIOC7 outut reset</description>
              <bitRange>[23:23]</bitRange>
            </field>
            <field>
              <name>BR8</name>
              <description>GPIOC8 outut reset</description>
              <bitRange>[24:24]</bitRange>
            </field>
            <field>
              <name>BR9</name>
              <description>GPIOC9 outut reset</description>
              <bitRange>[25:25]</bitRange>
            </field>
            <field>
              <name>BR10</name>
              <description>GPIOC10 outut reset</description>
              <bitRange>[26:26]</bitRange>
            </field>
            <field>
              <name>BR11</name>
              <description>GPIOC11 outut reset</description>
              <bitRange>[27:27]</bitRange>
            </field>
            <field>
              <name>BR12</name>
              <description>GPIOC12 outut reset</description>
              <bitRange>[28:28]</bitRange>
            </field>
            <field>
              <name>BR13</name>
              <description>GPIOC13 outut reset</description>
              <bitRange>[29:29]</bitRange>
            </field>
            <field>
              <name>BR14</name>
              <description>GPIOC14 outut reset</description>
              <bitRange>[30:30]</bitRange>
            </field>
            <field>
              <name>BR15</name>
              <description>GPIOC15 outut reset</description>
              <bitRange>[31:31]</bitRange>
            </field>
          </fields>
        </register>
        <register>
          <name>LCKR</name>
          <addressOffset>0x1C</addressOffset>
          <fields>
            <field>
              <name>LCK0</name>
              <description>GPIOC lock(bit0)</description>
              <bitRange>[0:0]</bitRange>
            </field>
            <field>
              <name>LCK1</name>
              <description>GPIOC lock(bit1)</description>
              <bitRange>[1:1]</bitRange>
            </field>
            <field>
              <name>LCK2</name>
              <description>GPIOC lock(bit2)</description>
              <bitRange>[2:2]</bitRange>
            </field>
            <field>
              <name>LCK3</name>
              <description>GPIOC lock(bit3)</description>
              <bitRange>[3:3]</bitRange>
            </field>
            <field>
              <name>LCK4</name>
              <description>GPIOC lock(bit4)</description>
              <bitRange>[4:4]</bitRange>
            </field>
            <field>
              <name>LCK5</name>
              <description>GPIOC lock(bit5)</description>
              <bitRange>[5:5]</bitRange>
            </field>
            <field>
              <name>LCK6</name>
              <description>GPIOC lock(bit6)</description>
              <bitRange>[6:6]</bitRange>
            </field>
            <field>
              <name>LCK7</name>
              <description>GPIOC lock(bit7)</description>
              <bitRange>[7:7]</bitRange>
            </field>
            <field>
              <name>LCK8</name>
              <description>GPIOC lock(bit8)</description>
              <bitRange>[8:8]</bitRange>
            </field>
            <field>
              <name>LCK9</name>
              <description>GPIOC lock(bit9)</description>
              <bitRange>[9:9]</bitRange>
            </field>
            <field>
              <name>LCK10</name>
              <description>GPIOC lock(bit10)</description>
              <bitRange>[10:10]</bitRange>
            </field>
            <field>
              <name>LCK11</name>
              <description>GPIOC lock(bit11)</description>
              <bitRange>[11:11]</bitRange>
            </field>
            <field>
              <name>LCK12</name>
              <description>GPIOC lock(bit12)</description>
              <bitRange>[12:12]</bitRange>
            </field>
            <field>
              <name>LCK13</name>
              <description>GPIOC lock(bit13)</description>
              <bitRange>[13:13]</bitRange>
            </field>
            <field>
              <name>LCK14</name>
              <description>GPIOC lock(bit14)</description>
              <bitRange>[14:14]</bitRange>
            </field>
            <field>
              <name>LCK15</name>
              <description>GPIOC lock(bit15)</description>
              <bitRange>[15:15]</bitRange>
            </field>
            <field>
              <name>LCKK</name>
              <description>GPIOC lock key</description>
              <bitRange>[16:16]</bitRange>
            </field>
          </fields>
        </register>
        <register>
          <name>AFRL</name>
          <addressOffset>0x20</addressOffset>
          <fields>
            <field>
              <name>AFSEL0</name>
              <description>GPIOC0 AF select</description>
              <bitRange>[3:0]</bitRange>
            </field>
            <field>
              <name>AFSEL1</name>
              <description>GPIOC1 AF select</description>
              <bitRange>[7:4]</bitRange>
            </field>
            <field>
              <name>AFSEL2</name>
              <description>GPIOC2 AF select</description>
              <bitRange>[11:8]</bitRange>
            </field>
            <field>
              <name>AFSEL3</name>
              <description>GPIOC3 AF select</description>
              <bitRange>[15:12]</bitRange>
            </field>
            <field>
              <name>AFSEL4</name>
              <description>GPIOC4 AF select</description>
              <bitRange>[19:16]</bitRange>
            </field>
            <field>
              <name>AFSEL5</name>
              <description>GPIOC5 AF select</description>
              <bitRange>[23:20]</bitRange>
            </field>
            <field>
              <name>AFSEL6</name>
              <description>GPIOC6 AF select</description>
              <bitRange>[27:24]</bitRange>
            </field>
            <field>
              <name>AFSEL7</name>
              <description>GPIOC7 AF select</description>
              <bitRange>[31:28]</bitRange>
            </field>
          </fields>
        </register>
        <register>
          <name>AFRH</name>
          <addressOffset>0x24</addressOffset>
          <fields>
            <field>
              <name>AFSEL8</name>
              <description>GPIOC8 AF select</description>
              <bitRange>[3:0]</bitRange>
            </field>
            <field>
              <name>AFSEL9</name>
              <description>GPIOC9 AF select</description>
              <bitRange>[7:4]</bitRange>
            </field>
            <field>
              <name>AFSEL10</name>
              <description>GPIOC10 AF select</description>
              <bitRange>[11:8]</bitRange>
            </field>
            <field>
              <name>AFSEL11</name>
              <description>GPIOC11 AF select</description>
              <bitRange>[15:12]</bitRange>
            </field>
            <field>
              <name>AFSEL12</name>
              <description>GPIOC12 AF select</description>
              <bitRange>[19:16]</bitRange>
            </field>
            <field>
              <name>AFSEL13</name>
              <description>GPIOC13 AF select</description>
              <bitRange>[23:20]</bitRange>
            </field>
            <field>
              <name>AFSEL14</name>
              <description>GPIOC14 AF select</description>
              <bitRange>[27:24]</bitRange>
            </field>
            <field>
              <name>AFSEL15</name>
              <description>GPIOC15 AF select</description>
              <bitRange>[31:28]</bitRange>
            </field>
          </fields>
        </register>
        <register>
          <name>BRR</name>
          <addressOffset>0x28</addressOffset>
          <fields>
            <field>
              <name>BR0</name>
              <description>GPIOC 0 output pin reset</description>
              <bitRange>[0:0]</bitRange>
            </field>
            <field>
              <name>BR1</name>
              <description>GPIOC 1 output pin reset</description>
              <bitRange>[1:1]</bitRange>
            </field>
            <field>
              <name>BR2</name>
              <description>GPIOC 2 output pin reset</description>
              <bitRange>[2:2]</bitRange>
            </field>
            <field>
              <name>BR3</name>
              <description>GPIOC 3 output pin reset</description>
              <bitRange>[3:3]</bitRange>
            </field>
            <field>
              <name>BR4</name>
              <description>GPIOC 4 output pin reset</description>
              <bitRange>[4:4]</bitRange>
            </field>
            <field>
              <name>BR5</name>
              <description>GPIOC 5 output pin reset</description>
              <bitRange>[5:5]</bitRange>
            </field>
            <field>
              <name>BR6</name>
              <description>GPIOC 6 output pin reset</description>
              <bitRange>[6:6]</bitRange>
            </field>
            <field>
              <name>BR7</name>
              <description>GPIOC 7 output pin reset</description>
              <bitRange>[7:7]</bitRange>
            </field>
            <field>
              <name>BR8</name>
              <description>GPIOC 8 output pin reset</description>
              <bitRange>[8:8]</bitRange>
            </field>
            <field>
              <name>BR9</name>
              <description>GPIOC 9 output pin reset</description>
              <bitRange>[9:9]</bitRange>
            </field>
            <field>
              <name>BR10</name>
              <description>GPIOC 10 output pin reset</description>
              <bitRange>[10:10]</bitRange>
            </field>
            <field>
              <name>BR11</name>
              <description>GPIOC 11 output pin reset</description>
              <bitRange>[11:11]</bitRange>
            </field>
            <field>
              <name>BR12</name>
              <description>GPIOC 12 output pin reset</description>
              <bitRange>[12:12]</bitRange>
            </field>
            <field>
              <name>BR13</name>
              <description>GPIOC 13 output pin reset</description>
              <bitRange>[13:13]</bitRange>
            </field>
            <field>
              <name>BR14</name>
              <description>GPIOC 14 output pin reset</description>
              <bitRange>[14:14]</bitRange>
            </field>
            <field>
              <name>BR15</name>
              <description>GPIOC 15 output pin reset</description>
              <bitRange>[15:15]</bitRange>
            </field>
          </fields>
        </register>
      </registers>
    </peripheral>
    <peripheral>
      <name>GPIOD</name>
      <baseAddress>0x48000C00</baseAddress>
      <addressBlock>
        <offset>0x0</offset>
        <size>0x400</size>
        <usage>registers</usage>
      </addressBlock>
      <registers>
        <register>
          <name>MODER</name>
          <addressOffset>0x0</addressOffset>
          <fields>
            <field>
              <name>MODER0</name>
              <description>GPIOD0 MODE</description>
              <bitRange>[1:0]</bitRange>
            </field>
            <field>
              <name>MODER1</name>
              <description>GPIOD1 MODE</description>
              <bitRange>[3:2]</bitRange>
            </field>
            <field>
              <name>MODER2</name>
              <description>GPIOD2 MODE</description>
              <bitRange>[5:4]</bitRange>
            </field>
            <field>
              <name>MODER3</name>
              <description>GPIOD3 MODE</description>
              <bitRange>[7:6]</bitRange>
            </field>
            <field>
              <name>MODER4</name>
              <description>GPIOD4 MODE</description>
              <bitRange>[9:8]</bitRange>
            </field>
            <field>
              <name>MODER5</name>
              <description>GPIOD5 MODE</description>
              <bitRange>[11:10]</bitRange>
            </field>
            <field>
              <name>MODER6</name>
              <description>GPIOD6 MODE</description>
              <bitRange>[13:12]</bitRange>
            </field>
            <field>
              <name>MODER7</name>
              <description>GPIOD7 MODE</description>
              <bitRange>[15:14]</bitRange>
            </field>
            <field>
              <name>MODER8</name>
              <description>GPIOD8 MODE</description>
              <bitRange>[17:16]</bitRange>
            </field>
            <field>
              <name>MODER9</name>
              <description>GPIOD9 MODE</description>
              <bitRange>[19:18]</bitRange>
            </field>
            <field>
              <name>MODER10</name>
              <description>GPIOD10 MODE</description>
              <bitRange>[21:20]</bitRange>
            </field>
            <field>
              <name>MODER11</name>
              <description>GPIOD11 MODE</description>
              <bitRange>[23:22]</bitRange>
            </field>
            <field>
              <name>MODER12</name>
              <description>GPIOD12 MODE</description>
              <bitRange>[25:24]</bitRange>
            </field>
            <field>
              <name>MODER13</name>
              <description>GPIOD13 MODE</description>
              <bitRange>[27:26]</bitRange>
            </field>
            <field>
              <name>MODER14</name>
              <description>GPIOD14 MODE</description>
              <bitRange>[29:28]</bitRange>
            </field>
            <field>
              <name>MODER15</name>
              <description>GPIOD15 MODE</description>
              <bitRange>[31:30]</bitRange>
            </field>
          </fields>
        </register>
        <register>
          <name>OTYPER</name>
          <addressOffset>0x4</addressOffset>
          <fields>
            <field>
              <name>OT0</name>
              <description>GPIOD0 Output type</description>
              <bitRange>[0:0]</bitRange>
            </field>
            <field>
              <name>OT1</name>
              <description>GPIOD1 Output type</description>
              <bitRange>[1:1]</bitRange>
            </field>
            <field>
              <name>OT2</name>
              <description>GPIOD2 Output type</description>
              <bitRange>[2:2]</bitRange>
            </field>
            <field>
              <name>OT3</name>
              <description>GPIOD3 Output type</description>
              <bitRange>[3:3]</bitRange>
            </field>
            <field>
              <name>OT4</name>
              <description>GPIOD4 Output type</description>
              <bitRange>[4:4]</bitRange>
            </field>
            <field>
              <name>OT5</name>
              <description>GPIOD5 Output type</description>
              <bitRange>[5:5]</bitRange>
            </field>
            <field>
              <name>OT6</name>
              <description>GPIOD6 Output type</description>
              <bitRange>[6:6]</bitRange>
            </field>
            <field>
              <name>OT7</name>
              <description>GPIOD7 Output type</description>
              <bitRange>[7:7]</bitRange>
            </field>
            <field>
              <name>OT8</name>
              <description>GPIOD8 Output type</description>
              <bitRange>[8:8]</bitRange>
            </field>
            <field>
              <name>OT9</name>
              <description>GPIOD9 Output type</description>
              <bitRange>[9:9]</bitRange>
            </field>
            <field>
              <name>OT10</name>
              <description>GPIOD10 Output type</description>
              <bitRange>[10:10]</bitRange>
            </field>
            <field>
              <name>OT11</name>
              <description>GPIOD11 Output type</description>
              <bitRange>[11:11]</bitRange>
            </field>
            <field>
              <name>OT12</name>
              <description>GPIOD12 Output type</description>
              <bitRange>[12:12]</bitRange>
            </field>
            <field>
              <name>OT13</name>
              <description>GPIOD13 Output type</description>
              <bitRange>[13:13]</bitRange>
            </field>
            <field>
              <name>OT14</name>
              <description>GPIOD14 Output type</description>
              <bitRange>[14:14]</bitRange>
            </field>
            <field>
              <name>OT15</name>
              <description>GPIOD15 Output type</description>
              <bitRange>[15:15]</bitRange>
            </field>
          </fields>
        </register>
        <register>
          <name>OSPDDER</name>
          <addressOffset>0x8</addressOffset>
          <fields>
            <field>
              <name>OSPEED0</name>
              <description>GPIOD0 output speed</description>
              <bitRange>[1:0]</bitRange>
            </field>
            <field>
              <name>OSPEED1</name>
              <description>GPIOD1 output speed</description>
              <bitRange>[3:2]</bitRange>
            </field>
            <field>
              <name>OSPEED2</name>
              <description>GPIOD2 output speed</description>
              <bitRange>[5:4]</bitRange>
            </field>
            <field>
              <name>OSPEED3</name>
              <description>GPIOD3 output speed</description>
              <bitRange>[7:6]</bitRange>
            </field>
            <field>
              <name>OSPEED4</name>
              <description>GPIOD4 output speed</description>
              <bitRange>[9:8]</bitRange>
            </field>
            <field>
              <name>OSPEED5</name>
              <description>GPIOD5 output speed</description>
              <bitRange>[11:10]</bitRange>
            </field>
            <field>
              <name>OSPEED6</name>
              <description>GPIOD6 output speed</description>
              <bitRange>[13:12]</bitRange>
            </field>
            <field>
              <name>OSPEED7</name>
              <description>GPIOD7 output speed</description>
              <bitRange>[15:14]</bitRange>
            </field>
            <field>
              <name>OSPEED8</name>
              <description>GPIOD8 output speed</description>
              <bitRange>[17:16]</bitRange>
            </field>
            <field>
              <name>OSPEED9</name>
              <description>GPIOD9 output speed</description>
              <bitRange>[19:18]</bitRange>
            </field>
            <field>
              <name>OSPEED10</name>
              <description>GPIOD10 output speed</description>
              <bitRange>[21:20]</bitRange>
            </field>
            <field>
              <name>OSPEED11</name>
              <description>GPIOD11 output speed</description>
              <bitRange>[23:22]</bitRange>
            </field>
            <field>
              <name>OSPEED12</name>
              <description>GPIOD12 output speed</description>
              <bitRange>[25:24]</bitRange>
            </field>
            <field>
              <name>OSPEED13</name>
              <description>GPIOD13 output speed</description>
              <bitRange>[27:26]</bitRange>
            </field>
            <field>
              <name>OSPEED14</name>
              <description>GPIOD14 output speed</description>
              <bitRange>[29:28]</bitRange>
            </field>
            <field>
              <name>OSPEED15</name>
              <description>GPIOD15 output speed</description>
              <bitRange>[31:30]</bitRange>
            </field>
          </fields>
        </register>
        <register>
          <name>PUPDR</name>
          <addressOffset>0xC</addressOffset>
          <fields>
            <field>
              <name>PUPD0</name>
              <description>GPIOD0 pull up/pull down</description>
              <bitRange>[1:0]</bitRange>
            </field>
            <field>
              <name>PUPD1</name>
              <description>GPIOD1 pull up/pull down</description>
              <bitRange>[3:2]</bitRange>
            </field>
            <field>
              <name>PUPD2</name>
              <description>GPIOD2 pull up/pull down</description>
              <bitRange>[5:4]</bitRange>
            </field>
            <field>
              <name>PUPD3</name>
              <description>GPIOD3 pull up/pull down</description>
              <bitRange>[7:6]</bitRange>
            </field>
            <field>
              <name>PUPD4</name>
              <description>GPIOD4 pull up/pull down</description>
              <bitRange>[9:8]</bitRange>
            </field>
            <field>
              <name>PUPD5</name>
              <description>GPIOD5 pull up/pull down</description>
              <bitRange>[11:10]</bitRange>
            </field>
            <field>
              <name>PUPD6</name>
              <description>GPIOD6 pull up/pull down</description>
              <bitRange>[13:12]</bitRange>
            </field>
            <field>
              <name>PUPD7</name>
              <description>GPIOD7 pull up/pull down</description>
              <bitRange>[15:14]</bitRange>
            </field>
            <field>
              <name>PUPD8</name>
              <description>GPIOD8 pull up/pull down</description>
              <bitRange>[17:16]</bitRange>
            </field>
            <field>
              <name>PUPD9</name>
              <description>GPIOD9 pull up/pull down</description>
              <bitRange>[19:18]</bitRange>
            </field>
            <field>
              <name>PUPD10</name>
              <description>GPIOD10 pull up/pull down</description>
              <bitRange>[21:20]</bitRange>
            </field>
            <field>
              <name>PUPD11</name>
              <description>GPIOD11 pull up/pull down</description>
              <bitRange>[23:22]</bitRange>
            </field>
            <field>
              <name>PUPD12</name>
              <description>GPIOD12 pull up/pull down</description>
              <bitRange>[25:24]</bitRange>
            </field>
            <field>
              <name>PUPD13</name>
              <description>GPIOD13 pull up/pull down</description>
              <bitRange>[27:26]</bitRange>
            </field>
            <field>
              <name>PUPD14</name>
              <description>GPIOD14 pull up/pull down</description>
              <bitRange>[29:28]</bitRange>
            </field>
            <field>
              <name>PUPD15</name>
              <description>GPIOD15 pull up/pull down</description>
              <bitRange>[31:30]</bitRange>
            </field>
          </fields>
        </register>
        <register>
          <name>IDR</name>
          <addressOffset>0x10</addressOffset>
          <fields>
            <field>
              <name>ID0</name>
              <description>GPIOD0 input data</description>
              <bitRange>[0:0]</bitRange>
              <access>read-only</access>
            </field>
            <field>
              <name>ID1</name>
              <description>GPIOD1 input data</description>
              <bitRange>[1:1]</bitRange>
              <access>read-only</access>
            </field>
            <field>
              <name>ID2</name>
              <description>GPIOD2 input data</description>
              <bitRange>[2:2]</bitRange>
              <access>read-only</access>
            </field>
            <field>
              <name>ID3</name>
              <description>GPIOD3 input data</description>
              <bitRange>[3:3]</bitRange>
              <access>read-only</access>
            </field>
            <field>
              <name>ID4</name>
              <description>GPIOD4 input data</description>
              <bitRange>[4:4]</bitRange>
              <access>read-only</access>
            </field>
            <field>
              <name>ID5</name>
              <description>GPIOD5 input data</description>
              <bitRange>[5:5]</bitRange>
              <access>read-only</access>
            </field>
            <field>
              <name>ID6</name>
              <description>GPIOD6 input data</description>
              <bitRange>[6:6]</bitRange>
              <access>read-only</access>
            </field>
            <field>
              <name>ID7</name>
              <description>GPIOD7 input data</description>
              <bitRange>[7:7]</bitRange>
              <access>read-only</access>
            </field>
            <field>
              <name>ID8</name>
              <description>GPIOD8 input data</description>
              <bitRange>[8:8]</bitRange>
              <access>read-only</access>
            </field>
            <field>
              <name>ID9</name>
              <description>GPIOD9 input data</description>
              <bitRange>[9:9]</bitRange>
              <access>read-only</access>
            </field>
            <field>
              <name>ID10</name>
              <description>GPIOD10 input data</description>
              <bitRange>[10:10]</bitRange>
              <access>read-only</access>
            </field>
            <field>
              <name>ID11</name>
              <description>GPIOD11 input data</description>
              <bitRange>[11:11]</bitRange>
              <access>read-only</access>
            </field>
            <field>
              <name>ID12</name>
              <description>GPIOD12 input data</description>
              <bitRange>[12:12]</bitRange>
              <access>read-only</access>
            </field>
            <field>
              <name>ID13</name>
              <description>GPIOD13 input data</description>
              <bitRange>[13:13]</bitRange>
              <access>read-only</access>
            </field>
            <field>
              <name>ID14</name>
              <description>GPIOD14 input data</description>
              <bitRange>[14:14]</bitRange>
              <access>read-only</access>
            </field>
            <field>
              <name>ID15</name>
              <description>GPIOD15 input data</description>
              <bitRange>[15:15]</bitRange>
              <access>read-only</access>
            </field>
          </fields>
        </register>
        <register>
          <name>ODR</name>
          <addressOffset>0x14</addressOffset>
          <fields>
            <field>
              <name>OD0</name>
              <description>GPIOD0 output data</description>
              <bitRange>[0:0]</bitRange>
            </field>
            <field>
              <name>OD1</name>
              <description>GPIOD1 output data</description>
              <bitRange>[1:1]</bitRange>
            </field>
            <field>
              <name>OD2</name>
              <description>GPIOD2 output data</description>
              <bitRange>[2:2]</bitRange>
            </field>
            <field>
              <name>OD3</name>
              <description>GPIOD3 output data</description>
              <bitRange>[3:3]</bitRange>
            </field>
            <field>
              <name>OD4</name>
              <description>GPIOD4 output data</description>
              <bitRange>[4:4]</bitRange>
            </field>
            <field>
              <name>OD5</name>
              <description>GPIOD5 output data</description>
              <bitRange>[5:5]</bitRange>
            </field>
            <field>
              <name>OD6</name>
              <description>GPIOD6 output data</description>
              <bitRange>[6:6]</bitRange>
            </field>
            <field>
              <name>OD7</name>
              <description>GPIOD7 output data</description>
              <bitRange>[7:7]</bitRange>
            </field>
            <field>
              <name>OD8</name>
              <description>GPIOD8 output data</description>
              <bitRange>[8:8]</bitRange>
            </field>
            <field>
              <name>OD9</name>
              <description>GPIOD9 output data</description>
              <bitRange>[9:9]</bitRange>
            </field>
            <field>
              <name>OD10</name>
              <description>GPIOD10 output data</description>
              <bitRange>[10:10]</bitRange>
            </field>
            <field>
              <name>OD11</name>
              <description>GPIOD11 output data</description>
              <bitRange>[11:11]</bitRange>
            </field>
            <field>
              <name>OD12</name>
              <description>GPIOD12 output data</description>
              <bitRange>[12:12]</bitRange>
            </field>
            <field>
              <name>OD13</name>
              <description>GPIOD13 output data</description>
              <bitRange>[13:13]</bitRange>
            </field>
            <field>
              <name>OD14</name>
              <description>GPIOD14 output data</description>
              <bitRange>[14:14]</bitRange>
            </field>
            <field>
              <name>OD15</name>
              <description>GPIOD15 output data</description>
              <bitRange>[15:15]</bitRange>
            </field>
          </fields>
        </register>
        <register>
          <name>BSRR</name>
          <addressOffset>0x18</addressOffset>
          <fields>
            <field>
              <name>BS0</name>
              <description>GPIOD0 output set</description>
              <bitRange>[0:0]</bitRange>
            </field>
            <field>
              <name>BS1</name>
              <description>GPIOD1 output set</description>
              <bitRange>[1:1]</bitRange>
            </field>
            <field>
              <name>BS2</name>
              <description>GPIOD2 output set</description>
              <bitRange>[2:2]</bitRange>
            </field>
            <field>
              <name>BS3</name>
              <description>GPIOD3 output set</description>
              <bitRange>[3:3]</bitRange>
            </field>
            <field>
              <name>BS4</name>
              <description>GPIOD4 output set</description>
              <bitRange>[4:4]</bitRange>
            </field>
            <field>
              <name>BS5</name>
              <description>GPIOD5 output set</description>
              <bitRange>[5:5]</bitRange>
            </field>
            <field>
              <name>BS6</name>
              <description>GPIOD6 output set</description>
              <bitRange>[6:6]</bitRange>
            </field>
            <field>
              <name>BS7</name>
              <description>GPIOD7 output set</description>
              <bitRange>[7:7]</bitRange>
            </field>
            <field>
              <name>BS8</name>
              <description>GPIOD8 output set</description>
              <bitRange>[8:8]</bitRange>
            </field>
            <field>
              <name>BS9</name>
              <description>GPIOD9 output set</description>
              <bitRange>[9:9]</bitRange>
            </field>
            <field>
              <name>BS10</name>
              <description>GPIOD10 output set</description>
              <bitRange>[10:10]</bitRange>
            </field>
            <field>
              <name>BS11</name>
              <description>GPIOD11 output set</description>
              <bitRange>[11:11]</bitRange>
            </field>
            <field>
              <name>BS12</name>
              <description>GPIOD12 output set</description>
              <bitRange>[12:12]</bitRange>
            </field>
            <field>
              <name>BS13</name>
              <description>GPIOD13 output set</description>
              <bitRange>[13:13]</bitRange>
            </field>
            <field>
              <name>BS14</name>
              <description>GPIOD14 output set</description>
              <bitRange>[14:14]</bitRange>
            </field>
            <field>
              <name>BS15</name>
              <description>GPIOD15 output set</description>
              <bitRange>[15:15]</bitRange>
            </field>
            <field>
              <name>BR0</name>
              <description>GPIOD0 outut reset</description>
              <bitRange>[16:16]</bitRange>
            </field>
            <field>
              <name>BR1</name>
              <description>GPIOD1 outut reset</description>
              <bitRange>[17:17]</bitRange>
            </field>
            <field>
              <name>BR2</name>
              <description>GPIOD2 outut reset</description>
              <bitRange>[18:18]</bitRange>
            </field>
            <field>
              <name>BR3</name>
              <description>GPIOD3 outut reset</description>
              <bitRange>[19:19]</bitRange>
            </field>
            <field>
              <name>BR4</name>
              <description>GPIOD4 outut reset</description>
              <bitRange>[20:20]</bitRange>
            </field>
            <field>
              <name>BR5</name>
              <description>GPIOD5 outut reset</description>
              <bitRange>[21:21]</bitRange>
            </field>
            <field>
              <name>BR6</name>
              <description>GPIOD6 outut reset</description>
              <bitRange>[22:22]</bitRange>
            </field>
            <field>
              <name>BR7</name>
              <description>GPIOD7 outut reset</description>
              <bitRange>[23:23]</bitRange>
            </field>
            <field>
              <name>BR8</name>
              <description>GPIOD8 outut reset</description>
              <bitRange>[24:24]</bitRange>
            </field>
            <field>
              <name>BR9</name>
              <description>GPIOD9 outut reset</description>
              <bitRange>[25:25]</bitRange>
            </field>
            <field>
              <name>BR10</name>
              <description>GPIOD10 outut reset</description>
              <bitRange>[26:26]</bitRange>
            </field>
            <field>
              <name>BR11</name>
              <description>GPIOD11 outut reset</description>
              <bitRange>[27:27]</bitRange>
            </field>
            <field>
              <name>BR12</name>
              <description>GPIOD12 outut reset</description>
              <bitRange>[28:28]</bitRange>
            </field>
            <field>
              <name>BR13</name>
              <description>GPIOD13 outut reset</description>
              <bitRange>[29:29]</bitRange>
            </field>
            <field>
              <name>BR14</name>
              <description>GPIOD14 outut reset</description>
              <bitRange>[30:30]</bitRange>
            </field>
            <field>
              <name>BR15</name>
              <description>GPIOD15 outut reset</description>
              <bitRange>[31:31]</bitRange>
            </field>
          </fields>
        </register>
        <register>
          <name>LCKR</name>
          <addressOffset>0x1C</addressOffset>
          <fields>
            <field>
              <name>LCK0</name>
              <description>GPIOD lock(bit0)</description>
              <bitRange>[0:0]</bitRange>
            </field>
            <field>
              <name>LCK1</name>
              <description>GPIOD lock(bit1)</description>
              <bitRange>[1:1]</bitRange>
            </field>
            <field>
              <name>LCK2</name>
              <description>GPIOD lock(bit2)</description>
              <bitRange>[2:2]</bitRange>
            </field>
            <field>
              <name>LCK3</name>
              <description>GPIOD lock(bit3)</description>
              <bitRange>[3:3]</bitRange>
            </field>
            <field>
              <name>LCK4</name>
              <description>GPIOD lock(bit4)</description>
              <bitRange>[4:4]</bitRange>
            </field>
            <field>
              <name>LCK5</name>
              <description>GPIOD lock(bit5)</description>
              <bitRange>[5:5]</bitRange>
            </field>
            <field>
              <name>LCK6</name>
              <description>GPIOD lock(bit6)</description>
              <bitRange>[6:6]</bitRange>
            </field>
            <field>
              <name>LCK7</name>
              <description>GPIOD lock(bit7)</description>
              <bitRange>[7:7]</bitRange>
            </field>
            <field>
              <name>LCK8</name>
              <description>GPIOD lock(bit8)</description>
              <bitRange>[8:8]</bitRange>
            </field>
            <field>
              <name>LCK9</name>
              <description>GPIOD lock(bit9)</description>
              <bitRange>[9:9]</bitRange>
            </field>
            <field>
              <name>LCK10</name>
              <description>GPIOD lock(bit10)</description>
              <bitRange>[10:10]</bitRange>
            </field>
            <field>
              <name>LCK11</name>
              <description>GPIOD lock(bit11)</description>
              <bitRange>[11:11]</bitRange>
            </field>
            <field>
              <name>LCK12</name>
              <description>GPIOD lock(bit12)</description>
              <bitRange>[12:12]</bitRange>
            </field>
            <field>
              <name>LCK13</name>
              <description>GPIOD lock(bit13)</description>
              <bitRange>[13:13]</bitRange>
            </field>
            <field>
              <name>LCK14</name>
              <description>GPIOD lock(bit14)</description>
              <bitRange>[14:14]</bitRange>
            </field>
            <field>
              <name>LCK15</name>
              <description>GPIOD lock(bit15)</description>
              <bitRange>[15:15]</bitRange>
            </field>
            <field>
              <name>LCKK</name>
              <description>GPIOD lock key</description>
              <bitRange>[16:16]</bitRange>
            </field>
          </fields>
        </register>
        <register>
          <name>AFRL</name>
          <addressOffset>0x20</addressOffset>
          <fields>
            <field>
              <name>AFSEL0</name>
              <description>GPIOD0 AF select</description>
              <bitRange>[3:0]</bitRange>
            </field>
            <field>
              <name>AFSEL1</name>
              <description>GPIOD1 AF select</description>
              <bitRange>[7:4]</bitRange>
            </field>
            <field>
              <name>AFSEL2</name>
              <description>GPIOD2 AF select</description>
              <bitRange>[11:8]</bitRange>
            </field>
            <field>
              <name>AFSEL3</name>
              <description>GPIOD3 AF select</description>
              <bitRange>[15:12]</bitRange>
            </field>
            <field>
              <name>AFSEL4</name>
              <description>GPIOD4 AF select</description>
              <bitRange>[19:16]</bitRange>
            </field>
            <field>
              <name>AFSEL5</name>
              <description>GPIOD5 AF select</description>
              <bitRange>[23:20]</bitRange>
            </field>
            <field>
              <name>AFSEL6</name>
              <description>GPIOD6 AF select</description>
              <bitRange>[27:24]</bitRange>
            </field>
            <field>
              <name>AFSEL7</name>
              <description>GPIOD7 AF select</description>
              <bitRange>[31:28]</bitRange>
            </field>
          </fields>
        </register>
        <register>
          <name>AFRH</name>
          <addressOffset>0x24</addressOffset>
          <fields>
            <field>
              <name>AFSEL8</name>
              <description>GPIOD8 AF select</description>
              <bitRange>[3:0]</bitRange>
            </field>
            <field>
              <name>AFSEL9</name>
              <description>GPIOD9 AF select</description>
              <bitRange>[7:4]</bitRange>
            </field>
            <field>
              <name>AFSEL10</name>
              <description>GPIOD10 AF select</description>
              <bitRange>[11:8]</bitRange>
            </field>
            <field>
              <name>AFSEL11</name>
              <description>GPIOD11 AF select</description>
              <bitRange>[15:12]</bitRange>
            </field>
            <field>
              <name>AFSEL12</name>
              <description>GPIOD12 AF select</description>
              <bitRange>[19:16]</bitRange>
            </field>
            <field>
              <name>AFSEL13</name>
              <description>GPIOD13 AF select</description>
              <bitRange>[23:20]</bitRange>
            </field>
            <field>
              <name>AFSEL14</name>
              <description>GPIOD14 AF select</description>
              <bitRange>[27:24]</bitRange>
            </field>
            <field>
              <name>AFSEL15</name>
              <description>GPIOD15 AF select</description>
              <bitRange>[31:28]</bitRange>
            </field>
          </fields>
        </register>
        <register>
          <name>BRR</name>
          <addressOffset>0x28</addressOffset>
          <fields>
            <field>
              <name>BR0</name>
              <description>GPIOD 0 output pin reset</description>
              <bitRange>[0:0]</bitRange>
            </field>
            <field>
              <name>BR1</name>
              <description>GPIOD 1 output pin reset</description>
              <bitRange>[1:1]</bitRange>
            </field>
            <field>
              <name>BR2</name>
              <description>GPIOD 2 output pin reset</description>
              <bitRange>[2:2]</bitRange>
            </field>
            <field>
              <name>BR3</name>
              <description>GPIOD 3 output pin reset</description>
              <bitRange>[3:3]</bitRange>
            </field>
            <field>
              <name>BR4</name>
              <description>GPIOD 4 output pin reset</description>
              <bitRange>[4:4]</bitRange>
            </field>
            <field>
              <name>BR5</name>
              <description>GPIOD 5 output pin reset</description>
              <bitRange>[5:5]</bitRange>
            </field>
            <field>
              <name>BR6</name>
              <description>GPIOD 6 output pin reset</description>
              <bitRange>[6:6]</bitRange>
            </field>
            <field>
              <name>BR7</name>
              <description>GPIOD 7 output pin reset</description>
              <bitRange>[7:7]</bitRange>
            </field>
            <field>
              <name>BR8</name>
              <description>GPIOD 8 output pin reset</description>
              <bitRange>[8:8]</bitRange>
            </field>
            <field>
              <name>BR9</name>
              <description>GPIOD 9 output pin reset</description>
              <bitRange>[9:9]</bitRange>
            </field>
            <field>
              <name>BR10</name>
              <description>GPIOD 10 output pin reset</description>
              <bitRange>[10:10]</bitRange>
            </field>
            <field>
              <name>BR11</name>
              <description>GPIOD 11 output pin reset</description>
              <bitRange>[11:11]</bitRange>
            </field>
            <field>
              <name>BR12</name>
              <description>GPIOD 12 output pin reset</description>
              <bitRange>[12:12]</bitRange>
            </field>
            <field>
              <name>BR13</name>
              <description>GPIOD 13 output pin reset</description>
              <bitRange>[13:13]</bitRange>
            </field>
            <field>
              <name>BR14</name>
              <description>GPIOD 14 output pin reset</description>
              <bitRange>[14:14]</bitRange>
            </field>
            <field>
              <name>BR15</name>
              <description>GPIOD 15 output pin reset</description>
              <bitRange>[15:15]</bitRange>
            </field>
          </fields>
        </register>
      </registers>
    </peripheral>
    <peripheral>
      <name>GPIOE</name>
      <baseAddress>0x48001000</baseAddress>
      <addressBlock>
        <offset>0x0</offset>
        <size>0x400</size>
        <usage>registers</usage>
      </addressBlock>
      <registers>
        <register>
          <name>MODER</name>
          <addressOffset>0x0</addressOffset>
          <fields>
            <field>
              <name>MODER0</name>
              <description>GPIOE0 MODE</description>
              <bitRange>[1:0]</bitRange>
            </field>
            <field>
              <name>MODER1</name>
              <description>GPIOE1 MODE</description>
              <bitRange>[3:2]</bitRange>
            </field>
            <field>
              <name>MODER2</name>
              <description>GPIOE2 MODE</description>
              <bitRange>[5:4]</bitRange>
            </field>
            <field>
              <name>MODER3</name>
              <description>GPIOE3 MODE</description>
              <bitRange>[7:6]</bitRange>
            </field>
            <field>
              <name>MODER4</name>
              <description>GPIOE4 MODE</description>
              <bitRange>[9:8]</bitRange>
            </field>
            <field>
              <name>MODER5</name>
              <description>GPIOE5 MODE</description>
              <bitRange>[11:10]</bitRange>
            </field>
            <field>
              <name>MODER6</name>
              <description>GPIOE6 MODE</description>
              <bitRange>[13:12]</bitRange>
            </field>
            <field>
              <name>MODER7</name>
              <description>GPIOE7 MODE</description>
              <bitRange>[15:14]</bitRange>
            </field>
            <field>
              <name>MODER8</name>
              <description>GPIOE8 MODE</description>
              <bitRange>[17:16]</bitRange>
            </field>
            <field>
              <name>MODER9</name>
              <description>GPIOE9 MODE</description>
              <bitRange>[19:18]</bitRange>
            </field>
            <field>
              <name>MODER10</name>
              <description>GPIOE10 MODE</description>
              <bitRange>[21:20]</bitRange>
            </field>
            <field>
              <name>MODER11</name>
              <description>GPIOE11 MODE</description>
              <bitRange>[23:22]</bitRange>
            </field>
            <field>
              <name>MODER12</name>
              <description>GPIOE12 MODE</description>
              <bitRange>[25:24]</bitRange>
            </field>
            <field>
              <name>MODER13</name>
              <description>GPIOE13 MODE</description>
              <bitRange>[27:26]</bitRange>
            </field>
            <field>
              <name>MODER14</name>
              <description>GPIOE14 MODE</description>
              <bitRange>[29:28]</bitRange>
            </field>
            <field>
              <name>MODER15</name>
              <description>GPIOE15 MODE</description>
              <bitRange>[31:30]</bitRange>
            </field>
          </fields>
        </register>
        <register>
          <name>OTYPER</name>
          <addressOffset>0x4</addressOffset>
          <fields>
            <field>
              <name>OT0</name>
              <description>GPIOE0 Output type</description>
              <bitRange>[0:0]</bitRange>
            </field>
            <field>
              <name>OT1</name>
              <description>GPIOE1 Output type</description>
              <bitRange>[1:1]</bitRange>
            </field>
            <field>
              <name>OT2</name>
              <description>GPIOE2 Output type</description>
              <bitRange>[2:2]</bitRange>
            </field>
            <field>
              <name>OT3</name>
              <description>GPIOE3 Output type</description>
              <bitRange>[3:3]</bitRange>
            </field>
            <field>
              <name>OT4</name>
              <description>GPIOE4 Output type</description>
              <bitRange>[4:4]</bitRange>
            </field>
            <field>
              <name>OT5</name>
              <description>GPIOE5 Output type</description>
              <bitRange>[5:5]</bitRange>
            </field>
            <field>
              <name>OT6</name>
              <description>GPIOE6 Output type</description>
              <bitRange>[6:6]</bitRange>
            </field>
            <field>
              <name>OT7</name>
              <description>GPIOE7 Output type</description>
              <bitRange>[7:7]</bitRange>
            </field>
            <field>
              <name>OT8</name>
              <description>GPIOE8 Output type</description>
              <bitRange>[8:8]</bitRange>
            </field>
            <field>
              <name>OT9</name>
              <description>GPIOE9 Output type</description>
              <bitRange>[9:9]</bitRange>
            </field>
            <field>
              <name>OT10</name>
              <description>GPIOE10 Output type</description>
              <bitRange>[10:10]</bitRange>
            </field>
            <field>
              <name>OT11</name>
              <description>GPIOE11 Output type</description>
              <bitRange>[11:11]</bitRange>
            </field>
            <field>
              <name>OT12</name>
              <description>GPIOE12 Output type</description>
              <bitRange>[12:12]</bitRange>
            </field>
            <field>
              <name>OT13</name>
              <description>GPIOE13 Output type</description>
              <bitRange>[13:13]</bitRange>
            </field>
            <field>
              <name>OT14</name>
              <description>GPIOE14 Output type</description>
              <bitRange>[14:14]</bitRange>
            </field>
            <field>
              <name>OT15</name>
              <description>GPIOE15 Output type</description>
              <bitRange>[15:15]</bitRange>
            </field>
          </fields>
        </register>
        <register>
          <name>OSPDDER</name>
          <addressOffset>0x8</addressOffset>
          <fields>
            <field>
              <name>OSPEED0</name>
              <description>GPIOE0 output speed</description>
              <bitRange>[1:0]</bitRange>
            </field>
            <field>
              <name>OSPEED1</name>
              <description>GPIOE1 output speed</description>
              <bitRange>[3:2]</bitRange>
            </field>
            <field>
              <name>OSPEED2</name>
              <description>GPIOE2 output speed</description>
              <bitRange>[5:4]</bitRange>
            </field>
            <field>
              <name>OSPEED3</name>
              <description>GPIOE3 output speed</description>
              <bitRange>[7:6]</bitRange>
            </field>
            <field>
              <name>OSPEED4</name>
              <description>GPIOE4 output speed</description>
              <bitRange>[9:8]</bitRange>
            </field>
            <field>
              <name>OSPEED5</name>
              <description>GPIOE5 output speed</description>
              <bitRange>[11:10]</bitRange>
            </field>
            <field>
              <name>OSPEED6</name>
              <description>GPIOE6 output speed</description>
              <bitRange>[13:12]</bitRange>
            </field>
            <field>
              <name>OSPEED7</name>
              <description>GPIOE7 output speed</description>
              <bitRange>[15:14]</bitRange>
            </field>
            <field>
              <name>OSPEED8</name>
              <description>GPIOE8 output speed</description>
              <bitRange>[17:16]</bitRange>
            </field>
            <field>
              <name>OSPEED9</name>
              <description>GPIOE9 output speed</description>
              <bitRange>[19:18]</bitRange>
            </field>
            <field>
              <name>OSPEED10</name>
              <description>GPIOE10 output speed</description>
              <bitRange>[21:20]</bitRange>
            </field>
            <field>
              <name>OSPEED11</name>
              <description>GPIOE11 output speed</description>
              <bitRange>[23:22]</bitRange>
            </field>
            <field>
              <name>OSPEED12</name>
              <description>GPIOE12 output speed</description>
              <bitRange>[25:24]</bitRange>
            </field>
            <field>
              <name>OSPEED13</name>
              <description>GPIOE13 output speed</description>
              <bitRange>[27:26]</bitRange>
            </field>
            <field>
              <name>OSPEED14</name>
              <description>GPIOE14 output speed</description>
              <bitRange>[29:28]</bitRange>
            </field>
            <field>
              <name>OSPEED15</name>
              <description>GPIOE15 output speed</description>
              <bitRange>[31:30]</bitRange>
            </field>
          </fields>
        </register>
        <register>
          <name>PUPDR</name>
          <addressOffset>0xC</addressOffset>
          <fields>
            <field>
              <name>PUPD0</name>
              <description>GPIOE0 pull up/pull down</description>
              <bitRange>[1:0]</bitRange>
            </field>
            <field>
              <name>PUPD1</name>
              <description>GPIOE1 pull up/pull down</description>
              <bitRange>[3:2]</bitRange>
            </field>
            <field>
              <name>PUPD2</name>
              <description>GPIOE2 pull up/pull down</description>
              <bitRange>[5:4]</bitRange>
            </field>
            <field>
              <name>PUPD3</name>
              <description>GPIOE3 pull up/pull down</description>
              <bitRange>[7:6]</bitRange>
            </field>
            <field>
              <name>PUPD4</name>
              <description>GPIOE4 pull up/pull down</description>
              <bitRange>[9:8]</bitRange>
            </field>
            <field>
              <name>PUPD5</name>
              <description>GPIOE5 pull up/pull down</description>
              <bitRange>[11:10]</bitRange>
            </field>
            <field>
              <name>PUPD6</name>
              <description>GPIOE6 pull up/pull down</description>
              <bitRange>[13:12]</bitRange>
            </field>
            <field>
              <name>PUPD7</name>
              <description>GPIOE7 pull up/pull down</description>
              <bitRange>[15:14]</bitRange>
            </field>
            <field>
              <name>PUPD8</name>
              <description>GPIOE8 pull up/pull down</description>
              <bitRange>[17:16]</bitRange>
            </field>
            <field>
              <name>PUPD9</name>
              <description>GPIOE9 pull up/pull down</description>
              <bitRange>[19:18]</bitRange>
            </field>
            <field>
              <name>PUPD10</name>
              <description>GPIOE10 pull up/pull down</description>
              <bitRange>[21:20]</bitRange>
            </field>
            <field>
              <name>PUPD11</name>
              <description>GPIOE11 pull up/pull down</description>
              <bitRange>[23:22]</bitRange>
            </field>
            <field>
              <name>PUPD12</name>
              <description>GPIOE12 pull up/pull down</description>
              <bitRange>[25:24]</bitRange>
            </field>
            <field>
              <name>PUPD13</name>
              <description>GPIOE13 pull up/pull down</description>
              <bitRange>[27:26]</bitRange>
            </field>
            <field>
              <name>PUPD14</name>
              <description>GPIOE14 pull up/pull down</description>
              <bitRange>[29:28]</bitRange>
            </field>
            <field>
              <name>PUPD15</name>
              <description>GPIOE15 pull up/pull down</description>
              <bitRange>[31:30]</bitRange>
            </field>
          </fields>
        </register>
        <register>
          <name>IDR</name>
          <addressOffset>0x10</addressOffset>
          <fields>
            <field>
              <name>ID0</name>
              <description>GPIOE0 input data</description>
              <bitRange>[0:0]</bitRange>
              <access>read-only</access>
            </field>
            <field>
              <name>ID1</name>
              <description>GPIOE1 input data</description>
              <bitRange>[1:1]</bitRange>
              <access>read-only</access>
            </field>
            <field>
              <name>ID2</name>
              <description>GPIOE2 input data</description>
              <bitRange>[2:2]</bitRange>
              <access>read-only</access>
            </field>
            <field>
              <name>ID3</name>
              <description>GPIOE3 input data</description>
              <bitRange>[3:3]</bitRange>
              <access>read-only</access>
            </field>
            <field>
              <name>ID4</name>
              <description>GPIOE4 input data</description>
              <bitRange>[4:4]</bitRange>
              <access>read-only</access>
            </field>
            <field>
              <name>ID5</name>
              <description>GPIOE5 input data</description>
              <bitRange>[5:5]</bitRange>
              <access>read-only</access>
            </field>
            <field>
              <name>ID6</name>
              <description>GPIOE6 input data</description>
              <bitRange>[6:6]</bitRange>
              <access>read-only</access>
            </field>
            <field>
              <name>ID7</name>
              <description>GPIOE7 input data</description>
              <bitRange>[7:7]</bitRange>
              <access>read-only</access>
            </field>
            <field>
              <name>ID8</name>
              <description>GPIOE8 input data</description>
              <bitRange>[8:8]</bitRange>
              <access>read-only</access>
            </field>
            <field>
              <name>ID9</name>
              <description>GPIOE9 input data</description>
              <bitRange>[9:9]</bitRange>
              <access>read-only</access>
            </field>
            <field>
              <name>ID10</name>
              <description>GPIOE10 input data</description>
              <bitRange>[10:10]</bitRange>
              <access>read-only</access>
            </field>
            <field>
              <name>ID11</name>
              <description>GPIOE11 input data</description>
              <bitRange>[11:11]</bitRange>
              <access>read-only</access>
            </field>
            <field>
              <name>ID12</name>
              <description>GPIOE12 input data</description>
              <bitRange>[12:12]</bitRange>
              <access>read-only</access>
            </field>
            <field>
              <name>ID13</name>
              <description>GPIOE13 input data</description>
              <bitRange>[13:13]</bitRange>
              <access>read-only</access>
            </field>
            <field>
              <name>ID14</name>
              <description>GPIOE14 input data</description>
              <bitRange>[14:14]</bitRange>
              <access>read-only</access>
            </field>
            <field>
              <name>ID15</name>
              <description>GPIOE15 input data</description>
              <bitRange>[15:15]</bitRange>
              <access>read-only</access>
            </field>
          </fields>
        </register>
        <register>
          <name>ODR</name>
          <addressOffset>0x14</addressOffset>
          <fields>
            <field>
              <name>OD0</name>
              <description>GPIOE0 output data</description>
              <bitRange>[0:0]</bitRange>
            </field>
            <field>
              <name>OD1</name>
              <description>GPIOE1 output data</description>
              <bitRange>[1:1]</bitRange>
            </field>
            <field>
              <name>OD2</name>
              <description>GPIOE2 output data</description>
              <bitRange>[2:2]</bitRange>
            </field>
            <field>
              <name>OD3</name>
              <description>GPIOE3 output data</description>
              <bitRange>[3:3]</bitRange>
            </field>
            <field>
              <name>OD4</name>
              <description>GPIOE4 output data</description>
              <bitRange>[4:4]</bitRange>
            </field>
            <field>
              <name>OD5</name>
              <description>GPIOE5 output data</description>
              <bitRange>[5:5]</bitRange>
            </field>
            <field>
              <name>OD6</name>
              <description>GPIOE6 output data</description>
              <bitRange>[6:6]</bitRange>
            </field>
            <field>
              <name>OD7</name>
              <description>GPIOE7 output data</description>
              <bitRange>[7:7]</bitRange>
            </field>
            <field>
              <name>OD8</name>
              <description>GPIOE8 output data</description>
              <bitRange>[8:8]</bitRange>
            </field>
            <field>
              <name>OD9</name>
              <description>GPIOE9 output data</description>
              <bitRange>[9:9]</bitRange>
            </field>
            <field>
              <name>OD10</name>
              <description>GPIOE10 output data</description>
              <bitRange>[10:10]</bitRange>
            </field>
            <field>
              <name>OD11</name>
              <description>GPIOE11 output data</description>
              <bitRange>[11:11]</bitRange>
            </field>
            <field>
              <name>OD12</name>
              <description>GPIOE12 output data</description>
              <bitRange>[12:12]</bitRange>
            </field>
            <field>
              <name>OD13</name>
              <description>GPIOE13 output data</description>
              <bitRange>[13:13]</bitRange>
            </field>
            <field>
              <name>OD14</name>
              <description>GPIOE14 output data</description>
              <bitRange>[14:14]</bitRange>
            </field>
            <field>
              <name>OD15</name>
              <description>GPIOE15 output data</description>
              <bitRange>[15:15]</bitRange>
            </field>
          </fields>
        </register>
        <register>
          <name>BSRR</name>
          <addressOffset>0x18</addressOffset>
          <fields>
            <field>
              <name>BS0</name>
              <description>GPIOE0 output set</description>
              <bitRange>[0:0]</bitRange>
            </field>
            <field>
              <name>BS1</name>
              <description>GPIOE1 output set</description>
              <bitRange>[1:1]</bitRange>
            </field>
            <field>
              <name>BS2</name>
              <description>GPIOE2 output set</description>
              <bitRange>[2:2]</bitRange>
            </field>
            <field>
              <name>BS3</name>
              <description>GPIOE3 output set</description>
              <bitRange>[3:3]</bitRange>
            </field>
            <field>
              <name>BS4</name>
              <description>GPIOE4 output set</description>
              <bitRange>[4:4]</bitRange>
            </field>
            <field>
              <name>BS5</name>
              <description>GPIOE5 output set</description>
              <bitRange>[5:5]</bitRange>
            </field>
            <field>
              <name>BS6</name>
              <description>GPIOE6 output set</description>
              <bitRange>[6:6]</bitRange>
            </field>
            <field>
              <name>BS7</name>
              <description>GPIOE7 output set</description>
              <bitRange>[7:7]</bitRange>
            </field>
            <field>
              <name>BS8</name>
              <description>GPIOE8 output set</description>
              <bitRange>[8:8]</bitRange>
            </field>
            <field>
              <name>BS9</name>
              <description>GPIOE9 output set</description>
              <bitRange>[9:9]</bitRange>
            </field>
            <field>
              <name>BS10</name>
              <description>GPIOE10 output set</description>
              <bitRange>[10:10]</bitRange>
            </field>
            <field>
              <name>BS11</name>
              <description>GPIOE11 output set</description>
              <bitRange>[11:11]</bitRange>
            </field>
            <field>
              <name>BS12</name>
              <description>GPIOE12 output set</description>
              <bitRange>[12:12]</bitRange>
            </field>
            <field>
              <name>BS13</name>
              <description>GPIOE13 output set</description>
              <bitRange>[13:13]</bitRange>
            </field>
            <field>
              <name>BS14</name>
              <description>GPIOE14 output set</description>
              <bitRange>[14:14]</bitRange>
            </field>
            <field>
              <name>BS15</name>
              <description>GPIOE15 output set</description>
              <bitRange>[15:15]</bitRange>
            </field>
            <field>
              <name>BR0</name>
              <description>GPIOE0 outut reset</description>
              <bitRange>[16:16]</bitRange>
            </field>
            <field>
              <name>BR1</name>
              <description>GPIOE1 outut reset</description>
              <bitRange>[17:17]</bitRange>
            </field>
            <field>
              <name>BR2</name>
              <description>GPIOE2 outut reset</description>
              <bitRange>[18:18]</bitRange>
            </field>
            <field>
              <name>BR3</name>
              <description>GPIOE3 outut reset</description>
              <bitRange>[19:19]</bitRange>
            </field>
            <field>
              <name>BR4</name>
              <description>GPIOE4 outut reset</description>
              <bitRange>[20:20]</bitRange>
            </field>
            <field>
              <name>BR5</name>
              <description>GPIOE5 outut reset</description>
              <bitRange>[21:21]</bitRange>
            </field>
            <field>
              <name>BR6</name>
              <description>GPIOE6 outut reset</description>
              <bitRange>[22:22]</bitRange>
            </field>
            <field>
              <name>BR7</name>
              <description>GPIOE7 outut reset</description>
              <bitRange>[23:23]</bitRange>
            </field>
            <field>
              <name>BR8</name>
              <description>GPIOE8 outut reset</description>
              <bitRange>[24:24]</bitRange>
            </field>
            <field>
              <name>BR9</name>
              <description>GPIOE9 outut reset</description>
              <bitRange>[25:25]</bitRange>
            </field>
            <field>
              <name>BR10</name>
              <description>GPIOE10 outut reset</description>
              <bitRange>[26:26]</bitRange>
            </field>
            <field>
              <name>BR11</name>
              <description>GPIOE11 outut reset</description>
              <bitRange>[27:27]</bitRange>
            </field>
            <field>
              <name>BR12</name>
              <description>GPIOE12 outut reset</description>
              <bitRange>[28:28]</bitRange>
            </field>
            <field>
              <name>BR13</name>
              <description>GPIOE13 outut reset</description>
              <bitRange>[29:29]</bitRange>
            </field>
            <field>
              <name>BR14</name>
              <description>GPIOE14 outut reset</description>
              <bitRange>[30:30]</bitRange>
            </field>
            <field>
              <name>BR15</name>
              <description>GPIOE15 outut reset</description>
              <bitRange>[31:31]</bitRange>
            </field>
          </fields>
        </register>
        <register>
          <name>LCKR</name>
          <addressOffset>0x1C</addressOffset>
          <fields>
            <field>
              <name>LCK0</name>
              <description>GPIOE lock(bit0)</description>
              <bitRange>[0:0]</bitRange>
            </field>
            <field>
              <name>LCK1</name>
              <description>GPIOE lock(bit1)</description>
              <bitRange>[1:1]</bitRange>
            </field>
            <field>
              <name>LCK2</name>
              <description>GPIOE lock(bit2)</description>
              <bitRange>[2:2]</bitRange>
            </field>
            <field>
              <name>LCK3</name>
              <description>GPIOE lock(bit3)</description>
              <bitRange>[3:3]</bitRange>
            </field>
            <field>
              <name>LCK4</name>
              <description>GPIOE lock(bit4)</description>
              <bitRange>[4:4]</bitRange>
            </field>
            <field>
              <name>LCK5</name>
              <description>GPIOE lock(bit5)</description>
              <bitRange>[5:5]</bitRange>
            </field>
            <field>
              <name>LCK6</name>
              <description>GPIOE lock(bit6)</description>
              <bitRange>[6:6]</bitRange>
            </field>
            <field>
              <name>LCK7</name>
              <description>GPIOE lock(bit7)</description>
              <bitRange>[7:7]</bitRange>
            </field>
            <field>
              <name>LCK8</name>
              <description>GPIOE lock(bit8)</description>
              <bitRange>[8:8]</bitRange>
            </field>
            <field>
              <name>LCK9</name>
              <description>GPIOE lock(bit9)</description>
              <bitRange>[9:9]</bitRange>
            </field>
            <field>
              <name>LCK10</name>
              <description>GPIOE lock(bit10)</description>
              <bitRange>[10:10]</bitRange>
            </field>
            <field>
              <name>LCK11</name>
              <description>GPIOE lock(bit11)</description>
              <bitRange>[11:11]</bitRange>
            </field>
            <field>
              <name>LCK12</name>
              <description>GPIOE lock(bit12)</description>
              <bitRange>[12:12]</bitRange>
            </field>
            <field>
              <name>LCK13</name>
              <description>GPIOE lock(bit13)</description>
              <bitRange>[13:13]</bitRange>
            </field>
            <field>
              <name>LCK14</name>
              <description>GPIOE lock(bit14)</description>
              <bitRange>[14:14]</bitRange>
            </field>
            <field>
              <name>LCK15</name>
              <description>GPIOE lock(bit15)</description>
              <bitRange>[15:15]</bitRange>
            </field>
            <field>
              <name>LCKK</name>
              <description>GPIOE lock key</description>
              <bitRange>[16:16]</bitRange>
            </field>
          </fields>
        </register>
        <register>
          <name>AFRL</name>
          <addressOffset>0x20</addressOffset>
          <fields>
            <field>
              <name>AFSEL0</name>
              <description>GPIOE0 AF select</description>
              <bitRange>[3:0]</bitRange>
            </field>
            <field>
              <name>AFSEL1</name>
              <description>GPIOE1 AF select</description>
              <bitRange>[7:4]</bitRange>
            </field>
            <field>
              <name>AFSEL2</name>
              <description>GPIOE2 AF select</description>
              <bitRange>[11:8]</bitRange>
            </field>
            <field>
              <name>AFSEL3</name>
              <description>GPIOE3 AF select</description>
              <bitRange>[15:12]</bitRange>
            </field>
            <field>
              <name>AFSEL4</name>
              <description>GPIOE4 AF select</description>
              <bitRange>[19:16]</bitRange>
            </field>
            <field>
              <name>AFSEL5</name>
              <description>GPIOE5 AF select</description>
              <bitRange>[23:20]</bitRange>
            </field>
            <field>
              <name>AFSEL6</name>
              <description>GPIOE6 AF select</description>
              <bitRange>[27:24]</bitRange>
            </field>
            <field>
              <name>AFSEL7</name>
              <description>GPIOE7 AF select</description>
              <bitRange>[31:28]</bitRange>
            </field>
          </fields>
        </register>
        <register>
          <name>AFRH</name>
          <addressOffset>0x24</addressOffset>
          <fields>
            <field>
              <name>AFSEL8</name>
              <description>GPIOE8 AF select</description>
              <bitRange>[3:0]</bitRange>
            </field>
            <field>
              <name>AFSEL9</name>
              <description>GPIOE9 AF select</description>
              <bitRange>[7:4]</bitRange>
            </field>
            <field>
              <name>AFSEL10</name>
              <description>GPIOE10 AF select</description>
              <bitRange>[11:8]</bitRange>
            </field>
            <field>
              <name>AFSEL11</name>
              <description>GPIOE11 AF select</description>
              <bitRange>[15:12]</bitRange>
            </field>
            <field>
              <name>AFSEL12</name>
              <description>GPIOE12 AF select</description>
              <bitRange>[19:16]</bitRange>
            </field>
            <field>
              <name>AFSEL13</name>
              <description>GPIOE13 AF select</description>
              <bitRange>[23:20]</bitRange>
            </field>
            <field>
              <name>AFSEL14</name>
              <description>GPIOE14 AF select</description>
              <bitRange>[27:24]</bitRange>
            </field>
            <field>
              <name>AFSEL15</name>
              <description>GPIOE15 AF select</description>
              <bitRange>[31:28]</bitRange>
            </field>
          </fields>
        </register>
        <register>
          <name>BRR</name>
          <addressOffset>0x28</addressOffset>
          <fields>
            <field>
              <name>BR0</name>
              <description>GPIOE 0 output pin reset</description>
              <bitRange>[0:0]</bitRange>
            </field>
            <field>
              <name>BR1</name>
              <description>GPIOE 1 output pin reset</description>
              <bitRange>[1:1]</bitRange>
            </field>
            <field>
              <name>BR2</name>
              <description>GPIOE 2 output pin reset</description>
              <bitRange>[2:2]</bitRange>
            </field>
            <field>
              <name>BR3</name>
              <description>GPIOE 3 output pin reset</description>
              <bitRange>[3:3]</bitRange>
            </field>
            <field>
              <name>BR4</name>
              <description>GPIOE 4 output pin reset</description>
              <bitRange>[4:4]</bitRange>
            </field>
            <field>
              <name>BR5</name>
              <description>GPIOE 5 output pin reset</description>
              <bitRange>[5:5]</bitRange>
            </field>
            <field>
              <name>BR6</name>
              <description>GPIOE 6 output pin reset</description>
              <bitRange>[6:6]</bitRange>
            </field>
            <field>
              <name>BR7</name>
              <description>GPIOE 7 output pin reset</description>
              <bitRange>[7:7]</bitRange>
            </field>
            <field>
              <name>BR8</name>
              <description>GPIOE 8 output pin reset</description>
              <bitRange>[8:8]</bitRange>
            </field>
            <field>
              <name>BR9</name>
              <description>GPIOE 9 output pin reset</description>
              <bitRange>[9:9]</bitRange>
            </field>
            <field>
              <name>BR10</name>
              <description>GPIOE 10 output pin reset</description>
              <bitRange>[10:10]</bitRange>
            </field>
            <field>
              <name>BR11</name>
              <description>GPIOE 11 output pin reset</description>
              <bitRange>[11:11]</bitRange>
            </field>
            <field>
              <name>BR12</name>
              <description>GPIOE 12 output pin reset</description>
              <bitRange>[12:12]</bitRange>
            </field>
            <field>
              <name>BR13</name>
              <description>GPIOE 13 output pin reset</description>
              <bitRange>[13:13]</bitRange>
            </field>
            <field>
              <name>BR14</name>
              <description>GPIOE 14 output pin reset</description>
              <bitRange>[14:14]</bitRange>
            </field>
            <field>
              <name>BR15</name>
              <description>GPIOE 15 output pin reset</description>
              <bitRange>[15:15]</bitRange>
            </field>
          </fields>
        </register>
      </registers>
    </peripheral>
    <peripheral>
      <name>GPIOF</name>
      <baseAddress>0x48001400</baseAddress>
      <addressBlock>
        <offset>0x0</offset>
        <size>0x400</size>
        <usage>registers</usage>
      </addressBlock>
      <registers>
        <register>
          <name>MODER</name>
          <addressOffset>0x0</addressOffset>
          <fields>
            <field>
              <name>MODER0</name>
              <description>GPIOF0 MODE</description>
              <bitRange>[1:0]</bitRange>
            </field>
            <field>
              <name>MODER1</name>
              <description>GPIOF1 MODE</description>
              <bitRange>[3:2]</bitRange>
            </field>
            <field>
              <name>MODER2</name>
              <description>GPIOF2 MODE</description>
              <bitRange>[5:4]</bitRange>
            </field>
            <field>
              <name>MODER3</name>
              <description>GPIOF3 MODE</description>
              <bitRange>[7:6]</bitRange>
            </field>
            <field>
              <name>MODER4</name>
              <description>GPIOF4 MODE</description>
              <bitRange>[9:8]</bitRange>
            </field>
            <field>
              <name>MODER5</name>
              <description>GPIOF5 MODE</description>
              <bitRange>[11:10]</bitRange>
            </field>
          </fields>
        </register>
        <register>
          <name>OTYPER</name>
          <addressOffset>0x4</addressOffset>
          <fields>
            <field>
              <name>OT0</name>
              <description>GPIOF0 Output type</description>
              <bitRange>[0:0]</bitRange>
            </field>
            <field>
              <name>OT1</name>
              <description>GPIOF1 Output type</description>
              <bitRange>[1:1]</bitRange>
            </field>
            <field>
              <name>OT2</name>
              <description>GPIOF2 Output type</description>
              <bitRange>[2:2]</bitRange>
            </field>
            <field>
              <name>OT3</name>
              <description>GPIOF3 Output type</description>
              <bitRange>[3:3]</bitRange>
            </field>
            <field>
              <name>OT4</name>
              <description>GPIOF4 Output type</description>
              <bitRange>[4:4]</bitRange>
            </field>
            <field>
              <name>OT5</name>
              <description>GPIOF5 Output type</description>
              <bitRange>[5:5]</bitRange>
            </field>
          </fields>
        </register>
        <register>
          <name>OSPDDER</name>
          <addressOffset>0x8</addressOffset>
          <fields>
            <field>
              <name>OSPEED0</name>
              <description>GPIOF0 output speed</description>
              <bitRange>[1:0]</bitRange>
            </field>
            <field>
              <name>OSPEED1</name>
              <description>GPIOF1 output speed</description>
              <bitRange>[3:2]</bitRange>
            </field>
            <field>
              <name>OSPEED2</name>
              <description>GPIOF2 output speed</description>
              <bitRange>[5:4]</bitRange>
            </field>
            <field>
              <name>OSPEED3</name>
              <description>GPIOF3 output speed</description>
              <bitRange>[7:6]</bitRange>
            </field>
            <field>
              <name>OSPEED4</name>
              <description>GPIOF4 output speed</description>
              <bitRange>[9:8]</bitRange>
            </field>
            <field>
              <name>OSPEED5</name>
              <description>GPIOF5 output speed</description>
              <bitRange>[11:10]</bitRange>
            </field>
          </fields>
        </register>
        <register>
          <name>PUPDR</name>
          <addressOffset>0xC</addressOffset>
          <fields>
            <field>
              <name>PUPD0</name>
              <description>GPIOF0 pull up/pull down</description>
              <bitRange>[1:0]</bitRange>
            </field>
            <field>
              <name>PUPD1</name>
              <description>GPIOF1 pull up/pull down</description>
              <bitRange>[3:2]</bitRange>
            </field>
            <field>
              <name>PUPD2</name>
              <description>GPIOF2 pull up/pull down</description>
              <bitRange>[5:4]</bitRange>
            </field>
            <field>
              <name>PUPD3</name>
              <description>GPIOF3 pull up/pull down</description>
              <bitRange>[7:6]</bitRange>
            </field>
            <field>
              <name>PUPD4</name>
              <description>GPIOF4 pull up/pull down</description>
              <bitRange>[9:8]</bitRange>
            </field>
            <field>
              <name>PUPD5</name>
              <description>GPIOF5 pull up/pull down</description>
              <bitRange>[11:10]</bitRange>
            </field>
          </fields>
        </register>
        <register>
          <name>IDR</name>
          <addressOffset>0x10</addressOffset>
          <fields>
            <field>
              <name>ID0</name>
              <description>GPIOF0 input data</description>
              <bitRange>[0:0]</bitRange>
              <access>read-only</access>
            </field>
            <field>
              <name>ID1</name>
              <description>GPIOF1 input data</description>
              <bitRange>[1:1]</bitRange>
              <access>read-only</access>
            </field>
            <field>
              <name>ID2</name>
              <description>GPIOF2 input data</description>
              <bitRange>[2:2]</bitRange>
              <access>read-only</access>
            </field>
            <field>
              <name>ID3</name>
              <description>GPIOF3 input data</description>
              <bitRange>[3:3]</bitRange>
              <access>read-only</access>
            </field>
            <field>
              <name>ID4</name>
              <description>GPIOF4 input data</description>
              <bitRange>[4:4]</bitRange>
              <access>read-only</access>
            </field>
            <field>
              <name>ID5</name>
              <description>GPIOF5 input data</description>
              <bitRange>[5:5]</bitRange>
              <access>read-only</access>
            </field>
          </fields>
        </register>
        <register>
          <name>ODR</name>
          <addressOffset>0x14</addressOffset>
          <fields>
            <field>
              <name>OD0</name>
              <description>GPIOF0 output data</description>
              <bitRange>[0:0]</bitRange>
            </field>
            <field>
              <name>OD1</name>
              <description>GPIOF1 output data</description>
              <bitRange>[1:1]</bitRange>
            </field>
            <field>
              <name>OD2</name>
              <description>GPIOF2 output data</description>
              <bitRange>[2:2]</bitRange>
            </field>
            <field>
              <name>OD3</name>
              <description>GPIOF3 output data</description>
              <bitRange>[3:3]</bitRange>
            </field>
            <field>
              <name>OD4</name>
              <description>GPIOF4 output data</description>
              <bitRange>[4:4]</bitRange>
            </field>
            <field>
              <name>OD5</name>
              <description>GPIOF5 output data</description>
              <bitRange>[5:5]</bitRange>
            </field>
          </fields>
        </register>
        <register>
          <name>BSRR</name>
          <addressOffset>0x18</addressOffset>
          <fields>
            <field>
              <name>BS0</name>
              <description>GPIOF0 output set</description>
              <bitRange>[1:1]</bitRange>
            </field>
            <field>
              <name>BS1</name>
              <description>GPIOF1 output set</description>
              <bitRange>[2:2]</bitRange>
            </field>
            <field>
              <name>BS2</name>
              <description>GPIOF2 output set</description>
              <bitRange>[3:3]</bitRange>
            </field>
            <field>
              <name>BS3</name>
              <description>GPIOF3 output set</description>
              <bitRange>[4:4]</bitRange>
            </field>
            <field>
              <name>BS4</name>
              <description>GPIOF4 output set</description>
              <bitRange>[5:5]</bitRange>
            </field>
            <field>
              <name>BS5</name>
              <description>GPIOF5 output set</description>
              <bitRange>[6:6]</bitRange>
            </field>
            <field>
              <name>BR0</name>
              <description>GPIOF0 outut reset</description>
              <bitRange>[17:17]</bitRange>
            </field>
            <field>
              <name>BR1</name>
              <description>GPIOF1 outut reset</description>
              <bitRange>[18:18]</bitRange>
            </field>
            <field>
              <name>BR2</name>
              <description>GPIOF2 outut reset</description>
              <bitRange>[19:19]</bitRange>
            </field>
            <field>
              <name>BR3</name>
              <description>GPIOF3 outut reset</description>
              <bitRange>[20:20]</bitRange>
            </field>
            <field>
              <name>BR4</name>
              <description>GPIOF4 outut reset</description>
              <bitRange>[21:21]</bitRange>
            </field>
            <field>
              <name>BR5</name>
              <description>GPIOF5 outut reset</description>
              <bitRange>[22:22]</bitRange>
            </field>
          </fields>
        </register>
        <register>
          <name>LCKR</name>
          <addressOffset>0x1C</addressOffset>
          <fields>
            <field>
              <name>LCK0</name>
              <description>GPIOF lock(bit0)</description>
              <bitRange>[0:0]</bitRange>
            </field>
            <field>
              <name>LCK1</name>
              <description>GPIOF lock(bit1)</description>
              <bitRange>[1:1]</bitRange>
            </field>
            <field>
              <name>LCK2</name>
              <description>GPIOF lock(bit2)</description>
              <bitRange>[2:2]</bitRange>
            </field>
            <field>
              <name>LCK3</name>
              <description>GPIOF lock(bit3)</description>
              <bitRange>[3:3]</bitRange>
            </field>
            <field>
              <name>LCK4</name>
              <description>GPIOF lock(bit4)</description>
              <bitRange>[4:4]</bitRange>
            </field>
            <field>
              <name>LCK5</name>
              <description>GPIOF lock(bit5)</description>
              <bitRange>[5:5]</bitRange>
            </field>
            <field>
              <name>LCKK</name>
              <description>GPIOF lock key</description>
              <bitRange>[16:16]</bitRange>
            </field>
          </fields>
        </register>
        <register>
          <name>AFRL</name>
          <addressOffset>0x20</addressOffset>
          <fields>
            <field>
              <name>AFSEL0</name>
              <description>GPIOF0 AF select</description>
              <bitRange>[3:0]</bitRange>
            </field>
            <field>
              <name>AFSEL1</name>
              <description>GPIOF1 AF select</description>
              <bitRange>[7:4]</bitRange>
            </field>
            <field>
              <name>AFSEL2</name>
              <description>GPIOF2 AF select</description>
              <bitRange>[11:8]</bitRange>
            </field>
            <field>
              <name>AFSEL3</name>
              <description>GPIOF3 AF select</description>
              <bitRange>[15:12]</bitRange>
            </field>
            <field>
              <name>AFSEL4</name>
              <description>GPIOF4 AF select</description>
              <bitRange>[19:16]</bitRange>
            </field>
            <field>
              <name>AFSEL5</name>
              <description>GPIOF5 AF select</description>
              <bitRange>[23:20]</bitRange>
            </field>
          </fields>
        </register>
        <register>
          <name>BRR</name>
          <addressOffset>0x28</addressOffset>
          <fields>
            <field>
              <name>BR0</name>
              <description>GPIOF 0 output pin reset</description>
              <bitRange>[0:0]</bitRange>
            </field>
            <field>
              <name>BR1</name>
              <description>GPIOF 1 output pin reset</description>
              <bitRange>[1:1]</bitRange>
            </field>
            <field>
              <name>BR2</name>
              <description>GPIOF 2 output pin reset</description>
              <bitRange>[2:2]</bitRange>
            </field>
            <field>
              <name>BR3</name>
              <description>GPIOF 3 output pin reset</description>
              <bitRange>[3:3]</bitRange>
            </field>
            <field>
              <name>BR4</name>
              <description>GPIOF 4 output pin reset</description>
              <bitRange>[4:4]</bitRange>
            </field>
            <field>
              <name>BR5</name>
              <description>GPIOF 5 output pin reset</description>
              <bitRange>[5:5]</bitRange>
            </field>
          </fields>
        </register>
      </registers>
    </peripheral>
    <peripheral>
      <name>I2C1</name>
      <description>desc I2C</description>
      <groupName>I2C</groupName>
      <baseAddress>0x40005400</baseAddress>
      <addressBlock>
        <offset>0x0</offset>
        <size>0x400</size>
        <usage>registers</usage>
      </addressBlock>
      <interrupt>
        <name>I2C1_EV</name>
        <description>I2C1 Event Interrupt</description>
        <value>31</value>
      </interrupt>
      <interrupt>
        <name>I2C1_ER</name>
        <description>I2C1 Error Interrupt</description>
        <value>32</value>
      </interrupt>
      <registers>
        <register>
          <name>CR1</name>
          <description>desc CR1</description>
          <addressOffset>0x0</addressOffset>
          <fields>
            <field>
              <name>PE</name>
              <description>desc PE</description>
              <bitRange>[0:0]</bitRange>
            </field>
            <field>
              <name>SMBUS</name>
              <description>desc SMBUS</description>
              <bitRange>[1:1]</bitRange>
            </field>
            <field>
              <name>SMBTYPE</name>
              <description>desc SMBTYPE</description>
              <bitRange>[3:3]</bitRange>
            </field>
            <field>
              <name>ENARP</name>
              <description>desc ENARP</description>
              <bitRange>[4:4]</bitRange>
            </field>
            <field>
              <name>ENPEC</name>
              <description>desc ENPEC</description>
              <bitRange>[5:5]</bitRange>
            </field>
            <field>
              <name>ENGC</name>
              <description>desc ENGC</description>
              <bitRange>[6:6]</bitRange>
            </field>
            <field>
              <name>NOSTRETCH</name>
              <description>desc NOSTRETCH</description>
              <bitRange>[7:7]</bitRange>
            </field>
            <field>
              <name>START</name>
              <description>desc START</description>
              <bitRange>[8:8]</bitRange>
            </field>
            <field>
              <name>STOP</name>
              <description>desc STOP</description>
              <bitRange>[9:9]</bitRange>
            </field>
            <field>
              <name>ACK</name>
              <description>desc ACK</description>
              <bitRange>[10:10]</bitRange>
            </field>
            <field>
              <name>POS</name>
              <description>desc POS</description>
              <bitRange>[11:11]</bitRange>
            </field>
            <field>
              <name>PEC</name>
              <description>desc PEC</description>
              <bitRange>[12:12]</bitRange>
            </field>
            <field>
              <name>ALERT</name>
              <description>desc ALERT</description>
              <bitRange>[13:13]</bitRange>
            </field>
            <field>
              <name>SWRST</name>
              <description>desc SWRST</description>
              <bitRange>[15:15]</bitRange>
            </field>
          <field><name>WUPEN</name><description>WUPEN</description><bitRange>[2:2]</bitRange><access>read-write</access></field><field><name>WKUP_DIV</name><description>WKUP_DIV</description><bitRange>[17:16]</bitRange><access>read-write</access></field><field><name>WKUP_CNT</name><description>WKUP_CNT</description><bitRange>[19:18]</bitRange><access>read-write</access></field></fields>
        </register>
        <register>
          <name>CR2</name>
          <description>desc CR2</description>
          <addressOffset>0x4</addressOffset>
          <fields>
            <field>
              <name>FREQ</name>
              <description>desc FREQ</description>
              <bitRange>[5:0]</bitRange>
            </field>
            <field>
              <name>ITERREN</name>
              <description>desc ITERREN</description>
              <bitRange>[8:8]</bitRange>
            </field>
            <field>
              <name>ITEVTEN</name>
              <description>desc ITEVTEN</description>
              <bitRange>[9:9]</bitRange>
            </field>
            <field>
              <name>ITBUFEN</name>
              <description>desc ITBUFEN</description>
              <bitRange>[10:10]</bitRange>
            </field>
            <field>
              <name>DMAEN</name>
              <description>desc DMAEN</description>
              <bitRange>[11:11]</bitRange>
            </field>
            <field>
              <name>LAST</name>
              <description>desc LAST</description>
              <bitRange>[12:12]</bitRange>
            </field>
          </fields>
        </register>
        <register>
          <name>OAR1</name>
          <description>desc OAR1</description>
          <addressOffset>0x8</addressOffset>
          <fields>
            <field>
              <name>ADD0</name>
              <description>desc ADD0</description>
              <bitRange>[0:0]</bitRange>
            </field>
            <field>
              <name>ADD1_7</name>
              <description>desc ADD</description>
              <bitRange>[7:1]</bitRange>
            </field>
            <field>
              <name>ADD8_9</name>
              <description>desc ADD</description>
              <bitRange>[9:8]</bitRange>
            </field>
            <field>
              <name>ADDMODE</name>
              <description>desc ADDMODE</description>
              <bitRange>[15:15]</bitRange>
            </field>
          </fields>
        </register>
        <register>
          <name>OAR2</name>
          <description>desc OAR2</description>
          <addressOffset>0xC</addressOffset>
          <fields>
            <field>
              <name>ENDUAL</name>
              <description>desc ENDUAL</description>
              <bitRange>[0:0]</bitRange>
            </field>
            <field>
              <name>ADD2</name>
              <description>desc ADD2</description>
              <bitRange>[7:1]</bitRange>
            </field>
          </fields>
        </register>
        <register>
          <name>DR</name>
          <description>desc DR</description>
          <addressOffset>0x10</addressOffset>
          <fields>
            <field>
              <name>DR</name>
              <description>desc DR</description>
              <bitRange>[7:0]</bitRange>
            </field>
          </fields>
        </register>
        <register>
          <name>SR1</name>
          <description>desc SR1</description>
          <addressOffset>0x14</addressOffset>
          <fields>
            <field>
              <name>SB</name>
              <description>desc SB</description>
              <bitRange>[0:0]</bitRange>
              <access>read-only</access>
            </field>
            <field>
              <name>ADDR</name>
              <description>desc ADDR</description>
              <bitRange>[1:1]</bitRange>
              <access>read-only</access>
            </field>
            <field>
              <name>BTF</name>
              <description>desc BTF</description>
              <bitRange>[2:2]</bitRange>
              <access>read-only</access>
            </field>
            <field>
              <name>ADD10</name>
              <description>desc ADD10</description>
              <bitRange>[3:3]</bitRange>
              <access>read-only</access>
            </field>
            <field>
              <name>STOPF</name>
              <description>desc STOPF</description>
              <bitRange>[4:4]</bitRange>
              <access>read-only</access>
            </field>
            <field>
              <name>RXNE</name>
              <description>desc RXNE</description>
              <bitRange>[6:6]</bitRange>
              <access>read-only</access>
            </field>
            <field>
              <name>TXE</name>
              <description>desc TXE</description>
              <bitRange>[7:7]</bitRange>
              <access>read-only</access>
            </field>
            <field>
              <name>BERR</name>
              <description>desc BERR</description>
              <bitRange>[8:8]</bitRange>
            </field>
            <field>
              <name>ARLO</name>
              <description>desc ARLO</description>
              <bitRange>[9:9]</bitRange>
            </field>
            <field>
              <name>AF</name>
              <description>desc AF</description>
              <bitRange>[10:10]</bitRange>
            </field>
            <field>
              <name>OVR</name>
              <description>desc OVR</description>
              <bitRange>[11:11]</bitRange>
            </field>
            <field>
              <name>PECERR</name>
              <description>desc PECERR</description>
              <bitRange>[12:12]</bitRange>
            </field>
            <field>
              <name>TIMEOUT</name>
              <description>desc TIMEOUT</description>
              <bitRange>[14:14]</bitRange>
            </field>
            <field>
              <name>SMBALERT</name>
              <description>desc SMBALERT</description>
              <bitRange>[15:15]</bitRange>
            </field>
          </fields>
        </register>
        <register>
          <name>SR2</name>
          <description>desc SR2</description>
          <addressOffset>0x18</addressOffset>
          <fields>
            <field>
              <name>MSL</name>
              <description>desc MSL</description>
              <bitRange>[0:0]</bitRange>
              <access>read-only</access>
            </field>
            <field>
              <name>BUSY</name>
              <description>desc BUSY</description>
              <bitRange>[1:1]</bitRange>
              <access>read-only</access>
            </field>
            <field>
              <name>TRA</name>
              <description>desc TRA</description>
              <bitRange>[2:2]</bitRange>
              <access>read-only</access>
            </field>
            <field>
              <name>GENCALL</name>
              <description>desc GENCALL</description>
              <bitRange>[4:4]</bitRange>
              <access>read-only</access>
            </field>
            <field>
              <name>SMBDEFAULT</name>
              <description>desc SMBDEFAULT</description>
              <bitRange>[5:5]</bitRange>
              <access>read-only</access>
            </field>
            <field>
              <name>SMBHOST</name>
              <description>desc SMBHOST</description>
              <bitRange>[6:6]</bitRange>
              <access>read-only</access>
            </field>
            <field>
              <name>DUALF</name>
              <description>desc DUALF</description>
              <bitRange>[7:7]</bitRange>
              <access>read-only</access>
            </field>
            <field>
              <name>PEC</name>
              <description>desc PEC</description>
              <bitRange>[15:8]</bitRange>
              <access>read-only</access>
            </field>
          </fields>
        </register>
        <register>
          <name>CCR</name>
          <description>desc CCR</description>
          <addressOffset>0x1C</addressOffset>
          <fields>
            <field>
              <name>CCR</name>
              <description>desc CCR</description>
              <bitRange>[11:0]</bitRange>
            </field>
            <field>
              <name>DUTY</name>
              <description>desc DUTY</description>
              <bitRange>[14:14]</bitRange>
            </field>
            <field>
              <name>FS</name>
              <description>desc FS</description>
              <bitRange>[15:15]</bitRange>
            </field>
          <field><name>FP</name><description>FP</description><bitRange>[13:13]</bitRange><access>read-write</access></field></fields>
        </register>
        <register>
          <name>TRISE</name>
          <description>desc TRISE</description>
          <addressOffset>0x20</addressOffset>
          <fields>
            <field>
              <name>TRISE</name>
              <description>desc TRISE</description>
              <bitRange>[5:0]</bitRange>
            </field>
          <field><name>THOLDDATA</name><description>THOLDDATA</description><bitRange>[11:7]</bitRange><access>read-write</access></field><field><name>THOLDDATA_SEL</name><description>THOLDDATA_SEL</description><bitRange>[12:12]</bitRange><access>read-write</access></field></fields>
        </register>
      <register><name>TIMEOUTR</name><description>I2C timeout register</description><addressOffset>0x24</addressOffset><fields><field><name>TIMEOUTA</name><description>TIMEOUTA</description><bitRange>[11:0]</bitRange><access>read-write</access></field><field><name>TIDLE</name><description>TIDLE</description><bitRange>[12:12]</bitRange><access>read-write</access></field><field><name>TIMEOUTEN</name><description>TIMEOUTEN</description><bitRange>[15:15]</bitRange><access>read-write</access></field><field><name>TIMEOUTB</name><description>TIMEOUTB</description><bitRange>[27:16]</bitRange><access>read-write</access></field><field><name>TEXTEN</name><description>TEXTEN</description><bitRange>[31:31]</bitRange><access>read-write</access></field></fields></register></registers>
    </peripheral>
    <peripheral derivedFrom="I2C1">
      <name>I2C2</name>
      <description>desc I2C</description>
      <baseAddress>0x40005800</baseAddress>
      <interrupt>
        <name>I2C2_EV</name>
        <description>I2C2 Event Interrupt</description>
        <value>33</value>
      </interrupt>
      <interrupt>
        <name>I2C2_ER</name>
        <description>I2C2 Error Interrupt</description>
        <value>34</value>
      </interrupt>
    </peripheral>
    <peripheral derivedFrom="I2C1">
      <name>I2C3</name>
      <description>desc I2C</description>
      <baseAddress>0x40007800</baseAddress>
      <interrupt>
        <name>I2C3_EV</name>
        <description>I2C3 Event Interrupt</description>
        <value>63</value>
      </interrupt>
      <interrupt>
        <name>I2C3_ER</name>
        <description>I2C3 Error Interrupt</description>
        <value>64</value>
      </interrupt>
    </peripheral>
    <peripheral derivedFrom="I2C1">
      <name>I2C4</name>
      <description>desc I2C</description>
      <baseAddress>0x40008400</baseAddress>
      <interrupt>
        <name>I2C4_EV</name>
        <description>I2C4 Event Interrupt</description>
        <value>65</value>
      </interrupt>
      <interrupt>
        <name>I2C4_ER</name>
        <description>I2C4 Error Interrupt</description>
        <value>66</value>
      </interrupt>
    </peripheral>
    <peripheral>
      <name>IWDG</name>
      <baseAddress>0x40003000</baseAddress>
      <addressBlock>
        <offset>0x0</offset>
        <size>0x400</size>
        <usage>registers</usage>
      </addressBlock>
      <registers>
        <register>
          <name>KR</name>
          <addressOffset>0x0</addressOffset>
          <fields>
            <field>
              <name>KEY</name>
              <description>IWDG KEY</description>
              <bitRange>[15:0]</bitRange>
            </field>
          </fields>
        </register>
        <register>
          <name>PR</name>
          <addressOffset>0x4</addressOffset>
          <fields>
            <field>
              <name>PR</name>
              <description>IWDG preload</description>
              <bitRange>[2:0]</bitRange>
            </field>
          </fields>
        </register>
        <register>
          <name>RLR</name>
          <addressOffset>0x8</addressOffset>
          <fields>
            <field>
              <name>RL</name>
              <description>IWDG reload</description>
              <bitRange>[11:0]</bitRange>
            </field>
          </fields>
        </register>
        <register>
          <name>SR</name>
          <addressOffset>0xC</addressOffset>
          <fields>
            <field>
              <name>PVU</name>
              <description>Watchdog prescaler value update</description>
              <bitRange>[0:0]</bitRange>
              <access>read-only</access>
            </field>
            <field>
              <name>RVU</name>
              <description>Watchdog counter reload value update</description>
              <bitRange>[1:1]</bitRange>
              <access>read-only</access>
            </field>
          </fields>
        </register>
      </registers>
    </peripheral>
    <peripheral>
      <name>LCDC</name>
      <baseAddress>0x40017400</baseAddress>
      <addressBlock>
        <offset>0x0</offset>
        <size>0x400</size>
        <usage>registers</usage>
      </addressBlock>
      <registers>
        <register>
          <name>CR</name>
          <addressOffset>0x0</addressOffset>
          <fields>
            <field>
              <name>EN0</name>
              <description>LCD0 enable</description>
              <bitRange>[0:0]</bitRange>
            </field>
            <field>
              <name>EN1</name>
              <description>LCD1 enable</description>
              <bitRange>[1:1]</bitRange>
            </field>
            <field>
              <name>EN2</name>
              <description>LCD2 enable</description>
              <bitRange>[2:2]</bitRange>
            </field>
            <field>
              <name>EN3</name>
              <description>LCD3 enable</description>
              <bitRange>[3:3]</bitRange>
            </field>
            <field>
              <name>MODE0</name>
              <description>LCD0 mode</description>
              <bitRange>[4:4]</bitRange>
            </field>
            <field>
              <name>MODE1</name>
              <description>LCD1 mode</description>
              <bitRange>[5:5]</bitRange>
            </field>
            <field>
              <name>MODE2</name>
              <description>LCD2 mode</description>
              <bitRange>[6:6]</bitRange>
            </field>
            <field>
              <name>MODE3</name>
              <description>LCD3 mode</description>
              <bitRange>[7:7]</bitRange>
            </field>
          </fields>
        </register>
        <register>
          <name>LCD0_DR</name>
          <addressOffset>0x4</addressOffset>
          <fields>
            <field>
              <name>D</name>
              <description>LCD0 data register</description>
              <bitRange>[17:0]</bitRange>
            </field>
          </fields>
        </register>
        <register>
          <name>LCD0_CMDR</name>
          <addressOffset>0x8</addressOffset>
          <fields>
            <field>
              <name>CMD</name>
              <description>LCD0 command register</description>
              <bitRange>[7:0]</bitRange>
            </field>
          </fields>
        </register>
        <register>
          <name>LCD0_WCFGR</name>
          <addressOffset>0xC</addressOffset>
          <fields>
            <field>
              <name>ADDSET</name>
              <description>LCD0 write ADDSET</description>
              <bitRange>[3:0]</bitRange>
            </field>
            <field>
              <name>DATAST</name>
              <description>LCD0 write DATAST</description>
              <bitRange>[15:8]</bitRange>
            </field>
            <field>
              <name>DATAHLD</name>
              <description>LCD0 write DATAHLD</description>
              <bitRange>[31:30]</bitRange>
            </field>
          </fields>
        </register>
        <register>
          <name>LCD0_RCFGR</name>
          <addressOffset>0x10</addressOffset>
          <fields>
            <field>
              <name>ADDSET</name>
              <description>LCD0 read ADDSET</description>
              <bitRange>[3:0]</bitRange>
            </field>
            <field>
              <name>DATAST</name>
              <description>LCD0 read DATAST</description>
              <bitRange>[15:8]</bitRange>
            </field>
            <field>
              <name>DATAHLD</name>
              <description>LCD0 read DATAHLD</description>
              <bitRange>[31:30]</bitRange>
            </field>
          </fields>
        </register>
        <register>
          <name>LCD1_DR</name>
          <addressOffset>0x14</addressOffset>
          <fields>
            <field>
              <name>D</name>
              <description>LCD1 data register</description>
              <bitRange>[17:0]</bitRange>
            </field>
          </fields>
        </register>
        <register>
          <name>LCD1_CMDR</name>
          <addressOffset>0x18</addressOffset>
          <fields>
            <field>
              <name>CMD</name>
              <description>LCD1 command register</description>
              <bitRange>[7:0]</bitRange>
            </field>
          </fields>
        </register>
        <register>
          <name>LCD1_WCFGR</name>
          <addressOffset>0x1C</addressOffset>
          <fields>
            <field>
              <name>ADDSET</name>
              <description>LCD1 write ADDSET</description>
              <bitRange>[3:0]</bitRange>
            </field>
            <field>
              <name>DATAST</name>
              <description>LCD1 write DATAST</description>
              <bitRange>[15:8]</bitRange>
            </field>
            <field>
              <name>DATAHLD</name>
              <description>LCD1 write DATAHLD</description>
              <bitRange>[31:30]</bitRange>
            </field>
          </fields>
        </register>
        <register>
          <name>LCD1_RCFGR</name>
          <addressOffset>0x20</addressOffset>
          <fields>
            <field>
              <name>ADDSET</name>
              <description>LCD1 read ADDSET</description>
              <bitRange>[3:0]</bitRange>
            </field>
            <field>
              <name>DATAST</name>
              <description>LCD1 read DATAST</description>
              <bitRange>[15:8]</bitRange>
            </field>
            <field>
              <name>DATAHLD</name>
              <description>LCD1 read DATAHLD</description>
              <bitRange>[31:30]</bitRange>
            </field>
          </fields>
        </register>
        <register>
          <name>LCD2_DR</name>
          <addressOffset>0x24</addressOffset>
          <fields>
            <field>
              <name>D</name>
              <description>LCD2 data register</description>
              <bitRange>[17:0]</bitRange>
            </field>
          </fields>
        </register>
        <register>
          <name>LCD2_CMDR</name>
          <addressOffset>0x28</addressOffset>
          <fields>
            <field>
              <name>CMD</name>
              <description>LCD2 command register</description>
              <bitRange>[7:0]</bitRange>
            </field>
          </fields>
        </register>
        <register>
          <name>LCD2_WCFGR</name>
          <addressOffset>0x2C</addressOffset>
          <fields>
            <field>
              <name>ADDSET</name>
              <description>LCD2 write ADDSET</description>
              <bitRange>[3:0]</bitRange>
            </field>
            <field>
              <name>DATAST</name>
              <description>LCD2 write DATAST</description>
              <bitRange>[15:8]</bitRange>
            </field>
            <field>
              <name>DATAHLD</name>
              <description>LCD2 write DATAHLD</description>
              <bitRange>[31:30]</bitRange>
            </field>
          </fields>
        </register>
        <register>
          <name>LCD2_RCFGR</name>
          <addressOffset>0x30</addressOffset>
          <fields>
            <field>
              <name>ADDSET</name>
              <description>LCD2 read ADDSET</description>
              <bitRange>[3:0]</bitRange>
            </field>
            <field>
              <name>DATAST</name>
              <description>LCD2 read DATAST</description>
              <bitRange>[15:8]</bitRange>
            </field>
            <field>
              <name>DATAHLD</name>
              <description>LCD2 read DATAHLD</description>
              <bitRange>[31:30]</bitRange>
            </field>
          </fields>
        </register>
        <register>
          <name>LCD3_DR</name>
          <addressOffset>0x34</addressOffset>
          <fields>
            <field>
              <name>D</name>
              <description>LCD3 data register</description>
              <bitRange>[17:0]</bitRange>
            </field>
          </fields>
        </register>
        <register>
          <name>LCD3_CMDR</name>
          <addressOffset>0x38</addressOffset>
          <fields>
            <field>
              <name>CMD</name>
              <description>LCD3 command register</description>
              <bitRange>[7:0]</bitRange>
            </field>
          </fields>
        </register>
        <register>
          <name>LCD3_WCFGR</name>
          <addressOffset>0x3C</addressOffset>
          <fields>
            <field>
              <name>ADDSET</name>
              <description>LCD3 write ADDSET</description>
              <bitRange>[3:0]</bitRange>
            </field>
            <field>
              <name>DATAST</name>
              <description>LCD3 write DATAST</description>
              <bitRange>[15:8]</bitRange>
            </field>
            <field>
              <name>DATAHLD</name>
              <description>LCD3 write DATAHLD</description>
              <bitRange>[31:30]</bitRange>
            </field>
          </fields>
        </register>
        <register>
          <name>LCD3_RCFGR</name>
          <addressOffset>0x40</addressOffset>
          <fields>
            <field>
              <name>ADDSET</name>
              <description>LCD3 read ADDSET</description>
              <bitRange>[3:0]</bitRange>
            </field>
            <field>
              <name>DATAST</name>
              <description>LCD3 read DATAST</description>
              <bitRange>[15:8]</bitRange>
            </field>
            <field>
              <name>DATAHLD</name>
              <description>LCD3 read DATAHLD</description>
              <bitRange>[31:30]</bitRange>
            </field>
          </fields>
        </register>
      </registers>
    </peripheral>
    <peripheral>
      <name>LPTIM</name>
      <baseAddress>0x40007C00</baseAddress>
      <addressBlock>
        <offset>0x0</offset>
        <size>0x400</size>
        <usage>registers</usage>
      </addressBlock>
      <interrupt>
        <name>LPTIM</name>
        <description>LPTIM global Interrupt</description>
        <value>80</value>
      </interrupt>
      <registers>
        <register>
          <name>ISR</name>
          <addressOffset>0x0</addressOffset>
          <fields>
            <field>
              <name>CMPM</name>
              <description>Compare match</description>
              <bitRange>[0:0]</bitRange>
              <access>read-only</access>
            </field>
            <field>
              <name>ARRM</name>
              <description>Autoreload match</description>
              <bitRange>[1:1]</bitRange>
              <access>read-only</access>
            </field>
            <field>
              <name>EXTTRIG</name>
              <description>External trigger edge event</description>
              <bitRange>[2:2]</bitRange>
              <access>read-only</access>
            </field>
            <field>
              <name>CMPOK</name>
              <description>Compare register update OK</description>
              <bitRange>[3:3]</bitRange>
              <access>read-only</access>
            </field>
            <field>
              <name>ARROK</name>
              <description>Autoreload register update OK</description>
              <bitRange>[4:4]</bitRange>
              <access>read-only</access>
            </field>
            <field>
              <name>UP</name>
              <description>Counter direction change down to up</description>
              <bitRange>[5:5]</bitRange>
              <access>read-only</access>
            </field>
            <field>
              <name>DOWN</name>
              <description>Counter direction change up to down</description>
              <bitRange>[6:6]</bitRange>
              <access>read-only</access>
            </field>
          </fields>
        </register>
        <register>
          <name>ICR</name>
          <addressOffset>0x4</addressOffset>
          <fields>
            <field>
              <name>CMPMCF</name>
              <description>Compare match clear flag</description>
              <bitRange>[0:0]</bitRange>
            </field>
            <field>
              <name>ARRMCF</name>
              <description>Autoreload match clear flag</description>
              <bitRange>[1:1]</bitRange>
            </field>
            <field>
              <name>EXTTRIGCF</name>
              <description>External trigger valid edge clear flag</description>
              <bitRange>[2:2]</bitRange>
            </field>
            <field>
              <name>CMPOKCF</name>
              <description>Compare register update OK clear flag</description>
              <bitRange>[3:3]</bitRange>
            </field>
            <field>
              <name>ARROKCF</name>
              <description>Autoreload register update OK clear flag</description>
              <bitRange>[4:4]</bitRange>
            </field>
            <field>
              <name>UPCF</name>
              <description>Direction change to UP clear flag</description>
              <bitRange>[5:5]</bitRange>
            </field>
            <field>
              <name>DOWNCF</name>
              <description>Direction change to down clear flag</description>
              <bitRange>[6:6]</bitRange>
            </field>
          </fields>
        </register>
        <register>
          <name>IER</name>
          <addressOffset>0x8</addressOffset>
          <fields>
            <field>
              <name>CMPMIE</name>
              <description>Compare match Interrupt Enable</description>
              <bitRange>[0:0]</bitRange>
            </field>
            <field>
              <name>ARRMIE</name>
              <description>Autoreload match Interrupt Enable</description>
              <bitRange>[1:1]</bitRange>
            </field>
            <field>
              <name>EXTTRIGIE</name>
              <description>External trigger valid edge Interrupt Enable</description>
              <bitRange>[2:2]</bitRange>
            </field>
            <field>
              <name>CMPOKIE</name>
              <description>Compare register update OK Interrupt Enable</description>
              <bitRange>[3:3]</bitRange>
            </field>
            <field>
              <name>ARROKIE</name>
              <description>Autoreload register update OK Interrupt Enable</description>
              <bitRange>[4:4]</bitRange>
            </field>
            <field>
              <name>UPIE</name>
              <description>Direction change to UP Interrupt Enable</description>
              <bitRange>[5:5]</bitRange>
            </field>
            <field>
              <name>DOWNIE</name>
              <description>Direction change to down Interrupt Enable</description>
              <bitRange>[6:6]</bitRange>
            </field>
          </fields>
        </register>
        <register>
          <name>CFGR</name>
          <addressOffset>0xC</addressOffset>
          <fields>
            <field>
              <name>CKSEL</name>
              <description>Clock selector</description>
              <bitRange>[0:0]</bitRange>
            </field>
            <field>
              <name>CKPOL</name>
              <description>Clock Polarity</description>
              <bitRange>[2:1]</bitRange>
            </field>
            <field>
              <name>CKFLT</name>
              <description>Configurable digital filter for external clock</description>
              <bitRange>[4:3]</bitRange>
            </field>
            <field>
              <name>TRGFLT</name>
              <description>Configurable digital filter for trigger</description>
              <bitRange>[7:6]</bitRange>
            </field>
            <field>
              <name>PRESC</name>
              <description>Clock prescaler</description>
              <bitRange>[11:9]</bitRange>
            </field>
            <field>
              <name>TRIGSEL</name>
              <description>Trigger selector</description>
              <bitRange>[15:13]</bitRange>
            </field>
            <field>
              <name>TRIGEN</name>
              <description>Trigger enable and polarity</description>
              <bitRange>[18:17]</bitRange>
            </field>
            <field>
              <name>TIMOUT</name>
              <description>Timeout enable</description>
              <bitRange>[19:19]</bitRange>
            </field>
            <field>
              <name>WAVE</name>
              <description>Waveform shape</description>
              <bitRange>[20:20]</bitRange>
            </field>
            <field>
              <name>WAVPOL</name>
              <description>Waveform shape polarity</description>
              <bitRange>[21:21]</bitRange>
            </field>
            <field>
              <name>PRELOAD</name>
              <description>Registers update mode</description>
              <bitRange>[22:22]</bitRange>
            </field>
            <field>
              <name>COUNTMODE</name>
              <description>counter mode enabled</description>
              <bitRange>[23:23]</bitRange>
            </field>
            <field>
              <name>ENC</name>
              <description>Encoder mode enable</description>
              <bitRange>[24:24]</bitRange>
            </field>
          </fields>
        </register>
        <register>
          <name>CR</name>
          <addressOffset>0x10</addressOffset>
          <fields>
            <field>
              <name>ENABLE</name>
              <description>LPTIM enable</description>
              <bitRange>[0:0]</bitRange>
            </field>
            <field>
              <name>SNGSTRT</name>
              <description>LPTIM start in Single mode</description>
              <bitRange>[1:1]</bitRange>
            </field>
            <field>
              <name>CNTSTRT</name>
              <description>Timer start in Continuous mode</description>
              <bitRange>[2:2]</bitRange>
            </field>
            <field>
              <name>COUNTRST</name>
              <description>Counter reset</description>
              <bitRange>[3:3]</bitRange>
            </field>
            <field>
              <name>RSTARE</name>
              <description>Reset after read enable</description>
              <bitRange>[4:4]</bitRange>
            </field>
          </fields>
        </register>
        <register>
          <name>CMP</name>
          <addressOffset>0x14</addressOffset>
          <fields>
            <field>
              <name>CMP</name>
              <description>Compare value</description>
              <bitRange>[15:0]</bitRange>
            </field>
          </fields>
        </register>
        <register>
          <name>ARR</name>
          <addressOffset>0x18</addressOffset>
          <fields>
            <field>
              <name>ARR</name>
              <description>Auto reload value</description>
              <bitRange>[15:0]</bitRange>
            </field>
          </fields>
        </register>
        <register>
          <name>CNT</name>
          <addressOffset>0x1C</addressOffset>
          <fields>
            <field>
              <name>CNT</name>
              <description>Counter value</description>
              <bitRange>[15:0]</bitRange>
              <access>read-only</access>
            </field>
          </fields>
        </register>
        <register>
          <name>OR</name>
          <addressOffset>0x20</addressOffset>
          <fields>
            <field>
              <name>IN1_L</name>
              <description>LPTimer input 1 remap extension</description>
              <bitRange>[0:0]</bitRange>
            </field>
            <field>
              <name>IN2_L</name>
              <description>LPTimer input 1 remap extension</description>
              <bitRange>[1:1]</bitRange>
            </field>
            <field>
              <name>IN1_H</name>
              <description>LPTimer input 3 remap extension</description>
              <bitRange>[3:2]</bitRange>
            </field>
            <field>
              <name>IN2_H</name>
              <description>LPTimer input 2 remap extension</description>
              <bitRange>[5:4]</bitRange>
            </field>
          </fields>
        </register>
      </registers>
    </peripheral>
    <peripheral>
      <name>LPUART</name>
      <baseAddress>0x40008000</baseAddress>
      <addressBlock>
        <offset>0x0</offset>
        <size>0x400</size>
        <usage>registers</usage>
      </addressBlock>
      <interrupt>
        <name>LPUART</name>
        <description>LPUART global Interrupt</description>
        <value>53</value>
      </interrupt>
      <registers>
        <register>
          <name>CR1</name>
          <addressOffset>0x0</addressOffset>
          <fields>
            <field>
              <name>UE</name>
              <description>LPUART enabled</description>
              <bitRange>[0:0]</bitRange>
            </field>
            <field>
              <name>UESM</name>
              <description>LPUART enabled in Stop mode</description>
              <bitRange>[1:1]</bitRange>
            </field>
            <field>
              <name>RE</name>
              <description>Receive enable</description>
              <bitRange>[2:2]</bitRange>
            </field>
            <field>
              <name>TE</name>
              <description>Transfer enable</description>
              <bitRange>[3:3]</bitRange>
            </field>
            <field>
              <name>IDLEIE</name>
              <description>IDLE interrupt enable</description>
              <bitRange>[4:4]</bitRange>
            </field>
            <field>
              <name>RXFNEIE</name>
              <description>RXFIFO non-null interrupt enable</description>
              <bitRange>[5:5]</bitRange>
            </field>
            <field>
              <name>TCIE</name>
              <description>End of Transfer interrupt enabled</description>
              <bitRange>[6:6]</bitRange>
            </field>
            <field>
              <name>TXFNFIE</name>
              <description>TXFIFO is not full interrupt enabled</description>
              <bitRange>[7:7]</bitRange>
            </field>
            <field>
              <name>PEIE</name>
              <description>PE interrupt enable</description>
              <bitRange>[8:8]</bitRange>
            </field>
            <field>
              <name>PS</name>
              <description>Parity selection</description>
              <bitRange>[9:9]</bitRange>
            </field>
            <field>
              <name>PCE</name>
              <description>Parity control</description>
              <bitRange>[10:10]</bitRange>
            </field>
            <field>
              <name>WAKE</name>
              <description>Receive wake-up mode</description>
              <bitRange>[11:11]</bitRange>
            </field>
            <field>
              <name>M0</name>
              <description>Configure the word length in combination with M1</description>
              <bitRange>[12:12]</bitRange>
            </field>
            <field>
              <name>MME</name>
              <description>Silent mode enabled</description>
              <bitRange>[13:13]</bitRange>
            </field>
            <field>
              <name>CMIE</name>
              <description>Character match interrupt enabled</description>
              <bitRange>[14:14]</bitRange>
            </field>
            <field>
              <name>DEDT</name>
              <description>The time between the transmit frame stop bit and the invalid DE (driver enable) signal</description>
              <bitRange>[20:16]</bitRange>
            </field>
            <field>
              <name>DEAT</name>
              <description>The time between the DE (driver enable) signal validity and the start bit</description>
              <bitRange>[25:21]</bitRange>
            </field>
            <field>
              <name>M1</name>
              <description>The value of {M1,M0} the configurate length</description>
              <bitRange>[28:28]</bitRange>
            </field>
            <field>
              <name>FIFOEN</name>
              <description>FIFO mode enabled</description>
              <bitRange>[29:29]</bitRange>
            </field>
            <field>
              <name>TXFEIE</name>
              <description>TXFIFO null interrupt enabled</description>
              <bitRange>[30:30]</bitRange>
            </field>
            <field>
              <name>RXFFIE</name>
              <description>RXFIFO full interrupt enabled</description>
              <bitRange>[31:31]</bitRange>
            </field>
          </fields>
        </register>
        <register>
          <name>CR2</name>
          <addressOffset>0x4</addressOffset>
          <fields>
            <field>
              <name>ADDM7</name>
              <description>7bit/4bit address detection configuration</description>
              <bitRange>[4:4]</bitRange>
            </field>
            <field>
              <name>STOP</name>
              <description>Stop bit configuration</description>
              <bitRange>[13:12]</bitRange>
            </field>
            <field>
              <name>SWAP</name>
              <description>TX/RX pin interchangeable</description>
              <bitRange>[15:15]</bitRange>
            </field>
            <field>
              <name>RXINV</name>
              <description>The RX pin is active level inverting</description>
              <bitRange>[16:16]</bitRange>
            </field>
            <field>
              <name>TXINV</name>
              <description>TX pin active level inverted</description>
              <bitRange>[17:17]</bitRange>
            </field>
            <field>
              <name>DATAINV</name>
              <description>Inverse binary data processing</description>
              <bitRange>[18:18]</bitRange>
            </field>
            <field>
              <name>MSBFIRST</name>
              <description>MSB first</description>
              <bitRange>[19:19]</bitRange>
            </field>
            <field>
              <name>TXOE_ALWAYS_ON</name>
              <bitRange>[20:20]</bitRange>
            </field>
            <field>
              <name>ADD</name>
              <description>LPUART address</description>
              <bitRange>[31:24]</bitRange>
            </field>
          </fields>
        </register>
        <register>
          <name>CR3</name>
          <addressOffset>0x8</addressOffset>
          <fields>
            <field>
              <name>EIE</name>
              <description>Error interrupts are enabled</description>
              <bitRange>[0:0]</bitRange>
            </field>
            <field>
              <name>HDSEL</name>
              <description>Half-duplex selection</description>
              <bitRange>[3:3]</bitRange>
            </field>
            <field>
              <name>DMAR</name>
              <description>Enable DMA on reception</description>
              <bitRange>[6:6]</bitRange>
            </field>
            <field>
              <name>DMAT</name>
              <description>Enable DMA while transmitting</description>
              <bitRange>[7:7]</bitRange>
            </field>
            <field>
              <name>RTSE</name>
              <description>RTS enabled</description>
              <bitRange>[8:8]</bitRange>
            </field>
            <field>
              <name>CTSE</name>
              <description>CTS enabled</description>
              <bitRange>[9:9]</bitRange>
            </field>
            <field>
              <name>CTSIE</name>
              <description>CTS interrupt enable</description>
              <bitRange>[10:10]</bitRange>
            </field>
            <field>
              <name>OVRDIS</name>
              <description>Overrun is prohibited</description>
              <bitRange>[12:12]</bitRange>
            </field>
            <field>
              <name>DDRE</name>
              <description>Whether DMA is disabled when receiving an error</description>
              <bitRange>[13:13]</bitRange>
            </field>
            <field>
              <name>DEM</name>
              <description>DE mode enabled</description>
              <bitRange>[14:14]</bitRange>
            </field>
            <field>
              <name>DEP</name>
              <description>DE polarity selection</description>
              <bitRange>[15:15]</bitRange>
            </field>
            <field>
              <name>WUS</name>
              <description>Low-power wake-up options</description>
              <bitRange>[21:20]</bitRange>
            </field>
            <field>
              <name>WUFIE</name>
              <description>Low-power wake-up interrupt enable</description>
              <bitRange>[22:22]</bitRange>
            </field>
            <field>
              <name>TXFTIE</name>
              <description>TXFIFO threshold interrupt enabled</description>
              <bitRange>[23:23]</bitRange>
            </field>
            <field>
              <name>RXFTCFG</name>
              <description>RXFIFO full threshold configuration</description>
              <bitRange>[27:25]</bitRange>
            </field>
            <field>
              <name>RXFTIE</name>
              <description>RXFIFO threshold interrupt enabled</description>
              <bitRange>[28:28]</bitRange>
            </field>
            <field>
              <name>TXFTCFG</name>
              <description>TXFIFO threshold configuration</description>
              <bitRange>[31:29]</bitRange>
            </field>
          </fields>
        </register>
        <register>
          <name>BRR</name>
          <addressOffset>0xC</addressOffset>
          <fields>
            <field>
              <name>BBR</name>
              <description>LPUART baud rate</description>
              <bitRange>[19:0]</bitRange>
            </field>
          </fields>
        </register>
        <register>
          <name>RQR</name>
          <addressOffset>0x18</addressOffset>
          <fields>
            <field>
              <name>SBKRQ</name>
              <description>Send an abort request</description>
              <bitRange>[1:1]</bitRange>
            </field>
            <field>
              <name>MMRQ</name>
              <description>Silent mode request</description>
              <bitRange>[2:2]</bitRange>
            </field>
            <field>
              <name>RXFRQ</name>
              <description>Receive a data refresh request</description>
              <bitRange>[3:3]</bitRange>
            </field>
            <field>
              <name>TXFRQ</name>
              <description>Route a data refresh request</description>
              <bitRange>[4:4]</bitRange>
            </field>
          </fields>
        </register>
        <register>
          <name>ISR</name>
          <addressOffset>0x1C</addressOffset>
          <fields>
            <field>
              <name>PE</name>
              <description>Parity error</description>
              <bitRange>[0:0]</bitRange>
              <access>read-only</access>
            </field>
            <field>
              <name>FE</name>
              <description>Frame error flag</description>
              <bitRange>[1:1]</bitRange>
              <access>read-only</access>
            </field>
            <field>
              <name>NE</name>
              <description>START bit noise flag</description>
              <bitRange>[2:2]</bitRange>
              <access>read-only</access>
            </field>
            <field>
              <name>ORE</name>
              <description>Overrun error flag</description>
              <bitRange>[3:3]</bitRange>
              <access>read-only</access>
            </field>
            <field>
              <name>IDLE</name>
              <description>idle flag</description>
              <bitRange>[4:4]</bitRange>
              <access>read-only</access>
            </field>
            <field>
              <name>RXFNE</name>
              <description>RX register not empty</description>
              <bitRange>[5:5]</bitRange>
              <access>read-only</access>
            </field>
            <field>
              <name>TC</name>
              <description>Transmission completion flag</description>
              <bitRange>[6:6]</bitRange>
              <access>read-only</access>
            </field>
            <field>
              <name>TXFNF</name>
              <description>TX register not full</description>
              <bitRange>[7:7]</bitRange>
              <access>read-only</access>
            </field>
            <field>
              <name>CTSIF</name>
              <description>CTS interrupt flag</description>
              <bitRange>[9:9]</bitRange>
              <access>read-only</access>
            </field>
            <field>
              <name>CTS</name>
              <description>CTS flag</description>
              <bitRange>[10:10]</bitRange>
              <access>read-only</access>
            </field>
            <field>
              <name>BUSY</name>
              <description>Busy flag</description>
              <bitRange>[16:16]</bitRange>
              <access>read-only</access>
            </field>
            <field>
              <name>CMF</name>
              <description>Address match flag</description>
              <bitRange>[17:17]</bitRange>
              <access>read-only</access>
            </field>
            <field>
              <name>SBKF</name>
              <description>Send abort flag</description>
              <bitRange>[18:18]</bitRange>
              <access>read-only</access>
            </field>
            <field>
              <name>RWU</name>
              <description>Receive Mute mode wake-up flag</description>
              <bitRange>[19:19]</bitRange>
              <access>read-only</access>
            </field>
            <field>
              <name>WUF</name>
              <description>Wake flag from low-power mode</description>
              <bitRange>[20:20]</bitRange>
              <access>read-only</access>
            </field>
            <field>
              <name>TEACK</name>
              <description>Transport enable acknowledgement flag</description>
              <bitRange>[21:21]</bitRange>
              <access>read-only</access>
            </field>
            <field>
              <name>REACK</name>
              <description>Receive the enable acknowledgment flag</description>
              <bitRange>[22:22]</bitRange>
              <access>read-only</access>
            </field>
            <field>
              <name>TXFE</name>
              <description>TXFIFO empty</description>
              <bitRange>[23:23]</bitRange>
              <access>read-only</access>
            </field>
            <field>
              <name>RXFF</name>
              <description>RXFIFO full logo</description>
              <bitRange>[24:24]</bitRange>
              <access>read-only</access>
            </field>
            <field>
              <name>RXFT</name>
              <description>RCFIFO threshold flag</description>
              <bitRange>[26:26]</bitRange>
              <access>read-only</access>
            </field>
            <field>
              <name>TXFT</name>
              <description>TXFIFO threshold flag</description>
              <bitRange>[27:27]</bitRange>
              <access>read-only</access>
            </field>
          </fields>
        </register>
        <register>
          <name>ICR</name>
          <addressOffset>0x20</addressOffset>
          <fields>
            <field>
              <name>PECF</name>
              <description>Check value error flag reset</description>
              <bitRange>[0:0]</bitRange>
            </field>
            <field>
              <name>FECF</name>
              <description>Frame error flag reset</description>
              <bitRange>[1:1]</bitRange>
            </field>
            <field>
              <name>NECF</name>
              <description>Clear the START bit noise flag</description>
              <bitRange>[2:2]</bitRange>
            </field>
            <field>
              <name>ORECF</name>
              <description>Overrun error flag reset</description>
              <bitRange>[3:3]</bitRange>
            </field>
            <field>
              <name>IDLECF</name>
              <description>Clear idle flag</description>
              <bitRange>[4:4]</bitRange>
            </field>
            <field>
              <name>TCCF</name>
              <description>Transfer completion flag reset</description>
              <bitRange>[6:6]</bitRange>
            </field>
            <field>
              <name>CTSCF</name>
              <description>CTS flag reset</description>
              <bitRange>[9:9]</bitRange>
            </field>
            <field>
              <name>CMCF</name>
              <description>Address matching flag reset</description>
              <bitRange>[17:17]</bitRange>
            </field>
            <field>
              <name>WUCF</name>
              <description>Low power wake-up flag reset</description>
              <bitRange>[20:20]</bitRange>
            </field>
          </fields>
        </register>
        <register>
          <name>RDR</name>
          <addressOffset>0x24</addressOffset>
          <fields>
            <field>
              <name>RDR</name>
              <description>Receive Data Register</description>
              <bitRange>[8:0]</bitRange>
              <access>read-only</access>
            </field>
          </fields>
        </register>
        <register>
          <name>TDR</name>
          <addressOffset>0x28</addressOffset>
          <fields>
            <field>
              <name>TDR</name>
              <description>Transmit Data Register</description>
              <bitRange>[8:0]</bitRange>
            </field>
          </fields>
        </register>
        <register>
          <name>PRESC</name>
          <addressOffset>0x2C</addressOffset>
          <fields>
            <field>
              <name>PRESCALER</name>
              <description>Input clock prescaler register</description>
              <bitRange>[3:0]</bitRange>
            </field>
          </fields>
        </register>
      </registers>
    </peripheral>
    <peripheral>
      <name>OPAMP</name>
      <baseAddress>0x40017000</baseAddress>
      <addressBlock>
        <offset>0x0</offset>
        <size>0x20</size>
        <usage>registers</usage>
      </addressBlock>
      <registers>
        <register>
          <name>CSR1</name>
          <addressOffset>0x0</addressOffset>
          <fields>
            <field>
              <name>OPAEN</name>
              <description>OPA Enable</description>
              <bitRange>[0:0]</bitRange>
            </field>
            <field>
              <name>VP_SEL</name>
              <description>Non reverse input selection</description>
              <bitRange>[3:2]</bitRange>
            </field>
            <field>
              <name>VM_SEL</name>
              <description>Reverse input selection</description>
              <bitRange>[6:5]</bitRange>
            </field>
            <field>
              <name>OPAHSM</name>
              <description>OPA high-speed mode</description>
              <bitRange>[7:7]</bitRange>
            </field>
            <field>
              <name>OPAINTOEN</name>
              <description>OPA internal output enable</description>
              <bitRange>[8:8]</bitRange>
            </field>
            <field>
              <name>OPA_VBIAS</name>
              <description>OPA Bias voltage selection</description>
              <bitRange>[10:9]</bitRange>
            </field>
            <field>
              <name>PGA_GAIN</name>
              <description>OPA configurable amplifier gain value</description>
              <bitRange>[18:14]</bitRange>
            </field>
            <field>
              <name>OPA1_VBSEL</name>
              <description>OPA1 Bias selection</description>
              <bitRange>[29:29]</bitRange>
            </field>
            <field>
              <name>LOCK</name>
              <description>OPAMP1_CSR register Lock</description>
              <bitRange>[31:31]</bitRange>
            </field>
          </fields>
        </register>
        <register>
          <name>CSR2</name>
          <addressOffset>0x4</addressOffset>
          <fields>
            <field>
              <name>OPAEN</name>
              <description>OPA Enable</description>
              <bitRange>[0:0]</bitRange>
            </field>
            <field>
              <name>VP_SEL</name>
              <description>Non reverse input selection</description>
              <bitRange>[3:2]</bitRange>
            </field>
            <field>
              <name>VM_SEL</name>
              <description>Reverse input selection</description>
              <bitRange>[6:5]</bitRange>
            </field>
            <field>
              <name>OPAHSM</name>
              <description>OPA high-speed mode</description>
              <bitRange>[7:7]</bitRange>
            </field>
            <field>
              <name>OPAINTOEN</name>
              <description>OPA internal output enable</description>
              <bitRange>[8:8]</bitRange>
            </field>
            <field>
              <name>PGA_GAIN</name>
              <description>OPA configurable amplifier gain value</description>
              <bitRange>[18:14]</bitRange>
            </field>
            <field>
              <name>OPA2_VBSEL</name>
              <description>OPA2 Bias selection</description>
              <bitRange>[29:29]</bitRange>
            </field>
            <field>
              <name>LOCK</name>
              <description>OPAMP2_CSR register Lock</description>
              <bitRange>[31:31]</bitRange>
            </field>
          </fields>
        </register>
        <register>
          <name>CSR3</name>
          <addressOffset>0x8</addressOffset>
          <fields>
            <field>
              <name>OPAEN</name>
              <description>OPA Enable</description>
              <bitRange>[0:0]</bitRange>
            </field>
            <field>
              <name>VP_SEL</name>
              <description>Non reverse input selection</description>
              <bitRange>[3:2]</bitRange>
            </field>
            <field>
              <name>VM_SEL</name>
              <description>Reverse input selection</description>
              <bitRange>[6:5]</bitRange>
            </field>
            <field>
              <name>OPAHSM</name>
              <description>OPA high-speed mode</description>
              <bitRange>[7:7]</bitRange>
            </field>
            <field>
              <name>OPAINTOEN</name>
              <description>OPA internal output enable</description>
              <bitRange>[8:8]</bitRange>
            </field>
            <field>
              <name>PGA_GAIN</name>
              <description>OPA configurable amplifier gain value</description>
              <bitRange>[18:14]</bitRange>
            </field>
            <field>
              <name>OPA3_VBSEL</name>
              <description>OPA3 Bias selection</description>
              <bitRange>[29:29]</bitRange>
            </field>
            <field>
              <name>LOCK</name>
              <description>OPAMP3_CSR register Lock</description>
              <bitRange>[31:31]</bitRange>
            </field>
          </fields>
        </register>
        <register>
          <name>TCMR1</name>
          <addressOffset>0xC</addressOffset>
          <fields>
            <field>
              <name>VMS_SEL</name>
              <description>OPAMPx reverse phase input secondary selection</description>
              <bitRange>[0:0]</bitRange>
            </field>
            <field>
              <name>VPS_SEL</name>
              <description>OPAMPx non inverting input secondary selection</description>
              <bitRange>[2:1]</bitRange>
            </field>
            <field>
              <name>T1CM_EN</name>
              <description>TIM1 Control Multiplexing Mode Enable</description>
              <bitRange>[3:3]</bitRange>
            </field>
            <field>
              <name>T8CM_EN</name>
              <description>TIM8 Control Multiplexing Mode Enable</description>
              <bitRange>[4:4]</bitRange>
            </field>
            <field>
              <name>LOCK</name>
              <description>OPAMP1_TCMR register Lock</description>
              <bitRange>[31:31]</bitRange>
            </field>
          </fields>
        </register>
        <register>
          <name>TCMR2</name>
          <addressOffset>0x10</addressOffset>
          <fields>
            <field>
              <name>VMS_SEL</name>
              <description>OPAMPx reverse phase input secondary selection</description>
              <bitRange>[0:0]</bitRange>
            </field>
            <field>
              <name>VPS_SEL</name>
              <description>OPAMPx non inverting input secondary selection</description>
              <bitRange>[2:1]</bitRange>
            </field>
            <field>
              <name>T1CM_EN</name>
              <description>TIM1 Control Multiplexing Mode Enable</description>
              <bitRange>[3:3]</bitRange>
            </field>
            <field>
              <name>T8CM_EN</name>
              <description>TIM8 Control Multiplexing Mode Enable</description>
              <bitRange>[4:4]</bitRange>
            </field>
            <field>
              <name>LOCK</name>
              <description>OPAMP2_TCMR register Lock</description>
              <bitRange>[31:31]</bitRange>
            </field>
          </fields>
        </register>
        <register>
          <name>TCMR3</name>
          <addressOffset>0x14</addressOffset>
          <fields>
            <field>
              <name>VMS_SEL</name>
              <description>OPAMPx reverse phase input secondary selection</description>
              <bitRange>[0:0]</bitRange>
            </field>
            <field>
              <name>VPS_SEL</name>
              <description>OPAMPx non inverting input secondary selection</description>
              <bitRange>[2:1]</bitRange>
            </field>
            <field>
              <name>T1CM_EN</name>
              <description>TIM1 Control Multiplexing Mode Enable</description>
              <bitRange>[3:3]</bitRange>
            </field>
            <field>
              <name>T8CM_EN</name>
              <description>TIM8 Control Multiplexing Mode Enable</description>
              <bitRange>[4:4]</bitRange>
            </field>
            <field>
              <name>LOCK</name>
              <description>OPAMP3_TCMR register Lock</description>
              <bitRange>[31:31]</bitRange>
            </field>
          </fields>
        </register>
      </registers>
    </peripheral>
    <peripheral>
      <name>PWR</name>
      <baseAddress>0x40007000</baseAddress>
      <addressBlock>
        <offset>0x0</offset>
        <size>0x400</size>
        <usage>registers</usage>
      </addressBlock>
      <interrupt>
        <name>PVD</name>
        <description>PVD through EXTI Line detection Interrupt</description>
        <value>1</value>
      </interrupt>
      <registers>
        <register>
          <name>CR1</name>
          <addressOffset>0x0</addressOffset>
          <fields>
            <field>
              <name>LPMS</name>
              <bitRange>[1:0]</bitRange>
            </field>
            <field>
              <name>DBP</name>
              <bitRange>[8:8]</bitRange>
            </field>
            <field>
              <name>VOS</name>
              <bitRange>[10:9]</bitRange>
            </field>
            <field>
              <name>BKPVR_VOS</name>
              <bitRange>[12:11]</bitRange>
            </field>
            <field>
              <name>LPR</name>
              <bitRange>[14:14]</bitRange>
            </field>
            <field>
              <name>HSION_CTRL</name>
              <bitRange>[16:16]</bitRange>
            </field>
            <field>
              <name>FLS_WUPT</name>
              <bitRange>[18:17]</bitRange>
            </field>
            <field>
              <name>STDBY_MRRDY_WAIT</name>
              <bitRange>[20:19]</bitRange>
            </field>
          <field><name>SRAM_RETV</name><description>SRAM_RETV</description><bitRange>[12:11]</bitRange><access>read-write</access></field></fields>
        </register>
        <register>
          <name>CR2</name>
          <addressOffset>0x4</addressOffset>
          <fields>
            <field>
              <name>PVDE</name>
              <bitRange>[0:0]</bitRange>
            </field>
            <field>
              <name>PLS</name>
              <bitRange>[3:1]</bitRange>
            </field>
            <field>
              <name>FLTEN</name>
              <bitRange>[8:8]</bitRange>
            </field>
            <field>
              <name>FLT_CTRL</name>
              <bitRange>[11:9]</bitRange>
            </field>
          </fields>
        </register>
        <register>
          <name>CR3</name>
          <addressOffset>0x8</addressOffset>
          <fields>
            <field>
              <name>EWUP1</name>
              <bitRange>[0:0]</bitRange>
            </field>
            <field>
              <name>EWUP2</name>
              <bitRange>[1:1]</bitRange>
            </field>
            <field>
              <name>EWUP3</name>
              <bitRange>[2:2]</bitRange>
            </field>
            <field>
              <name>EWUP4</name>
              <bitRange>[3:3]</bitRange>
            </field>
            <field>
              <name>EWUP5</name>
              <bitRange>[4:4]</bitRange>
            </field>
            <field>
              <name>RRS</name>
              <bitRange>[8:8]</bitRange>
            </field>
          </fields>
        </register>
        <register>
          <name>CR4</name>
          <addressOffset>0xC</addressOffset>
          <fields>
            <field>
              <name>WP1</name>
              <bitRange>[0:0]</bitRange>
            </field>
            <field>
              <name>WP2</name>
              <bitRange>[1:1]</bitRange>
            </field>
            <field>
              <name>WP3</name>
              <bitRange>[2:2]</bitRange>
            </field>
            <field>
              <name>WP4</name>
              <bitRange>[3:3]</bitRange>
            </field>
            <field>
              <name>WP5</name>
              <bitRange>[4:4]</bitRange>
            </field>
          </fields>
        </register>
        <register>
          <name>SR</name>
          <addressOffset>0x10</addressOffset>
          <fields>
            <field>
              <name>WUF1</name>
              <bitRange>[0:0]</bitRange>
              <access>read-only</access>
            </field>
            <field>
              <name>WUF2</name>
              <bitRange>[1:1]</bitRange>
              <access>read-only</access>
            </field>
            <field>
              <name>WUF3</name>
              <bitRange>[2:2]</bitRange>
              <access>read-only</access>
            </field>
            <field>
              <name>WUF4</name>
              <bitRange>[3:3]</bitRange>
              <access>read-only</access>
            </field>
            <field>
              <name>WUF5</name>
              <bitRange>[4:4]</bitRange>
              <access>read-only</access>
            </field>
            <field>
              <name>SBF</name>
              <bitRange>[8:8]</bitRange>
              <access>read-only</access>
            </field>
            <field>
              <name>PVDO</name>
              <bitRange>[16:16]</bitRange>
              <access>read-only</access>
            </field>
          <field><name>MR_RDY</name><description>MR_RDY</description><bitRange>[9:9]</bitRange><access>read-write</access></field></fields>
        </register>
        <register>
          <name>CSR</name>
          <addressOffset>0x14</addressOffset>
          <fields>
            <field>
              <name>CWUF1</name>
              <bitRange>[0:0]</bitRange>
            </field>
            <field>
              <name>CWUF2</name>
              <bitRange>[1:1]</bitRange>
            </field>
            <field>
              <name>CWUF3</name>
              <bitRange>[2:2]</bitRange>
            </field>
            <field>
              <name>CWUF4</name>
              <bitRange>[3:3]</bitRange>
            </field>
            <field>
              <name>CWUF5</name>
              <bitRange>[4:4]</bitRange>
            </field>
            <field>
              <name>CSBF</name>
              <bitRange>[8:8]</bitRange>
            </field>
          </fields>
        </register>
      </registers>
    </peripheral>
    <peripheral>
      <name>RCC</name>
      <baseAddress>0x40021000</baseAddress>
      <addressBlock>
        <offset>0x0</offset>
        <size>0x400</size>
        <usage>registers</usage>
      </addressBlock>
      <interrupt>
        <name>RCC_CTC</name>
        <description>RCC global Interrupt</description>
        <value>5</value>
      </interrupt>
      <registers>
        <register>
          <name>CR</name>
          <addressOffset>0x0</addressOffset>
          <fields>
            <field>
              <name>HSION</name>
              <bitRange>[0:0]</bitRange>
            </field>
            <field>
              <name>HSIRDY</name>
              <bitRange>[1:1]</bitRange>
              <access>read-only</access>
            </field>
            <field>
              <name>HSITRIM</name>
              <bitRange>[7:3]</bitRange>
            </field>
            <field>
              <name>HSICAL_L</name>
              <bitRange>[15:8]</bitRange>
              <access>read-only</access>
            </field>
            <field>
              <name>HSEON</name>
              <bitRange>[16:16]</bitRange>
            </field>
            <field>
              <name>HSERDY</name>
              <bitRange>[17:17]</bitRange>
              <access>read-only</access>
            </field>
            <field>
              <name>HSEBYP</name>
              <bitRange>[18:18]</bitRange>
            </field>
            <field>
              <name>CSSON</name>
              <bitRange>[19:19]</bitRange>
            </field>
            <field>
              <name>HSICAL_H</name>
              <bitRange>[23:21]</bitRange>
              <access>read-only</access>
            </field>
            <field>
              <name>PLLON</name>
              <bitRange>[24:24]</bitRange>
            </field>
            <field>
              <name>PLLRDY</name>
              <bitRange>[25:25]</bitRange>
              <access>read-only</access>
            </field>
          <field><name>HSIKERON</name><description>HSIKERON</description><bitRange>[2:2]</bitRange><access>read-write</access></field></fields>
        </register>
        <register>
          <name>CFGR</name>
          <addressOffset>0x4</addressOffset>
          <fields>
            <field>
              <name>SW</name>
              <bitRange>[1:0]</bitRange>
            </field>
            <field>
              <name>SWS</name>
              <bitRange>[3:2]</bitRange>
            </field>
            <field>
              <name>HPRE</name>
              <bitRange>[7:4]</bitRange>
            </field>
            <field>
              <name>PPRE1</name>
              <bitRange>[10:8]</bitRange>
            </field>
            <field>
              <name>PPRE2</name>
              <bitRange>[13:11]</bitRange>
            </field>
            <field>
              <name>ADCPRE</name>
              <bitRange>[18:16]</bitRange>
            </field>
            <field>
              <name>USBPRE</name>
              <bitRange>[22:20]</bitRange>
            </field>
            <field>
              <name>MCO</name>
              <bitRange>[27:24]</bitRange>
            </field>
          <field><name>SRAM2PRE</name><description>SRAM2PRE</description><bitRange>[23:23]</bitRange><access>read-write</access></field></fields>
        </register>
        <register>
          <name>CIR</name>
          <addressOffset>0x8</addressOffset>
          <fields>
            <field>
              <name>LSIRDYF</name>
              <bitRange>[0:0]</bitRange>
              <access>read-only</access>
            </field>
            <field>
              <name>LSERDYF</name>
              <bitRange>[1:1]</bitRange>
              <access>read-only</access>
            </field>
            <field>
              <name>HSIRDYF</name>
              <bitRange>[2:2]</bitRange>
              <access>read-only</access>
            </field>
            <field>
              <name>HSERDYF</name>
              <bitRange>[3:3]</bitRange>
              <access>read-only</access>
            </field>
            <field>
              <name>PLLRDYF</name>
              <bitRange>[4:4]</bitRange>
              <access>read-only</access>
            </field>
            <field>
              <name>HSI48RDYF</name>
              <bitRange>[5:5]</bitRange>
              <access>read-only</access>
            </field>
            <field>
              <name>CSSF</name>
              <bitRange>[7:7]</bitRange>
              <access>read-only</access>
            </field>
            <field>
              <name>LSIRDYIE</name>
              <bitRange>[8:8]</bitRange>
            </field>
            <field>
              <name>LSERDYIE</name>
              <bitRange>[9:9]</bitRange>
            </field>
            <field>
              <name>HSIRDYIE</name>
              <bitRange>[10:10]</bitRange>
            </field>
            <field>
              <name>HSERDYIE</name>
              <bitRange>[11:11]</bitRange>
            </field>
            <field>
              <name>PLLRDYIE</name>
              <bitRange>[12:12]</bitRange>
            </field>
            <field>
              <name>HSI48RDYIE</name>
              <bitRange>[13:13]</bitRange>
            </field>
            <field>
              <name>LSIRDYC</name>
              <bitRange>[16:16]</bitRange>
            </field>
            <field>
              <name>LSERDYC</name>
              <bitRange>[17:17]</bitRange>
            </field>
            <field>
              <name>HSIRDYC</name>
              <bitRange>[18:18]</bitRange>
            </field>
            <field>
              <name>HSERDYC</name>
              <bitRange>[19:19]</bitRange>
            </field>
            <field>
              <name>PLLRDYC</name>
              <bitRange>[20:20]</bitRange>
            </field>
            <field>
              <name>HSI48RDYC</name>
              <bitRange>[21:21]</bitRange>
            </field>
            <field>
              <name>CSSC</name>
              <bitRange>[23:23]</bitRange>
            </field>
          </fields>
        </register>
        <register>
          <name>AHB1RSTR</name>
          <addressOffset>0x28</addressOffset>
          <fields>
            <field>
              <name>DMA1RST</name>
              <bitRange>[0:0]</bitRange>
            </field>
            <field>
              <name>DMA2RST</name>
              <bitRange>[1:1]</bitRange>
            </field>
            <field>
              <name>CORDICRST</name>
              <bitRange>[5:5]</bitRange>
            </field>
            <field>
              <name>CRCRST</name>
              <bitRange>[6:6]</bitRange>
            </field>
            <field>
              <name>ESMCRST</name>
              <bitRange>[12:12]</bitRange>
            </field>
          </fields>
        </register>
        <register>
          <name>AHB2RSTR</name>
          <addressOffset>0x2C</addressOffset>
          <fields>
            <field>
              <name>IOPARST</name>
              <bitRange>[2:2]</bitRange>
            </field>
            <field>
              <name>IOPBRST</name>
              <bitRange>[3:3]</bitRange>
            </field>
            <field>
              <name>IOPCRST</name>
              <bitRange>[4:4]</bitRange>
            </field>
            <field>
              <name>IOPDRST</name>
              <bitRange>[5:5]</bitRange>
            </field>
            <field>
              <name>IOPERST</name>
              <bitRange>[6:6]</bitRange>
            </field>
            <field>
              <name>IOPFRST</name>
              <bitRange>[7:7]</bitRange>
            </field>
            <field>
              <name>SDIORST</name>
              <bitRange>[9:9]</bitRange>
            </field>
            <field>
              <name>AESRST</name>
              <bitRange>[10:10]</bitRange>
            </field>
            <field>
              <name>USB1RST</name>
              <bitRange>[13:13]</bitRange>
            </field>
            <field>
              <name>USB2RST</name>
              <bitRange>[14:14]</bitRange>
            </field>
            <field>
              <name>ETHRST</name>
              <bitRange>[15:15]</bitRange>
            </field>
          </fields>
        </register>
        <register>
          <name>APB1RSTR1</name>
          <addressOffset>0x38</addressOffset>
          <fields>
            <field>
              <name>TIM2RST</name>
              <bitRange>[0:0]</bitRange>
            </field>
            <field>
              <name>TIM3RST</name>
              <bitRange>[1:1]</bitRange>
            </field>
            <field>
              <name>TIM4RST</name>
              <bitRange>[2:2]</bitRange>
            </field>
            <field>
              <name>TIM5RST</name>
              <bitRange>[3:3]</bitRange>
            </field>
            <field>
              <name>TIM6RST</name>
              <bitRange>[4:4]</bitRange>
            </field>
            <field>
              <name>TIM7RST</name>
              <bitRange>[5:5]</bitRange>
            </field>
            <field>
              <name>TIM12RST</name>
              <bitRange>[6:6]</bitRange>
            </field>
            <field>
              <name>TIM13RST</name>
              <bitRange>[7:7]</bitRange>
            </field>
            <field>
              <name>TIM14RST</name>
              <bitRange>[8:8]</bitRange>
            </field>
            <field>
              <name>TIM18RST</name>
              <bitRange>[9:9]</bitRange>
            </field>
            <field>
              <name>WWDGRST</name>
              <bitRange>[11:11]</bitRange>
            </field>
            <field>
              <name>SPI2RST</name>
              <bitRange>[14:14]</bitRange>
            </field>
            <field>
              <name>SPI3RST</name>
              <bitRange>[15:15]</bitRange>
            </field>
            <field>
              <name>USART2RST</name>
              <bitRange>[17:17]</bitRange>
            </field>
            <field>
              <name>USART3RST</name>
              <bitRange>[18:18]</bitRange>
            </field>
            <field>
              <name>UART1RST</name>
              <bitRange>[19:19]</bitRange>
            </field>
            <field>
              <name>UART2RST</name>
              <bitRange>[20:20]</bitRange>
            </field>
            <field>
              <name>I2C1RST</name>
              <bitRange>[21:21]</bitRange>
            </field>
            <field>
              <name>I2C2RST</name>
              <bitRange>[22:22]</bitRange>
            </field>
            <field>
              <name>UART3RST</name>
              <bitRange>[23:23]</bitRange>
            </field>
            <field>
              <name>CAN1RST</name>
              <bitRange>[25:25]</bitRange>
            </field>
            <field>
              <name>CAN2RST</name>
              <bitRange>[26:26]</bitRange>
            </field>
            <field>
              <name>PWRRST</name>
              <bitRange>[28:28]</bitRange>
            </field>
            <field>
              <name>DACRST</name>
              <bitRange>[29:29]</bitRange>
            </field>
            <field>
              <name>I2C3RST</name>
              <bitRange>[30:30]</bitRange>
            </field>
            <field>
              <name>CTCRST</name>
              <bitRange>[31:31]</bitRange>
            </field>
          </fields>
        </register>
        <register>
          <name>APB1RSTR2</name>
          <addressOffset>0x3C</addressOffset>
          <fields>
            <field>
              <name>LPTIM1RST</name>
              <bitRange>[0:0]</bitRange>
            </field>
            <field>
              <name>LPUART1RST</name>
              <bitRange>[1:1]</bitRange>
            </field>
            <field>
              <name>I2C4RST</name>
              <bitRange>[2:2]</bitRange>
            </field>
          </fields>
        </register>
        <register>
          <name>APB2RSTR</name>
          <addressOffset>0x40</addressOffset>
          <fields>
            <field>
              <name>SYSCFGRST</name>
              <bitRange>[0:0]</bitRange>
            </field>
            <field>
              <name>ADC1RST</name>
              <bitRange>[9:9]</bitRange>
            </field>
            <field>
              <name>ADC2RST</name>
              <bitRange>[10:10]</bitRange>
            </field>
            <field>
              <name>TIM1RST</name>
              <bitRange>[11:11]</bitRange>
            </field>
            <field>
              <name>SPI1RST</name>
              <bitRange>[12:12]</bitRange>
            </field>
            <field>
              <name>TIM8RST</name>
              <bitRange>[13:13]</bitRange>
            </field>
            <field>
              <name>USART1RST</name>
              <bitRange>[14:14]</bitRange>
            </field>
            <field>
              <name>ADC3RST</name>
              <bitRange>[15:15]</bitRange>
            </field>
            <field>
              <name>TIM9RST</name>
              <bitRange>[19:19]</bitRange>
            </field>
            <field>
              <name>TIM10RST</name>
              <bitRange>[20:20]</bitRange>
            </field>
            <field>
              <name>TIM11RST</name>
              <bitRange>[21:21]</bitRange>
            </field>
            <field>
              <name>TIM15RST</name>
              <bitRange>[22:22]</bitRange>
            </field>
            <field>
              <name>TIM16RST</name>
              <bitRange>[23:23]</bitRange>
            </field>
            <field>
              <name>TIM17RST</name>
              <bitRange>[24:24]</bitRange>
            </field>
            <field>
              <name>TIM19RST</name>
              <bitRange>[25:25]</bitRange>
            </field>
            <field>
              <name>RNGRST</name>
              <bitRange>[26:26]</bitRange>
            </field>
            <field>
              <name>COMPRST</name>
              <bitRange>[27:27]</bitRange>
            </field>
            <field>
              <name>OPAMPRST</name>
              <bitRange>[28:28]</bitRange>
            </field>
            <field>
              <name>LCDCRST</name>
              <bitRange>[29:29]</bitRange>
            </field>
          </fields>
        </register>
        <register>
          <name>AHB1ENR</name>
          <addressOffset>0x48</addressOffset>
          <fields>
            <field>
              <name>DMA1EN</name>
              <bitRange>[0:0]</bitRange>
            </field>
            <field>
              <name>DMA2EN</name>
              <bitRange>[1:1]</bitRange>
            </field>
            <field>
              <name>SRAMEN</name>
              <bitRange>[2:2]</bitRange>
            </field>
            <field>
              <name>FMCEN</name>
              <bitRange>[4:4]</bitRange>
            </field>
            <field>
              <name>CORDICEN</name>
              <bitRange>[5:5]</bitRange>
            </field>
            <field>
              <name>CRCEN</name>
              <bitRange>[6:6]</bitRange>
            </field>
            <field>
              <name>ESMCEN</name>
              <bitRange>[12:12]</bitRange>
            </field>
          </fields>
        </register>
        <register>
          <name>AHB2ENR</name>
          <addressOffset>0x4C</addressOffset>
          <fields>
            <field>
              <name>IOPAEN</name>
              <bitRange>[2:2]</bitRange>
            </field>
            <field>
              <name>IOPBEN</name>
              <bitRange>[3:3]</bitRange>
            </field>
            <field>
              <name>IOPCEN</name>
              <bitRange>[4:4]</bitRange>
            </field>
            <field>
              <name>IOPDEN</name>
              <bitRange>[5:5]</bitRange>
            </field>
            <field>
              <name>IOPEEN</name>
              <bitRange>[6:6]</bitRange>
            </field>
            <field>
              <name>IOPFEN</name>
              <bitRange>[7:7]</bitRange>
            </field>
            <field>
              <name>SDIOEN</name>
              <bitRange>[9:9]</bitRange>
            </field>
            <field>
              <name>AESEN</name>
              <bitRange>[10:10]</bitRange>
            </field>
            <field>
              <name>USB1EN</name>
              <bitRange>[13:13]</bitRange>
            </field>
            <field>
              <name>USB2EN</name>
              <bitRange>[14:14]</bitRange>
            </field>
            <field>
              <name>ETHEN</name>
              <bitRange>[15:15]</bitRange>
            </field>
          <field><name>ETHTXEN</name><description>ETHTXEN</description><bitRange>[16:16]</bitRange><access>read-write</access></field><field><name>ETHRXEN</name><description>ETHRXEN</description><bitRange>[17:17]</bitRange><access>read-write</access></field></fields>
        </register>
        <register>
          <name>APB1ENR1</name>
          <addressOffset>0x58</addressOffset>
          <fields>
            <field>
              <name>TIM2EN</name>
              <bitRange>[0:0]</bitRange>
            </field>
            <field>
              <name>TIM3EN</name>
              <bitRange>[1:1]</bitRange>
            </field>
            <field>
              <name>TIM4EN</name>
              <bitRange>[2:2]</bitRange>
            </field>
            <field>
              <name>TIM5EN</name>
              <bitRange>[3:3]</bitRange>
            </field>
            <field>
              <name>TIM6EN</name>
              <bitRange>[4:4]</bitRange>
            </field>
            <field>
              <name>TIM7EN</name>
              <bitRange>[5:5]</bitRange>
            </field>
            <field>
              <name>TIM12EN</name>
              <bitRange>[6:6]</bitRange>
            </field>
            <field>
              <name>TIM13EN</name>
              <bitRange>[7:7]</bitRange>
            </field>
            <field>
              <name>TIM14EN</name>
              <bitRange>[8:8]</bitRange>
            </field>
            <field>
              <name>TIM18EN</name>
              <bitRange>[9:9]</bitRange>
            </field>
            <field>
              <name>WWDGEN</name>
              <bitRange>[11:11]</bitRange>
            </field>
            <field>
              <name>SPI2EN</name>
              <bitRange>[14:14]</bitRange>
            </field>
            <field>
              <name>SPI3EN</name>
              <bitRange>[15:15]</bitRange>
            </field>
            <field>
              <name>USART2EN</name>
              <bitRange>[17:17]</bitRange>
            </field>
            <field>
              <name>USART3EN</name>
              <bitRange>[18:18]</bitRange>
            </field>
            <field>
              <name>UART1EN</name>
              <bitRange>[19:19]</bitRange>
            </field>
            <field>
              <name>UART2EN</name>
              <bitRange>[20:20]</bitRange>
            </field>
            <field>
              <name>I2C1EN</name>
              <bitRange>[21:21]</bitRange>
            </field>
            <field>
              <name>I2C2EN</name>
              <bitRange>[22:22]</bitRange>
            </field>
            <field>
              <name>UART3EN</name>
              <bitRange>[23:23]</bitRange>
            </field>
            <field>
              <name>CAN1EN</name>
              <bitRange>[25:25]</bitRange>
            </field>
            <field>
              <name>CAN2EN</name>
              <bitRange>[26:26]</bitRange>
            </field>
            <field>
              <name>BKPEN</name>
              <bitRange>[27:27]</bitRange>
            </field>
            <field>
              <name>PWREN</name>
              <bitRange>[28:28]</bitRange>
            </field>
            <field>
              <name>DACEN</name>
              <bitRange>[29:29]</bitRange>
            </field>
            <field>
              <name>I2C3EN</name>
              <bitRange>[30:30]</bitRange>
            </field>
            <field>
              <name>CTCEN</name>
              <bitRange>[31:31]</bitRange>
            </field>
          </fields>
        </register>
        <register>
          <name>APB1ENR2</name>
          <addressOffset>0x5C</addressOffset>
          <fields>
            <field>
              <name>LPTIM1EN</name>
              <bitRange>[0:0]</bitRange>
            </field>
            <field>
              <name>LPUART1EN</name>
              <bitRange>[1:1]</bitRange>
            </field>
            <field>
              <name>I2C4EN</name>
              <bitRange>[2:2]</bitRange>
            </field>
          </fields>
        </register>
        <register>
          <name>APB2ENR</name>
          <addressOffset>0x60</addressOffset>
          <fields>
            <field>
              <name>SYSCFGEN</name>
              <bitRange>[0:0]</bitRange>
            </field>
            <field>
              <name>ADC1EN</name>
              <bitRange>[9:9]</bitRange>
            </field>
            <field>
              <name>ADC2EN</name>
              <bitRange>[10:10]</bitRange>
            </field>
            <field>
              <name>TIM1EN</name>
              <bitRange>[11:11]</bitRange>
            </field>
            <field>
              <name>SPI1EN</name>
              <bitRange>[12:12]</bitRange>
            </field>
            <field>
              <name>TIM8EN</name>
              <bitRange>[13:13]</bitRange>
            </field>
            <field>
              <name>USART1EN</name>
              <bitRange>[14:14]</bitRange>
            </field>
            <field>
              <name>ADC3EN</name>
              <bitRange>[15:15]</bitRange>
            </field>
            <field>
              <name>TIM9EN</name>
              <bitRange>[19:19]</bitRange>
            </field>
            <field>
              <name>TIM10EN</name>
              <bitRange>[20:20]</bitRange>
            </field>
            <field>
              <name>TIM11EN</name>
              <bitRange>[21:21]</bitRange>
            </field>
            <field>
              <name>TIM15EN</name>
              <bitRange>[22:22]</bitRange>
            </field>
            <field>
              <name>TIM16EN</name>
              <bitRange>[23:23]</bitRange>
            </field>
            <field>
              <name>TIM17EN</name>
              <bitRange>[24:24]</bitRange>
            </field>
            <field>
              <name>TIM19EN</name>
              <bitRange>[25:25]</bitRange>
            </field>
            <field>
              <name>RNGEN</name>
              <bitRange>[26:26]</bitRange>
            </field>
            <field>
              <name>COMPEN</name>
              <bitRange>[27:27]</bitRange>
            </field>
            <field>
              <name>OPAMPEN</name>
              <bitRange>[28:28]</bitRange>
            </field>
            <field>
              <name>LCDCEN</name>
              <bitRange>[29:29]</bitRange>
            </field>
          <field><name>OPAEN</name><description>OPAEN</description><bitRange>[28:28]</bitRange><access>read-write</access></field></fields>
        </register>
        <register>
          <name>CCIPR</name>
          <addressOffset>0x68</addressOffset>
          <fields>
            <field>
              <name>USART1SEL</name>
              <bitRange>[1:0]</bitRange>
            </field>
            <field>
              <name>USART2SEL</name>
              <bitRange>[3:2]</bitRange>
            </field>
            <field>
              <name>USART3SEL</name>
              <bitRange>[5:4]</bitRange>
            </field>
            <field>
              <name>LPUART1SEL</name>
              <bitRange>[13:12]</bitRange>
            </field>
            <field>
              <name>LPTIM1SEL</name>
              <bitRange>[15:14]</bitRange>
            </field>
            <field>
              <name>COMP1SEL</name>
              <bitRange>[17:16]</bitRange>
            </field>
            <field>
              <name>COMP2SEL</name>
              <bitRange>[19:18]</bitRange>
            </field>
            <field>
              <name>COMP3SEL</name>
              <bitRange>[21:20]</bitRange>
            </field>
            <field>
              <name>COMP4SEL</name>
              <bitRange>[23:22]</bitRange>
            </field>
          </fields>
        </register>
        <register>
          <name>BDCR</name>
          <addressOffset>0x70</addressOffset>
          <fields>
            <field>
              <name>LSEON</name>
              <bitRange>[0:0]</bitRange>
            </field>
            <field>
              <name>LSERDY</name>
              <bitRange>[1:1]</bitRange>
              <access>read-only</access>
            </field>
            <field>
              <name>LSEBYP</name>
              <bitRange>[2:2]</bitRange>
            </field>
            <field>
              <name>LSEDRV</name>
              <bitRange>[4:3]</bitRange>
            </field>
            <field>
              <name>RTCSEL</name>
              <bitRange>[9:8]</bitRange>
            </field>
            <field>
              <name>RTCEN</name>
              <bitRange>[15:15]</bitRange>
            </field>
            <field>
              <name>BDRST</name>
              <bitRange>[16:16]</bitRange>
            </field>
          </fields>
        </register>
        <register>
          <name>CSR</name>
          <addressOffset>0x74</addressOffset>
          <fields>
            <field>
              <name>LSION</name>
              <bitRange>[0:0]</bitRange>
            </field>
            <field>
              <name>LSIRDY</name>
              <bitRange>[1:1]</bitRange>
              <access>read-only</access>
            </field>
            <field>
              <name>RMVF</name>
              <bitRange>[24:24]</bitRange>
            </field>
            <field>
              <name>OBLRSTF</name>
              <bitRange>[25:25]</bitRange>
              <access>read-only</access>
            </field>
            <field>
              <name>PINRSTF</name>
              <bitRange>[26:26]</bitRange>
              <access>read-only</access>
            </field>
            <field>
              <name>PWRRSTF</name>
              <bitRange>[27:27]</bitRange>
              <access>read-only</access>
            </field>
            <field>
              <name>SFTRSTF</name>
              <bitRange>[28:28]</bitRange>
              <access>read-only</access>
            </field>
            <field>
              <name>IWDGRSTF</name>
              <bitRange>[29:29]</bitRange>
              <access>read-only</access>
            </field>
            <field>
              <name>WWDGRSTF</name>
              <bitRange>[30:30]</bitRange>
              <access>read-only</access>
            </field>
            <field>
              <name>LPWRRSTF</name>
              <bitRange>[31:31]</bitRange>
              <access>read-only</access>
            </field>
          </fields>
        </register>
        <register>
          <name>CFGR1</name>
          <addressOffset>0x78</addressOffset>
          <fields>
            <field>
              <name>MCOPRE</name>
              <bitRange>[2:0]</bitRange>
            </field>
            <field>
              <name>HSI48ON</name>
              <bitRange>[4:4]</bitRange>
            </field>
            <field>
              <name>HSI48RDY</name>
              <bitRange>[5:5]</bitRange>
              <access>read-only</access>
            </field>
            <field>
              <name>HSI48TRIM</name>
              <bitRange>[15:9]</bitRange>
            </field>
            <field>
              <name>HSI48CAL</name>
              <bitRange>[28:16]</bitRange>
              <access>read-only</access>
            </field>
            <field>
              <name>PVDSEL</name>
              <bitRange>[30:29]</bitRange>
            </field>
            <field>
              <name>USBSELHSI48</name>
              <bitRange>[31:31]</bitRange>
            </field>
          </fields>
        </register>
        <register>
          <name>CFGR2</name>
          <addressOffset>0x7C</addressOffset>
          <fields>
            <field>
              <name>CANCKSEL</name>
              <bitRange>[3:0]</bitRange>
            </field>
            <field>
              <name>HSEDRV</name>
              <bitRange>[9:8]</bitRange>
            </field>
          </fields>
        </register>
        <register>
          <name>CFGR3</name>
          <addressOffset>0x80</addressOffset>
          <fields>
            <field>
              <name>PLLSRC</name>
              <bitRange>[0:0]</bitRange>
            </field>
            <field>
              <name>PLLXTPRE</name>
              <bitRange>[1:1]</bitRange>
            </field>
            <field>
              <name>PLLPREDIV</name>
              <bitRange>[3:2]</bitRange>
            </field>
            <field>
              <name>PLLPOSTDIV</name>
              <bitRange>[5:4]</bitRange>
            </field>
            <field>
              <name>PLLFBDIV</name>
              <bitRange>[15:8]</bitRange>
            </field>
            <field>
              <name>PLLCPGAIN</name>
              <bitRange>[19:16]</bitRange>
            </field>
          </fields>
        </register>
      </registers>
    </peripheral>
    <peripheral>
      <name>RNG</name>
      <baseAddress>0x40016800</baseAddress>
      <addressBlock>
        <offset>0x0</offset>
        <size>0x400</size>
        <usage>registers</usage>
      </addressBlock>
      <interrupt>
        <name>RNG</name>
        <description>RNG global Interrupt</description>
        <value>69</value>
      </interrupt>
      <registers>
        <register>
          <name>CR</name>
          <addressOffset>0x0</addressOffset>
          <fields>
            <field>
              <name>RBG0_EN</name>
              <bitRange>[0:0]</bitRange>
            </field>
            <field>
              <name>RBG1_EN</name>
              <bitRange>[1:1]</bitRange>
            </field>
            <field>
              <name>IE</name>
              <bitRange>[2:2]</bitRange>
            </field>
          </fields>
        </register>
        <register>
          <name>ALGR</name>
          <addressOffset>0x4</addressOffset>
          <fields>
            <field>
              <name>RNG_ALG</name>
              <bitRange>[31:0]</bitRange>
            </field>
          </fields>
        </register>
        <register>
          <name>SR</name>
          <addressOffset>0x8</addressOffset>
          <fields>
            <field>
              <name>DATA_RDY</name>
              <bitRange>[0:0]</bitRange>
              <access>read-only</access>
            </field>
          </fields>
        </register>
        <register>
          <name>DR</name>
          <addressOffset>0xC</addressOffset>
          <fields>
            <field>
              <name>RNG_DATA</name>
              <bitRange>[31:0]</bitRange>
              <access>read-only</access>
            </field>
          </fields>
        </register>
        <register>
          <name>RSSR</name>
          <addressOffset>0x10</addressOffset>
          <fields>
            <field>
              <name>RSS0</name>
              <bitRange>[0:0]</bitRange>
              <access>read-only</access>
            </field>
            <field>
              <name>RSS1</name>
              <bitRange>[1:1]</bitRange>
              <access>read-only</access>
            </field>
          </fields>
        </register>
      </registers>
    </peripheral>
    <peripheral>
      <name>RTC</name>
      <baseAddress>0x40002800</baseAddress>
      <addressBlock>
        <offset>0x0</offset>
        <size>0x400</size>
        <usage>registers</usage>
      </addressBlock>
      <interrupt>
        <name>TAMPER</name>
        <description>Intrusion detection global interrupt</description>
        <value>2</value>
      </interrupt>
      <interrupt>
        <name>RTC</name>
        <description>RTC global interrupt</description>
        <value>3</value>
      </interrupt>
      <registers>
        <register>
          <name>CRH</name>
          <addressOffset>0x0</addressOffset>
          <fields>
            <field>
              <name>SECIE</name>
              <description>Second interrupt enable</description>
              <bitRange>[0:0]</bitRange>
            </field>
            <field>
              <name>ALRIE</name>
              <description>Alarm interrupt enable</description>
              <bitRange>[1:1]</bitRange>
            </field>
            <field>
              <name>OWIE</name>
              <description>Overflow interrupt enable</description>
              <bitRange>[2:2]</bitRange>
            </field>
          </fields>
        </register>
        <register>
          <name>CRL</name>
          <addressOffset>0x4</addressOffset>
          <fields>
            <field>
              <name>SECF</name>
              <description>Second flag</description>
              <bitRange>[0:0]</bitRange>
            </field>
            <field>
              <name>ALRF</name>
              <description>Alarm flag</description>
              <bitRange>[1:1]</bitRange>
            </field>
            <field>
              <name>OWF</name>
              <description>Overflow flag</description>
              <bitRange>[2:2]</bitRange>
            </field>
            <field>
              <name>RSF</name>
              <description>Registers synchronized flag</description>
              <bitRange>[3:3]</bitRange>
            </field>
            <field>
              <name>CNF</name>
              <description>Configuration flag</description>
              <bitRange>[4:4]</bitRange>
            </field>
            <field>
              <name>RTOFF</name>
              <description>RTC operation OFF</description>
              <bitRange>[5:5]</bitRange>
              <access>read-only</access>
            </field>
          </fields>
        </register>
        <register>
          <name>PRL0</name>
          <addressOffset>0x8</addressOffset>
          <size>8</size>
          <fields>
            <field>
              <name>PRL</name>
              <description>RTC pre-scaler reload value byte0</description>
              <bitRange>[7:0]</bitRange>
            </field>
          </fields>
        </register>
        <register>
          <name>PRL1</name>
          <addressOffset>0xC</addressOffset>
          <size>8</size>
          <fields>
            <field>
              <name>PRL</name>
              <description>RTC pre-scaler reload value byte1</description>
              <bitRange>[7:0]</bitRange>
            </field>
          </fields>
        </register>
        <register>
          <name>PRL2</name>
          <addressOffset>0x10</addressOffset>
          <size>8</size>
          <fields>
            <field>
              <name>PRL</name>
              <description>RTC pre-scaler reload value byte2</description>
              <bitRange>[3:0]</bitRange>
            </field>
          </fields>
        </register>
        <register>
          <name>DIV0</name>
          <addressOffset>0x14</addressOffset>
          <size>8</size>
          <fields>
            <field>
              <name>RTC_DIV</name>
              <description>RTC clock divider byte0</description>
              <bitRange>[7:0]</bitRange>
              <access>read-only</access>
            </field>
          </fields>
        </register>
        <register>
          <name>DIV1</name>
          <addressOffset>0x18</addressOffset>
          <size>8</size>
          <fields>
            <field>
              <name>RTC_DIV</name>
              <description>RTC clock divider byte1</description>
              <bitRange>[7:0]</bitRange>
              <access>read-only</access>
            </field>
          </fields>
        </register>
        <register>
          <name>DIV2</name>
          <addressOffset>0x1C</addressOffset>
          <size>8</size>
          <fields>
            <field>
              <name>RTC_DIV</name>
              <description>RTC clock divider byte2</description>
              <bitRange>[3:0]</bitRange>
              <access>read-only</access>
            </field>
          </fields>
        </register>
        <register>
          <name>CNT0</name>
          <addressOffset>0x20</addressOffset>
          <size>8</size>
          <fields>
            <field>
              <name>RTC_CNT</name>
              <description>RTC counter byte0</description>
              <bitRange>[7:0]</bitRange>
            </field>
          </fields>
        </register>
        <register>
          <name>CNT1</name>
          <addressOffset>0x24</addressOffset>
          <size>8</size>
          <fields>
            <field>
              <name>RTC_CNT</name>
              <description>RTC counter byte1</description>
              <bitRange>[7:0]</bitRange>
            </field>
          </fields>
        </register>
        <register>
          <name>CNT2</name>
          <addressOffset>0x28</addressOffset>
          <size>8</size>
          <fields>
            <field>
              <name>RTC_CNT</name>
              <description>RTC counter byte2</description>
              <bitRange>[7:0]</bitRange>
            </field>
          </fields>
        </register>
        <register>
          <name>CNT3</name>
          <addressOffset>0x2C</addressOffset>
          <size>8</size>
          <fields>
            <field>
              <name>RTC_CNT</name>
              <description>RTC counter byte3</description>
              <bitRange>[7:0]</bitRange>
            </field>
          </fields>
        </register>
        <register>
          <name>ALR0</name>
          <addressOffset>0x30</addressOffset>
          <size>8</size>
          <fields>
            <field>
              <name>RTC_ALR</name>
              <description>RTC alarm byte0</description>
              <bitRange>[7:0]</bitRange>
            </field>
          </fields>
        </register>
        <register>
          <name>ALR1</name>
          <addressOffset>0x34</addressOffset>
          <size>8</size>
          <fields>
            <field>
              <name>RTC_ALR</name>
              <description>RTC alarm byte1</description>
              <bitRange>[7:0]</bitRange>
            </field>
          </fields>
        </register>
        <register>
          <name>ALR2</name>
          <addressOffset>0x38</addressOffset>
          <size>8</size>
          <fields>
            <field>
              <name>RTC_ALR</name>
              <description>RTC alarm byte2</description>
              <bitRange>[7:0]</bitRange>
            </field>
          </fields>
        </register>
        <register>
          <name>ALR3</name>
          <addressOffset>0x3C</addressOffset>
          <size>8</size>
          <fields>
            <field>
              <name>RTC_ALR</name>
              <description>RTC alarm byte3</description>
              <bitRange>[7:0]</bitRange>
            </field>
          </fields>
        </register>
      </registers>
    </peripheral>
    <peripheral>
      <name>SDIO</name>
      <description>desc SDIO</description>
      <baseAddress>0x48002000</baseAddress>
      <addressBlock>
        <offset>0x0</offset>
        <size>0x400</size>
        <usage>registers</usage>
      </addressBlock>
      <interrupt>
        <name>SDIO</name>
        <description>SDIO global Interrupt</description>
        <value>49</value>
      </interrupt>
      <registers>
        <register>
          <name>POWER</name>
          <description>desc POWER</description>
          <addressOffset>0x0</addressOffset>
          <fields>
            <field>
              <name>PWRCTRL</name>
              <description>desc PWRCTRL</description>
              <bitRange>[0:0]</bitRange>
            </field>
          </fields>
        </register>
        <register>
          <name>CLKCR</name>
          <description>desc CLKCR</description>
          <addressOffset>0x4</addressOffset>
          <fields>
            <field>
              <name>CLKDIV</name>
              <description>desc CLKDIV</description>
              <bitRange>[7:0]</bitRange>
            </field>
            <field>
              <name>CLKEN</name>
              <description>desc CLKEN</description>
              <bitRange>[8:8]</bitRange>
            </field>
            <field>
              <name>PWRSAV</name>
              <description>desc PWRSAV</description>
              <bitRange>[9:9]</bitRange>
            </field>
            <field>
              <name>WIDBUS</name>
              <description>desc WIDBUS</description>
              <bitRange>[11:10]</bitRange>
            </field>
            <field>
              <name>SMPCLKSEL</name>
              <description>desc SMPCLKSEL</description>
              <bitRange>[12:12]</bitRange>
            </field>
            <field>
              <name>SMPEN</name>
              <description>desc SMPEN</description>
              <bitRange>[13:13]</bitRange>
            </field>
            <field>
              <name>CKSEL</name>
              <description>desc CKSEL</description>
              <bitRange>[14:14]</bitRange>
            </field>
          </fields>
        </register>
        <register>
          <name>ARG</name>
          <description>desc ARG</description>
          <addressOffset>0x8</addressOffset>
          <fields>
            <field>
              <name>CMDARG</name>
              <description>desc CMDARG</description>
              <bitRange>[31:0]</bitRange>
            </field>
          </fields>
        </register>
        <register>
          <name>CMD</name>
          <description>desc CMD</description>
          <addressOffset>0xC</addressOffset>
          <fields>
            <field>
              <name>CMDINDEX</name>
              <description>desc CMDINDEX</description>
              <bitRange>[5:0]</bitRange>
            </field>
            <field>
              <name>WAITRESP</name>
              <description>desc WAITRESP</description>
              <bitRange>[6:6]</bitRange>
            </field>
            <field>
              <name>RESPLEN</name>
              <description>desc RESPLEN</description>
              <bitRange>[7:7]</bitRange>
            </field>
            <field>
              <name>CHECKRESPCRC</name>
              <description>desc CHECKRESPCRC</description>
              <bitRange>[8:8]</bitRange>
            </field>
            <field>
              <name>DEXPECT</name>
              <description>desc DEXPECT</description>
              <bitRange>[9:9]</bitRange>
            </field>
            <field>
              <name>DIR</name>
              <description>desc DIR</description>
              <bitRange>[10:10]</bitRange>
            </field>
            <field>
              <name>DTMODE</name>
              <description>desc DTMODE</description>
              <bitRange>[11:11]</bitRange>
            </field>
            <field>
              <name>AUTOSTOP</name>
              <description>desc AUTOSTOP</description>
              <bitRange>[12:12]</bitRange>
            </field>
            <field>
              <name>WAITPEND</name>
              <description>desc WAITPEND</description>
              <bitRange>[13:13]</bitRange>
            </field>
            <field>
              <name>ABORTCMD</name>
              <description>desc ABORTCMD</description>
              <bitRange>[14:14]</bitRange>
            </field>
            <field>
              <name>AUTOINIT</name>
              <description>desc AUTOINIT</description>
              <bitRange>[15:15]</bitRange>
            </field>
            <field>
              <name>REGSYNC</name>
              <description>desc REGSYNC</description>
              <bitRange>[21:21]</bitRange>
            </field>
            <field>
              <name>ATACMD</name>
              <description>desc ATACMD</description>
              <bitRange>[22:22]</bitRange>
            </field>
            <field>
              <name>IEN</name>
              <description>desc IEN</description>
              <bitRange>[23:23]</bitRange>
            </field>
            <field>
              <name>BOOTEN</name>
              <description>desc BOOTEN</description>
              <bitRange>[24:24]</bitRange>
            </field>
            <field>
              <name>BOOTACK</name>
              <description>desc BOOTACK</description>
              <bitRange>[25:25]</bitRange>
            </field>
            <field>
              <name>BOOTDIS</name>
              <description>desc BOOTDIS</description>
              <bitRange>[26:26]</bitRange>
            </field>
            <field>
              <name>BOOTMODE</name>
              <description>desc BOOTMODE</description>
              <bitRange>[27:27]</bitRange>
            </field>
            <field>
              <name>STARTCMD</name>
              <description>desc STARTCMD</description>
              <bitRange>[31:31]</bitRange>
            </field>
          </fields>
        </register>
        <register>
          <name>RESPCMD</name>
          <description>desc RESPCMD</description>
          <addressOffset>0x10</addressOffset>
          <fields>
            <field>
              <name>RESPCMD</name>
              <description>desc RESPCMD</description>
              <bitRange>[5:0]</bitRange>
              <access>read-only</access>
            </field>
          </fields>
        </register>
        <register>
          <name>RESP0</name>
          <description>desc RESP0</description>
          <addressOffset>0x14</addressOffset>
          <fields>
            <field>
              <name>CARDSTATUS1</name>
              <description>desc CARDSTATUS1</description>
              <bitRange>[31:0]</bitRange>
              <access>read-only</access>
            </field>
          </fields>
        </register>
        <register>
          <name>RESP1</name>
          <description>desc RESP1</description>
          <addressOffset>0x18</addressOffset>
          <fields>
            <field>
              <name>CARDSTATUS2</name>
              <description>desc CARDSTATUS2</description>
              <bitRange>[31:0]</bitRange>
              <access>read-only</access>
            </field>
          </fields>
        </register>
        <register>
          <name>RESP2</name>
          <description>desc RESP2</description>
          <addressOffset>0x1C</addressOffset>
          <fields>
            <field>
              <name>CARDSTATUS3</name>
              <description>desc CARDSTATUS3</description>
              <bitRange>[31:0]</bitRange>
              <access>read-only</access>
            </field>
          </fields>
        </register>
        <register>
          <name>RESP3</name>
          <description>desc RESP3</description>
          <addressOffset>0x20</addressOffset>
          <fields>
            <field>
              <name>CARDSTATUS4</name>
              <description>desc CARDSTATUS4</description>
              <bitRange>[31:0]</bitRange>
              <access>read-only</access>
            </field>
          </fields>
        </register>
        <register>
          <name>TMOUT</name>
          <description>desc TMOUT</description>
          <addressOffset>0x24</addressOffset>
          <fields>
            <field>
              <name>RESPTIME</name>
              <description>desc RESPTIME</description>
              <bitRange>[7:0]</bitRange>
            </field>
            <field>
              <name>DATATIME</name>
              <description>desc DATATIME</description>
              <bitRange>[31:8]</bitRange>
            </field>
          </fields>
        </register>
        <register>
          <name>BLKSIZ</name>
          <description>desc BLKSIZ</description>
          <addressOffset>0x28</addressOffset>
          <fields>
            <field>
              <name>DBLOCKSIZE</name>
              <description>desc DBLOCKSIZE</description>
              <bitRange>[15:0]</bitRange>
            </field>
          </fields>
        </register>
        <register>
          <name>DLEN</name>
          <description>desc DLEN</description>
          <addressOffset>0x2C</addressOffset>
          <fields>
            <field>
              <name>DATALENGTH</name>
              <description>desc DATALENGTH</description>
              <bitRange>[31:0]</bitRange>
            </field>
          </fields>
        </register>
        <register>
          <name>CTRL</name>
          <description>desc CTRL</description>
          <addressOffset>0x30</addressOffset>
          <fields>
            <field>
              <name>SDIORST</name>
              <description>desc SDIORST</description>
              <bitRange>[0:0]</bitRange>
            </field>
            <field>
              <name>FIFORST</name>
              <description>desc FIFORST</description>
              <bitRange>[1:1]</bitRange>
            </field>
            <field>
              <name>INTEN</name>
              <description>desc INTEN</description>
              <bitRange>[4:4]</bitRange>
            </field>
            <field>
              <name>DMAEN</name>
              <description>desc DMAEN</description>
              <bitRange>[5:5]</bitRange>
            </field>
            <field>
              <name>READWAIT</name>
              <description>desc READWAIT</description>
              <bitRange>[6:6]</bitRange>
            </field>
            <field>
              <name>AUTOIRQRESP</name>
              <description>desc AUTOIRQRESP</description>
              <bitRange>[7:7]</bitRange>
            </field>
            <field>
              <name>ABORTRD</name>
              <description>desc ABORTRD</description>
              <bitRange>[8:8]</bitRange>
            </field>
            <field>
              <name>CCSDEN</name>
              <description>desc CCSDEN</description>
              <bitRange>[9:9]</bitRange>
            </field>
            <field>
              <name>AUTOSTOPCCSD</name>
              <description>desc AUTOSTOPCCSD</description>
              <bitRange>[10:10]</bitRange>
            </field>
            <field>
              <name>CEATAINTEN</name>
              <description>desc CEATAINTEN</description>
              <bitRange>[11:11]</bitRange>
            </field>
            <field>
              <name>ODPUEN</name>
              <description>desc ODPUEN</description>
              <bitRange>[24:24]</bitRange>
            </field>
          </fields>
        </register>
        <register>
          <name>STATUS</name>
          <description>desc STATUS</description>
          <addressOffset>0x34</addressOffset>
          <fields>
            <field>
              <name>RXWMARK</name>
              <description>desc RXWMARK</description>
              <bitRange>[0:0]</bitRange>
              <access>read-only</access>
            </field>
            <field>
              <name>TXWMARK</name>
              <description>desc TXWMARK</description>
              <bitRange>[1:1]</bitRange>
              <access>read-only</access>
            </field>
            <field>
              <name>FIFOE</name>
              <description>desc FIFOE</description>
              <bitRange>[2:2]</bitRange>
              <access>read-only</access>
            </field>
            <field>
              <name>FIFOF</name>
              <description>desc FIFOF</description>
              <bitRange>[3:3]</bitRange>
              <access>read-only</access>
            </field>
            <field>
              <name>CMDFSM</name>
              <description>desc CMDFSM</description>
              <bitRange>[7:4]</bitRange>
              <access>read-only</access>
            </field>
            <field>
              <name>CARDPRESENT</name>
              <description>desc CARDPRESENT</description>
              <bitRange>[8:8]</bitRange>
              <access>read-only</access>
            </field>
            <field>
              <name>CARDBSY</name>
              <description>desc CARDBSY</description>
              <bitRange>[9:9]</bitRange>
              <access>read-only</access>
            </field>
            <field>
              <name>FIFOCNT</name>
              <description>desc FIFOCNT</description>
              <bitRange>[29:17]</bitRange>
              <access>read-only</access>
            </field>
          </fields>
        </register>
        <register>
          <name>INTSTS</name>
          <description>desc INTSTS</description>
          <addressOffset>0x38</addressOffset>
          <fields>
            <field>
              <name>CAD</name>
              <description>desc CAD</description>
              <bitRange>[0:0]</bitRange>
            </field>
            <field>
              <name>RE</name>
              <description>desc RE</description>
              <bitRange>[1:1]</bitRange>
            </field>
            <field>
              <name>CD</name>
              <description>desc CD</description>
              <bitRange>[2:2]</bitRange>
            </field>
            <field>
              <name>DTO</name>
              <description>desc DTO</description>
              <bitRange>[3:3]</bitRange>
            </field>
            <field>
              <name>TXDR</name>
              <description>desc TXDR</description>
              <bitRange>[4:4]</bitRange>
            </field>
            <field>
              <name>RXDR</name>
              <description>desc RXDR</description>
              <bitRange>[5:5]</bitRange>
            </field>
            <field>
              <name>RCRC</name>
              <description>desc RCRC</description>
              <bitRange>[6:6]</bitRange>
            </field>
            <field>
              <name>DCRC</name>
              <description>desc DCRC</description>
              <bitRange>[7:7]</bitRange>
            </field>
            <field>
              <name>RTO_BAR</name>
              <description>desc RTO_BAR</description>
              <bitRange>[8:8]</bitRange>
            </field>
            <field>
              <name>DRTO_BDS</name>
              <description>desc DRTO_BDS</description>
              <bitRange>[9:9]</bitRange>
            </field>
            <field>
              <name>HTO</name>
              <description>desc HTO</description>
              <bitRange>[10:10]</bitRange>
            </field>
            <field>
              <name>FRUN</name>
              <description>desc FRUN</description>
              <bitRange>[11:11]</bitRange>
            </field>
            <field>
              <name>HLE</name>
              <description>desc HLE</description>
              <bitRange>[12:12]</bitRange>
            </field>
            <field>
              <name>SBE</name>
              <description>desc SBE</description>
              <bitRange>[13:13]</bitRange>
            </field>
            <field>
              <name>ACD</name>
              <description>desc ACD</description>
              <bitRange>[14:14]</bitRange>
            </field>
            <field>
              <name>EBE</name>
              <description>desc EBE</description>
              <bitRange>[15:15]</bitRange>
            </field>
            <field>
              <name>SDIOINT</name>
              <description>desc SDIOINT</description>
              <bitRange>[16:16]</bitRange>
            </field>
          </fields>
        </register>
        <register>
          <name>INTMASK</name>
          <description>desc INTMASK</description>
          <addressOffset>0x3C</addressOffset>
          <fields>
            <field>
              <name>CADIE</name>
              <description>desc CADIE</description>
              <bitRange>[0:0]</bitRange>
            </field>
            <field>
              <name>REIE</name>
              <description>desc REIE</description>
              <bitRange>[1:1]</bitRange>
            </field>
            <field>
              <name>CDIE</name>
              <description>desc CDIE</description>
              <bitRange>[2:2]</bitRange>
            </field>
            <field>
              <name>DTOIE</name>
              <description>desc DTOIE</description>
              <bitRange>[3:3]</bitRange>
            </field>
            <field>
              <name>TXDRIE</name>
              <description>desc TXDRIE</description>
              <bitRange>[4:4]</bitRange>
            </field>
            <field>
              <name>RXDRIE</name>
              <description>desc RXDRIE</description>
              <bitRange>[5:5]</bitRange>
            </field>
            <field>
              <name>RCRCIE</name>
              <description>desc RCRCIE</description>
              <bitRange>[6:6]</bitRange>
            </field>
            <field>
              <name>DCRCIE</name>
              <description>desc DCRCIE</description>
              <bitRange>[7:7]</bitRange>
            </field>
            <field>
              <name>RTOIE</name>
              <description>desc RTOIE</description>
              <bitRange>[8:8]</bitRange>
            </field>
            <field>
              <name>DRTOIE</name>
              <description>desc DRTOIE</description>
              <bitRange>[9:9]</bitRange>
            </field>
            <field>
              <name>HTOIE</name>
              <description>desc HTOIE</description>
              <bitRange>[10:10]</bitRange>
            </field>
            <field>
              <name>FRUNIE</name>
              <description>desc FRUNIE</description>
              <bitRange>[11:11]</bitRange>
            </field>
            <field>
              <name>HLEIE</name>
              <description>desc HLEIE</description>
              <bitRange>[12:12]</bitRange>
            </field>
            <field>
              <name>SBEIE</name>
              <description>desc SBEIE</description>
              <bitRange>[13:13]</bitRange>
            </field>
            <field>
              <name>ACDIE</name>
              <description>desc ACDIE</description>
              <bitRange>[14:14]</bitRange>
            </field>
            <field>
              <name>EBEIE</name>
              <description>desc EBEIE</description>
              <bitRange>[15:15]</bitRange>
            </field>
            <field>
              <name>SDIOINTIE</name>
              <description>desc SDIOINTIE</description>
              <bitRange>[16:16]</bitRange>
            </field>
          </fields>
        </register>
        <register>
          <name>FIFOTH</name>
          <description>desc FIFOTH</description>
          <addressOffset>0x40</addressOffset>
          <fields>
            <field>
              <name>TXWMARK</name>
              <description>desc TXWMARK</description>
              <bitRange>[11:0]</bitRange>
            </field>
            <field>
              <name>RXWMARK</name>
              <description>desc RXWMARK</description>
              <bitRange>[27:16]</bitRange>
            </field>
          </fields>
        </register>
        <register>
          <name>TCBCNT</name>
          <description>desc TCBCNT</description>
          <addressOffset>0x44</addressOffset>
          <fields>
            <field>
              <name>TCBCNT</name>
              <description>desc TCBCNT</description>
              <bitRange>[31:0]</bitRange>
              <access>read-only</access>
            </field>
          </fields>
        </register>
        <register>
          <name>TBBCNT</name>
          <description>desc TBBCNT</description>
          <addressOffset>0x48</addressOffset>
          <fields>
            <field>
              <name>TBBCNT</name>
              <description>desc TBBCNT</description>
              <bitRange>[31:0]</bitRange>
              <access>read-only</access>
            </field>
          </fields>
        </register>
      <register><name>FIFODATA</name><description>SDIO FIFO data register</description><addressOffset>0x200</addressOffset><fields><field><name>FIFODATA</name><description>FIFODATA</description><bitRange>[31:0]</bitRange><access>read-write</access></field></fields></register></registers>
    </peripheral>
    <peripheral>
      <name>SPI1</name>
      <groupName>SPI</groupName>
      <baseAddress>0x40013000</baseAddress>
      <addressBlock>
        <offset>0x0</offset>
        <size>0x400</size>
        <usage>registers</usage>
      </addressBlock>
      <interrupt>
        <name>SPI1</name>
        <description>SPI1 global Interrupt</description>
        <value>35</value>
      </interrupt>
      <registers>
        <register>
          <name>CR1</name>
          <addressOffset>0x0</addressOffset>
          <fields>
            <field>
              <name>CPHA</name>
              <description>Clock Phase</description>
              <bitRange>[0:0]</bitRange>
            </field>
            <field>
              <name>CPOL</name>
              <description>Clock Polarity</description>
              <bitRange>[1:1]</bitRange>
            </field>
            <field>
              <name>MSTR</name>
              <description>Master Selection</description>
              <bitRange>[2:2]</bitRange>
            </field>
            <field>
              <name>BR</name>
              <description>Baud Rate Control</description>
              <bitRange>[5:3]</bitRange>
            </field>
            <field>
              <name>SPE</name>
              <description>SPI Enable</description>
              <bitRange>[6:6]</bitRange>
            </field>
            <field>
              <name>LSBFIRST</name>
              <description>Frame Format</description>
              <bitRange>[7:7]</bitRange>
            </field>
            <field>
              <name>SSI</name>
              <description>Internal slave select</description>
              <bitRange>[8:8]</bitRange>
            </field>
            <field>
              <name>SSM</name>
              <description>Software slave management</description>
              <bitRange>[9:9]</bitRange>
            </field>
            <field>
              <name>RXONLY</name>
              <description>Receive only</description>
              <bitRange>[10:10]</bitRange>
            </field>
            <field>
              <name>DFF</name>
              <description>Data frame format</description>
              <bitRange>[11:11]</bitRange>
            </field>
            <field>
              <name>CRCNEXT</name>
              <description>Transmit CRC next</description>
              <bitRange>[12:12]</bitRange>
            </field>
            <field>
              <name>CRCEN</name>
              <description>Hardware CRC calculation enable</description>
              <bitRange>[13:13]</bitRange>
            </field>
            <field>
              <name>BIDIOE</name>
              <description>Output enable in bidirectional mode</description>
              <bitRange>[14:14]</bitRange>
            </field>
            <field>
              <name>BIDIMODE</name>
              <description>Bidirectional data mode enable</description>
              <bitRange>[15:15]</bitRange>
            </field>
          </fields>
        </register>
        <register>
          <name>CR2</name>
          <addressOffset>0x4</addressOffset>
          <fields>
            <field>
              <name>RXDMAEN</name>
              <description>Rx buffer DMA enable</description>
              <bitRange>[0:0]</bitRange>
            </field>
            <field>
              <name>TXDMAEN</name>
              <description>Tx buffer DMA enable</description>
              <bitRange>[1:1]</bitRange>
            </field>
            <field>
              <name>SSOE</name>
              <description>SS Output Enable</description>
              <bitRange>[2:2]</bitRange>
            </field>
            <field>
              <name>CLRTXFIFO</name>
              <description>Clear FIFO</description>
              <bitRange>[4:4]</bitRange>
            </field>
            <field>
              <name>ERRIE</name>
              <description>Error Interrupt Enable</description>
              <bitRange>[5:5]</bitRange>
            </field>
            <field>
              <name>RXNEIE</name>
              <description>RX buffer Not Empty Interrupt Enable</description>
              <bitRange>[6:6]</bitRange>
            </field>
            <field>
              <name>TXEIE</name>
              <description>Tx buffer Empty Interrupt Enable</description>
              <bitRange>[7:7]</bitRange>
            </field>
            <field>
              <name>FRXTH</name>
              <bitRange>[12:12]</bitRange>
            </field>
            <field>
              <name>FRF</name>
              <bitRange>[15:15]</bitRange>
            </field>
          </fields>
        </register>
        <register>
          <name>SR</name>
          <addressOffset>0x8</addressOffset>
          <fields>
            <field>
              <name>RXNE</name>
              <description>Receive buffer Not Empty</description>
              <bitRange>[0:0]</bitRange>
              <access>read-only</access>
            </field>
            <field>
              <name>TXE</name>
              <description>Transmit buffer Empty</description>
              <bitRange>[1:1]</bitRange>
              <access>read-only</access>
            </field>
            <field>
              <name>CHSIDE</name>
              <description>Channel side</description>
              <bitRange>[2:2]</bitRange>
              <access>read-only</access>
            </field>
            <field>
              <name>UDR</name>
              <description>Underrun flag</description>
              <bitRange>[3:3]</bitRange>
              <access>read-only</access>
            </field>
            <field>
              <name>CRCERR</name>
              <description>CRC error flag</description>
              <bitRange>[4:4]</bitRange>
            </field>
            <field>
              <name>MODF</name>
              <description>Mode fault</description>
              <bitRange>[5:5]</bitRange>
            </field>
            <field>
              <name>OVR</name>
              <description>Overrun flag</description>
              <bitRange>[6:6]</bitRange>
              <access>read-only</access>
            </field>
            <field>
              <name>BSY</name>
              <description>Busy flag</description>
              <bitRange>[7:7]</bitRange>
              <access>read-only</access>
            </field>
            <field>
              <name>FRE</name>
              <bitRange>[8:8]</bitRange>
              <access>read-only</access>
            </field>
            <field>
              <name>FRLVL</name>
              <description>FIFO Reception Level</description>
              <bitRange>[10:9]</bitRange>
              <access>read-only</access>
            </field>
            <field>
              <name>FTLVL</name>
              <description>FIFO Transmission Level</description>
              <bitRange>[12:11]</bitRange>
              <access>read-only</access>
            </field>
          </fields>
        </register>
        <register>
          <name>DR</name>
          <addressOffset>0xC</addressOffset>
          <fields>
            <field>
              <name>DR</name>
              <description>Data Register</description>
              <bitRange>[15:0]</bitRange>
            </field>
          </fields>
        </register>
        <register>
          <name>CRCPR</name>
          <addressOffset>0x10</addressOffset>
          <fields>
            <field>
              <name>CRCPOLY</name>
              <description>CRC polynomial register</description>
              <bitRange>[15:0]</bitRange>
            </field>
          </fields>
        </register>
        <register>
          <name>RXCRCR</name>
          <addressOffset>0x14</addressOffset>
          <fields>
            <field>
              <name>RXCRC</name>
              <description>rcv crc reg</description>
              <bitRange>[15:0]</bitRange>
              <access>read-only</access>
            </field>
          </fields>
        </register>
        <register>
          <name>TXCRCR</name>
          <addressOffset>0x18</addressOffset>
          <fields>
            <field>
              <name>TXCRC</name>
              <description>tx crc reg</description>
              <bitRange>[15:0]</bitRange>
              <access>read-only</access>
            </field>
          </fields>
        </register>
        <register>
          <name>I2S_CFGR</name>
          <addressOffset>0x1C</addressOffset>
          <fields>
            <field>
              <name>CHLEN</name>
              <description>Channel length (number of bits per audio channel</description>
              <bitRange>[0:0]</bitRange>
            </field>
            <field>
              <name>DATLEN</name>
              <description>Data length to be transferred</description>
              <bitRange>[2:1]</bitRange>
            </field>
            <field>
              <name>CKPOL</name>
              <description>Steady state clock polarity</description>
              <bitRange>[3:3]</bitRange>
            </field>
            <field>
              <name>I2SSTD</name>
              <description>I2S standard selection</description>
              <bitRange>[5:4]</bitRange>
            </field>
            <field>
              <name>PCMSYNC</name>
              <description>PCM frame synchronization</description>
              <bitRange>[7:7]</bitRange>
            </field>
            <field>
              <name>I2SCFG</name>
              <description>I2S configuration mode</description>
              <bitRange>[9:8]</bitRange>
            </field>
            <field>
              <name>I2SE</name>
              <description>I2S enable</description>
              <bitRange>[10:10]</bitRange>
            </field>
            <field>
              <name>I2SMOD</name>
              <description>I2S mode selection</description>
              <bitRange>[11:11]</bitRange>
            </field>
          </fields>
        </register>
        <register>
          <name>I2SPR</name>
          <addressOffset>0x20</addressOffset>
          <fields>
            <field>
              <name>I2SDIV</name>
              <description>I2S linear prescaler</description>
              <bitRange>[7:0]</bitRange>
            </field>
            <field>
              <name>ODD</name>
              <description>Odd factor for the prescaler</description>
              <bitRange>[8:8]</bitRange>
            </field>
            <field>
              <name>MCKOE</name>
              <description>Master clock output enable</description>
              <bitRange>[9:9]</bitRange>
            </field>
          </fields>
        </register>
      </registers>
    </peripheral>
    <peripheral derivedFrom="SPI1">
      <name>SPI2</name>
      <description>desc SPI</description>
      <baseAddress>0x40003800</baseAddress>
      <interrupt>
        <name>SPI2</name>
        <description>SPI2 global Interrupt</description>
        <value>36</value>
      </interrupt>
    </peripheral>
    <peripheral derivedFrom="SPI1">
      <name>SPI3</name>
      <description>desc SPI</description>
      <baseAddress>0x40003C00</baseAddress>
      <interrupt>
        <name>SPI3</name>
        <description>SPI3 global Interrupt</description>
        <value>51</value>
      </interrupt>
    </peripheral>
    <peripheral>
      <name>SYSCFG</name>
      <baseAddress>0x40010000</baseAddress>
      <addressBlock>
        <offset>0x0</offset>
        <size>0x400</size>
        <usage>registers</usage>
      </addressBlock>
      <registers>
        <register>
          <name>CFGR1</name>
          <addressOffset>0x0</addressOffset>
          <fields>
            <field>
              <name>MEM_MODE</name>
              <description>memory mapping mode</description>
              <bitRange>[1:0]</bitRange>
            </field>
            <field>
              <name>ETH_PHYSEL</name>
              <description>Ethernet PHY Interface selection</description>
              <bitRange>[2:2]</bitRange>
            </field>
            <field>
              <name>TIM2ITR1_REMAP</name>
              <description>timer2 inner trigger input 1 mapping</description>
              <bitRange>[4:3]</bitRange>
            </field>
            <field>
              <name>PTP_PPS_REMAP</name>
              <description>ETH PTP PPS mapping</description>
              <bitRange>[5:5]</bitRange>
            </field>
            <field>
              <name>CTC_SOF_SEL</name>
              <description>selection of usb sof to ctc</description>
              <bitRange>[6:6]</bitRange>
            </field>
            <field>
              <name>I2C1_FMP</name>
              <description>I2C1 Fast-mode Plus driving capability activation</description>
              <bitRange>[7:7]</bitRange>
            </field>
            <field>
              <name>I2C2_FMP</name>
              <description>I2C2 Fast-mode Plus driving capability activation</description>
              <bitRange>[8:8]</bitRange>
            </field>
            <field>
              <name>I2C3_FMP</name>
              <description>I2C3 Fast-mode Plus driving capability activation</description>
              <bitRange>[9:9]</bitRange>
            </field>
            <field>
              <name>I2C4_FMP</name>
              <description>I2C4 Fast-mode Plus driving capability activation</description>
              <bitRange>[10:10]</bitRange>
            </field>
            <field>
              <name>I2C_EIIC</name>
              <description>I2C analog filter enable</description>
              <bitRange>[31:16]</bitRange>
            </field>
          </fields>
        </register>
        <register>
          <name>CFGR2</name>
          <addressOffset>0x4</addressOffset>
          <fields>
            <field>
              <name>CLL</name>
              <description>core lockup enable</description>
              <bitRange>[0:0]</bitRange>
            </field>
            <field>
              <name>SPL</name>
              <description>sram parity lock enable</description>
              <bitRange>[1:1]</bitRange>
            </field>
            <field>
              <name>PVDL</name>
              <description>pvd lock enable</description>
              <bitRange>[2:2]</bitRange>
            </field>
            <field>
              <name>ECCL</name>
              <description>ecc lock</description>
              <bitRange>[3:3]</bitRange>
            </field>
            <field>
              <name>SPF</name>
              <description>SRAM parity flag</description>
              <bitRange>[8:8]</bitRange>
            </field>
          </fields>
        </register>
        <register>
          <name>CFGR3</name>
          <addressOffset>0x8</addressOffset>
          <fields>
            <field>
              <name>DMA1_MAP1</name>
              <description>DMA1 ch1 mapping</description>
              <bitRange>[6:0]</bitRange>
            </field>
            <field>
              <name>DMA1_MAP2</name>
              <description>DMA1 ch2 mapping</description>
              <bitRange>[14:8]</bitRange>
            </field>
            <field>
              <name>DMA1_MAP3</name>
              <description>DMA1 ch3 mapping</description>
              <bitRange>[22:16]</bitRange>
            </field>
            <field>
              <name>DMA1_MAP4</name>
              <description>DMA1 ch4 mapping</description>
              <bitRange>[30:24]</bitRange>
            </field>
          </fields>
        </register>
        <register>
          <name>CFGR4</name>
          <addressOffset>0xC</addressOffset>
          <fields>
            <field>
              <name>DMA1_MAP5</name>
              <description>DMA1 ch5 mapping</description>
              <bitRange>[6:0]</bitRange>
            </field>
            <field>
              <name>DMA1_MAP6</name>
              <description>DMA1 ch6 mapping</description>
              <bitRange>[14:8]</bitRange>
            </field>
            <field>
              <name>DMA2_MAP1</name>
              <description>DMA2 ch1 mapping</description>
              <bitRange>[22:16]</bitRange>
            </field>
            <field>
              <name>DMA2_MAP2</name>
              <description>DMA2 ch2 mapping</description>
              <bitRange>[30:24]</bitRange>
            </field>
          </fields>
        </register>
        <register>
          <name>CFGR5</name>
          <addressOffset>0x10</addressOffset>
          <fields>
            <field>
              <name>DMA2_MAP3</name>
              <description>DMA2 ch3 mapping</description>
              <bitRange>[6:0]</bitRange>
            </field>
            <field>
              <name>DMA2_MAP4</name>
              <description>DMA2 ch4 mapping</description>
              <bitRange>[14:8]</bitRange>
            </field>
            <field>
              <name>DMA2_MAP5</name>
              <description>DMA2 ch5 mapping</description>
              <bitRange>[22:16]</bitRange>
            </field>
            <field>
              <name>DMA2_MAP6</name>
              <description>DMA2 ch6 mapping</description>
              <bitRange>[30:24]</bitRange>
            </field>
          </fields>
        </register>
        <register>
          <name>EXTICR1</name>
          <addressOffset>0x14</addressOffset>
          <fields>
            <field>
              <name>EXTI0</name>
              <description>EXTI 0~3 configuration</description>
              <bitRange>[3:0]</bitRange>
            </field>
            <field>
              <name>EXTI1</name>
              <description>EXTI 0~3 configuration</description>
              <bitRange>[7:4]</bitRange>
            </field>
            <field>
              <name>EXTI2</name>
              <description>EXTI 0~3 configuration</description>
              <bitRange>[11:8]</bitRange>
            </field>
            <field>
              <name>EXTI3</name>
              <description>EXTI 0~3 configuration</description>
              <bitRange>[15:12]</bitRange>
            </field>
          </fields>
        </register>
        <register>
          <name>EXTICR2</name>
          <addressOffset>0x18</addressOffset>
          <fields>
            <field>
              <name>EXTI4</name>
              <description>EXTI 4~7 configuration</description>
              <bitRange>[3:0]</bitRange>
            </field>
            <field>
              <name>EXTI5</name>
              <description>EXTI 4~7 configuration</description>
              <bitRange>[7:4]</bitRange>
            </field>
            <field>
              <name>EXTI6</name>
              <description>EXTI 4~7 configuration</description>
              <bitRange>[11:8]</bitRange>
            </field>
            <field>
              <name>EXTI7</name>
              <description>EXTI 4~7 configuration</description>
              <bitRange>[15:12]</bitRange>
            </field>
          </fields>
        </register>
        <register>
          <name>EXTICR3</name>
          <addressOffset>0x1C</addressOffset>
          <fields>
            <field>
              <name>EXTI8</name>
              <description>EXTI 8~11 configuration</description>
              <bitRange>[3:0]</bitRange>
            </field>
            <field>
              <name>EXTI9</name>
              <description>EXTI 8~11 configuration</description>
              <bitRange>[7:4]</bitRange>
            </field>
            <field>
              <name>EXTI10</name>
              <description>EXTI 8~11 configuration</description>
              <bitRange>[11:8]</bitRange>
            </field>
            <field>
              <name>EXTI11</name>
              <description>EXTI 8~11 configuration</description>
              <bitRange>[15:12]</bitRange>
            </field>
          </fields>
        </register>
        <register>
          <name>EXTICR4</name>
          <addressOffset>0x20</addressOffset>
          <fields>
            <field>
              <name>EXTI12</name>
              <description>EXTI 12~15 configuration</description>
              <bitRange>[3:0]</bitRange>
            </field>
            <field>
              <name>EXTI13</name>
              <description>EXTI 12~15 configuration</description>
              <bitRange>[7:4]</bitRange>
            </field>
            <field>
              <name>EXTI14</name>
              <description>EXTI 12~15 configuration</description>
              <bitRange>[11:8]</bitRange>
            </field>
            <field>
              <name>EXTI15</name>
              <description>EXTI 12~15 configuration</description>
              <bitRange>[15:12]</bitRange>
            </field>
          </fields>
        </register>
        <register>
          <name>PA_ENS</name>
          <addressOffset>0x24</addressOffset>
          <fields>
            <field>
              <name>PA_ENS</name>
              <description>GPIOA noise filter enable</description>
              <bitRange>[15:0]</bitRange>
            </field>
          </fields>
        </register>
        <register>
          <name>PB_ENS</name>
          <addressOffset>0x28</addressOffset>
          <fields>
            <field>
              <name>PB_ENS</name>
              <description>GPIOB noise filter enable</description>
              <bitRange>[15:0]</bitRange>
            </field>
          </fields>
        </register>
        <register>
          <name>PC_ENS</name>
          <addressOffset>0x2C</addressOffset>
          <fields>
            <field>
              <name>PC_ENS</name>
              <description>GPIOC noise filter enable</description>
              <bitRange>[15:0]</bitRange>
            </field>
          </fields>
        </register>
        <register>
          <name>PD_ENS</name>
          <addressOffset>0x30</addressOffset>
          <fields>
            <field>
              <name>PD_ENS</name>
              <description>GPIOD noise filter enable</description>
              <bitRange>[15:0]</bitRange>
            </field>
          </fields>
        </register>
        <register>
          <name>PE_ENS</name>
          <addressOffset>0x34</addressOffset>
          <fields>
            <field>
              <name>PE_ENS</name>
              <description>GPIOE noise filter enable</description>
              <bitRange>[15:0]</bitRange>
            </field>
          </fields>
        </register>
        <register>
          <name>PF_ENS</name>
          <addressOffset>0x38</addressOffset>
          <fields>
            <field>
              <name>PF_ENS</name>
              <description>GPIOF noise filter enable</description>
              <bitRange>[5:0]</bitRange>
            </field>
          </fields>
        </register>
        <register>
          <name>PA_ANA2ENR</name>
          <addressOffset>0x40</addressOffset>
          <fields>
            <field>
              <name>PA0_ENA2</name>
              <description>GPIOA0 ANA2 enable</description>
              <bitRange>[0:0]</bitRange>
            </field>
            <field>
              <name>PA1_ENA2</name>
              <description>GPIOA1 ANA2 enable</description>
              <bitRange>[1:1]</bitRange>
            </field>
            <field>
              <name>PA2_ENA2</name>
              <description>GPIOA2 ANA2 enable</description>
              <bitRange>[2:2]</bitRange>
            </field>
            <field>
              <name>PA3_ENA2</name>
              <description>GPIOA3 ANA2 enable</description>
              <bitRange>[3:3]</bitRange>
            </field>
            <field>
              <name>PA4_ENA2</name>
              <description>GPIOA4 ANA2 enable</description>
              <bitRange>[4:4]</bitRange>
            </field>
            <field>
              <name>PA5_ENA2</name>
              <description>GPIOA5 ANA2 enable</description>
              <bitRange>[5:5]</bitRange>
            </field>
            <field>
              <name>PA7_ENA2</name>
              <description>GPIOA7 ANA2 enable</description>
              <bitRange>[7:7]</bitRange>
            </field>
            <field>
              <name>PA10_ENA2</name>
              <description>GPIOA10 ANA2 enable</description>
              <bitRange>[10:10]</bitRange>
            </field>
          </fields>
        </register>
        <register>
          <name>PB_ANA2ENR</name>
          <addressOffset>0x44</addressOffset>
          <fields>
            <field>
              <name>PB0_ENA2</name>
              <description>GPIOB0 ANA2 enable</description>
              <bitRange>[0:0]</bitRange>
            </field>
            <field>
              <name>PB1_ENA2</name>
              <description>GPIOB1 ANA2 enable</description>
              <bitRange>[1:1]</bitRange>
            </field>
            <field>
              <name>PB2_ENA2</name>
              <description>GPIOB2 ANA2 enable</description>
              <bitRange>[2:2]</bitRange>
            </field>
          </fields>
        </register>
        <register>
          <name>PC_ANA2ENR</name>
          <addressOffset>0x48</addressOffset>
          <fields>
            <field>
              <name>PC0_ENA2</name>
              <description>GPIOC0 ANA2 enable</description>
              <bitRange>[0:0]</bitRange>
            </field>
            <field>
              <name>PC1_ENA2</name>
              <description>GPIOC1 ANA2 enable</description>
              <bitRange>[1:1]</bitRange>
            </field>
            <field>
              <name>PC2_ENA2</name>
              <description>GPIOC2 ANA2 enable</description>
              <bitRange>[2:2]</bitRange>
            </field>
            <field>
              <name>PC3_ENA2</name>
              <description>GPIOC3 ANA2 enable</description>
              <bitRange>[3:3]</bitRange>
            </field>
            <field>
              <name>PC14_ENA2</name>
              <description>GPIOC14 ANA2 enable</description>
              <bitRange>[14:14]</bitRange>
            </field>
            <field>
              <name>PC15_ENA2</name>
              <description>GPIOC15 ANA2 enable</description>
              <bitRange>[15:15]</bitRange>
            </field>
          </fields>
        </register>
        <register>
          <name>PD_ANA2ENR</name>
          <addressOffset>0x4C</addressOffset>
          <fields>
            <field>
              <name>PD10_ENA2</name>
              <description>GPIOD10_ANA2 enable</description>
              <bitRange>[10:10]</bitRange>
            </field>
            <field>
              <name>PD11_ENA2</name>
              <description>GPIOD11_ANA2 enable</description>
              <bitRange>[11:11]</bitRange>
            </field>
            <field>
              <name>PD12_ENA2</name>
              <description>GPIOD12_ANA2 enable</description>
              <bitRange>[12:12]</bitRange>
            </field>
            <field>
              <name>PD13_ENA2</name>
              <description>GPIOD13_ANA2 enable</description>
              <bitRange>[13:13]</bitRange>
            </field>
          </fields>
        </register>
        <register>
          <name>PE_ANA2ENR</name>
          <addressOffset>0x50</addressOffset>
          <fields>
            <field>
              <name>PE7_ENA2</name>
              <description>GPIOE7_ANA2 enable</description>
              <bitRange>[7:7]</bitRange>
            </field>
            <field>
              <name>PE8_ENA2</name>
              <description>GPIOE8_ANA2 enable</description>
              <bitRange>[8:8]</bitRange>
            </field>
            <field>
              <name>PE10_ENA2</name>
              <description>GPIOE10_ANA2 enable</description>
              <bitRange>[10:10]</bitRange>
            </field>
            <field>
              <name>PE11_ENA2</name>
              <description>GPIOE11_ANA2 enable</description>
              <bitRange>[11:11]</bitRange>
            </field>
            <field>
              <name>PE12_ENA2</name>
              <description>GPIOE12_ANA2 enable</description>
              <bitRange>[12:12]</bitRange>
            </field>
          </fields>
        </register>
        <register>
          <name>PF_ANA2ENR</name>
          <addressOffset>0x54</addressOffset>
          <fields>
            <field>
              <name>PF0_ENA2</name>
              <description>GPIOF0_ANA2 enable</description>
              <bitRange>[0:0]</bitRange>
            </field>
            <field>
              <name>PF1_ENA2</name>
              <description>GPIOF1_ANA2 enable</description>
              <bitRange>[1:1]</bitRange>
            </field>
          </fields>
        </register>
        <register>
          <name>SCSR</name>
          <addressOffset>0x70</addressOffset>
          <fields>
            <field>
              <name>CCMER</name>
              <description>CCM SRAM erase</description>
              <bitRange>[0:0]</bitRange>
            </field>
            <field>
              <name>CCM_BSY</name>
              <description>CCM SRAM busy</description>
              <bitRange>[1:1]</bitRange>
              <access>read-only</access>
            </field>
          </fields>
        </register>
        <register>
          <name>SWPR</name>
          <addressOffset>0x74</addressOffset>
          <fields>
            <field>
              <name>P0WP</name>
              <description>CCM SRAM page 0 write protection</description>
              <bitRange>[0:0]</bitRange>
            </field>
            <field>
              <name>P1WP</name>
              <description>CCM SRAM page 1 write protection</description>
              <bitRange>[1:1]</bitRange>
            </field>
            <field>
              <name>P2WP</name>
              <description>CCM SRAM page 2 write protection</description>
              <bitRange>[2:2]</bitRange>
            </field>
            <field>
              <name>P3WP</name>
              <description>CCM SRAM page 3 write protection</description>
              <bitRange>[3:3]</bitRange>
            </field>
            <field>
              <name>P4WP</name>
              <description>CCM SRAM page 4 write protection</description>
              <bitRange>[4:4]</bitRange>
            </field>
            <field>
              <name>P5WP</name>
              <description>CCM SRAM page 5 write protection</description>
              <bitRange>[5:5]</bitRange>
            </field>
            <field>
              <name>P6WP</name>
              <description>CCM SRAM page 6 write protection</description>
              <bitRange>[6:6]</bitRange>
            </field>
            <field>
              <name>P7WP</name>
              <description>CCM SRAM page 7 write protection</description>
              <bitRange>[7:7]</bitRange>
            </field>
            <field>
              <name>P8WP</name>
              <description>CCM SRAM page 8 write protection</description>
              <bitRange>[8:8]</bitRange>
            </field>
            <field>
              <name>P9WP</name>
              <description>CCM SRAM page 9 write protection</description>
              <bitRange>[9:9]</bitRange>
            </field>
            <field>
              <name>P10WP</name>
              <description>CCM SRAM page 10 write protection</description>
              <bitRange>[10:10]</bitRange>
            </field>
            <field>
              <name>P11WP</name>
              <description>CCM SRAM page 11 write protection</description>
              <bitRange>[11:11]</bitRange>
            </field>
            <field>
              <name>P12WP</name>
              <description>CCM SRAM page 12 write protection</description>
              <bitRange>[12:12]</bitRange>
            </field>
            <field>
              <name>P13WP</name>
              <description>CCM SRAM page 13 write protection</description>
              <bitRange>[13:13]</bitRange>
            </field>
            <field>
              <name>P14WP</name>
              <description>CCM SRAM page 14 write protection</description>
              <bitRange>[14:14]</bitRange>
            </field>
            <field>
              <name>P15WP</name>
              <description>CCM SRAM page 15 write protection</description>
              <bitRange>[15:15]</bitRange>
            </field>
            <field>
              <name>P16WP</name>
              <description>CCM SRAM page 16 write protection</description>
              <bitRange>[16:16]</bitRange>
            </field>
            <field>
              <name>P17WP</name>
              <description>CCM SRAM page 17 write protection</description>
              <bitRange>[17:17]</bitRange>
            </field>
            <field>
              <name>P18WP</name>
              <description>CCM SRAM page 18 write protection</description>
              <bitRange>[18:18]</bitRange>
            </field>
            <field>
              <name>P19WP</name>
              <description>CCM SRAM page 19 write protection</description>
              <bitRange>[19:19]</bitRange>
            </field>
            <field>
              <name>P20WP</name>
              <description>CCM SRAM page 20 write protection</description>
              <bitRange>[20:20]</bitRange>
            </field>
            <field>
              <name>P21WP</name>
              <description>CCM SRAM page 21 write protection</description>
              <bitRange>[21:21]</bitRange>
            </field>
            <field>
              <name>P22WP</name>
              <description>CCM SRAM page 22 write protection</description>
              <bitRange>[22:22]</bitRange>
            </field>
            <field>
              <name>P23WP</name>
              <description>CCM SRAM page 23 write protection</description>
              <bitRange>[23:23]</bitRange>
            </field>
            <field>
              <name>P24WP</name>
              <description>CCM SRAM page 24 write protection</description>
              <bitRange>[24:24]</bitRange>
            </field>
            <field>
              <name>P25WP</name>
              <description>CCM SRAM page 25 write protection</description>
              <bitRange>[25:25]</bitRange>
            </field>
            <field>
              <name>P26WP</name>
              <description>CCM SRAM page 26 write protection</description>
              <bitRange>[26:26]</bitRange>
            </field>
            <field>
              <name>P27WP</name>
              <description>CCM SRAM page 27 write protection</description>
              <bitRange>[27:27]</bitRange>
            </field>
            <field>
              <name>P28WP</name>
              <description>CCM SRAM page 28 write protection</description>
              <bitRange>[28:28]</bitRange>
            </field>
            <field>
              <name>P29WP</name>
              <description>CCM SRAM page 29 write protection</description>
              <bitRange>[29:29]</bitRange>
            </field>
            <field>
              <name>P30WP</name>
              <description>CCM SRAM page 30 write protection</description>
              <bitRange>[30:30]</bitRange>
            </field>
            <field>
              <name>P31WP</name>
              <description>CCM SRAM page 31 write protection</description>
              <bitRange>[31:31]</bitRange>
            </field>
          </fields>
        </register>
        <register>
          <name>SKR</name>
          <addressOffset>0x78</addressOffset>
          <fields>
            <field>
              <name>KEY</name>
              <description>protective key of SYSCFG_SCSR</description>
              <bitRange>[7:0]</bitRange>
            </field>
          </fields>
        </register>
      </registers>
    </peripheral>
    <peripheral>
      <name>TIM1</name>
      <groupName>TIM</groupName>
      <baseAddress>0x40012C00</baseAddress>
      <addressBlock>
        <offset>0x0</offset>
        <size>0x400</size>
        <usage>registers</usage>
      </addressBlock>
      <interrupt>
        <name>TIM1_BRK_TIM9</name>
        <description>TIM1 Break Interrupt and TIM9 global Interrupt</description>
        <value>24</value>
      </interrupt>
      <interrupt>
        <name>TIM1_UP_TIM10</name>
        <description>TIM1 Update Interrupt and TIM10 global Interrupt</description>
        <value>25</value>
      </interrupt>
      <interrupt>
        <name>TIM1_TRG_COM_TIM11</name>
        <description>TIM1 Trigger and Commutation Interrupt and TIM11 global interrupt</description>
        <value>26</value>
      </interrupt>
      <interrupt>
        <name>TIM1_CC</name>
        <description>TIM1 Capture Compare Interrupt</description>
        <value>27</value>
      </interrupt>
      <registers>
        <register>
          <name>CR1</name>
          <addressOffset>0x0</addressOffset>
          <size>16</size>
          <fields>
            <field>
              <name>CEN</name>
              <bitRange>[0:0]</bitRange>
            </field>
            <field>
              <name>UDIS</name>
              <bitRange>[1:1]</bitRange>
            </field>
            <field>
              <name>URS</name>
              <bitRange>[2:2]</bitRange>
            </field>
            <field>
              <name>OPM</name>
              <bitRange>[3:3]</bitRange>
            </field>
            <field>
              <name>DIR</name>
              <bitRange>[4:4]</bitRange>
            </field>
            <field>
              <name>CMS</name>
              <bitRange>[6:5]</bitRange>
            </field>
            <field>
              <name>ARPE</name>
              <bitRange>[7:7]</bitRange>
            </field>
            <field>
              <name>CKD</name>
              <bitRange>[9:8]</bitRange>
            </field>
            <field>
              <name>UIFREMAP</name>
              <bitRange>[11:11]</bitRange>
            </field>
            <field>
              <name>DITHEN</name>
              <bitRange>[12:12]</bitRange>
            </field>
          </fields>
        </register>
        <register>
          <name>CR2</name>
          <addressOffset>0x4</addressOffset>
          <fields>
            <field>
              <name>CCPC</name>
              <bitRange>[0:0]</bitRange>
            </field>
            <field>
              <name>CCUS</name>
              <bitRange>[2:2]</bitRange>
            </field>
            <field>
              <name>CCDS</name>
              <bitRange>[3:3]</bitRange>
            </field>
            <field>
              <name>MMS_L</name>
              <bitRange>[6:4]</bitRange>
            </field>
            <field>
              <name>TI1S</name>
              <bitRange>[7:7]</bitRange>
            </field>
            <field>
              <name>OIS1</name>
              <bitRange>[8:8]</bitRange>
            </field>
            <field>
              <name>OIS1N</name>
              <bitRange>[9:9]</bitRange>
            </field>
            <field>
              <name>OIS2</name>
              <bitRange>[10:10]</bitRange>
            </field>
            <field>
              <name>OIS2N</name>
              <bitRange>[11:11]</bitRange>
            </field>
            <field>
              <name>OIS3</name>
              <bitRange>[12:12]</bitRange>
            </field>
            <field>
              <name>OIS3N</name>
              <bitRange>[13:13]</bitRange>
            </field>
            <field>
              <name>OIS4</name>
              <bitRange>[14:14]</bitRange>
            </field>
            <field>
              <name>OIS4N</name>
              <bitRange>[15:15]</bitRange>
            </field>
            <field>
              <name>OIS5</name>
              <bitRange>[16:16]</bitRange>
            </field>
            <field>
              <name>OIS6</name>
              <bitRange>[18:18]</bitRange>
            </field>
            <field>
              <name>MMS2</name>
              <bitRange>[23:20]</bitRange>
            </field>
            <field>
              <name>MMS_H</name>
              <bitRange>[25:25]</bitRange>
            </field>
          </fields>
        </register>
        <register>
          <name>SMCR</name>
          <addressOffset>0x8</addressOffset>
          <fields>
            <field>
              <name>SMS_L</name>
              <bitRange>[2:0]</bitRange>
            </field>
            <field>
              <name>OCCS</name>
              <bitRange>[3:3]</bitRange>
            </field>
            <field>
              <name>TS_L</name>
              <bitRange>[6:4]</bitRange>
            </field>
            <field>
              <name>MSM</name>
              <bitRange>[7:7]</bitRange>
            </field>
            <field>
              <name>ETF</name>
              <bitRange>[11:8]</bitRange>
            </field>
            <field>
              <name>ETPS</name>
              <bitRange>[13:12]</bitRange>
            </field>
            <field>
              <name>ECE</name>
              <bitRange>[14:14]</bitRange>
            </field>
            <field>
              <name>ETP</name>
              <bitRange>[15:15]</bitRange>
            </field>
            <field>
              <name>SMS_H</name>
              <bitRange>[16:16]</bitRange>
            </field>
            <field>
              <name>TS_H</name>
              <bitRange>[21:20]</bitRange>
            </field>
            <field>
              <name>SMSPE</name>
              <bitRange>[24:24]</bitRange>
            </field>
            <field>
              <name>SMSPS</name>
              <bitRange>[25:25]</bitRange>
            </field>
          </fields>
        </register>
        <register>
          <name>DIER</name>
          <addressOffset>0xC</addressOffset>
          <fields>
            <field>
              <name>UIE</name>
              <bitRange>[0:0]</bitRange>
            </field>
            <field>
              <name>CC1IE</name>
              <bitRange>[1:1]</bitRange>
            </field>
            <field>
              <name>CC2IE</name>
              <bitRange>[2:2]</bitRange>
            </field>
            <field>
              <name>CC3IE</name>
              <bitRange>[3:3]</bitRange>
            </field>
            <field>
              <name>CC4IE</name>
              <bitRange>[4:4]</bitRange>
            </field>
            <field>
              <name>COMIE</name>
              <bitRange>[5:5]</bitRange>
            </field>
            <field>
              <name>TIE</name>
              <bitRange>[6:6]</bitRange>
            </field>
            <field>
              <name>BIE</name>
              <bitRange>[7:7]</bitRange>
            </field>
            <field>
              <name>UDE</name>
              <bitRange>[8:8]</bitRange>
            </field>
            <field>
              <name>CC1DE</name>
              <bitRange>[9:9]</bitRange>
            </field>
            <field>
              <name>CC2DE</name>
              <bitRange>[10:10]</bitRange>
            </field>
            <field>
              <name>CC3DE</name>
              <bitRange>[11:11]</bitRange>
            </field>
            <field>
              <name>CC4DE</name>
              <bitRange>[12:12]</bitRange>
            </field>
            <field>
              <name>COMDE</name>
              <bitRange>[13:13]</bitRange>
            </field>
            <field>
              <name>TDE</name>
              <bitRange>[14:14]</bitRange>
            </field>
            <field>
              <name>IDXIE</name>
              <bitRange>[20:20]</bitRange>
            </field>
            <field>
              <name>DIRIE</name>
              <bitRange>[21:21]</bitRange>
            </field>
            <field>
              <name>IERRIE</name>
              <bitRange>[22:22]</bitRange>
            </field>
            <field>
              <name>TERRIE</name>
              <bitRange>[23:23]</bitRange>
            </field>
          </fields>
        </register>
        <register>
          <name>SR</name>
          <addressOffset>0x10</addressOffset>
          <fields>
            <field>
              <name>UIF</name>
              <bitRange>[0:0]</bitRange>
            </field>
            <field>
              <name>CC1IF</name>
              <bitRange>[1:1]</bitRange>
            </field>
            <field>
              <name>CC2IF</name>
              <bitRange>[2:2]</bitRange>
            </field>
            <field>
              <name>CC3IF</name>
              <bitRange>[3:3]</bitRange>
            </field>
            <field>
              <name>CC4IF</name>
              <bitRange>[4:4]</bitRange>
            </field>
            <field>
              <name>COMIF</name>
              <bitRange>[5:5]</bitRange>
            </field>
            <field>
              <name>TIF</name>
              <bitRange>[6:6]</bitRange>
            </field>
            <field>
              <name>BIF</name>
              <bitRange>[7:7]</bitRange>
            </field>
            <field>
              <name>B2IF</name>
              <bitRange>[8:8]</bitRange>
            </field>
            <field>
              <name>CC1OF</name>
              <bitRange>[9:9]</bitRange>
            </field>
            <field>
              <name>CC2OF</name>
              <bitRange>[10:10]</bitRange>
            </field>
            <field>
              <name>CC3OF</name>
              <bitRange>[11:11]</bitRange>
            </field>
            <field>
              <name>CC4OF</name>
              <bitRange>[12:12]</bitRange>
            </field>
            <field>
              <name>SBIF</name>
              <bitRange>[13:13]</bitRange>
            </field>
            <field>
              <name>CC5IF</name>
              <bitRange>[16:16]</bitRange>
            </field>
            <field>
              <name>CC6IF</name>
              <bitRange>[17:17]</bitRange>
            </field>
            <field>
              <name>IC1IR</name>
              <bitRange>[18:18]</bitRange>
            </field>
            <field>
              <name>IC2IR</name>
              <bitRange>[19:19]</bitRange>
            </field>
            <field>
              <name>IDXF</name>
              <bitRange>[20:20]</bitRange>
            </field>
            <field>
              <name>DIRF</name>
              <bitRange>[21:21]</bitRange>
            </field>
            <field>
              <name>IERRF</name>
              <bitRange>[22:22]</bitRange>
            </field>
            <field>
              <name>TERRF</name>
              <bitRange>[23:23]</bitRange>
            </field>
            <field>
              <name>IC3IR</name>
              <bitRange>[24:24]</bitRange>
            </field>
            <field>
              <name>IC4IR</name>
              <bitRange>[25:25]</bitRange>
            </field>
            <field>
              <name>IC1IF</name>
              <bitRange>[26:26]</bitRange>
            </field>
            <field>
              <name>IC2IF</name>
              <bitRange>[27:27]</bitRange>
            </field>
            <field>
              <name>IC3IF</name>
              <bitRange>[28:28]</bitRange>
            </field>
            <field>
              <name>IC4IF</name>
              <bitRange>[29:29]</bitRange>
            </field>
          </fields>
        </register>
        <register>
          <name>EGR</name>
          <addressOffset>0x14</addressOffset>
          <size>16</size>
          <fields>
            <field>
              <name>UG</name>
              <bitRange>[0:0]</bitRange>
              <access>read-only</access>
            </field>
            <field>
              <name>CC1G</name>
              <bitRange>[1:1]</bitRange>
              <access>read-only</access>
            </field>
            <field>
              <name>CC2G</name>
              <bitRange>[2:2]</bitRange>
              <access>read-only</access>
            </field>
            <field>
              <name>CC3G</name>
              <bitRange>[3:3]</bitRange>
              <access>read-only</access>
            </field>
            <field>
              <name>CC4G</name>
              <bitRange>[4:4]</bitRange>
              <access>read-only</access>
            </field>
            <field>
              <name>COMG</name>
              <bitRange>[5:5]</bitRange>
              <access>read-only</access>
            </field>
            <field>
              <name>TG</name>
              <bitRange>[6:6]</bitRange>
              <access>read-only</access>
            </field>
            <field>
              <name>BG</name>
              <bitRange>[7:7]</bitRange>
              <access>read-only</access>
            </field>
            <field>
              <name>B2G</name>
              <bitRange>[8:8]</bitRange>
              <access>read-only</access>
            </field>
          </fields>
        </register>
        <register>
          <name>CCMR1_OUTPUT</name>
          <addressOffset>0x18</addressOffset>
          <fields>
            <field>
              <name>CC1S</name>
              <bitRange>[1:0]</bitRange>
            </field>
            <field>
              <name>OC1FE</name>
              <bitRange>[2:2]</bitRange>
            </field>
            <field>
              <name>OC1PE</name>
              <bitRange>[3:3]</bitRange>
            </field>
            <field>
              <name>OC1M_L</name>
              <bitRange>[6:4]</bitRange>
            </field>
            <field>
              <name>OC1CE</name>
              <bitRange>[7:7]</bitRange>
            </field>
            <field>
              <name>CC2S</name>
              <bitRange>[9:8]</bitRange>
            </field>
            <field>
              <name>OC2FE</name>
              <bitRange>[10:10]</bitRange>
            </field>
            <field>
              <name>OC2PE</name>
              <bitRange>[11:11]</bitRange>
            </field>
            <field>
              <name>OC2M_L</name>
              <bitRange>[14:12]</bitRange>
            </field>
            <field>
              <name>OC2CE</name>
              <bitRange>[15:15]</bitRange>
            </field>
            <field>
              <name>OC1M_H</name>
              <bitRange>[16:16]</bitRange>
            </field>
            <field>
              <name>OC2M_H</name>
              <bitRange>[24:24]</bitRange>
            </field>
          </fields>
        </register>
        <register>
          <name>CCMR1_INPUT</name>
          <alternateRegister>CCMR1_OUTPUT</alternateRegister>
          <addressOffset>0x18</addressOffset>
          <size>16</size>
          <fields>
            <field>
              <name>CC1S</name>
              <bitRange>[1:0]</bitRange>
            </field>
            <field>
              <name>IC1PSC</name>
              <bitRange>[3:2]</bitRange>
            </field>
            <field>
              <name>IC1F</name>
              <bitRange>[7:4]</bitRange>
            </field>
            <field>
              <name>CC2S</name>
              <bitRange>[9:8]</bitRange>
            </field>
            <field>
              <name>IC2PSC</name>
              <bitRange>[11:10]</bitRange>
            </field>
            <field>
              <name>IC2F</name>
              <bitRange>[15:12]</bitRange>
            </field>
          </fields>
        </register>
        <register>
          <name>CCMR2_OUTPUT</name>
          <addressOffset>0x1C</addressOffset>
          <fields>
            <field>
              <name>CC3S</name>
              <bitRange>[1:0]</bitRange>
            </field>
            <field>
              <name>OC3FE</name>
              <bitRange>[2:2]</bitRange>
            </field>
            <field>
              <name>OC3PE</name>
              <bitRange>[3:3]</bitRange>
            </field>
            <field>
              <name>OC3M_L</name>
              <bitRange>[6:4]</bitRange>
            </field>
            <field>
              <name>OC3CE</name>
              <bitRange>[7:7]</bitRange>
            </field>
            <field>
              <name>CC4S</name>
              <bitRange>[9:8]</bitRange>
            </field>
            <field>
              <name>OC4FE</name>
              <bitRange>[10:10]</bitRange>
            </field>
            <field>
              <name>OC4PE</name>
              <bitRange>[11:11]</bitRange>
            </field>
            <field>
              <name>OC4M_L</name>
              <bitRange>[14:12]</bitRange>
            </field>
            <field>
              <name>OC4CE</name>
              <bitRange>[15:15]</bitRange>
            </field>
            <field>
              <name>OC3M_H</name>
              <bitRange>[16:16]</bitRange>
            </field>
            <field>
              <name>OC4M_H</name>
              <bitRange>[24:24]</bitRange>
            </field>
          </fields>
        </register>
        <register>
          <name>CCMR2_INPUT</name>
          <alternateRegister>CCMR2_OUTPUT</alternateRegister>
          <addressOffset>0x1C</addressOffset>
          <size>16</size>
          <fields>
            <field>
              <name>CC3S</name>
              <bitRange>[1:0]</bitRange>
            </field>
            <field>
              <name>IC3PSC</name>
              <bitRange>[3:2]</bitRange>
            </field>
            <field>
              <name>IC3F</name>
              <bitRange>[7:4]</bitRange>
            </field>
            <field>
              <name>CC4S</name>
              <bitRange>[9:8]</bitRange>
            </field>
            <field>
              <name>IC4PSC</name>
              <bitRange>[11:10]</bitRange>
            </field>
            <field>
              <name>IC4F</name>
              <bitRange>[15:12]</bitRange>
            </field>
          </fields>
        </register>
        <register>
          <name>CCER</name>
          <addressOffset>0x20</addressOffset>
          <fields>
            <field>
              <name>CC1E</name>
              <bitRange>[0:0]</bitRange>
            </field>
            <field>
              <name>CC1P</name>
              <bitRange>[1:1]</bitRange>
            </field>
            <field>
              <name>CC1NE</name>
              <bitRange>[2:2]</bitRange>
            </field>
            <field>
              <name>CC1NP</name>
              <bitRange>[3:3]</bitRange>
            </field>
            <field>
              <name>CC2E</name>
              <bitRange>[4:4]</bitRange>
            </field>
            <field>
              <name>CC2P</name>
              <bitRange>[5:5]</bitRange>
            </field>
            <field>
              <name>CC2NE</name>
              <bitRange>[6:6]</bitRange>
            </field>
            <field>
              <name>CC2NP</name>
              <bitRange>[7:7]</bitRange>
            </field>
            <field>
              <name>CC3E</name>
              <bitRange>[8:8]</bitRange>
            </field>
            <field>
              <name>CC3P</name>
              <bitRange>[9:9]</bitRange>
            </field>
            <field>
              <name>CC3NE</name>
              <bitRange>[10:10]</bitRange>
            </field>
            <field>
              <name>CC3NP</name>
              <bitRange>[11:11]</bitRange>
            </field>
            <field>
              <name>CC4E</name>
              <bitRange>[12:12]</bitRange>
            </field>
            <field>
              <name>CC4P</name>
              <bitRange>[13:13]</bitRange>
            </field>
            <field>
              <name>CC4NE</name>
              <bitRange>[14:14]</bitRange>
            </field>
            <field>
              <name>CC4NP</name>
              <bitRange>[15:15]</bitRange>
            </field>
            <field>
              <name>CC5E</name>
              <bitRange>[16:16]</bitRange>
            </field>
            <field>
              <name>CC5P</name>
              <bitRange>[17:17]</bitRange>
            </field>
            <field>
              <name>CC6E</name>
              <bitRange>[20:20]</bitRange>
            </field>
            <field>
              <name>CC6P</name>
              <bitRange>[21:21]</bitRange>
            </field>
          </fields>
        </register>
        <register>
          <name>CNT</name>
          <addressOffset>0x24</addressOffset>
          <fields>
            <field>
              <name>CNT</name>
              <bitRange>[15:0]</bitRange>
            </field>
            <field>
              <name>UIFCPY</name>
              <bitRange>[31:31]</bitRange>
              <access>read-only</access>
            </field>
          </fields>
        </register>
        <register>
          <name>PSC</name>
          <addressOffset>0x28</addressOffset>
          <size>16</size>
          <fields>
            <field>
              <name>PSC</name>
              <bitRange>[15:0]</bitRange>
            </field>
          </fields>
        </register>
        <register>
          <name>ARR</name>
          <addressOffset>0x2C</addressOffset>
          <fields>
            <field>
              <name>ARR</name>
              <bitRange>[19:0]</bitRange>
            </field>
          </fields>
        </register>
        <register>
          <name>RCR</name>
          <addressOffset>0x30</addressOffset>
          <size>16</size>
          <fields>
            <field>
              <name>REP</name>
              <bitRange>[15:0]</bitRange>
            </field>
          </fields>
        </register>
        <register>
          <name>CCR1</name>
          <addressOffset>0x34</addressOffset>
          <fields>
            <field>
              <name>CCR1</name>
              <bitRange>[19:0]</bitRange>
            </field>
          </fields>
        </register>
        <register>
          <name>CCR2</name>
          <addressOffset>0x38</addressOffset>
          <fields>
            <field>
              <name>CCR2</name>
              <bitRange>[19:0]</bitRange>
            </field>
          </fields>
        </register>
        <register>
          <name>CCR3</name>
          <addressOffset>0x3C</addressOffset>
          <fields>
            <field>
              <name>CCR3</name>
              <bitRange>[19:0]</bitRange>
            </field>
          </fields>
        </register>
        <register>
          <name>CCR4</name>
          <addressOffset>0x40</addressOffset>
          <fields>
            <field>
              <name>CCR4</name>
              <bitRange>[19:0]</bitRange>
            </field>
          </fields>
        </register>
        <register>
          <name>BDTR</name>
          <addressOffset>0x44</addressOffset>
          <fields>
            <field>
              <name>DTG</name>
              <bitRange>[7:0]</bitRange>
            </field>
            <field>
              <name>LOCK</name>
              <bitRange>[9:8]</bitRange>
            </field>
            <field>
              <name>OSSI</name>
              <bitRange>[10:10]</bitRange>
            </field>
            <field>
              <name>OSSR</name>
              <bitRange>[11:11]</bitRange>
            </field>
            <field>
              <name>BKE</name>
              <bitRange>[12:12]</bitRange>
            </field>
            <field>
              <name>BKP</name>
              <bitRange>[13:13]</bitRange>
            </field>
            <field>
              <name>AOE</name>
              <bitRange>[14:14]</bitRange>
            </field>
            <field>
              <name>MOE</name>
              <bitRange>[15:15]</bitRange>
            </field>
            <field>
              <name>BKF</name>
              <bitRange>[19:16]</bitRange>
            </field>
            <field>
              <name>BK2F</name>
              <bitRange>[23:20]</bitRange>
            </field>
            <field>
              <name>BK2E</name>
              <bitRange>[24:24]</bitRange>
            </field>
            <field>
              <name>BK2P</name>
              <bitRange>[25:25]</bitRange>
            </field>
            <field>
              <name>BKDSRM</name>
              <bitRange>[26:26]</bitRange>
            </field>
            <field>
              <name>BK2DSRM</name>
              <bitRange>[27:27]</bitRange>
            </field>
            <field>
              <name>BKBID</name>
              <bitRange>[28:28]</bitRange>
            </field>
            <field>
              <name>BK2BID</name>
              <bitRange>[29:29]</bitRange>
            </field>
          </fields>
        </register>
        <register>
          <name>CCR5</name>
          <addressOffset>0x48</addressOffset>
          <fields>
            <field>
              <name>CCR5</name>
              <bitRange>[19:0]</bitRange>
            </field>
            <field>
              <name>GC5C1</name>
              <bitRange>[29:29]</bitRange>
            </field>
            <field>
              <name>GC5C2</name>
              <bitRange>[30:30]</bitRange>
            </field>
            <field>
              <name>GC5C3</name>
              <bitRange>[31:31]</bitRange>
            </field>
          </fields>
        </register>
        <register>
          <name>CCR6</name>
          <addressOffset>0x4C</addressOffset>
          <fields>
            <field>
              <name>CCR6</name>
              <bitRange>[19:0]</bitRange>
            </field>
          </fields>
        </register>
        <register>
          <name>CCMR3</name>
          <addressOffset>0x50</addressOffset>
          <fields>
            <field>
              <name>OC5FE</name>
              <bitRange>[2:2]</bitRange>
            </field>
            <field>
              <name>OC5PE</name>
              <bitRange>[3:3]</bitRange>
            </field>
            <field>
              <name>OC5M_L</name>
              <bitRange>[6:4]</bitRange>
            </field>
            <field>
              <name>OC5CE</name>
              <bitRange>[7:7]</bitRange>
            </field>
            <field>
              <name>OC6FE</name>
              <bitRange>[10:10]</bitRange>
            </field>
            <field>
              <name>OC6PE</name>
              <bitRange>[11:11]</bitRange>
            </field>
            <field>
              <name>OC6M_L</name>
              <bitRange>[14:12]</bitRange>
            </field>
            <field>
              <name>OC6CE</name>
              <bitRange>[15:15]</bitRange>
            </field>
            <field>
              <name>OC5M_H</name>
              <bitRange>[16:16]</bitRange>
            </field>
            <field>
              <name>OC6M_H</name>
              <bitRange>[24:24]</bitRange>
            </field>
          </fields>
        </register>
        <register>
          <name>DTR2</name>
          <addressOffset>0x54</addressOffset>
          <fields>
            <field>
              <name>DTGF</name>
              <bitRange>[7:0]</bitRange>
            </field>
            <field>
              <name>DTAE</name>
              <bitRange>[16:16]</bitRange>
            </field>
            <field>
              <name>DTPE</name>
              <bitRange>[17:17]</bitRange>
            </field>
          </fields>
        </register>
        <register>
          <name>ECR</name>
          <addressOffset>0x58</addressOffset>
          <fields>
            <field>
              <name>IE</name>
              <bitRange>[0:0]</bitRange>
            </field>
            <field>
              <name>IDIR</name>
              <bitRange>[1:1]</bitRange>
            </field>
            <field>
              <name>FIDX</name>
              <bitRange>[5:5]</bitRange>
            </field>
            <field>
              <name>IPOS</name>
              <bitRange>[7:6]</bitRange>
            </field>
            <field>
              <name>PW</name>
              <bitRange>[23:16]</bitRange>
            </field>
            <field>
              <name>PWPRSC</name>
              <bitRange>[26:24]</bitRange>
            </field>
          </fields>
        </register>
        <register>
          <name>TISEL</name>
          <addressOffset>0x5C</addressOffset>
          <fields>
            <field>
              <name>TI1SEL</name>
              <bitRange>[3:0]</bitRange>
            </field>
            <field>
              <name>TI2SEL</name>
              <bitRange>[11:8]</bitRange>
            </field>
            <field>
              <name>TI3SEL</name>
              <bitRange>[19:16]</bitRange>
            </field>
            <field>
              <name>TI4SEL</name>
              <bitRange>[27:24]</bitRange>
            </field>
          </fields>
        </register>
        <register>
          <name>AF1</name>
          <addressOffset>0x60</addressOffset>
          <fields>
            <field>
              <name>BKINE</name>
              <bitRange>[0:0]</bitRange>
            </field>
            <field>
              <name>BKCMP1E</name>
              <bitRange>[1:1]</bitRange>
            </field>
            <field>
              <name>BKCMP2E</name>
              <bitRange>[2:2]</bitRange>
            </field>
            <field>
              <name>BKCMP3E</name>
              <bitRange>[3:3]</bitRange>
            </field>
            <field>
              <name>BKCMP4E</name>
              <bitRange>[4:4]</bitRange>
            </field>
            <field>
              <name>BKCMP5E</name>
              <bitRange>[5:5]</bitRange>
            </field>
            <field>
              <name>BKCMP6E</name>
              <bitRange>[6:6]</bitRange>
            </field>
            <field>
              <name>BKCMP7E</name>
              <bitRange>[7:7]</bitRange>
            </field>
            <field>
              <name>BKCMP8E</name>
              <bitRange>[8:8]</bitRange>
            </field>
            <field>
              <name>BKINP</name>
              <bitRange>[9:9]</bitRange>
            </field>
            <field>
              <name>BKCMP1P</name>
              <bitRange>[10:10]</bitRange>
            </field>
            <field>
              <name>BKCMP2P</name>
              <bitRange>[11:11]</bitRange>
            </field>
            <field>
              <name>BKCMP3P</name>
              <bitRange>[12:12]</bitRange>
            </field>
            <field>
              <name>BKCMP4P</name>
              <bitRange>[13:13]</bitRange>
            </field>
            <field>
              <name>ETRSEL</name>
              <bitRange>[17:14]</bitRange>
            </field>
          </fields>
        </register>
        <register>
          <name>AF2</name>
          <addressOffset>0x64</addressOffset>
          <fields>
            <field>
              <name>BK2INE</name>
              <bitRange>[0:0]</bitRange>
            </field>
            <field>
              <name>BK2CMP1E</name>
              <bitRange>[1:1]</bitRange>
            </field>
            <field>
              <name>BK2CMP2E</name>
              <bitRange>[2:2]</bitRange>
            </field>
            <field>
              <name>BK2CMP3E</name>
              <bitRange>[3:3]</bitRange>
            </field>
            <field>
              <name>BK2CMP4E</name>
              <bitRange>[4:4]</bitRange>
            </field>
            <field>
              <name>BK2CMP5E</name>
              <bitRange>[5:5]</bitRange>
            </field>
            <field>
              <name>BK2CMP6E</name>
              <bitRange>[6:6]</bitRange>
            </field>
            <field>
              <name>BK2CMP7E</name>
              <bitRange>[7:7]</bitRange>
            </field>
            <field>
              <name>BK2CMP8E</name>
              <bitRange>[8:8]</bitRange>
            </field>
            <field>
              <name>BK2INP</name>
              <bitRange>[9:9]</bitRange>
            </field>
            <field>
              <name>BK2CMP1P</name>
              <bitRange>[10:10]</bitRange>
            </field>
            <field>
              <name>BK2CMP2P</name>
              <bitRange>[11:11]</bitRange>
            </field>
            <field>
              <name>BK2CMP3P</name>
              <bitRange>[12:12]</bitRange>
            </field>
            <field>
              <name>BK2CMP4P</name>
              <bitRange>[13:13]</bitRange>
            </field>
            <field>
              <name>OCRSEL</name>
              <bitRange>[18:16]</bitRange>
            </field>
          </fields>
        </register>
        <register>
          <name>TIMXDCR</name>
          <addressOffset>0x3DC</addressOffset>
          <size>16</size>
          <fields>
            <field>
              <name>DBA</name>
              <bitRange>[4:0]</bitRange>
            </field>
            <field>
              <name>DBL</name>
              <bitRange>[12:8]</bitRange>
            </field>
          </fields>
        </register>
        <register>
          <name>DMAR</name>
          <addressOffset>0x3E0</addressOffset>
          <fields>
            <field>
              <name>DMAB</name>
              <bitRange>[31:0]</bitRange>
            </field>
          </fields>
        </register>
      </registers>
    </peripheral>
    <peripheral>
      <name>TIM2</name>
      <description>desc TIM</description>
      <groupName>TIM</groupName>
      <baseAddress>0x40000000</baseAddress>
      <addressBlock>
        <offset>0x0</offset>
        <size>0x400</size>
        <usage>registers</usage>
      </addressBlock>
      <interrupt>
        <name>TIM2</name>
        <description>TIM2 global Interrupt</description>
        <value>28</value>
      </interrupt>
      <registers>
        <register>
          <name>CR1</name>
          <description>desc CR1</description>
          <addressOffset>0x0</addressOffset>
          <size>16</size>
          <fields>
            <field>
              <name>CEN</name>
              <bitRange>[0:0]</bitRange>
            </field>
            <field>
              <name>UDIS</name>
              <bitRange>[1:1]</bitRange>
            </field>
            <field>
              <name>URS</name>
              <bitRange>[2:2]</bitRange>
            </field>
            <field>
              <name>OPM</name>
              <bitRange>[3:3]</bitRange>
            </field>
            <field>
              <name>DIR</name>
              <bitRange>[4:4]</bitRange>
            </field>
            <field>
              <name>CMS</name>
              <bitRange>[6:5]</bitRange>
            </field>
            <field>
              <name>ARPE</name>
              <bitRange>[7:7]</bitRange>
            </field>
            <field>
              <name>CKD</name>
              <bitRange>[9:8]</bitRange>
            </field>
            <field>
              <name>UIFREMAP</name>
              <bitRange>[11:11]</bitRange>
            </field>
            <field>
              <name>DITHEN</name>
              <bitRange>[12:12]</bitRange>
            </field>
          </fields>
        </register>
        <register>
          <name>CR2</name>
          <description>desc CR2</description>
          <addressOffset>0x4</addressOffset>
          <fields>
            <field>
              <name>CCDS</name>
              <bitRange>[3:3]</bitRange>
            </field>
            <field>
              <name>MMS_L</name>
              <bitRange>[6:4]</bitRange>
              <access>read-only</access>
            </field>
            <field>
              <name>TI1S</name>
              <bitRange>[7:7]</bitRange>
            </field>
            <field>
              <name>MMS_H</name>
              <bitRange>[25:25]</bitRange>
            </field>
          </fields>
        </register>
        <register>
          <name>SMCR</name>
          <description>desc SMCR</description>
          <addressOffset>0x8</addressOffset>
          <fields>
            <field>
              <name>SMS_L</name>
              <bitRange>[2:0]</bitRange>
            </field>
            <field>
              <name>OCCS</name>
              <bitRange>[3:3]</bitRange>
            </field>
            <field>
              <name>TS_L</name>
              <bitRange>[6:4]</bitRange>
            </field>
            <field>
              <name>MSM</name>
              <bitRange>[7:7]</bitRange>
            </field>
            <field>
              <name>ETF</name>
              <bitRange>[11:8]</bitRange>
            </field>
            <field>
              <name>ETPS</name>
              <bitRange>[13:12]</bitRange>
            </field>
            <field>
              <name>ECE</name>
              <bitRange>[14:14]</bitRange>
            </field>
            <field>
              <name>ETP</name>
              <bitRange>[15:15]</bitRange>
            </field>
            <field>
              <name>SMS_H</name>
              <bitRange>[16:16]</bitRange>
            </field>
            <field>
              <name>TS_H</name>
              <bitRange>[21:20]</bitRange>
            </field>
            <field>
              <name>SMSPE</name>
              <bitRange>[24:24]</bitRange>
            </field>
            <field>
              <name>SMSPS</name>
              <bitRange>[25:25]</bitRange>
            </field>
          </fields>
        </register>
        <register>
          <name>DIER</name>
          <description>desc DIER</description>
          <addressOffset>0xC</addressOffset>
          <fields>
            <field>
              <name>UIE</name>
              <bitRange>[0:0]</bitRange>
            </field>
            <field>
              <name>CC1IE</name>
              <bitRange>[1:1]</bitRange>
            </field>
            <field>
              <name>CC2IE</name>
              <bitRange>[2:2]</bitRange>
            </field>
            <field>
              <name>CC3IE</name>
              <bitRange>[3:3]</bitRange>
            </field>
            <field>
              <name>CC4IE</name>
              <bitRange>[4:4]</bitRange>
            </field>
            <field>
              <name>TIE</name>
              <bitRange>[6:6]</bitRange>
            </field>
            <field>
              <name>UDE</name>
              <bitRange>[8:8]</bitRange>
            </field>
            <field>
              <name>CC1DE</name>
              <bitRange>[9:9]</bitRange>
            </field>
            <field>
              <name>CC2DE</name>
              <bitRange>[10:10]</bitRange>
            </field>
            <field>
              <name>CC3DE</name>
              <bitRange>[11:11]</bitRange>
            </field>
            <field>
              <name>CC4DE</name>
              <bitRange>[12:12]</bitRange>
            </field>
            <field>
              <name>TDE</name>
              <bitRange>[14:14]</bitRange>
            </field>
            <field>
              <name>IDXIE</name>
              <bitRange>[20:20]</bitRange>
            </field>
            <field>
              <name>DIRIE</name>
              <bitRange>[21:21]</bitRange>
            </field>
            <field>
              <name>IERRIE</name>
              <bitRange>[22:22]</bitRange>
            </field>
            <field>
              <name>TERRIE</name>
              <bitRange>[23:23]</bitRange>
            </field>
          </fields>
        </register>
        <register>
          <name>SR</name>
          <description>desc SR</description>
          <addressOffset>0x10</addressOffset>
          <fields>
            <field>
              <name>UIF</name>
              <bitRange>[0:0]</bitRange>
            </field>
            <field>
              <name>CC1IF</name>
              <bitRange>[1:1]</bitRange>
            </field>
            <field>
              <name>CC2IF</name>
              <bitRange>[2:2]</bitRange>
            </field>
            <field>
              <name>CC3IF</name>
              <bitRange>[3:3]</bitRange>
            </field>
            <field>
              <name>CC4IF</name>
              <bitRange>[4:4]</bitRange>
            </field>
            <field>
              <name>TIF</name>
              <bitRange>[6:6]</bitRange>
            </field>
            <field>
              <name>CC1OF</name>
              <bitRange>[9:9]</bitRange>
            </field>
            <field>
              <name>CC2OF</name>
              <bitRange>[10:10]</bitRange>
            </field>
            <field>
              <name>CC3OF</name>
              <bitRange>[11:11]</bitRange>
            </field>
            <field>
              <name>CC4OF</name>
              <bitRange>[12:12]</bitRange>
            </field>
            <field>
              <name>IC1IR</name>
              <bitRange>[18:18]</bitRange>
            </field>
            <field>
              <name>IC2IR</name>
              <bitRange>[19:19]</bitRange>
            </field>
            <field>
              <name>IDXF</name>
              <bitRange>[20:20]</bitRange>
            </field>
            <field>
              <name>DIRF</name>
              <bitRange>[21:21]</bitRange>
            </field>
            <field>
              <name>IERRF</name>
              <bitRange>[22:22]</bitRange>
            </field>
            <field>
              <name>TERRF</name>
              <bitRange>[23:23]</bitRange>
            </field>
            <field>
              <name>IC3IR</name>
              <bitRange>[24:24]</bitRange>
            </field>
            <field>
              <name>IC4IR</name>
              <bitRange>[25:25]</bitRange>
            </field>
            <field>
              <name>IC1IF</name>
              <bitRange>[26:26]</bitRange>
            </field>
            <field>
              <name>IC2IF</name>
              <bitRange>[27:27]</bitRange>
            </field>
            <field>
              <name>IC3IF</name>
              <bitRange>[28:28]</bitRange>
            </field>
            <field>
              <name>IC4IF</name>
              <bitRange>[29:29]</bitRange>
            </field>
          </fields>
        </register>
        <register>
          <name>EGR</name>
          <description>desc EGR</description>
          <addressOffset>0x14</addressOffset>
          <size>16</size>
          <fields>
            <field>
              <name>UG</name>
              <bitRange>[0:0]</bitRange>
              <access>read-only</access>
            </field>
            <field>
              <name>CC1G</name>
              <bitRange>[1:1]</bitRange>
              <access>read-only</access>
            </field>
            <field>
              <name>CC2G</name>
              <bitRange>[2:2]</bitRange>
              <access>read-only</access>
            </field>
            <field>
              <name>CC3G</name>
              <bitRange>[3:3]</bitRange>
              <access>read-only</access>
            </field>
            <field>
              <name>CC4G</name>
              <bitRange>[4:4]</bitRange>
              <access>read-only</access>
            </field>
            <field>
              <name>TG</name>
              <bitRange>[6:6]</bitRange>
              <access>read-only</access>
            </field>
          </fields>
        </register>
        <register>
          <name>CCMR1_OUTPUT</name>
          <description>desc CCMR1:OUTPUT</description>
          <addressOffset>0x18</addressOffset>
          <fields>
            <field>
              <name>CC1S</name>
              <bitRange>[1:0]</bitRange>
            </field>
            <field>
              <name>OC1FE</name>
              <bitRange>[2:2]</bitRange>
            </field>
            <field>
              <name>OC1PE</name>
              <bitRange>[3:3]</bitRange>
            </field>
            <field>
              <name>OC1M_L</name>
              <bitRange>[6:4]</bitRange>
            </field>
            <field>
              <name>OC1CE</name>
              <bitRange>[7:7]</bitRange>
            </field>
            <field>
              <name>CC2S</name>
              <bitRange>[9:8]</bitRange>
            </field>
            <field>
              <name>OC2FE</name>
              <bitRange>[10:10]</bitRange>
            </field>
            <field>
              <name>OC2PE</name>
              <bitRange>[11:11]</bitRange>
            </field>
            <field>
              <name>OC2M_L</name>
              <bitRange>[14:12]</bitRange>
            </field>
            <field>
              <name>OC2CE</name>
              <bitRange>[15:15]</bitRange>
            </field>
            <field>
              <name>OC1M_H</name>
              <bitRange>[16:16]</bitRange>
            </field>
            <field>
              <name>OC2M_H</name>
              <bitRange>[24:24]</bitRange>
            </field>
          </fields>
        </register>
        <register>
          <name>CCMR1_INPUT</name>
          <description>desc CCMR1:INPUT</description>
          <alternateRegister>CCMR1_OUTPUT</alternateRegister>
          <addressOffset>0x18</addressOffset>
          <fields>
            <field>
              <name>CC1S</name>
              <bitRange>[1:0]</bitRange>
            </field>
            <field>
              <name>IC1PSC</name>
              <bitRange>[3:2]</bitRange>
            </field>
            <field>
              <name>IC1F</name>
              <bitRange>[7:4]</bitRange>
            </field>
            <field>
              <name>CC2S</name>
              <bitRange>[9:8]</bitRange>
            </field>
            <field>
              <name>IC2PSC</name>
              <bitRange>[11:10]</bitRange>
            </field>
            <field>
              <name>IC2F</name>
              <bitRange>[15:12]</bitRange>
            </field>
          </fields>
        </register>
        <register>
          <name>CCMR2_OUTPUT</name>
          <description>desc CCMR2:OUTPUT</description>
          <addressOffset>0x1C</addressOffset>
          <fields>
            <field>
              <name>CC3S</name>
              <bitRange>[1:0]</bitRange>
            </field>
            <field>
              <name>OC3FE</name>
              <bitRange>[2:2]</bitRange>
            </field>
            <field>
              <name>OC3PE</name>
              <bitRange>[3:3]</bitRange>
            </field>
            <field>
              <name>OC3M_L</name>
              <bitRange>[6:4]</bitRange>
            </field>
            <field>
              <name>OC3CE</name>
              <bitRange>[7:7]</bitRange>
            </field>
            <field>
              <name>CC4S</name>
              <bitRange>[9:8]</bitRange>
            </field>
            <field>
              <name>OC4FE</name>
              <bitRange>[10:10]</bitRange>
            </field>
            <field>
              <name>OC4PE</name>
              <bitRange>[11:11]</bitRange>
            </field>
            <field>
              <name>OC4M_L</name>
              <bitRange>[14:12]</bitRange>
            </field>
            <field>
              <name>OC4CE</name>
              <bitRange>[15:15]</bitRange>
            </field>
            <field>
              <name>OC3M_H</name>
              <bitRange>[16:16]</bitRange>
            </field>
            <field>
              <name>OC4M_H</name>
              <bitRange>[24:24]</bitRange>
            </field>
          </fields>
        </register>
        <register>
          <name>CCMR2_INPUT</name>
          <description>desc CCMR2:INPUT</description>
          <alternateRegister>CCMR2_OUTPUT</alternateRegister>
          <addressOffset>0x1C</addressOffset>
          <fields>
            <field>
              <name>CC3S</name>
              <bitRange>[1:0]</bitRange>
            </field>
            <field>
              <name>IC3PSC</name>
              <bitRange>[3:2]</bitRange>
            </field>
            <field>
              <name>IC3F</name>
              <bitRange>[7:4]</bitRange>
            </field>
            <field>
              <name>CC4S</name>
              <bitRange>[9:8]</bitRange>
            </field>
            <field>
              <name>IC4PSC</name>
              <bitRange>[11:10]</bitRange>
            </field>
            <field>
              <name>IC4F</name>
              <bitRange>[15:12]</bitRange>
            </field>
          </fields>
        </register>
        <register>
          <name>CCER</name>
          <description>desc CCER</description>
          <addressOffset>0x20</addressOffset>
          <fields>
            <field>
              <name>CC1E</name>
              <bitRange>[0:0]</bitRange>
            </field>
            <field>
              <name>CC1P</name>
              <bitRange>[1:1]</bitRange>
            </field>
            <field>
              <name>CC1NP</name>
              <bitRange>[3:3]</bitRange>
            </field>
            <field>
              <name>CC2E</name>
              <bitRange>[4:4]</bitRange>
            </field>
            <field>
              <name>CC2P</name>
              <bitRange>[5:5]</bitRange>
            </field>
            <field>
              <name>CC2NP</name>
              <bitRange>[7:7]</bitRange>
            </field>
            <field>
              <name>CC3E</name>
              <bitRange>[8:8]</bitRange>
            </field>
            <field>
              <name>CC3P</name>
              <bitRange>[9:9]</bitRange>
            </field>
            <field>
              <name>CC3NP</name>
              <bitRange>[11:11]</bitRange>
            </field>
            <field>
              <name>CC4E</name>
              <bitRange>[12:12]</bitRange>
            </field>
            <field>
              <name>CC4P</name>
              <bitRange>[13:13]</bitRange>
            </field>
            <field>
              <name>CC4NP</name>
              <bitRange>[15:15]</bitRange>
            </field>
          </fields>
        </register>
        <register>
          <name>CNT</name>
          <description>desc CNT</description>
          <addressOffset>0x24</addressOffset>
          <fields>
            <field>
              <name>CNT</name>
              <bitRange>[30:0]</bitRange>
            </field>
            <field>
              <name>UIFCPY</name>
              <bitRange>[31:31]</bitRange>
              <access>read-only</access>
            </field>
          </fields>
        </register>
        <register>
          <name>PSC</name>
          <description>desc PSC</description>
          <addressOffset>0x28</addressOffset>
          <fields>
            <field>
              <name>PSC</name>
              <bitRange>[15:0]</bitRange>
            </field>
          </fields>
        </register>
        <register>
          <name>ARR</name>
          <description>desc ARR</description>
          <addressOffset>0x2C</addressOffset>
          <fields>
            <field>
              <name>ARR</name>
              <bitRange>[31:0]</bitRange>
            </field>
          </fields>
        </register>
        <register>
          <name>CCR1</name>
          <description>desc CCR1</description>
          <addressOffset>0x34</addressOffset>
          <fields>
            <field>
              <name>CCR1</name>
              <bitRange>[31:0]</bitRange>
            </field>
          </fields>
        </register>
        <register>
          <name>CCR2</name>
          <description>desc CCR2</description>
          <addressOffset>0x38</addressOffset>
          <fields>
            <field>
              <name>CCR2</name>
              <bitRange>[31:0]</bitRange>
            </field>
          </fields>
        </register>
        <register>
          <name>CCR3</name>
          <description>desc CCR3</description>
          <addressOffset>0x3C</addressOffset>
          <fields>
            <field>
              <name>CCR3</name>
              <bitRange>[31:0]</bitRange>
            </field>
          </fields>
        </register>
        <register>
          <name>CCR4</name>
          <description>desc CCR4</description>
          <addressOffset>0x40</addressOffset>
          <fields>
            <field>
              <name>CCR4</name>
              <bitRange>[31:0]</bitRange>
            </field>
          </fields>
        </register>
        <register>
          <name>ECR</name>
          <addressOffset>0x58</addressOffset>
          <fields>
            <field>
              <name>IE</name>
              <bitRange>[0:0]</bitRange>
            </field>
            <field>
              <name>IDIR</name>
              <bitRange>[2:1]</bitRange>
            </field>
            <field>
              <name>FIDX</name>
              <bitRange>[5:5]</bitRange>
            </field>
            <field>
              <name>IPOS</name>
              <bitRange>[7:6]</bitRange>
            </field>
            <field>
              <name>PW</name>
              <bitRange>[23:16]</bitRange>
            </field>
            <field>
              <name>PWPRSC</name>
              <bitRange>[26:24]</bitRange>
            </field>
          </fields>
        </register>
        <register>
          <name>TISEL</name>
          <addressOffset>0x5C</addressOffset>
          <fields>
            <field>
              <name>TI1SEL</name>
              <bitRange>[3:0]</bitRange>
            </field>
            <field>
              <name>TI2SEL</name>
              <bitRange>[11:8]</bitRange>
            </field>
            <field>
              <name>TI3SEL</name>
              <bitRange>[19:16]</bitRange>
            </field>
            <field>
              <name>TI4SEL</name>
              <bitRange>[27:24]</bitRange>
            </field>
          </fields>
        </register>
        <register>
          <name>AF1</name>
          <addressOffset>0x60</addressOffset>
          <fields>
            <field>
              <name>ETRSEL</name>
              <bitRange>[17:14]</bitRange>
            </field>
          </fields>
        </register>
        <register>
          <name>AF2</name>
          <addressOffset>0x64</addressOffset>
          <fields>
            <field>
              <name>OCRSEL</name>
              <bitRange>[18:16]</bitRange>
            </field>
          </fields>
        </register>
        <register>
          <name>DCR</name>
          <description>desc DCR</description>
          <addressOffset>0x3DC</addressOffset>
          <size>16</size>
          <fields>
            <field>
              <name>DBA</name>
              <bitRange>[4:0]</bitRange>
            </field>
            <field>
              <name>DBL</name>
              <bitRange>[12:8]</bitRange>
            </field>
          </fields>
        </register>
        <register>
          <name>DMAR</name>
          <description>desc DMAR</description>
          <addressOffset>0x3E0</addressOffset>
          <fields>
            <field>
              <name>DMAB</name>
              <bitRange>[31:0]</bitRange>
            </field>
          </fields>
        </register>
      </registers>
    </peripheral>
    <peripheral derivedFrom="TIM2">
      <name>TIM3</name>
      <description>desc TIM</description>
      <baseAddress>0x40000400</baseAddress>
      <interrupt>
        <name>TIM3</name>
        <description>TIM3 global Interrupt</description>
        <value>29</value>
      </interrupt>
    </peripheral>
    <peripheral derivedFrom="TIM2">
      <name>TIM4</name>
      <description>desc TIM</description>
      <baseAddress>0x40000800</baseAddress>
      <interrupt>
        <name>TIM4</name>
        <description>TIM4 global Interrupt</description>
        <value>30</value>
      </interrupt>
    </peripheral>
    <peripheral derivedFrom="TIM2">
      <name>TIM5</name>
      <description>desc TIM</description>
      <baseAddress>0x40000C00</baseAddress>
      <interrupt>
        <name>TIM5</name>
        <description>TIM5 global Interrupt</description>
        <value>50</value>
      </interrupt>
    </peripheral>
    <peripheral>
      <name>TIM6</name>
      <description>desc TIM</description>
      <groupName>TIM</groupName>
      <baseAddress>0x40001000</baseAddress>
      <addressBlock>
        <offset>0x0</offset>
        <size>0x400</size>
        <usage>registers</usage>
      </addressBlock>
      <interrupt>
        <name>TIM6</name>
        <description>TIM6 global Interrupt</description>
        <value>54</value>
      </interrupt>
      <registers>
        <register>
          <name>CR1</name>
          <description>desc CR1</description>
          <addressOffset>0x0</addressOffset>
          <fields>
            <field>
              <name>CEN</name>
              <bitRange>[0:0]</bitRange>
            </field>
            <field>
              <name>UDIS</name>
              <bitRange>[1:1]</bitRange>
            </field>
            <field>
              <name>URS</name>
              <bitRange>[2:2]</bitRange>
            </field>
            <field>
              <name>OPM</name>
              <bitRange>[3:3]</bitRange>
            </field>
            <field>
              <name>ARPE</name>
              <bitRange>[7:7]</bitRange>
            </field>
          </fields>
        </register>
        <register>
          <name>CR2</name>
          <description>desc CR2</description>
          <addressOffset>0x4</addressOffset>
          <fields>
            <field>
              <name>MMS</name>
              <bitRange>[6:4]</bitRange>
            </field>
          </fields>
        </register>
        <register>
          <name>DIER</name>
          <description>desc DIER</description>
          <addressOffset>0xC</addressOffset>
          <fields>
            <field>
              <name>UIE</name>
              <bitRange>[0:0]</bitRange>
            </field>
            <field>
              <name>UDE</name>
              <bitRange>[8:8]</bitRange>
            </field>
          </fields>
        </register>
        <register>
          <name>SR</name>
          <description>desc SR</description>
          <addressOffset>0x10</addressOffset>
          <fields>
            <field>
              <name>UIF</name>
              <bitRange>[0:0]</bitRange>
            </field>
          </fields>
        </register>
        <register>
          <name>EGR</name>
          <description>desc EGR</description>
          <addressOffset>0x14</addressOffset>
          <fields>
            <field>
              <name>UG</name>
              <bitRange>[0:0]</bitRange>
            </field>
          </fields>
        </register>
        <register>
          <name>CNT</name>
          <description>desc CNT</description>
          <addressOffset>0x24</addressOffset>
          <fields>
            <field>
              <name>CNT</name>
              <bitRange>[15:0]</bitRange>
            </field>
          </fields>
        </register>
        <register>
          <name>PSC</name>
          <description>desc PSC</description>
          <addressOffset>0x28</addressOffset>
          <fields>
            <field>
              <name>PSC</name>
              <bitRange>[15:0]</bitRange>
            </field>
          </fields>
        </register>
        <register>
          <name>ARR</name>
          <description>desc ARR</description>
          <addressOffset>0x2C</addressOffset>
          <fields>
            <field>
              <name>ARR</name>
              <bitRange>[15:0]</bitRange>
            </field>
          </fields>
        </register>
      </registers>
    </peripheral>
    <peripheral derivedFrom="TIM6">
      <name>TIM7</name>
      <description>desc TIM</description>
      <baseAddress>0x40001400</baseAddress>
      <interrupt>
        <name>TIM7</name>
        <description>TIM7 global Interrupt</description>
        <value>55</value>
      </interrupt>
    </peripheral>
    <peripheral derivedFrom="TIM1">
      <name>TIM8</name>
      <baseAddress>0x40013400</baseAddress>
      <interrupt>
        <name>TIM8_BRK_TIM12</name>
        <description>TIM8 Break Interrupt and TIM12 global Interrupt</description>
        <value>43</value>
      </interrupt>
      <interrupt>
        <name>TIM8_UP_TIM13</name>
        <description>TIM8 Update Interrupt and TIM13 global Interrupt</description>
        <value>44</value>
      </interrupt>
      <interrupt>
        <name>TIM8_TRG_COM_TIM14</name>
        <description>TIM8 Trigger and Commutation Interrupt and TIM14 global interrupt</description>
        <value>45</value>
      </interrupt>
      <interrupt>
        <name>TIM8_CC</name>
        <description>TIM8 Capture Compare Interrupt</description>
        <value>46</value>
      </interrupt>
    </peripheral>
    <peripheral>
      <name>TIM9</name>
      <groupName>TIM</groupName>
      <baseAddress>0x40014C00</baseAddress>
      <addressBlock>
        <offset>0x0</offset>
        <size>0x400</size>
        <usage>registers</usage>
      </addressBlock>
      <interrupt>
        <name>TIM1_BRK_TIM9</name>
        <description>TIM1 Break Interrupt and TIM9 global Interrupt</description>
        <value>24</value>
      </interrupt>
      <registers>
        <register>
          <name>CR1</name>
          <addressOffset>0x0</addressOffset>
          <size>16</size>
          <fields>
            <field>
              <name>CEN</name>
              <bitRange>[0:0]</bitRange>
            </field>
            <field>
              <name>UDIS</name>
              <bitRange>[1:1]</bitRange>
            </field>
            <field>
              <name>URS</name>
              <bitRange>[2:2]</bitRange>
            </field>
            <field>
              <name>OPM</name>
              <bitRange>[3:3]</bitRange>
            </field>
            <field>
              <name>ARPE</name>
              <bitRange>[7:7]</bitRange>
            </field>
            <field>
              <name>CKD</name>
              <bitRange>[9:8]</bitRange>
            </field>
          </fields>
        </register>
        <register>
          <name>SMCR</name>
          <addressOffset>0x8</addressOffset>
          <size>16</size>
          <fields>
            <field>
              <name>SMS</name>
              <bitRange>[2:0]</bitRange>
            </field>
            <field>
              <name>TS</name>
              <bitRange>[8:4]</bitRange>
            </field>
          </fields>
        </register>
        <register>
          <name>DIER</name>
          <addressOffset>0xC</addressOffset>
          <size>16</size>
          <fields>
            <field>
              <name>UIE</name>
              <bitRange>[0:0]</bitRange>
            </field>
            <field>
              <name>CC1IE</name>
              <bitRange>[1:1]</bitRange>
            </field>
            <field>
              <name>CC2IE</name>
              <bitRange>[2:2]</bitRange>
            </field>
            <field>
              <name>TIE</name>
              <bitRange>[6:6]</bitRange>
            </field>
          </fields>
        </register>
        <register>
          <name>SR</name>
          <addressOffset>0x10</addressOffset>
          <size>16</size>
          <fields>
            <field>
              <name>UIF</name>
              <bitRange>[0:0]</bitRange>
            </field>
            <field>
              <name>CC1IF</name>
              <bitRange>[1:1]</bitRange>
            </field>
            <field>
              <name>CC2IF</name>
              <bitRange>[2:2]</bitRange>
            </field>
            <field>
              <name>COMIF</name>
              <bitRange>[5:5]</bitRange>
            </field>
            <field>
              <name>TIF</name>
              <bitRange>[6:6]</bitRange>
            </field>
            <field>
              <name>CC1OF</name>
              <bitRange>[9:9]</bitRange>
            </field>
            <field>
              <name>CC2OF</name>
              <bitRange>[10:10]</bitRange>
            </field>
          </fields>
        </register>
        <register>
          <name>EGR</name>
          <addressOffset>0x14</addressOffset>
          <size>16</size>
          <fields>
            <field>
              <name>UG</name>
              <bitRange>[0:0]</bitRange>
            </field>
            <field>
              <name>CC1G</name>
              <bitRange>[1:1]</bitRange>
            </field>
            <field>
              <name>CC2G</name>
              <bitRange>[2:2]</bitRange>
            </field>
            <field>
              <name>TG</name>
              <bitRange>[6:6]</bitRange>
            </field>
          </fields>
        </register>
        <register>
          <name>CCMR1_OUTPUT</name>
          <addressOffset>0x18</addressOffset>
          <fields>
            <field>
              <name>CC1S</name>
              <bitRange>[1:0]</bitRange>
            </field>
            <field>
              <name>OC1FE</name>
              <bitRange>[2:2]</bitRange>
            </field>
            <field>
              <name>OC1PE</name>
              <bitRange>[3:3]</bitRange>
            </field>
            <field>
              <name>OC1M</name>
              <bitRange>[6:4]</bitRange>
            </field>
            <field>
              <name>OC1CE</name>
              <bitRange>[7:7]</bitRange>
            </field>
            <field>
              <name>CC2S</name>
              <bitRange>[9:8]</bitRange>
            </field>
            <field>
              <name>OC2FE</name>
              <bitRange>[10:10]</bitRange>
            </field>
            <field>
              <name>OC2PE</name>
              <bitRange>[11:11]</bitRange>
            </field>
            <field>
              <name>OC2M</name>
              <bitRange>[14:12]</bitRange>
            </field>
            <field>
              <name>OC2CE</name>
              <bitRange>[15:15]</bitRange>
            </field>
          </fields>
        </register>
        <register>
          <name>CCMR1_INPUT</name>
          <alternateRegister>CCMR1_OUTPUT</alternateRegister>
          <addressOffset>0x18</addressOffset>
          <size>16</size>
          <fields>
            <field>
              <name>CC1S</name>
              <bitRange>[1:0]</bitRange>
            </field>
            <field>
              <name>IC1PSC</name>
              <bitRange>[3:2]</bitRange>
            </field>
            <field>
              <name>IC1F</name>
              <bitRange>[7:4]</bitRange>
            </field>
            <field>
              <name>CC2S</name>
              <bitRange>[9:8]</bitRange>
            </field>
            <field>
              <name>IC2PSC</name>
              <bitRange>[11:10]</bitRange>
            </field>
            <field>
              <name>IC2F</name>
              <bitRange>[15:12]</bitRange>
            </field>
          </fields>
        </register>
        <register>
          <name>CCER</name>
          <addressOffset>0x20</addressOffset>
          <size>16</size>
          <fields>
            <field>
              <name>CC1E</name>
              <bitRange>[0:0]</bitRange>
            </field>
            <field>
              <name>CC1P</name>
              <bitRange>[1:1]</bitRange>
            </field>
            <field>
              <name>CC1NE</name>
              <bitRange>[2:2]</bitRange>
            </field>
            <field>
              <name>CC1NP</name>
              <bitRange>[3:3]</bitRange>
            </field>
            <field>
              <name>CC2E</name>
              <bitRange>[4:4]</bitRange>
            </field>
            <field>
              <name>CC2P</name>
              <bitRange>[5:5]</bitRange>
            </field>
            <field>
              <name>CC2NE</name>
              <bitRange>[6:6]</bitRange>
            </field>
            <field>
              <name>CC2NP</name>
              <bitRange>[7:7]</bitRange>
            </field>
          </fields>
        </register>
        <register>
          <name>CNT</name>
          <addressOffset>0x24</addressOffset>
          <size>16</size>
          <fields>
            <field>
              <name>CNT</name>
              <bitRange>[15:0]</bitRange>
            </field>
          </fields>
        </register>
        <register>
          <name>PSC</name>
          <addressOffset>0x28</addressOffset>
          <size>16</size>
          <fields>
            <field>
              <name>PSC</name>
              <bitRange>[15:0]</bitRange>
            </field>
          </fields>
        </register>
        <register>
          <name>ARR</name>
          <addressOffset>0x2C</addressOffset>
          <size>16</size>
          <fields>
            <field>
              <name>ARR</name>
              <bitRange>[15:0]</bitRange>
            </field>
          </fields>
        </register>
        <register>
          <name>RCR</name>
          <addressOffset>0x30</addressOffset>
          <size>16</size>
          <fields>
            <field>
              <name>REP</name>
              <bitRange>[7:0]</bitRange>
            </field>
          </fields>
        </register>
        <register>
          <name>CCR1</name>
          <addressOffset>0x34</addressOffset>
          <size>16</size>
          <fields>
            <field>
              <name>CCR1</name>
              <bitRange>[15:0]</bitRange>
            </field>
          </fields>
        </register>
        <register>
          <name>CCR2</name>
          <addressOffset>0x38</addressOffset>
          <size>16</size>
          <fields>
            <field>
              <name>CCR2</name>
              <bitRange>[15:0]</bitRange>
            </field>
          </fields>
        </register>
      </registers>
    </peripheral>
    <peripheral>
      <name>TIM10</name>
      <groupName>TIM</groupName>
      <baseAddress>0x40015000</baseAddress>
      <addressBlock>
        <offset>0x0</offset>
        <size>0x400</size>
        <usage>registers</usage>
      </addressBlock>
      <interrupt>
        <name>TIM1_UP_TIM10</name>
        <description>TIM1 Update Interrupt and TIM10 global Interrupt</description>
        <value>25</value>
      </interrupt>
      <registers>
        <register>
          <name>CR1</name>
          <addressOffset>0x0</addressOffset>
          <size>16</size>
          <fields>
            <field>
              <name>CEN</name>
              <bitRange>[0:0]</bitRange>
            </field>
            <field>
              <name>UDIS</name>
              <bitRange>[1:1]</bitRange>
            </field>
            <field>
              <name>URS</name>
              <bitRange>[2:2]</bitRange>
            </field>
            <field>
              <name>OPM</name>
              <bitRange>[3:3]</bitRange>
            </field>
            <field>
              <name>ARPE</name>
              <bitRange>[7:7]</bitRange>
            </field>
            <field>
              <name>CKD</name>
              <bitRange>[9:8]</bitRange>
            </field>
          </fields>
        </register>
        <register>
          <name>DIER</name>
          <addressOffset>0xC</addressOffset>
          <size>16</size>
          <fields>
            <field>
              <name>UIE</name>
              <bitRange>[0:0]</bitRange>
            </field>
            <field>
              <name>CC1IE</name>
              <bitRange>[1:1]</bitRange>
            </field>
            <field>
              <name>TIE</name>
              <bitRange>[6:6]</bitRange>
            </field>
          </fields>
        </register>
        <register>
          <name>SR</name>
          <addressOffset>0x10</addressOffset>
          <size>16</size>
          <fields>
            <field>
              <name>UIF</name>
              <bitRange>[0:0]</bitRange>
            </field>
            <field>
              <name>CC1IF</name>
              <bitRange>[1:1]</bitRange>
            </field>
            <field>
              <name>CC1OF</name>
              <bitRange>[9:9]</bitRange>
            </field>
          </fields>
        </register>
        <register>
          <name>EGR</name>
          <addressOffset>0x14</addressOffset>
          <size>16</size>
          <fields>
            <field>
              <name>UG</name>
              <bitRange>[0:0]</bitRange>
            </field>
            <field>
              <name>CC1G</name>
              <bitRange>[1:1]</bitRange>
            </field>
          </fields>
        </register>
        <register>
          <name>CCMR1_OUTPUT</name>
          <addressOffset>0x18</addressOffset>
          <fields>
            <field>
              <name>CC1S</name>
              <bitRange>[1:0]</bitRange>
            </field>
            <field>
              <name>OC1PE</name>
              <bitRange>[3:3]</bitRange>
            </field>
            <field>
              <name>OC1M</name>
              <bitRange>[6:4]</bitRange>
            </field>
            <field>
              <name>OC1CE</name>
              <bitRange>[7:7]</bitRange>
            </field>
          </fields>
        </register>
        <register>
          <name>CCMR1_INPUT</name>
          <alternateRegister>CCMR1_OUTPUT</alternateRegister>
          <addressOffset>0x18</addressOffset>
          <size>16</size>
          <fields>
            <field>
              <name>CC1S</name>
              <bitRange>[1:0]</bitRange>
            </field>
            <field>
              <name>IC1PSC</name>
              <bitRange>[3:2]</bitRange>
            </field>
            <field>
              <name>IC1F</name>
              <bitRange>[7:4]</bitRange>
            </field>
          </fields>
        </register>
        <register>
          <name>CCER</name>
          <addressOffset>0x20</addressOffset>
          <size>16</size>
          <fields>
            <field>
              <name>CC1E</name>
              <bitRange>[0:0]</bitRange>
            </field>
            <field>
              <name>CC1P</name>
              <bitRange>[1:1]</bitRange>
            </field>
            <field>
              <name>CC1NP</name>
              <bitRange>[3:3]</bitRange>
            </field>
          </fields>
        </register>
        <register>
          <name>CNT</name>
          <addressOffset>0x24</addressOffset>
          <size>16</size>
          <fields>
            <field>
              <name>CNT</name>
              <bitRange>[15:0]</bitRange>
            </field>
          </fields>
        </register>
        <register>
          <name>PSC</name>
          <addressOffset>0x28</addressOffset>
          <size>16</size>
          <fields>
            <field>
              <name>PSC</name>
              <bitRange>[15:0]</bitRange>
            </field>
          </fields>
        </register>
        <register>
          <name>ARR</name>
          <addressOffset>0x2C</addressOffset>
          <size>16</size>
          <fields>
            <field>
              <name>ARR</name>
              <bitRange>[15:0]</bitRange>
            </field>
          </fields>
        </register>
        <register>
          <name>CCR1</name>
          <addressOffset>0x34</addressOffset>
          <size>16</size>
          <fields>
            <field>
              <name>CCR1</name>
              <bitRange>[15:0]</bitRange>
            </field>
          </fields>
        </register>
        <register>
          <name>OR</name>
          <addressOffset>0x50</addressOffset>
          <size>16</size>
          <fields>
            <field>
              <name>TI1_RMP</name>
              <bitRange>[15:0]</bitRange>
            </field>
          </fields>
        </register>
      </registers>
    </peripheral>
    <peripheral derivedFrom="TIM10">
      <name>TIM11</name>
      <baseAddress>0x40015400</baseAddress>
    </peripheral>
    <peripheral derivedFrom="TIM9">
      <name>TIM12</name>
      <baseAddress>0x40001800</baseAddress>
    </peripheral>
    <peripheral derivedFrom="TIM10">
      <name>TIM13</name>
      <baseAddress>0x40001C00</baseAddress>
    </peripheral>
    <peripheral derivedFrom="TIM10">
      <name>TIM14</name>
      <baseAddress>0x40002000</baseAddress>
    </peripheral>
    <peripheral>
      <name>TIM15</name>
      <groupName>TIM</groupName>
      <baseAddress>0x40015800</baseAddress>
      <addressBlock>
        <offset>0x0</offset>
        <size>0x3F0</size>
        <usage>registers</usage>
      </addressBlock>
      <interrupt>
        <name>TIM15</name>
        <description>TIM15 global Interrupt</description>
        <value>60</value>
      </interrupt>
      <registers>
        <register>
          <name>CR1</name>
          <addressOffset>0x0</addressOffset>
          <size>16</size>
          <fields>
            <field>
              <name>CEN</name>
              <bitRange>[0:0]</bitRange>
            </field>
            <field>
              <name>UDIS</name>
              <bitRange>[1:1]</bitRange>
            </field>
            <field>
              <name>URS</name>
              <bitRange>[2:2]</bitRange>
            </field>
            <field>
              <name>OPM</name>
              <bitRange>[3:3]</bitRange>
            </field>
            <field>
              <name>ARPE</name>
              <bitRange>[7:7]</bitRange>
            </field>
            <field>
              <name>CKD</name>
              <bitRange>[9:8]</bitRange>
            </field>
            <field>
              <name>UIFREMAP</name>
              <bitRange>[11:11]</bitRange>
            </field>
            <field>
              <name>DITHEN</name>
              <bitRange>[12:12]</bitRange>
            </field>
          </fields>
        </register>
        <register>
          <name>CR2</name>
          <addressOffset>0x4</addressOffset>
          <size>16</size>
          <fields>
            <field>
              <name>CCPC</name>
              <bitRange>[0:0]</bitRange>
            </field>
            <field>
              <name>CCUS</name>
              <bitRange>[2:2]</bitRange>
            </field>
            <field>
              <name>CCDS</name>
              <bitRange>[3:3]</bitRange>
            </field>
            <field>
              <name>MMS</name>
              <bitRange>[6:4]</bitRange>
              <access>read-only</access>
            </field>
            <field>
              <name>TI1S</name>
              <bitRange>[7:7]</bitRange>
            </field>
            <field>
              <name>OIS1</name>
              <bitRange>[8:8]</bitRange>
            </field>
            <field>
              <name>OIS1N</name>
              <bitRange>[9:9]</bitRange>
            </field>
            <field>
              <name>OIS2</name>
              <bitRange>[10:10]</bitRange>
            </field>
          </fields>
        </register>
        <register>
          <name>SMCR</name>
          <addressOffset>0x8</addressOffset>
          <fields>
            <field>
              <name>SMS_L</name>
              <bitRange>[2:0]</bitRange>
            </field>
            <field>
              <name>TS_L</name>
              <bitRange>[6:5]</bitRange>
            </field>
            <field>
              <name>MSM</name>
              <bitRange>[7:7]</bitRange>
            </field>
            <field>
              <name>SMS_H</name>
              <bitRange>[16:16]</bitRange>
            </field>
            <field>
              <name>TS_H</name>
              <bitRange>[21:20]</bitRange>
            </field>
          </fields>
        </register>
        <register>
          <name>DIER</name>
          <addressOffset>0xC</addressOffset>
          <size>16</size>
          <fields>
            <field>
              <name>UIE</name>
              <bitRange>[0:0]</bitRange>
            </field>
            <field>
              <name>CC1IE</name>
              <bitRange>[1:1]</bitRange>
            </field>
            <field>
              <name>CC2IE</name>
              <bitRange>[2:2]</bitRange>
            </field>
            <field>
              <name>COMIE</name>
              <bitRange>[5:5]</bitRange>
            </field>
            <field>
              <name>TIE</name>
              <bitRange>[6:6]</bitRange>
            </field>
            <field>
              <name>BIE</name>
              <bitRange>[7:7]</bitRange>
            </field>
            <field>
              <name>UDE</name>
              <bitRange>[8:8]</bitRange>
            </field>
            <field>
              <name>CC1DE</name>
              <bitRange>[9:9]</bitRange>
            </field>
            <field>
              <name>COMDE</name>
              <bitRange>[13:13]</bitRange>
            </field>
            <field>
              <name>TDE</name>
              <bitRange>[14:14]</bitRange>
            </field>
          </fields>
        </register>
        <register>
          <name>SR</name>
          <addressOffset>0x10</addressOffset>
          <fields>
            <field>
              <name>UIF</name>
              <bitRange>[0:0]</bitRange>
            </field>
            <field>
              <name>CC1IF</name>
              <bitRange>[1:1]</bitRange>
            </field>
            <field>
              <name>CC2IF</name>
              <bitRange>[2:2]</bitRange>
            </field>
            <field>
              <name>COMIF</name>
              <bitRange>[5:5]</bitRange>
            </field>
            <field>
              <name>TIF</name>
              <bitRange>[6:6]</bitRange>
            </field>
            <field>
              <name>BIF</name>
              <bitRange>[7:7]</bitRange>
            </field>
            <field>
              <name>CC1OF</name>
              <bitRange>[9:9]</bitRange>
            </field>
            <field>
              <name>CC2OF</name>
              <bitRange>[10:10]</bitRange>
            </field>
            <field>
              <name>IC1IR</name>
              <bitRange>[16:16]</bitRange>
            </field>
            <field>
              <name>IC2IR</name>
              <bitRange>[17:17]</bitRange>
            </field>
            <field>
              <name>IC1IF</name>
              <bitRange>[20:20]</bitRange>
            </field>
            <field>
              <name>IC2IF</name>
              <bitRange>[21:21]</bitRange>
            </field>
          </fields>
        </register>
        <register>
          <name>EGR</name>
          <addressOffset>0x14</addressOffset>
          <size>16</size>
          <fields>
            <field>
              <name>UG</name>
              <bitRange>[0:0]</bitRange>
              <access>read-only</access>
            </field>
            <field>
              <name>CC1G</name>
              <bitRange>[1:1]</bitRange>
              <access>read-only</access>
            </field>
            <field>
              <name>CC2G</name>
              <bitRange>[2:2]</bitRange>
              <access>read-only</access>
            </field>
            <field>
              <name>COMG</name>
              <bitRange>[5:5]</bitRange>
              <access>read-only</access>
            </field>
            <field>
              <name>TG</name>
              <bitRange>[6:6]</bitRange>
              <access>read-only</access>
            </field>
            <field>
              <name>BG</name>
              <bitRange>[7:7]</bitRange>
              <access>read-only</access>
            </field>
          </fields>
        </register>
        <register>
          <name>CCMR1_OUTPUT</name>
          <addressOffset>0x18</addressOffset>
          <fields>
            <field>
              <name>CC1S</name>
              <bitRange>[1:0]</bitRange>
            </field>
            <field>
              <name>OC1FE</name>
              <bitRange>[2:2]</bitRange>
            </field>
            <field>
              <name>OC1PE</name>
              <bitRange>[3:3]</bitRange>
            </field>
            <field>
              <name>OC1M_L</name>
              <bitRange>[6:4]</bitRange>
            </field>
            <field>
              <name>OC1CE</name>
              <bitRange>[7:7]</bitRange>
            </field>
            <field>
              <name>CC2S</name>
              <bitRange>[9:8]</bitRange>
            </field>
            <field>
              <name>OC2FE</name>
              <bitRange>[10:10]</bitRange>
            </field>
            <field>
              <name>OC2PE</name>
              <bitRange>[11:11]</bitRange>
            </field>
            <field>
              <name>OC2M_L</name>
              <bitRange>[14:12]</bitRange>
            </field>
            <field>
              <name>OC2CE</name>
              <bitRange>[15:15]</bitRange>
            </field>
            <field>
              <name>OC1M_H</name>
              <bitRange>[16:16]</bitRange>
            </field>
            <field>
              <name>OC2M_H</name>
              <bitRange>[24:24]</bitRange>
            </field>
          </fields>
        </register>
        <register>
          <name>CCMR1_INPUT</name>
          <alternateRegister>CCMR1_OUTPUT</alternateRegister>
          <addressOffset>0x18</addressOffset>
          <fields>
            <field>
              <name>CC1S</name>
              <bitRange>[1:0]</bitRange>
            </field>
            <field>
              <name>IC1PSC</name>
              <bitRange>[3:2]</bitRange>
            </field>
            <field>
              <name>IC1F</name>
              <bitRange>[7:4]</bitRange>
            </field>
            <field>
              <name>CC2S</name>
              <bitRange>[9:8]</bitRange>
            </field>
            <field>
              <name>IC2PSC</name>
              <bitRange>[11:10]</bitRange>
            </field>
            <field>
              <name>IC2F</name>
              <bitRange>[15:12]</bitRange>
            </field>
          </fields>
        </register>
        <register>
          <name>CCER</name>
          <addressOffset>0x20</addressOffset>
          <size>16</size>
          <fields>
            <field>
              <name>CC1E</name>
              <bitRange>[0:0]</bitRange>
            </field>
            <field>
              <name>CC1P</name>
              <bitRange>[1:1]</bitRange>
            </field>
            <field>
              <name>CC1NE</name>
              <bitRange>[2:2]</bitRange>
            </field>
            <field>
              <name>CC1NP</name>
              <bitRange>[3:3]</bitRange>
            </field>
            <field>
              <name>CC2E</name>
              <bitRange>[4:4]</bitRange>
            </field>
            <field>
              <name>CC2P</name>
              <bitRange>[5:5]</bitRange>
            </field>
            <field>
              <name>CC2NP</name>
              <bitRange>[7:7]</bitRange>
            </field>
          </fields>
        </register>
        <register>
          <name>CNT</name>
          <addressOffset>0x24</addressOffset>
          <fields>
            <field>
              <name>CNT</name>
              <bitRange>[15:0]</bitRange>
            </field>
            <field>
              <name>UIFCPY</name>
              <bitRange>[31:31]</bitRange>
              <access>read-only</access>
            </field>
          </fields>
        </register>
        <register>
          <name>PSC</name>
          <addressOffset>0x28</addressOffset>
          <fields>
            <field>
              <name>PSC</name>
              <bitRange>[15:0]</bitRange>
            </field>
          </fields>
        </register>
        <register>
          <name>ARR</name>
          <addressOffset>0x2C</addressOffset>
          <fields>
            <field>
              <name>ARR</name>
              <bitRange>[19:0]</bitRange>
            </field>
          </fields>
        </register>
        <register>
          <name>RCR</name>
          <addressOffset>0x30</addressOffset>
          <fields>
            <field>
              <name>REP</name>
              <bitRange>[7:0]</bitRange>
            </field>
          </fields>
        </register>
        <register>
          <name>CCR1</name>
          <addressOffset>0x34</addressOffset>
          <fields>
            <field>
              <name>CCR1</name>
              <bitRange>[19:0]</bitRange>
            </field>
          </fields>
        </register>
        <register>
          <name>CCR2</name>
          <addressOffset>0x38</addressOffset>
          <fields>
            <field>
              <name>CCR2</name>
              <bitRange>[19:0]</bitRange>
            </field>
          </fields>
        </register>
        <register>
          <name>BDTR</name>
          <addressOffset>0x44</addressOffset>
          <fields>
            <field>
              <name>DTG</name>
              <bitRange>[7:0]</bitRange>
            </field>
            <field>
              <name>LOCK</name>
              <bitRange>[9:8]</bitRange>
            </field>
            <field>
              <name>OSSI</name>
              <bitRange>[10:10]</bitRange>
            </field>
            <field>
              <name>OSSR</name>
              <bitRange>[11:11]</bitRange>
            </field>
            <field>
              <name>BKE</name>
              <bitRange>[12:12]</bitRange>
            </field>
            <field>
              <name>BKP</name>
              <bitRange>[13:13]</bitRange>
            </field>
            <field>
              <name>AOE</name>
              <bitRange>[14:14]</bitRange>
            </field>
            <field>
              <name>MOE</name>
              <bitRange>[15:15]</bitRange>
            </field>
            <field>
              <name>BKF</name>
              <bitRange>[19:16]</bitRange>
            </field>
            <field>
              <name>BKDSRM</name>
              <bitRange>[26:26]</bitRange>
            </field>
            <field>
              <name>BKBID</name>
              <bitRange>[28:28]</bitRange>
            </field>
          </fields>
        </register>
        <register>
          <name>DTR2</name>
          <addressOffset>0x54</addressOffset>
          <fields>
            <field>
              <name>DTGF</name>
              <bitRange>[7:0]</bitRange>
            </field>
            <field>
              <name>DTAE</name>
              <bitRange>[16:16]</bitRange>
            </field>
            <field>
              <name>DTPE</name>
              <bitRange>[17:17]</bitRange>
            </field>
          </fields>
        </register>
        <register>
          <name>TISEL</name>
          <addressOffset>0x5C</addressOffset>
          <fields>
            <field>
              <name>TI1SEL</name>
              <bitRange>[3:0]</bitRange>
            </field>
            <field>
              <name>TI2SEL</name>
              <bitRange>[11:8]</bitRange>
            </field>
          </fields>
        </register>
        <register>
          <name>AF1</name>
          <addressOffset>0x60</addressOffset>
          <fields>
            <field>
              <name>BKINE</name>
              <bitRange>[0:0]</bitRange>
            </field>
            <field>
              <name>BKCMP1E</name>
              <bitRange>[1:1]</bitRange>
            </field>
            <field>
              <name>BKCMP2E</name>
              <bitRange>[2:2]</bitRange>
            </field>
            <field>
              <name>BKCMP3E</name>
              <bitRange>[3:3]</bitRange>
            </field>
            <field>
              <name>BKCMP4E</name>
              <bitRange>[4:4]</bitRange>
            </field>
            <field>
              <name>BKINP</name>
              <bitRange>[9:9]</bitRange>
            </field>
            <field>
              <name>BKCMP1P</name>
              <bitRange>[10:10]</bitRange>
            </field>
            <field>
              <name>BKCMP2P</name>
              <bitRange>[11:11]</bitRange>
            </field>
            <field>
              <name>BKCMP3P</name>
              <bitRange>[12:12]</bitRange>
            </field>
            <field>
              <name>BKCMP4P</name>
              <bitRange>[13:13]</bitRange>
            </field>
          </fields>
        </register>
        <register>
          <name>AF2</name>
          <addressOffset>0x64</addressOffset>
          <fields>
            <field>
              <name>OCRSEL</name>
              <bitRange>[18:16]</bitRange>
            </field>
          </fields>
        </register>
        <register>
          <name>DCR</name>
          <addressOffset>0x3DC</addressOffset>
          <size>16</size>
          <fields>
            <field>
              <name>DBA</name>
              <bitRange>[4:0]</bitRange>
            </field>
            <field>
              <name>DBL</name>
              <bitRange>[12:8]</bitRange>
            </field>
          </fields>
        </register>
        <register>
          <name>DMAR</name>
          <addressOffset>0x3E0</addressOffset>
          <fields>
            <field>
              <name>DMAB</name>
              <bitRange>[31:0]</bitRange>
            </field>
          </fields>
        </register>
      </registers>
    </peripheral>
    <peripheral>
      <name>TIM16</name>
      <groupName>TIM</groupName>
      <baseAddress>0x40015C00</baseAddress>
      <addressBlock>
        <offset>0x0</offset>
        <size>0x3F0</size>
        <usage>registers</usage>
      </addressBlock>
      <interrupt>
        <name>TIM16</name>
        <description>TIM16 global Interrupt</description>
        <value>61</value>
      </interrupt>
      <registers>
        <register>
          <name>CR1</name>
          <addressOffset>0x0</addressOffset>
          <size>16</size>
          <fields>
            <field>
              <name>CEN</name>
              <bitRange>[0:0]</bitRange>
            </field>
            <field>
              <name>UDIS</name>
              <bitRange>[1:1]</bitRange>
            </field>
            <field>
              <name>URS</name>
              <bitRange>[2:2]</bitRange>
            </field>
            <field>
              <name>OPM</name>
              <bitRange>[3:3]</bitRange>
            </field>
            <field>
              <name>ARPE</name>
              <bitRange>[7:7]</bitRange>
            </field>
            <field>
              <name>CKD</name>
              <bitRange>[9:8]</bitRange>
            </field>
            <field>
              <name>UIFREMAP</name>
              <bitRange>[11:11]</bitRange>
            </field>
            <field>
              <name>DITHEN</name>
              <bitRange>[12:12]</bitRange>
            </field>
          </fields>
        </register>
        <register>
          <name>CR2</name>
          <addressOffset>0x4</addressOffset>
          <size>16</size>
          <fields>
            <field>
              <name>CCPC</name>
              <bitRange>[0:0]</bitRange>
            </field>
            <field>
              <name>CCDS</name>
              <bitRange>[3:3]</bitRange>
            </field>
            <field>
              <name>MMS</name>
              <bitRange>[6:4]</bitRange>
              <access>read-only</access>
            </field>
            <field>
              <name>TI1S</name>
              <bitRange>[7:7]</bitRange>
            </field>
            <field>
              <name>OIS1</name>
              <bitRange>[8:8]</bitRange>
            </field>
            <field>
              <name>OIS1N</name>
              <bitRange>[9:9]</bitRange>
            </field>
            <field>
              <name>OIS2</name>
              <bitRange>[10:10]</bitRange>
            </field>
          </fields>
        </register>
        <register>
          <name>DIER</name>
          <addressOffset>0xC</addressOffset>
          <size>16</size>
          <fields>
            <field>
              <name>UIE</name>
              <bitRange>[0:0]</bitRange>
            </field>
            <field>
              <name>CC1IE</name>
              <bitRange>[1:1]</bitRange>
            </field>
            <field>
              <name>COMIE</name>
              <bitRange>[5:5]</bitRange>
            </field>
            <field>
              <name>BIE</name>
              <bitRange>[7:7]</bitRange>
            </field>
            <field>
              <name>UDE</name>
              <bitRange>[8:8]</bitRange>
            </field>
            <field>
              <name>CC1DE</name>
              <bitRange>[9:9]</bitRange>
            </field>
          </fields>
        </register>
        <register>
          <name>SR</name>
          <addressOffset>0x10</addressOffset>
          <fields>
            <field>
              <name>UIF</name>
              <bitRange>[0:0]</bitRange>
            </field>
            <field>
              <name>CC1IF</name>
              <bitRange>[1:1]</bitRange>
            </field>
            <field>
              <name>COMIF</name>
              <bitRange>[5:5]</bitRange>
            </field>
            <field>
              <name>BIF</name>
              <bitRange>[7:7]</bitRange>
            </field>
            <field>
              <name>CC1OF</name>
              <bitRange>[9:9]</bitRange>
            </field>
            <field>
              <name>IC1IR</name>
              <bitRange>[16:16]</bitRange>
            </field>
            <field>
              <name>IC1IF</name>
              <bitRange>[20:20]</bitRange>
            </field>
          </fields>
        </register>
        <register>
          <name>EGR</name>
          <addressOffset>0x14</addressOffset>
          <size>16</size>
          <fields>
            <field>
              <name>UG</name>
              <bitRange>[0:0]</bitRange>
              <access>read-only</access>
            </field>
            <field>
              <name>CC1G</name>
              <bitRange>[1:1]</bitRange>
              <access>read-only</access>
            </field>
            <field>
              <name>COMG</name>
              <bitRange>[5:5]</bitRange>
              <access>read-only</access>
            </field>
            <field>
              <name>BG</name>
              <bitRange>[7:7]</bitRange>
              <access>read-only</access>
            </field>
          </fields>
        </register>
        <register>
          <name>CCMR1_OUTPUT</name>
          <addressOffset>0x18</addressOffset>
          <fields>
            <field>
              <name>CC1S</name>
              <bitRange>[1:0]</bitRange>
            </field>
            <field>
              <name>OC1FE</name>
              <bitRange>[2:2]</bitRange>
            </field>
            <field>
              <name>OC1PE</name>
              <bitRange>[3:3]</bitRange>
            </field>
            <field>
              <name>OC1M_L</name>
              <bitRange>[6:4]</bitRange>
            </field>
            <field>
              <name>OC1CE</name>
              <bitRange>[7:7]</bitRange>
            </field>
            <field>
              <name>OC1M_H</name>
              <bitRange>[16:16]</bitRange>
            </field>
          </fields>
        </register>
        <register>
          <name>CCMR1_INPUT</name>
          <alternateRegister>CCMR1_OUTPUT</alternateRegister>
          <addressOffset>0x18</addressOffset>
          <fields>
            <field>
              <name>CC1S</name>
              <bitRange>[1:0]</bitRange>
            </field>
            <field>
              <name>IC1PSC</name>
              <bitRange>[3:2]</bitRange>
            </field>
            <field>
              <name>IC1F</name>
              <bitRange>[7:4]</bitRange>
            </field>
            <field>
              <name>CC2S</name>
              <bitRange>[9:8]</bitRange>
            </field>
            <field>
              <name>IC2PSC</name>
              <bitRange>[11:10]</bitRange>
            </field>
            <field>
              <name>IC2F</name>
              <bitRange>[15:12]</bitRange>
            </field>
          </fields>
        </register>
        <register>
          <name>CCER</name>
          <addressOffset>0x20</addressOffset>
          <size>16</size>
          <fields>
            <field>
              <name>CC1E</name>
              <bitRange>[0:0]</bitRange>
            </field>
            <field>
              <name>CC1P</name>
              <bitRange>[1:1]</bitRange>
            </field>
            <field>
              <name>CC1NE</name>
              <bitRange>[2:2]</bitRange>
            </field>
            <field>
              <name>CC1NP</name>
              <bitRange>[3:3]</bitRange>
            </field>
          </fields>
        </register>
        <register>
          <name>CNT</name>
          <addressOffset>0x24</addressOffset>
          <fields>
            <field>
              <name>CNT</name>
              <bitRange>[15:0]</bitRange>
            </field>
            <field>
              <name>UIFCPY</name>
              <bitRange>[31:31]</bitRange>
              <access>read-only</access>
            </field>
          </fields>
        </register>
        <register>
          <name>PSC</name>
          <addressOffset>0x28</addressOffset>
          <fields>
            <field>
              <name>PSC</name>
              <bitRange>[15:0]</bitRange>
            </field>
          </fields>
        </register>
        <register>
          <name>ARR</name>
          <addressOffset>0x2C</addressOffset>
          <fields>
            <field>
              <name>ARR</name>
              <bitRange>[19:0]</bitRange>
            </field>
          </fields>
        </register>
        <register>
          <name>RCR</name>
          <addressOffset>0x30</addressOffset>
          <fields>
            <field>
              <name>REP</name>
              <bitRange>[7:0]</bitRange>
            </field>
          </fields>
        </register>
        <register>
          <name>CCR1</name>
          <addressOffset>0x34</addressOffset>
          <fields>
            <field>
              <name>CCR1</name>
              <bitRange>[19:0]</bitRange>
            </field>
          </fields>
        </register>
        <register>
          <name>BDTR</name>
          <addressOffset>0x44</addressOffset>
          <fields>
            <field>
              <name>DTG</name>
              <bitRange>[7:0]</bitRange>
            </field>
            <field>
              <name>LOCK</name>
              <bitRange>[9:8]</bitRange>
            </field>
            <field>
              <name>OSSI</name>
              <bitRange>[10:10]</bitRange>
            </field>
            <field>
              <name>OSSR</name>
              <bitRange>[11:11]</bitRange>
            </field>
            <field>
              <name>BKE</name>
              <bitRange>[12:12]</bitRange>
            </field>
            <field>
              <name>BKP</name>
              <bitRange>[13:13]</bitRange>
            </field>
            <field>
              <name>AOE</name>
              <bitRange>[14:14]</bitRange>
            </field>
            <field>
              <name>MOE</name>
              <bitRange>[15:15]</bitRange>
            </field>
            <field>
              <name>BKF</name>
              <bitRange>[19:16]</bitRange>
            </field>
            <field>
              <name>BKDSRM</name>
              <bitRange>[26:26]</bitRange>
            </field>
            <field>
              <name>BKBID</name>
              <bitRange>[28:28]</bitRange>
            </field>
          </fields>
        </register>
        <register>
          <name>DTR2</name>
          <addressOffset>0x54</addressOffset>
          <fields>
            <field>
              <name>DTGF</name>
              <bitRange>[7:0]</bitRange>
            </field>
            <field>
              <name>DTAE</name>
              <bitRange>[16:16]</bitRange>
            </field>
            <field>
              <name>DTPE</name>
              <bitRange>[17:17]</bitRange>
            </field>
          </fields>
        </register>
        <register>
          <name>TISEL</name>
          <addressOffset>0x5C</addressOffset>
          <fields>
            <field>
              <name>TI1SEL</name>
              <bitRange>[3:0]</bitRange>
            </field>
          </fields>
        </register>
        <register>
          <name>AF1</name>
          <addressOffset>0x60</addressOffset>
          <fields>
            <field>
              <name>BKINE</name>
              <bitRange>[0:0]</bitRange>
            </field>
            <field>
              <name>BKCMP1E</name>
              <bitRange>[1:1]</bitRange>
            </field>
            <field>
              <name>BKCMP2E</name>
              <bitRange>[2:2]</bitRange>
            </field>
            <field>
              <name>BKCMP3E</name>
              <bitRange>[3:3]</bitRange>
            </field>
            <field>
              <name>BKCMP4E</name>
              <bitRange>[4:4]</bitRange>
            </field>
            <field>
              <name>BKINP</name>
              <bitRange>[9:9]</bitRange>
            </field>
            <field>
              <name>BKCMP1P</name>
              <bitRange>[10:10]</bitRange>
            </field>
            <field>
              <name>BKCMP2P</name>
              <bitRange>[11:11]</bitRange>
            </field>
            <field>
              <name>BKCMP3P</name>
              <bitRange>[12:12]</bitRange>
            </field>
            <field>
              <name>BKCMP4P</name>
              <bitRange>[13:13]</bitRange>
            </field>
          </fields>
        </register>
        <register>
          <name>AF2</name>
          <addressOffset>0x64</addressOffset>
          <fields>
            <field>
              <name>OCRSEL</name>
              <bitRange>[18:16]</bitRange>
            </field>
          </fields>
        </register>
        <register>
          <name>OR1</name>
          <addressOffset>0x68</addressOffset>
          <fields>
            <field>
              <name>HSE32EN</name>
              <bitRange>[0:0]</bitRange>
            </field>
          </fields>
        </register>
        <register>
          <name>DCR</name>
          <addressOffset>0x3DC</addressOffset>
          <size>16</size>
          <fields>
            <field>
              <name>DBA</name>
              <bitRange>[4:0]</bitRange>
            </field>
            <field>
              <name>DBL</name>
              <bitRange>[12:8]</bitRange>
            </field>
          </fields>
        </register>
        <register>
          <name>DMAR</name>
          <addressOffset>0x3E0</addressOffset>
          <fields>
            <field>
              <name>DMAB</name>
              <bitRange>[31:0]</bitRange>
            </field>
          </fields>
        </register>
      </registers>
    </peripheral>
    <peripheral derivedFrom="TIM16">
      <name>TIM17</name>
      <baseAddress>0x40016000</baseAddress>
      <interrupt>
        <name>TIM17</name>
        <description>TIM17 global Interrupt</description>
        <value>62</value>
      </interrupt>
    </peripheral>
    <peripheral derivedFrom="TIM2">
      <name>TIM18</name>
      <baseAddress>0x40002400</baseAddress>
      <interrupt>
        <name>TIM18</name>
        <description>TIM18 global Interrupt</description>
        <value>22</value>
      </interrupt>
    </peripheral>
    <peripheral derivedFrom="TIM10">
      <name>TIM19</name>
      <baseAddress>0x40016400</baseAddress>
      <interrupt>
        <name>TIM19</name>
        <description>TIM19 global Interrupt</description>
        <value>42</value>
      </interrupt>
    </peripheral>
    <peripheral>
      <name>UART1</name>
      <groupName>UART</groupName>
      <baseAddress>0x40004C00</baseAddress>
      <addressBlock>
        <offset>0x0</offset>
        <size>0x400</size>
        <usage>registers</usage>
      </addressBlock>
      <interrupt>
        <name>UART1</name>
        <description>UART1 global Interrupt</description>
        <value>52</value>
      </interrupt>
      <registers>
        <register>
          <name>DR</name>
          <addressOffset>0x0</addressOffset>
          <fields>
            <field>
              <name>DR</name>
              <description>Receive/send data register</description>
              <bitRange>[8:0]</bitRange>
            </field>
          </fields>
        </register>
        <register>
          <name>BRR</name>
          <addressOffset>0x4</addressOffset>
          <fields>
            <field>
              <name>BRR</name>
              <description>Baud rate register</description>
              <bitRange>[15:0]</bitRange>
            </field>
          </fields>
        </register>
        <register>
          <name>SR</name>
          <addressOffset>0x10</addressOffset>
          <fields>
            <field>
              <name>RXNE</name>
              <description>Receive register not empty</description>
              <bitRange>[0:0]</bitRange>
              <access>read-only</access>
            </field>
            <field>
              <name>ORE</name>
              <description>Overrun error bit</description>
              <bitRange>[1:1]</bitRange>
            </field>
            <field>
              <name>PE</name>
              <description>Parity Error bit</description>
              <bitRange>[2:2]</bitRange>
            </field>
            <field>
              <name>FE</name>
              <description>Framing Error bit</description>
              <bitRange>[3:3]</bitRange>
            </field>
            <field>
              <name>BRI</name>
              <description>Break Interrupt bit</description>
              <bitRange>[4:4]</bitRange>
            </field>
            <field>
              <name>TDRE</name>
              <description>Transmit Holding Register Empty bit</description>
              <bitRange>[5:5]</bitRange>
              <access>read-only</access>
            </field>
            <field>
              <name>TXE</name>
              <description>Transmitter Empty bit</description>
              <bitRange>[6:6]</bitRange>
              <access>read-only</access>
            </field>
            <field>
              <name>ADDR_RCVD</name>
              <description>Address Received Bit</description>
              <bitRange>[8:8]</bitRange>
            </field>
            <field>
              <name>BUSY</name>
              <description>UART Busy</description>
              <bitRange>[9:9]</bitRange>
              <access>read-only</access>
            </field>
            <field>
              <name>BUSY_ERR</name>
              <description>Busy Detect Error</description>
              <bitRange>[10:10]</bitRange>
            </field>
          </fields>
        </register>
        <register>
          <name>CR1</name>
          <addressOffset>0x14</addressOffset>
          <fields>
            <field>
              <name>M</name>
              <description>Data Length Select</description>
              <bitRange>[1:0]</bitRange>
            </field>
            <field>
              <name>STOP</name>
              <description>Number of stop bits</description>
              <bitRange>[2:2]</bitRange>
            </field>
            <field>
              <name>PCE</name>
              <description>Parity Enable</description>
              <bitRange>[3:3]</bitRange>
            </field>
            <field>
              <name>PS</name>
              <description>Even Parity Select</description>
              <bitRange>[4:4]</bitRange>
            </field>
            <field>
              <name>SP</name>
              <description>Stick Parity</description>
              <bitRange>[5:5]</bitRange>
            </field>
            <field>
              <name>SBK</name>
              <description>Send Break</description>
              <bitRange>[6:6]</bitRange>
            </field>
            <field>
              <name>SWAP</name>
              <description>TX/RX pin swap</description>
              <bitRange>[8:8]</bitRange>
            </field>
            <field>
              <name>MSBFIRST</name>
              <description>MSB first mode</description>
              <bitRange>[9:9]</bitRange>
            </field>
          </fields>
        </register>
        <register>
          <name>CR2</name>
          <addressOffset>0x18</addressOffset>
          <fields>
            <field>
              <name>RXNEIE</name>
              <description>Enable Received Data Available Interrupt</description>
              <bitRange>[0:0]</bitRange>
            </field>
            <field>
              <name>TDREIE</name>
              <description>Enable Transmit Holding Register Empty Interrupt</description>
              <bitRange>[1:1]</bitRange>
            </field>
            <field>
              <name>LSIE</name>
              <description>Enable Receiver Line Status Interrupt</description>
              <bitRange>[2:2]</bitRange>
            </field>
            <field>
              <name>BUSYERRIE</name>
              <description>Enable Busyerr state interruption</description>
              <bitRange>[3:3]</bitRange>
            </field>
          </fields>
        </register>
        <register>
          <name>CR3</name>
          <addressOffset>0x1C</addressOffset>
          <fields>
            <field>
              <name>M_E</name>
              <description>Extension for DLS</description>
              <bitRange>[0:0]</bitRange>
            </field>
            <field>
              <name>ADDR_MATCH</name>
              <description>Address Match Mode</description>
              <bitRange>[1:1]</bitRange>
            </field>
            <field>
              <name>SEND_ADDR</name>
              <description>Send address control bit</description>
              <bitRange>[2:2]</bitRange>
            </field>
            <field>
              <name>TX_MODE</name>
              <description>Transmit mode control bit</description>
              <bitRange>[3:3]</bitRange>
            </field>
            <field>
              <name>DMAR</name>
              <description>DMA receive enable</description>
              <bitRange>[4:4]</bitRange>
            </field>
            <field>
              <name>DMAT</name>
              <description>DMA transmit enable</description>
              <bitRange>[5:5]</bitRange>
            </field>
            <field>
              <name>DMA_SOFT_ACK</name>
              <description>DMA software ack</description>
              <bitRange>[6:6]</bitRange>
            </field>
          </fields>
        </register>
        <register>
          <name>RAR</name>
          <addressOffset>0x20</addressOffset>
          <fields>
            <field>
              <name>RAR</name>
              <description>Receive address matching register</description>
              <bitRange>[7:0]</bitRange>
            </field>
          </fields>
        </register>
        <register>
          <name>TAR</name>
          <addressOffset>0x24</addressOffset>
          <fields>
            <field>
              <name>TAR</name>
              <description>Transmit address matching register</description>
              <bitRange>[7:0]</bitRange>
            </field>
          </fields>
        </register>
        <register>
          <name>BRRF</name>
          <addressOffset>0x28</addressOffset>
          <fields>
            <field>
              <name>BRRF</name>
              <description>Baud rate fractional register</description>
              <bitRange>[3:0]</bitRange>
            </field>
          </fields>
        </register>
      </registers>
    </peripheral>
    <peripheral derivedFrom="UART1">
      <name>UART2</name>
      <baseAddress>0x40005000</baseAddress>
      <interrupt>
        <name>UART2</name>
        <description>UART2 global Interrupt</description>
        <value>77</value>
      </interrupt>
    </peripheral>
    <peripheral derivedFrom="UART1">
      <name>UART3</name>
      <baseAddress>0x40005C00</baseAddress>
      <interrupt>
        <name>UART3</name>
        <description>UART3 global Interrupt</description>
        <value>78</value>
      </interrupt>
    </peripheral>
    <peripheral>
      <name>USART1</name>
      <groupName>USART</groupName>
      <baseAddress>0x40013800</baseAddress>
      <addressBlock>
        <offset>0x0</offset>
        <size>0x400</size>
        <usage>registers</usage>
      </addressBlock>
      <interrupt>
        <name>USART1</name>
        <description>USART1 global Interrupt</description>
        <value>37</value>
      </interrupt>
      <registers>
        <register>
          <name>SR</name>
          <addressOffset>0x0</addressOffset>
          <fields>
            <field>
              <name>PE</name>
              <description>Parity error</description>
              <bitRange>[0:0]</bitRange>
              <access>read-only</access>
            </field>
            <field>
              <name>FE</name>
              <description>Framing error</description>
              <bitRange>[1:1]</bitRange>
              <access>read-only</access>
            </field>
            <field>
              <name>NE</name>
              <description>Noise error flag</description>
              <bitRange>[2:2]</bitRange>
              <access>read-only</access>
            </field>
            <field>
              <name>ORE</name>
              <description>overrun error</description>
              <bitRange>[3:3]</bitRange>
              <access>read-only</access>
            </field>
            <field>
              <name>IDLE</name>
              <description>idle</description>
              <bitRange>[4:4]</bitRange>
              <access>read-only</access>
            </field>
            <field>
              <name>RXNE_RXFNF</name>
              <description>Read data register not empty</description>
              <bitRange>[5:5]</bitRange>
              <access>read-only</access>
            </field>
            <field>
              <name>TC</name>
              <description>Transmission complete</description>
              <bitRange>[6:6]</bitRange>
              <access>read-only</access>
            </field>
            <field>
              <name>TXE_TXFNF</name>
              <description>Transmit data register empty</description>
              <bitRange>[7:7]</bitRange>
              <access>read-only</access>
            </field>
            <field>
              <name>LBD</name>
              <description>LIN break detection flag</description>
              <bitRange>[8:8]</bitRange>
            </field>
            <field>
              <name>CTS</name>
              <description>cts flag</description>
              <bitRange>[9:9]</bitRange>
            </field>
            <field>
              <name>ABRF</name>
              <description>auto baud rate flag</description>
              <bitRange>[10:10]</bitRange>
              <access>read-only</access>
            </field>
            <field>
              <name>ABRE</name>
              <description>auto baud rateerror</description>
              <bitRange>[11:11]</bitRange>
              <access>read-only</access>
            </field>
            <field>
              <name>ABRQ</name>
              <description>auto baud rate req</description>
              <bitRange>[12:12]</bitRange>
              <access>read-only</access>
            </field>
            <field>
              <name>TXFT</name>
              <description>txfifo threshold flag</description>
              <bitRange>[13:13]</bitRange>
              <access>read-only</access>
            </field>
            <field>
              <name>RXFT</name>
              <description>rxfifo threshoold flag</description>
              <bitRange>[14:14]</bitRange>
              <access>read-only</access>
            </field>
            <field>
              <name>RXFF</name>
              <description>rxfifo full</description>
              <bitRange>[15:15]</bitRange>
              <access>read-only</access>
            </field>
            <field>
              <name>TXFE</name>
              <description>txfifo empty</description>
              <bitRange>[16:16]</bitRange>
              <access>read-only</access>
            </field>
            <field>
              <name>EOBF</name>
              <description>end of block flag</description>
              <bitRange>[18:18]</bitRange>
            </field>
            <field>
              <name>RTOF</name>
              <description>rto flag</description>
              <bitRange>[19:19]</bitRange>
            </field>
          <field><name>ABRRQ</name><description>ABRRQ</description><bitRange>[12:12]</bitRange><access>read-write</access></field></fields>
        </register>
        <register>
          <name>TDR</name>
          <addressOffset>0x4</addressOffset>
          <fields>
            <field>
              <name>TDR</name>
              <description>tdr</description>
              <bitRange>[8:0]</bitRange>
            </field>
          </fields>
        </register>
        <register>
          <name>BRR</name>
          <addressOffset>0x8</addressOffset>
          <fields>
            <field>
              <name>DIV_F</name>
              <description>DIV_Fraction</description>
              <bitRange>[3:0]</bitRange>
            </field>
            <field>
              <name>DIV_M</name>
              <description>DIV_Mantissa</description>
              <bitRange>[15:4]</bitRange>
            </field>
          </fields>
        </register>
        <register>
          <name>CR1</name>
          <addressOffset>0xC</addressOffset>
          <fields>
            <field>
              <name>SBK</name>
              <description>Send break</description>
              <bitRange>[0:0]</bitRange>
            </field>
            <field>
              <name>RWU</name>
              <description>Receiver wakeup</description>
              <bitRange>[1:1]</bitRange>
              <access>read-only</access>
            </field>
            <field>
              <name>RE</name>
              <description>Receiver enable</description>
              <bitRange>[2:2]</bitRange>
            </field>
            <field>
              <name>TE</name>
              <description>Transmitter enable</description>
              <bitRange>[3:3]</bitRange>
            </field>
            <field>
              <name>IDLEIE</name>
              <description>IDLE interrupt enable</description>
              <bitRange>[4:4]</bitRange>
            </field>
            <field>
              <name>RXNEIE</name>
              <description>RXNE interrupt enable</description>
              <bitRange>[5:5]</bitRange>
            </field>
            <field>
              <name>TCIE</name>
              <description>send complete int enable</description>
              <bitRange>[6:6]</bitRange>
            </field>
            <field>
              <name>TXEIE</name>
              <description>txe</description>
              <bitRange>[7:7]</bitRange>
            </field>
            <field>
              <name>PEIE</name>
              <description>PE interrupt enable</description>
              <bitRange>[8:8]</bitRange>
            </field>
            <field>
              <name>PS</name>
              <description>Parity selection</description>
              <bitRange>[9:9]</bitRange>
            </field>
            <field>
              <name>PCE</name>
              <description>Parity control enable</description>
              <bitRange>[10:10]</bitRange>
            </field>
            <field>
              <name>WAKE</name>
              <description>Wakeup method</description>
              <bitRange>[11:11]</bitRange>
            </field>
            <field>
              <name>M0</name>
              <description>word length</description>
              <bitRange>[12:12]</bitRange>
            </field>
            <field>
              <name>UE</name>
              <description>uesart enable</description>
              <bitRange>[13:13]</bitRange>
            </field>
            <field>
              <name>M1</name>
              <description>word length</description>
              <bitRange>[14:14]</bitRange>
            </field>
            <field>
              <name>MSB</name>
              <description>msb</description>
              <bitRange>[15:15]</bitRange>
            </field>
            <field>
              <name>MMRQ</name>
              <description>mm request</description>
              <bitRange>[16:16]</bitRange>
            </field>
            <field>
              <name>ADDM7</name>
              <description>addm7</description>
              <bitRange>[17:17]</bitRange>
            </field>
            <field>
              <name>SWAP</name>
              <description>swap</description>
              <bitRange>[18:18]</bitRange>
            </field>
            <field>
              <name>TXFTCFG</name>
              <description>txfifo threshoold cfg</description>
              <bitRange>[21:19]</bitRange>
            </field>
            <field>
              <name>RXFTCFG</name>
              <description>rxfifo threshoold cfg</description>
              <bitRange>[24:22]</bitRange>
            </field>
            <field>
              <name>RX_INV</name>
              <description>rxinv</description>
              <bitRange>[25:25]</bitRange>
            </field>
            <field>
              <name>TX_INV</name>
              <description>txinv</description>
              <bitRange>[26:26]</bitRange>
            </field>
            <field>
              <name>DATAINV</name>
              <description>datainv</description>
              <bitRange>[27:27]</bitRange>
            </field>
            <field>
              <name>RXFRQ</name>
              <description>receive data flush request</description>
              <bitRange>[29:29]</bitRange>
            </field>
            <field>
              <name>TXFRQ</name>
              <description>Transmit data flush request</description>
              <bitRange>[30:30]</bitRange>
            </field>
            <field>
              <name>FIFOEN</name>
              <description>fifo en</description>
              <bitRange>[31:31]</bitRange>
            </field>
          </fields>
        </register>
        <register>
          <name>CR2</name>
          <addressOffset>0x10</addressOffset>
          <fields>
            <field>
              <name>LBDL</name>
              <description>LIN break detection length</description>
              <bitRange>[5:5]</bitRange>
            </field>
            <field>
              <name>LBDIE</name>
              <description>lin break enable</description>
              <bitRange>[6:6]</bitRange>
            </field>
            <field>
              <name>LBCL</name>
              <description>lbcl</description>
              <bitRange>[8:8]</bitRange>
            </field>
            <field>
              <name>CPHA</name>
              <description>cpha</description>
              <bitRange>[9:9]</bitRange>
            </field>
            <field>
              <name>CPOL</name>
              <description>cpol</description>
              <bitRange>[10:10]</bitRange>
            </field>
            <field>
              <name>CLKEN</name>
              <description>clk en</description>
              <bitRange>[11:11]</bitRange>
            </field>
            <field>
              <name>STOP</name>
              <description>stop bit</description>
              <bitRange>[13:12]</bitRange>
            </field>
            <field>
              <name>LINEN</name>
              <description>lin enable</description>
              <bitRange>[14:14]</bitRange>
            </field>
            <field>
              <name>ADD</name>
              <description>address</description>
              <bitRange>[22:15]</bitRange>
            </field>
            <field>
              <name>DEM</name>
              <description>dem</description>
              <bitRange>[23:23]</bitRange>
            </field>
            <field>
              <name>DEP</name>
              <description>dep</description>
              <bitRange>[24:24]</bitRange>
            </field>
          <field><name>RTOEN</name><description>RTOEN</description><bitRange>[25:25]</bitRange><access>read-write</access></field></fields>
        </register>
        <register>
          <name>CR3</name>
          <addressOffset>0x14</addressOffset>
          <fields>
            <field>
              <name>EIE</name>
              <description>error int enable</description>
              <bitRange>[0:0]</bitRange>
            </field>
            <field>
              <name>IREN</name>
              <description>iren enable</description>
              <bitRange>[1:1]</bitRange>
            </field>
            <field>
              <name>IRLP</name>
              <description>idra lowpower</description>
              <bitRange>[2:2]</bitRange>
            </field>
            <field>
              <name>HDSEL</name>
              <description>hdsel</description>
              <bitRange>[3:3]</bitRange>
            </field>
            <field>
              <name>NACK</name>
              <description>scen nack enable</description>
              <bitRange>[4:4]</bitRange>
            </field>
            <field>
              <name>SCEN</name>
              <description>scen enable</description>
              <bitRange>[5:5]</bitRange>
            </field>
            <field>
              <name>DMAR</name>
              <description>dma rx enable</description>
              <bitRange>[6:6]</bitRange>
            </field>
            <field>
              <name>DMAT</name>
              <description>dma tx enable</description>
              <bitRange>[7:7]</bitRange>
            </field>
            <field>
              <name>RTSE</name>
              <description>rts enable</description>
              <bitRange>[8:8]</bitRange>
            </field>
            <field>
              <name>CTSE</name>
              <description>cts enable</description>
              <bitRange>[9:9]</bitRange>
            </field>
            <field>
              <name>CTSIE</name>
              <description>cts int enable</description>
              <bitRange>[10:10]</bitRange>
            </field>
            <field>
              <name>OVER8</name>
              <description>oversampling</description>
              <bitRange>[11:11]</bitRange>
            </field>
            <field>
              <name>ABREN</name>
              <description>autobaud enable</description>
              <bitRange>[12:12]</bitRange>
            </field>
            <field>
              <name>ABRMOD</name>
              <description>auto baud mod</description>
              <bitRange>[14:13]</bitRange>
            </field>
            <field>
              <name>RXFFIE</name>
              <description>rxff int enable</description>
              <bitRange>[15:15]</bitRange>
            </field>
            <field>
              <name>TXFEIE</name>
              <description>txfe int enable</description>
              <bitRange>[16:16]</bitRange>
            </field>
            <field>
              <name>RXFTIE</name>
              <description>rxft int enable</description>
              <bitRange>[17:17]</bitRange>
            </field>
            <field>
              <name>TXFTIE</name>
              <description>txft int enable</description>
              <bitRange>[18:18]</bitRange>
            </field>
            <field>
              <name>DEDT</name>
              <description>dedt int enable</description>
              <bitRange>[23:19]</bitRange>
            </field>
            <field>
              <name>DEAT</name>
              <description>deat int enable</description>
              <bitRange>[28:24]</bitRange>
            </field>
            <field>
              <name>RTOIE</name>
              <description>rto int enable</description>
              <bitRange>[29:29]</bitRange>
            </field>
            <field>
              <name>EOBIE</name>
              <description>eob int enable</description>
              <bitRange>[30:30]</bitRange>
            </field>
          </fields>
        </register>
        <register>
          <name>GTPR</name>
          <addressOffset>0x18</addressOffset>
          <fields>
            <field>
              <name>PSC</name>
              <description>Prescaler value</description>
              <bitRange>[7:0]</bitRange>
            </field>
            <field>
              <name>GT</name>
              <description>Guard time value</description>
              <bitRange>[15:8]</bitRange>
            </field>
          </fields>
        </register>
        <register>
          <name>RTOR</name>
          <addressOffset>0x1C</addressOffset>
          <fields>
            <field>
              <name>RTO</name>
              <description>receive timeout</description>
              <bitRange>[23:0]</bitRange>
            </field>
            <field>
              <name>BLEN</name>
              <description>blocken length</description>
              <bitRange>[31:24]</bitRange>
            </field>
          </fields>
        </register>
        <register>
          <name>RDR</name>
          <addressOffset>0x20</addressOffset>
          <fields>
            <field>
              <name>RDR</name>
              <description>rdr</description>
              <bitRange>[8:0]</bitRange>
            </field>
          </fields>
        </register>
      </registers>
    </peripheral>
    <peripheral derivedFrom="USART1">
      <name>USART2</name>
      <baseAddress>0x40004400</baseAddress>
      <interrupt>
        <name>USART2</name>
        <description>USART2 global Interrupt</description>
        <value>38</value>
      </interrupt>
    </peripheral>
    <peripheral derivedFrom="USART1">
      <name>USART3</name>
      <baseAddress>0x40004800</baseAddress>
      <interrupt>
        <name>USART3</name>
        <description>USART3 global Interrupt</description>
        <value>39</value>
      </interrupt>
    </peripheral>
    <peripheral>
      <name>USB1_OTG_DEVICE</name>
      <description>USB on the go full speed</description>
      <baseAddress>0x48040800</baseAddress>
      <addressBlock>
        <offset>0x0</offset>
        <size>0x400</size>
        <usage>registers</usage>
      </addressBlock>
      <registers>
        <register>
          <name>FS_DCFG</name>
          <description>OTG_FS device configuration register (OTG_FS_DCFG)</description>
          <addressOffset>0x0</addressOffset>
          <fields>
            <field>
              <name>DSPD</name>
              <description>Device speed</description>
              <bitRange>[1:0]</bitRange>
            </field>
            <field>
              <name>NZLSOHSK</name>
              <description>Non-zero-length status OUT handshake</description>
              <bitRange>[2:2]</bitRange>
            </field>
            <field>
              <name>DAD</name>
              <description>Device address</description>
              <bitRange>[10:4]</bitRange>
            </field>
            <field>
              <name>PFIVL</name>
              <description>Periodic frame interval</description>
              <bitRange>[12:11]</bitRange>
            </field>
          </fields>
        </register>
        <register>
          <name>FS_DCTL</name>
          <description>OTG_FS device control register (OTG_FS_DCTL)</description>
          <addressOffset>0x4</addressOffset>
          <fields>
            <field>
              <name>RWUSIG</name>
              <description>Remote wakeup signaling</description>
              <bitRange>[0:0]</bitRange>
            </field>
            <field>
              <name>SDIS</name>
              <description>Soft disconnect</description>
              <bitRange>[1:1]</bitRange>
            </field>
            <field>
              <name>GINSTS</name>
              <description>Global IN NAK status</description>
              <bitRange>[2:2]</bitRange>
              <access>read-only</access>
            </field>
            <field>
              <name>GONSTS</name>
              <description>Global OUT NAK status</description>
              <bitRange>[3:3]</bitRange>
              <access>read-only</access>
            </field>
            <field>
              <name>TCTL</name>
              <description>Test control</description>
              <bitRange>[6:4]</bitRange>
            </field>
            <field>
              <name>SGINAK</name>
              <description>Set global IN NAK</description>
              <bitRange>[7:7]</bitRange>
            </field>
            <field>
              <name>CGINAK</name>
              <description>Clear global IN NAK</description>
              <bitRange>[8:8]</bitRange>
            </field>
            <field>
              <name>SGONAK</name>
              <description>Set global OUT NAK</description>
              <bitRange>[9:9]</bitRange>
            </field>
            <field>
              <name>CGONAK</name>
              <description>Clear global OUT NAK</description>
              <bitRange>[10:10]</bitRange>
            </field>
            <field>
              <name>POPRGDNE</name>
              <description>Power-on programming done</description>
              <bitRange>[11:11]</bitRange>
            </field>
          </fields>
        </register>
        <register>
          <name>FS_DSTS</name>
          <description>OTG_FS device status register (OTG_FS_DSTS)</description>
          <addressOffset>0x8</addressOffset>
          <fields>
            <field>
              <name>SUSPSTS</name>
              <description>Suspend status</description>
              <bitRange>[0:0]</bitRange>
              <access>read-only</access>
            </field>
            <field>
              <name>ENUMSPD</name>
              <description>Enumerated speed</description>
              <bitRange>[2:1]</bitRange>
              <access>read-only</access>
            </field>
            <field>
              <name>EERR</name>
              <description>Erratic error</description>
              <bitRange>[3:3]</bitRange>
              <access>read-only</access>
            </field>
            <field>
              <name>FNSOF</name>
              <description>Frame number of the received SOF</description>
              <bitRange>[21:8]</bitRange>
              <access>read-only</access>
            </field>
          </fields>
        </register>
        <register>
          <name>FS_DIEPMSK</name>
          <description>OTG_FS device IN endpoint common interrupt mask register (OTG_FS_DIEPMSK)</description>
          <addressOffset>0x10</addressOffset>
          <fields>
            <field>
              <name>XFRCM</name>
              <description>Transfer completed interrupt mask</description>
              <bitRange>[0:0]</bitRange>
            </field>
            <field>
              <name>EPDM</name>
              <description>Endpoint disabled interrupt mask</description>
              <bitRange>[1:1]</bitRange>
            </field>
            <field>
              <name>TOM</name>
              <description>Timeout condition mask (Non-isochronous endpoints)</description>
              <bitRange>[3:3]</bitRange>
            </field>
            <field>
              <name>ITTXFEMSK</name>
              <description>IN token received when TxFIFO empty mask</description>
              <bitRange>[4:4]</bitRange>
            </field>
            <field>
              <name>INEPNMM</name>
              <description>IN token received with EP mismatch mask</description>
              <bitRange>[5:5]</bitRange>
            </field>
            <field>
              <name>INEPNEM</name>
              <description>IN endpoint NAK effective mask</description>
              <bitRange>[6:6]</bitRange>
            </field>
          </fields>
        </register>
        <register>
          <name>FS_DOEPMSK</name>
          <description>OTG_FS device OUT endpoint common interrupt mask register (OTG_FS_DOEPMSK)</description>
          <addressOffset>0x14</addressOffset>
          <fields>
            <field>
              <name>XFRCM</name>
              <description>Transfer completed interrupt mask</description>
              <bitRange>[0:0]</bitRange>
            </field>
            <field>
              <name>EPDM</name>
              <description>Endpoint disabled interrupt mask</description>
              <bitRange>[1:1]</bitRange>
            </field>
            <field>
              <name>STUPM</name>
              <description>SETUP phase done mask</description>
              <bitRange>[3:3]</bitRange>
            </field>
            <field>
              <name>OTEPDM</name>
              <description>OUT token received when endpoint disabled mask</description>
              <bitRange>[4:4]</bitRange>
            </field>
          </fields>
        </register>
        <register>
          <name>FS_DAINT</name>
          <description>OTG_FS device all endpoints interrupt register (OTG_FS_DAINT)</description>
          <addressOffset>0x18</addressOffset>
          <fields>
            <field>
              <name>IEPINT</name>
              <description>IN endpoint interrupt bits</description>
              <bitRange>[15:0]</bitRange>
              <access>read-only</access>
            </field>
            <field>
              <name>OEPINT</name>
              <description>OUT endpoint interrupt bits</description>
              <bitRange>[31:16]</bitRange>
              <access>read-only</access>
            </field>
          </fields>
        </register>
        <register>
          <name>FS_DAINTMSK</name>
          <description>OTG_FS all endpoints interrupt mask register (OTG_FS_DAINTMSK)</description>
          <addressOffset>0x1C</addressOffset>
          <fields>
            <field>
              <name>IEPM</name>
              <description>IN EP interrupt mask bits</description>
              <bitRange>[15:0]</bitRange>
            </field>
            <field>
              <name>OEPINT</name>
              <description>OUT endpoint interrupt bits</description>
              <bitRange>[31:16]</bitRange>
            </field>
          </fields>
        </register>
        <register>
          <name>DVBUSDIS</name>
          <description>OTG_FS device VBUS discharge time register</description>
          <addressOffset>0x28</addressOffset>
          <fields>
            <field>
              <name>VBUSDT</name>
              <description>Device VBUS discharge time</description>
              <bitRange>[15:0]</bitRange>
            </field>
          </fields>
        </register>
        <register>
          <name>DVBUSPULSE</name>
          <description>OTG_FS device VBUS pulsing time register</description>
          <addressOffset>0x2C</addressOffset>
          <fields>
            <field>
              <name>DVBUSP</name>
              <description>Device VBUS pulsing time</description>
              <bitRange>[11:0]</bitRange>
            </field>
          </fields>
        </register>
        <register>
          <name>DIEPEMPMSK</name>
          <description>OTG_FS device IN endpoint FIFO empty interrupt mask register</description>
          <addressOffset>0x34</addressOffset>
          <fields>
            <field>
              <name>INEPTXFEM</name>
              <description>IN EP Tx FIFO empty interrupt mask bits</description>
              <bitRange>[15:0]</bitRange>
            </field>
          </fields>
        </register>
        <register>
          <name>FS_DIEPCTL0</name>
          <description>OTG_FS device control IN endpoint 0 control register (OTG_FS_DIEPCTL0)</description>
          <addressOffset>0x100</addressOffset>
          <fields>
            <field>
              <name>MPSIZ</name>
              <description>Maximum packet size</description>
              <bitRange>[1:0]</bitRange>
            </field>
            <field>
              <name>USBAEP</name>
              <description>USB active endpoint</description>
              <bitRange>[15:15]</bitRange>
              <access>read-only</access>
            </field>
            <field>
              <name>NAKSTS</name>
              <description>NAK status</description>
              <bitRange>[17:17]</bitRange>
              <access>read-only</access>
            </field>
            <field>
              <name>EPTYP</name>
              <description>Endpoint type</description>
              <bitRange>[19:18]</bitRange>
              <access>read-only</access>
            </field>
            <field>
              <name>STALL</name>
              <description>STALL handshake</description>
              <bitRange>[21:21]</bitRange>
            </field>
            <field>
              <name>TXFNUM</name>
              <description>TxFIFO number</description>
              <bitRange>[25:22]</bitRange>
            </field>
            <field>
              <name>CNAK</name>
              <description>Clear NAK</description>
              <bitRange>[26:26]</bitRange>
            </field>
            <field>
              <name>SNAK</name>
              <description>Set NAK</description>
              <bitRange>[27:27]</bitRange>
            </field>
            <field>
              <name>EPDIS</name>
              <description>Endpoint disable</description>
              <bitRange>[30:30]</bitRange>
              <access>read-only</access>
            </field>
            <field>
              <name>EPENA</name>
              <description>Endpoint enable</description>
              <bitRange>[31:31]</bitRange>
              <access>read-only</access>
            </field>
          </fields>
        </register>
        <register>
          <name>DIEPINT0</name>
          <description>device endpoint-x interrupt register</description>
          <addressOffset>0x108</addressOffset>
          <fields>
            <field>
              <name>XFRC</name>
              <description>XFRC</description>
              <bitRange>[0:0]</bitRange>
            </field>
            <field>
              <name>EPDISD</name>
              <description>EPDISD</description>
              <bitRange>[1:1]</bitRange>
            </field>
            <field>
              <name>TOC</name>
              <description>TOC</description>
              <bitRange>[3:3]</bitRange>
            </field>
            <field>
              <name>ITTXFE</name>
              <description>ITTXFE</description>
              <bitRange>[4:4]</bitRange>
            </field>
            <field>
              <name>INEPNE</name>
              <description>INEPNE</description>
              <bitRange>[6:6]</bitRange>
            </field>
            <field>
              <name>TXFE</name>
              <description>TXFE</description>
              <bitRange>[7:7]</bitRange>
              <access>read-only</access>
            </field>
          </fields>
        </register>
        <register>
          <name>DIEPTSIZ0</name>
          <description>device endpoint-0 transfer size register</description>
          <addressOffset>0x110</addressOffset>
          <fields>
            <field>
              <name>XFRSIZ</name>
              <description>Transfer size</description>
              <bitRange>[6:0]</bitRange>
            </field>
            <field>
              <name>PKTCNT</name>
              <description>Packet count</description>
              <bitRange>[20:19]</bitRange>
            </field>
          </fields>
        </register>
        <register>
          <name>DTXFSTS0</name>
          <description>OTG_FS device IN endpoint transmit FIFO status register</description>
          <addressOffset>0x118</addressOffset>
          <fields>
            <field>
              <name>INEPTFSAV</name>
              <description>IN endpoint TxFIFO space available</description>
              <bitRange>[15:0]</bitRange>
              <access>read-only</access>
            </field>
          </fields>
        </register>
        <register>
          <name>DIEPCTL1</name>
          <description>OTG device endpoint-1 control register</description>
          <addressOffset>0x120</addressOffset>
          <fields>
            <field>
              <name>MPSIZ</name>
              <description>MPSIZ</description>
              <bitRange>[10:0]</bitRange>
            </field>
            <field>
              <name>USBAEP</name>
              <description>USBAEP</description>
              <bitRange>[15:15]</bitRange>
            </field>
            <field>
              <name>EONUM_DPID</name>
              <description>EONUM/DPID</description>
              <bitRange>[16:16]</bitRange>
              <access>read-only</access>
            </field>
            <field>
              <name>NAKSTS</name>
              <description>NAKSTS</description>
              <bitRange>[17:17]</bitRange>
              <access>read-only</access>
            </field>
            <field>
              <name>EPTYP</name>
              <description>EPTYP</description>
              <bitRange>[19:18]</bitRange>
            </field>
            <field>
              <name>STALL</name>
              <description>Stall</description>
              <bitRange>[21:21]</bitRange>
            </field>
            <field>
              <name>TXFNUM</name>
              <description>TXFNUM</description>
              <bitRange>[25:22]</bitRange>
            </field>
            <field>
              <name>CNAK</name>
              <description>CNAK</description>
              <bitRange>[26:26]</bitRange>
            </field>
            <field>
              <name>SNAK</name>
              <description>SNAK</description>
              <bitRange>[27:27]</bitRange>
            </field>
            <field>
              <name>SD0PID_SEVNFRM</name>
              <description>SD0PID/SEVNFRM</description>
              <bitRange>[28:28]</bitRange>
            </field>
            <field>
              <name>SODDFRM_SD1PID</name>
              <description>SODDFRM/SD1PID</description>
              <bitRange>[29:29]</bitRange>
            </field>
            <field>
              <name>EPDIS</name>
              <description>EPDIS</description>
              <bitRange>[30:30]</bitRange>
            </field>
            <field>
              <name>EPENA</name>
              <description>EPENA</description>
              <bitRange>[31:31]</bitRange>
            </field>
          </fields>
        </register>
        <register>
          <name>DIEPINT1</name>
          <description>device endpoint-1 interrupt register</description>
          <addressOffset>0x128</addressOffset>
          <fields>
            <field>
              <name>XFRC</name>
              <description>XFRC</description>
              <bitRange>[0:0]</bitRange>
            </field>
            <field>
              <name>EPDISD</name>
              <description>EPDISD</description>
              <bitRange>[1:1]</bitRange>
            </field>
            <field>
              <name>TOC</name>
              <description>TOC</description>
              <bitRange>[3:3]</bitRange>
            </field>
            <field>
              <name>ITTXFE</name>
              <description>ITTXFE</description>
              <bitRange>[4:4]</bitRange>
            </field>
            <field>
              <name>INEPNE</name>
              <description>INEPNE</description>
              <bitRange>[6:6]</bitRange>
            </field>
            <field>
              <name>TXFE</name>
              <description>TXFE</description>
              <bitRange>[7:7]</bitRange>
              <access>read-only</access>
            </field>
          </fields>
        </register>
        <register>
          <name>DIEPTSIZ1</name>
          <description>device endpoint-1 transfer size register</description>
          <addressOffset>0x130</addressOffset>
          <fields>
            <field>
              <name>XFRSIZ</name>
              <description>Transfer size</description>
              <bitRange>[18:0]</bitRange>
            </field>
            <field>
              <name>PKTCNT</name>
              <description>Packet count</description>
              <bitRange>[28:19]</bitRange>
            </field>
            <field>
              <name>MCNT</name>
              <description>Multi count</description>
              <bitRange>[30:29]</bitRange>
            </field>
          </fields>
        </register>
        <register>
          <name>DTXFSTS1</name>
          <description>OTG_FS device IN endpoint transmit FIFO status register</description>
          <addressOffset>0x138</addressOffset>
          <fields>
            <field>
              <name>INEPTFSAV</name>
              <description>IN endpoint TxFIFO space available</description>
              <bitRange>[15:0]</bitRange>
              <access>read-only</access>
            </field>
          </fields>
        </register>
        <register>
          <name>DIEPCTL2</name>
          <description>OTG device endpoint-2 control register</description>
          <addressOffset>0x140</addressOffset>
          <fields>
            <field>
              <name>MPSIZ</name>
              <description>MPSIZ</description>
              <bitRange>[10:0]</bitRange>
            </field>
            <field>
              <name>USBAEP</name>
              <description>USBAEP</description>
              <bitRange>[15:15]</bitRange>
            </field>
            <field>
              <name>EONUM_DPID</name>
              <description>EONUM/DPID</description>
              <bitRange>[16:16]</bitRange>
              <access>read-only</access>
            </field>
            <field>
              <name>NAKSTS</name>
              <description>NAKSTS</description>
              <bitRange>[17:17]</bitRange>
              <access>read-only</access>
            </field>
            <field>
              <name>EPTYP</name>
              <description>EPTYP</description>
              <bitRange>[19:18]</bitRange>
            </field>
            <field>
              <name>STALL</name>
              <description>Stall</description>
              <bitRange>[21:21]</bitRange>
            </field>
            <field>
              <name>TXFNUM</name>
              <description>TXFNUM</description>
              <bitRange>[25:22]</bitRange>
            </field>
            <field>
              <name>CNAK</name>
              <description>CNAK</description>
              <bitRange>[26:26]</bitRange>
            </field>
            <field>
              <name>SNAK</name>
              <description>SNAK</description>
              <bitRange>[27:27]</bitRange>
            </field>
            <field>
              <name>SD0PID_SEVNFRM</name>
              <description>SD0PID/SEVNFRM</description>
              <bitRange>[28:28]</bitRange>
            </field>
            <field>
              <name>SODDFRM</name>
              <description>SODDFRM</description>
              <bitRange>[29:29]</bitRange>
            </field>
            <field>
              <name>EPDIS</name>
              <description>EPDIS</description>
              <bitRange>[30:30]</bitRange>
            </field>
            <field>
              <name>EPENA</name>
              <description>EPENA</description>
              <bitRange>[31:31]</bitRange>
            </field>
          </fields>
        </register>
        <register>
          <name>DIEPINT2</name>
          <description>device endpoint-2 interrupt register</description>
          <addressOffset>0x148</addressOffset>
          <fields>
            <field>
              <name>XFRC</name>
              <description>XFRC</description>
              <bitRange>[0:0]</bitRange>
            </field>
            <field>
              <name>EPDISD</name>
              <description>EPDISD</description>
              <bitRange>[1:1]</bitRange>
            </field>
            <field>
              <name>TOC</name>
              <description>TOC</description>
              <bitRange>[3:3]</bitRange>
            </field>
            <field>
              <name>ITTXFE</name>
              <description>ITTXFE</description>
              <bitRange>[4:4]</bitRange>
            </field>
            <field>
              <name>INEPNE</name>
              <description>INEPNE</description>
              <bitRange>[6:6]</bitRange>
            </field>
            <field>
              <name>TXFE</name>
              <description>TXFE</description>
              <bitRange>[7:7]</bitRange>
              <access>read-only</access>
            </field>
          </fields>
        </register>
        <register>
          <name>DIEPTSIZ2</name>
          <description>device endpoint-2 transfer size register</description>
          <addressOffset>0x150</addressOffset>
          <fields>
            <field>
              <name>XFRSIZ</name>
              <description>Transfer size</description>
              <bitRange>[18:0]</bitRange>
            </field>
            <field>
              <name>PKTCNT</name>
              <description>Packet count</description>
              <bitRange>[28:19]</bitRange>
            </field>
            <field>
              <name>MCNT</name>
              <description>Multi count</description>
              <bitRange>[30:29]</bitRange>
            </field>
          </fields>
        </register>
        <register>
          <name>DTXFSTS2</name>
          <description>OTG_FS device IN endpoint transmit FIFO status register</description>
          <addressOffset>0x158</addressOffset>
          <fields>
            <field>
              <name>INEPTFSAV</name>
              <description>IN endpoint TxFIFO space available</description>
              <bitRange>[15:0]</bitRange>
              <access>read-only</access>
            </field>
          </fields>
        </register>
        <register>
          <name>DIEPCTL3</name>
          <description>OTG device endpoint-3 control register</description>
          <addressOffset>0x160</addressOffset>
          <fields>
            <field>
              <name>MPSIZ</name>
              <description>MPSIZ</description>
              <bitRange>[10:0]</bitRange>
            </field>
            <field>
              <name>USBAEP</name>
              <description>USBAEP</description>
              <bitRange>[15:15]</bitRange>
            </field>
            <field>
              <name>EONUM_DPID</name>
              <description>EONUM/DPID</description>
              <bitRange>[16:16]</bitRange>
              <access>read-only</access>
            </field>
            <field>
              <name>NAKSTS</name>
              <description>NAKSTS</description>
              <bitRange>[17:17]</bitRange>
              <access>read-only</access>
            </field>
            <field>
              <name>EPTYP</name>
              <description>EPTYP</description>
              <bitRange>[19:18]</bitRange>
            </field>
            <field>
              <name>STALL</name>
              <description>Stall</description>
              <bitRange>[21:21]</bitRange>
            </field>
            <field>
              <name>TXFNUM</name>
              <description>TXFNUM</description>
              <bitRange>[25:22]</bitRange>
            </field>
            <field>
              <name>CNAK</name>
              <description>CNAK</description>
              <bitRange>[26:26]</bitRange>
            </field>
            <field>
              <name>SNAK</name>
              <description>SNAK</description>
              <bitRange>[27:27]</bitRange>
            </field>
            <field>
              <name>SD0PID_SEVNFRM</name>
              <description>SD0PID/SEVNFRM</description>
              <bitRange>[28:28]</bitRange>
            </field>
            <field>
              <name>SODDFRM</name>
              <description>SODDFRM</description>
              <bitRange>[29:29]</bitRange>
            </field>
            <field>
              <name>EPDIS</name>
              <description>EPDIS</description>
              <bitRange>[30:30]</bitRange>
            </field>
            <field>
              <name>EPENA</name>
              <description>EPENA</description>
              <bitRange>[31:31]</bitRange>
            </field>
          </fields>
        </register>
        <register>
          <name>DIEPINT3</name>
          <description>device endpoint-3 interrupt register</description>
          <addressOffset>0x168</addressOffset>
          <fields>
            <field>
              <name>XFRC</name>
              <description>XFRC</description>
              <bitRange>[0:0]</bitRange>
            </field>
            <field>
              <name>EPDISD</name>
              <description>EPDISD</description>
              <bitRange>[1:1]</bitRange>
            </field>
            <field>
              <name>TOC</name>
              <description>TOC</description>
              <bitRange>[3:3]</bitRange>
            </field>
            <field>
              <name>ITTXFE</name>
              <description>ITTXFE</description>
              <bitRange>[4:4]</bitRange>
            </field>
            <field>
              <name>INEPNE</name>
              <description>INEPNE</description>
              <bitRange>[6:6]</bitRange>
            </field>
            <field>
              <name>TXFE</name>
              <description>TXFE</description>
              <bitRange>[7:7]</bitRange>
              <access>read-only</access>
            </field>
          </fields>
        </register>
        <register>
          <name>DIEPTSIZ3</name>
          <description>device endpoint-3 transfer size register</description>
          <addressOffset>0x170</addressOffset>
          <fields>
            <field>
              <name>XFRSIZ</name>
              <description>Transfer size</description>
              <bitRange>[18:0]</bitRange>
            </field>
            <field>
              <name>PKTCNT</name>
              <description>Packet count</description>
              <bitRange>[28:19]</bitRange>
            </field>
            <field>
              <name>MCNT</name>
              <description>Multi count</description>
              <bitRange>[30:29]</bitRange>
            </field>
          </fields>
        </register>
        <register>
          <name>DTXFSTS3</name>
          <description>OTG_FS device IN endpoint transmit FIFO status register</description>
          <addressOffset>0x178</addressOffset>
          <fields>
            <field>
              <name>INEPTFSAV</name>
              <description>IN endpoint TxFIFO space available</description>
              <bitRange>[15:0]</bitRange>
              <access>read-only</access>
            </field>
          </fields>
        </register>
        <register>
          <name>DOEPCTL0</name>
          <description>device endpoint-0 control register</description>
          <addressOffset>0x300</addressOffset>
          <fields>
            <field>
              <name>MPSIZ</name>
              <description>MPSIZ</description>
              <bitRange>[1:0]</bitRange>
              <access>read-only</access>
            </field>
            <field>
              <name>USBAEP</name>
              <description>USBAEP</description>
              <bitRange>[15:15]</bitRange>
              <access>read-only</access>
            </field>
            <field>
              <name>NAKSTS</name>
              <description>NAKSTS</description>
              <bitRange>[17:17]</bitRange>
              <access>read-only</access>
            </field>
            <field>
              <name>EPTYP</name>
              <description>EPTYP</description>
              <bitRange>[19:18]</bitRange>
              <access>read-only</access>
            </field>
            <field>
              <name>SNPM</name>
              <description>SNPM</description>
              <bitRange>[20:20]</bitRange>
            </field>
            <field>
              <name>STALL</name>
              <description>Stall</description>
              <bitRange>[21:21]</bitRange>
            </field>
            <field>
              <name>CNAK</name>
              <description>CNAK</description>
              <bitRange>[26:26]</bitRange>
            </field>
            <field>
              <name>SNAK</name>
              <description>SNAK</description>
              <bitRange>[27:27]</bitRange>
            </field>
            <field>
              <name>EPDIS</name>
              <description>EPDIS</description>
              <bitRange>[30:30]</bitRange>
              <access>read-only</access>
            </field>
            <field>
              <name>EPENA</name>
              <description>EPENA</description>
              <bitRange>[31:31]</bitRange>
            </field>
          </fields>
        </register>
        <register>
          <name>DOEPINT0</name>
          <description>device endpoint-0 interrupt register</description>
          <addressOffset>0x308</addressOffset>
          <fields>
            <field>
              <name>XFRC</name>
              <description>XFRC</description>
              <bitRange>[0:0]</bitRange>
            </field>
            <field>
              <name>EPDISD</name>
              <description>EPDISD</description>
              <bitRange>[1:1]</bitRange>
            </field>
            <field>
              <name>STUP</name>
              <description>STUP</description>
              <bitRange>[3:3]</bitRange>
            </field>
            <field>
              <name>OTEPDIS</name>
              <description>OTEPDIS</description>
              <bitRange>[4:4]</bitRange>
            </field>
            <field>
              <name>B2BSTUP</name>
              <description>B2BSTUP</description>
              <bitRange>[6:6]</bitRange>
            </field>
          </fields>
        </register>
        <register>
          <name>DOEPTSIZ0</name>
          <description>device OUT endpoint-0 transfer size register</description>
          <addressOffset>0x310</addressOffset>
          <fields>
            <field>
              <name>XFRSIZ</name>
              <description>Transfer size</description>
              <bitRange>[6:0]</bitRange>
            </field>
            <field>
              <name>PKTCNT</name>
              <description>Packet count</description>
              <bitRange>[19:19]</bitRange>
            </field>
            <field>
              <name>STUPCNT</name>
              <description>SETUP packet count</description>
              <bitRange>[30:29]</bitRange>
            </field>
          </fields>
        </register>
        <register>
          <name>DOEPCTL1</name>
          <description>device endpoint-1 control register</description>
          <addressOffset>0x320</addressOffset>
          <fields>
            <field>
              <name>MPSIZ</name>
              <description>MPSIZ</description>
              <bitRange>[10:0]</bitRange>
            </field>
            <field>
              <name>USBAEP</name>
              <description>USBAEP</description>
              <bitRange>[15:15]</bitRange>
            </field>
            <field>
              <name>EONUM_DPID</name>
              <description>EONUM/DPID</description>
              <bitRange>[16:16]</bitRange>
              <access>read-only</access>
            </field>
            <field>
              <name>NAKSTS</name>
              <description>NAKSTS</description>
              <bitRange>[17:17]</bitRange>
              <access>read-only</access>
            </field>
            <field>
              <name>EPTYP</name>
              <description>EPTYP</description>
              <bitRange>[19:18]</bitRange>
            </field>
            <field>
              <name>SNPM</name>
              <description>SNPM</description>
              <bitRange>[20:20]</bitRange>
            </field>
            <field>
              <name>STALL</name>
              <description>Stall</description>
              <bitRange>[21:21]</bitRange>
            </field>
            <field>
              <name>CNAK</name>
              <description>CNAK</description>
              <bitRange>[26:26]</bitRange>
            </field>
            <field>
              <name>SNAK</name>
              <description>SNAK</description>
              <bitRange>[27:27]</bitRange>
            </field>
            <field>
              <name>SD0PID_SEVNFRM</name>
              <description>SD0PID/SEVNFRM</description>
              <bitRange>[28:28]</bitRange>
            </field>
            <field>
              <name>SODDFRM</name>
              <description>SODDFRM</description>
              <bitRange>[29:29]</bitRange>
            </field>
            <field>
              <name>EPDIS</name>
              <description>EPDIS</description>
              <bitRange>[30:30]</bitRange>
            </field>
            <field>
              <name>EPENA</name>
              <description>EPENA</description>
              <bitRange>[31:31]</bitRange>
            </field>
          </fields>
        </register>
        <register>
          <name>DOEPINT1</name>
          <description>device endpoint-1 interrupt register</description>
          <addressOffset>0x328</addressOffset>
          <fields>
            <field>
              <name>XFRC</name>
              <description>XFRC</description>
              <bitRange>[0:0]</bitRange>
            </field>
            <field>
              <name>EPDISD</name>
              <description>EPDISD</description>
              <bitRange>[1:1]</bitRange>
            </field>
            <field>
              <name>STUP</name>
              <description>STUP</description>
              <bitRange>[3:3]</bitRange>
            </field>
            <field>
              <name>OTEPDIS</name>
              <description>OTEPDIS</description>
              <bitRange>[4:4]</bitRange>
            </field>
            <field>
              <name>B2BSTUP</name>
              <description>B2BSTUP</description>
              <bitRange>[6:6]</bitRange>
            </field>
          </fields>
        </register>
        <register>
          <name>DOEPTSIZ1</name>
          <description>device OUT endpoint-1 transfer size register</description>
          <addressOffset>0x330</addressOffset>
          <fields>
            <field>
              <name>XFRSIZ</name>
              <description>Transfer size</description>
              <bitRange>[18:0]</bitRange>
            </field>
            <field>
              <name>PKTCNT</name>
              <description>Packet count</description>
              <bitRange>[28:19]</bitRange>
            </field>
            <field>
              <name>RXDPID_STUPCNT</name>
              <description>Received data PID/SETUP packet count</description>
              <bitRange>[30:29]</bitRange>
            </field>
          </fields>
        </register>
        <register>
          <name>DOEPCTL2</name>
          <description>device endpoint-2 control register</description>
          <addressOffset>0x340</addressOffset>
          <fields>
            <field>
              <name>MPSIZ</name>
              <description>MPSIZ</description>
              <bitRange>[10:0]</bitRange>
            </field>
            <field>
              <name>USBAEP</name>
              <description>USBAEP</description>
              <bitRange>[15:15]</bitRange>
            </field>
            <field>
              <name>EONUM_DPID</name>
              <description>EONUM/DPID</description>
              <bitRange>[16:16]</bitRange>
              <access>read-only</access>
            </field>
            <field>
              <name>NAKSTS</name>
              <description>NAKSTS</description>
              <bitRange>[17:17]</bitRange>
              <access>read-only</access>
            </field>
            <field>
              <name>EPTYP</name>
              <description>EPTYP</description>
              <bitRange>[19:18]</bitRange>
            </field>
            <field>
              <name>SNPM</name>
              <description>SNPM</description>
              <bitRange>[20:20]</bitRange>
            </field>
            <field>
              <name>STALL</name>
              <description>Stall</description>
              <bitRange>[21:21]</bitRange>
            </field>
            <field>
              <name>CNAK</name>
              <description>CNAK</description>
              <bitRange>[26:26]</bitRange>
            </field>
            <field>
              <name>SNAK</name>
              <description>SNAK</description>
              <bitRange>[27:27]</bitRange>
            </field>
            <field>
              <name>SD0PID_SEVNFRM</name>
              <description>SD0PID/SEVNFRM</description>
              <bitRange>[28:28]</bitRange>
            </field>
            <field>
              <name>SODDFRM</name>
              <description>SODDFRM</description>
              <bitRange>[29:29]</bitRange>
            </field>
            <field>
              <name>EPDIS</name>
              <description>EPDIS</description>
              <bitRange>[30:30]</bitRange>
            </field>
            <field>
              <name>EPENA</name>
              <description>EPENA</description>
              <bitRange>[31:31]</bitRange>
            </field>
          </fields>
        </register>
        <register>
          <name>DOEPINT2</name>
          <description>device endpoint-2 interrupt register</description>
          <addressOffset>0x348</addressOffset>
          <fields>
            <field>
              <name>XFRC</name>
              <description>XFRC</description>
              <bitRange>[0:0]</bitRange>
            </field>
            <field>
              <name>EPDISD</name>
              <description>EPDISD</description>
              <bitRange>[1:1]</bitRange>
            </field>
            <field>
              <name>STUP</name>
              <description>STUP</description>
              <bitRange>[3:3]</bitRange>
            </field>
            <field>
              <name>OTEPDIS</name>
              <description>OTEPDIS</description>
              <bitRange>[4:4]</bitRange>
            </field>
            <field>
              <name>B2BSTUP</name>
              <description>B2BSTUP</description>
              <bitRange>[6:6]</bitRange>
            </field>
          </fields>
        </register>
        <register>
          <name>DOEPTSIZ2</name>
          <description>device OUT endpoint-2 transfer size register</description>
          <addressOffset>0x350</addressOffset>
          <fields>
            <field>
              <name>XFRSIZ</name>
              <description>Transfer size</description>
              <bitRange>[18:0]</bitRange>
            </field>
            <field>
              <name>PKTCNT</name>
              <description>Packet count</description>
              <bitRange>[28:19]</bitRange>
            </field>
            <field>
              <name>RXDPID_STUPCNT</name>
              <description>Received data PID/SETUP packet count</description>
              <bitRange>[30:29]</bitRange>
            </field>
          </fields>
        </register>
        <register>
          <name>DOEPCTL3</name>
          <description>device endpoint-3 control register</description>
          <addressOffset>0x360</addressOffset>
          <fields>
            <field>
              <name>MPSIZ</name>
              <description>MPSIZ</description>
              <bitRange>[10:0]</bitRange>
            </field>
            <field>
              <name>USBAEP</name>
              <description>USBAEP</description>
              <bitRange>[15:15]</bitRange>
            </field>
            <field>
              <name>EONUM_DPID</name>
              <description>EONUM/DPID</description>
              <bitRange>[16:16]</bitRange>
              <access>read-only</access>
            </field>
            <field>
              <name>NAKSTS</name>
              <description>NAKSTS</description>
              <bitRange>[17:17]</bitRange>
              <access>read-only</access>
            </field>
            <field>
              <name>EPTYP</name>
              <description>EPTYP</description>
              <bitRange>[19:18]</bitRange>
            </field>
            <field>
              <name>SNPM</name>
              <description>SNPM</description>
              <bitRange>[20:20]</bitRange>
            </field>
            <field>
              <name>STALL</name>
              <description>Stall</description>
              <bitRange>[21:21]</bitRange>
            </field>
            <field>
              <name>CNAK</name>
              <description>CNAK</description>
              <bitRange>[26:26]</bitRange>
            </field>
            <field>
              <name>SNAK</name>
              <description>SNAK</description>
              <bitRange>[27:27]</bitRange>
            </field>
            <field>
              <name>SD0PID_SEVNFRM</name>
              <description>SD0PID/SEVNFRM</description>
              <bitRange>[28:28]</bitRange>
            </field>
            <field>
              <name>SODDFRM</name>
              <description>SODDFRM</description>
              <bitRange>[29:29]</bitRange>
            </field>
            <field>
              <name>EPDIS</name>
              <description>EPDIS</description>
              <bitRange>[30:30]</bitRange>
            </field>
            <field>
              <name>EPENA</name>
              <description>EPENA</description>
              <bitRange>[31:31]</bitRange>
            </field>
          </fields>
        </register>
        <register>
          <name>DOEPINT3</name>
          <description>device endpoint-3 interrupt register</description>
          <addressOffset>0x368</addressOffset>
          <fields>
            <field>
              <name>XFRC</name>
              <description>XFRC</description>
              <bitRange>[0:0]</bitRange>
            </field>
            <field>
              <name>EPDISD</name>
              <description>EPDISD</description>
              <bitRange>[1:1]</bitRange>
            </field>
            <field>
              <name>STUP</name>
              <description>STUP</description>
              <bitRange>[3:3]</bitRange>
            </field>
            <field>
              <name>OTEPDIS</name>
              <description>OTEPDIS</description>
              <bitRange>[4:4]</bitRange>
            </field>
            <field>
              <name>B2BSTUP</name>
              <description>B2BSTUP</description>
              <bitRange>[6:6]</bitRange>
            </field>
          </fields>
        </register>
        <register>
          <name>DOEPTSIZ3</name>
          <description>device OUT endpoint-3 transfer size register</description>
          <addressOffset>0x370</addressOffset>
          <fields>
            <field>
              <name>XFRSIZ</name>
              <description>Transfer size</description>
              <bitRange>[18:0]</bitRange>
            </field>
            <field>
              <name>PKTCNT</name>
              <description>Packet count</description>
              <bitRange>[28:19]</bitRange>
            </field>
            <field>
              <name>RXDPID_STUPCNT</name>
              <description>Received data PID/SETUP packet count</description>
              <bitRange>[30:29]</bitRange>
            </field>
          </fields>
        </register>
      </registers>
    </peripheral>
    <peripheral>
      <name>USB1_OTG_GLOBAL</name>
      <description>USB on the go full speed</description>
      <baseAddress>0x48040000</baseAddress>
      <addressBlock>
        <offset>0x0</offset>
        <size>0x400</size>
        <usage>registers</usage>
      </addressBlock>
      <interrupt>
        <name>OTG1_FS</name>
        <description>USB1 OTG global interrupt</description>
        <value>21</value>
      </interrupt>
      <registers>
        <register>
          <name>FS_GOTGCTL</name>
          <description>OTG_FS control and status register (OTG_FS_GOTGCTL)</description>
          <addressOffset>0x0</addressOffset>
          <fields>
            <field>
              <name>SRQSCS</name>
              <description>Session request success</description>
              <bitRange>[0:0]</bitRange>
              <access>read-only</access>
            </field>
            <field>
              <name>SRQ</name>
              <description>Session request</description>
              <bitRange>[1:1]</bitRange>
            </field>
            <field>
              <name>HNGSCS</name>
              <description>Host negotiation success</description>
              <bitRange>[8:8]</bitRange>
              <access>read-only</access>
            </field>
            <field>
              <name>HNPRQ</name>
              <description>HNP request</description>
              <bitRange>[9:9]</bitRange>
            </field>
            <field>
              <name>HSHNPEN</name>
              <description>Host set HNP enable</description>
              <bitRange>[10:10]</bitRange>
            </field>
            <field>
              <name>DHNPEN</name>
              <description>Device HNP enabled</description>
              <bitRange>[11:11]</bitRange>
            </field>
            <field>
              <name>CIDSTS</name>
              <description>Connector ID status</description>
              <bitRange>[16:16]</bitRange>
              <access>read-only</access>
            </field>
            <field>
              <name>DBCT</name>
              <description>Long/short debounce time</description>
              <bitRange>[17:17]</bitRange>
              <access>read-only</access>
            </field>
            <field>
              <name>ASVLD</name>
              <description>A-session valid</description>
              <bitRange>[18:18]</bitRange>
              <access>read-only</access>
            </field>
            <field>
              <name>BSVLD</name>
              <description>B-session valid</description>
              <bitRange>[19:19]</bitRange>
              <access>read-only</access>
            </field>
          </fields>
        </register>
        <register>
          <name>FS_GOTGINT</name>
          <description>OTG_FS interrupt register (OTG_FS_GOTGINT)</description>
          <addressOffset>0x4</addressOffset>
          <fields>
            <field>
              <name>SEDET</name>
              <description>Session end detected</description>
              <bitRange>[2:2]</bitRange>
            </field>
            <field>
              <name>SRSSCHG</name>
              <description>Session request success status change</description>
              <bitRange>[8:8]</bitRange>
            </field>
            <field>
              <name>HNSSCHG</name>
              <description>Host negotiation success status change</description>
              <bitRange>[9:9]</bitRange>
            </field>
            <field>
              <name>HNGDET</name>
              <description>Host negotiation detected</description>
              <bitRange>[17:17]</bitRange>
            </field>
            <field>
              <name>ADTOCHG</name>
              <description>A-device timeout change</description>
              <bitRange>[18:18]</bitRange>
            </field>
            <field>
              <name>DBCDNE</name>
              <description>Debounce done</description>
              <bitRange>[19:19]</bitRange>
            </field>
          </fields>
        </register>
        <register>
          <name>FS_GAHBCFG</name>
          <description>OTG_FS AHB configuration register (OTG_FS_GAHBCFG)</description>
          <addressOffset>0x8</addressOffset>
          <fields>
            <field>
              <name>GINT</name>
              <description>Global interrupt mask</description>
              <bitRange>[0:0]</bitRange>
            </field>
            <field>
              <name>TXFELVL</name>
              <description>TxFIFO empty level</description>
              <bitRange>[7:7]</bitRange>
            </field>
            <field>
              <name>PTXFELVL</name>
              <description>Periodic TxFIFO empty level</description>
              <bitRange>[8:8]</bitRange>
            </field>
          </fields>
        </register>
        <register>
          <name>FS_GUSBCFG</name>
          <description>OTG_FS USB configuration register (OTG_FS_GUSBCFG)</description>
          <addressOffset>0xC</addressOffset>
          <fields>
            <field>
              <name>TOCAL</name>
              <description>FS timeout calibration</description>
              <bitRange>[2:0]</bitRange>
            </field>
            <field>
              <name>PHYSEL</name>
              <description>Full Speed serial transceiver select</description>
              <bitRange>[7:7]</bitRange>
            </field>
            <field>
              <name>SRPCAP</name>
              <description>SRP-capable</description>
              <bitRange>[8:8]</bitRange>
            </field>
            <field>
              <name>HNPCAP</name>
              <description>HNP-capable</description>
              <bitRange>[9:9]</bitRange>
            </field>
            <field>
              <name>TRDT</name>
              <description>USB turnaround time</description>
              <bitRange>[13:10]</bitRange>
            </field>
            <field>
              <name>FHMOD</name>
              <description>Force host mode</description>
              <bitRange>[29:29]</bitRange>
            </field>
            <field>
              <name>FDMOD</name>
              <description>Force device mode</description>
              <bitRange>[30:30]</bitRange>
            </field>
            <field>
              <name>CTXPKT</name>
              <description>Corrupt Tx packet</description>
              <bitRange>[31:31]</bitRange>
            </field>
          </fields>
        </register>
        <register>
          <name>FS_GRSTCTL</name>
          <description>OTG_FS reset register (OTG_FS_GRSTCTL)</description>
          <addressOffset>0x10</addressOffset>
          <fields>
            <field>
              <name>CSRST</name>
              <description>Core soft reset</description>
              <bitRange>[0:0]</bitRange>
            </field>
            <field>
              <name>HSRST</name>
              <description>HCLK soft reset</description>
              <bitRange>[1:1]</bitRange>
            </field>
            <field>
              <name>FCRST</name>
              <description>Host frame counter reset</description>
              <bitRange>[2:2]</bitRange>
            </field>
            <field>
              <name>RXFFLSH</name>
              <description>RxFIFO flush</description>
              <bitRange>[4:4]</bitRange>
            </field>
            <field>
              <name>TXFFLSH</name>
              <description>TxFIFO flush</description>
              <bitRange>[5:5]</bitRange>
            </field>
            <field>
              <name>TXFNUM</name>
              <description>TxFIFO number</description>
              <bitRange>[10:6]</bitRange>
            </field>
            <field>
              <name>AHBIDL</name>
              <description>AHB master idle</description>
              <bitRange>[31:31]</bitRange>
              <access>read-only</access>
            </field>
          </fields>
        </register>
        <register>
          <name>FS_GINTSTS</name>
          <description>OTG_FS core interrupt register (OTG_FS_GINTSTS)</description>
          <addressOffset>0x14</addressOffset>
          <fields>
            <field>
              <name>CMOD</name>
              <description>Current mode of operation</description>
              <bitRange>[0:0]</bitRange>
              <access>read-only</access>
            </field>
            <field>
              <name>MMIS</name>
              <description>Mode mismatch interrupt</description>
              <bitRange>[1:1]</bitRange>
            </field>
            <field>
              <name>OTGINT</name>
              <description>OTG interrupt</description>
              <bitRange>[2:2]</bitRange>
              <access>read-only</access>
            </field>
            <field>
              <name>SOF</name>
              <description>Start of frame</description>
              <bitRange>[3:3]</bitRange>
            </field>
            <field>
              <name>RXFLVL</name>
              <description>RxFIFO non-empty</description>
              <bitRange>[4:4]</bitRange>
              <access>read-only</access>
            </field>
            <field>
              <name>NPTXFE</name>
              <description>Non-periodic TxFIFO empty</description>
              <bitRange>[5:5]</bitRange>
              <access>read-only</access>
            </field>
            <field>
              <name>GINAKEFF</name>
              <description>Global IN non-periodic NAK effective</description>
              <bitRange>[6:6]</bitRange>
              <access>read-only</access>
            </field>
            <field>
              <name>GOUTNAKEFF</name>
              <description>Global OUT NAK effective</description>
              <bitRange>[7:7]</bitRange>
              <access>read-only</access>
            </field>
            <field>
              <name>ESUSP</name>
              <description>Early suspend</description>
              <bitRange>[10:10]</bitRange>
            </field>
            <field>
              <name>USBSUSP</name>
              <description>USB suspend</description>
              <bitRange>[11:11]</bitRange>
            </field>
            <field>
              <name>USBRST</name>
              <description>USB reset</description>
              <bitRange>[12:12]</bitRange>
            </field>
            <field>
              <name>ENUMDNE</name>
              <description>Enumeration done</description>
              <bitRange>[13:13]</bitRange>
            </field>
            <field>
              <name>ISOODRP</name>
              <description>Isochronous OUT packet dropped interrupt</description>
              <bitRange>[14:14]</bitRange>
            </field>
            <field>
              <name>EOPF</name>
              <description>End of periodic frame interrupt</description>
              <bitRange>[15:15]</bitRange>
            </field>
            <field>
              <name>IEPINT</name>
              <description>IN endpoint interrupt</description>
              <bitRange>[18:18]</bitRange>
              <access>read-only</access>
            </field>
            <field>
              <name>OEPINT</name>
              <description>OUT endpoint interrupt</description>
              <bitRange>[19:19]</bitRange>
              <access>read-only</access>
            </field>
            <field>
              <name>IISOIXFR</name>
              <description>Incomplete isochronous IN transfer</description>
              <bitRange>[20:20]</bitRange>
            </field>
            <field>
              <name>IPXFR_INCOMPISOOUT</name>
              <description>Incomplete periodic transfer(Host mode)/Incomplete isochronous OUT transfer(Device mode)</description>
              <bitRange>[21:21]</bitRange>
            </field>
            <field>
              <name>HPRTINT</name>
              <description>Host port interrupt</description>
              <bitRange>[24:24]</bitRange>
              <access>read-only</access>
            </field>
            <field>
              <name>HCINT</name>
              <description>Host channels interrupt</description>
              <bitRange>[25:25]</bitRange>
              <access>read-only</access>
            </field>
            <field>
              <name>PTXFE</name>
              <description>Periodic TxFIFO empty</description>
              <bitRange>[26:26]</bitRange>
              <access>read-only</access>
            </field>
            <field>
              <name>CIDSCHG</name>
              <description>Connector ID status change</description>
              <bitRange>[28:28]</bitRange>
            </field>
            <field>
              <name>DISCINT</name>
              <description>Disconnect detected interrupt</description>
              <bitRange>[29:29]</bitRange>
            </field>
            <field>
              <name>SRQINT</name>
              <description>Session request/new session detected interrupt</description>
              <bitRange>[30:30]</bitRange>
            </field>
            <field>
              <name>WKUPINT</name>
              <description>Resume/remote wakeup detected interrupt</description>
              <bitRange>[31:31]</bitRange>
            </field>
          </fields>
        </register>
        <register>
          <name>FS_GINTMSK</name>
          <description>OTG_FS interrupt mask register (OTG_FS_GINTMSK)</description>
          <addressOffset>0x18</addressOffset>
          <fields>
            <field>
              <name>MMISM</name>
              <description>Mode mismatch interrupt mask</description>
              <bitRange>[1:1]</bitRange>
            </field>
            <field>
              <name>OTGINT</name>
              <description>OTG interrupt mask</description>
              <bitRange>[2:2]</bitRange>
            </field>
            <field>
              <name>SOFM</name>
              <description>Start of frame mask</description>
              <bitRange>[3:3]</bitRange>
            </field>
            <field>
              <name>RXFLVLM</name>
              <description>Receive FIFO non-empty mask</description>
              <bitRange>[4:4]</bitRange>
            </field>
            <field>
              <name>NPTXFEM</name>
              <description>Non-periodic TxFIFO empty mask</description>
              <bitRange>[5:5]</bitRange>
            </field>
            <field>
              <name>GINAKEFFM</name>
              <description>Global non-periodic IN NAK effective mask</description>
              <bitRange>[6:6]</bitRange>
            </field>
            <field>
              <name>GONAKEFFM</name>
              <description>Global OUT NAK effective mask</description>
              <bitRange>[7:7]</bitRange>
            </field>
            <field>
              <name>ESUSPM</name>
              <description>Early suspend mask</description>
              <bitRange>[10:10]</bitRange>
            </field>
            <field>
              <name>USBSUSPM</name>
              <description>USB suspend mask</description>
              <bitRange>[11:11]</bitRange>
            </field>
            <field>
              <name>USBRST</name>
              <description>USB reset mask</description>
              <bitRange>[12:12]</bitRange>
            </field>
            <field>
              <name>ENUMDNEM</name>
              <description>Enumeration done mask</description>
              <bitRange>[13:13]</bitRange>
            </field>
            <field>
              <name>ISOODRPM</name>
              <description>Isochronous OUT packet dropped interrupt mask</description>
              <bitRange>[14:14]</bitRange>
            </field>
            <field>
              <name>EOPFM</name>
              <description>End of periodic frame interrupt mask</description>
              <bitRange>[15:15]</bitRange>
            </field>
            <field>
              <name>EPMISM</name>
              <description>Endpoint mismatch interrupt mask</description>
              <bitRange>[17:17]</bitRange>
            </field>
            <field>
              <name>IEPINT</name>
              <description>IN endpoints interrupt mask</description>
              <bitRange>[18:18]</bitRange>
            </field>
            <field>
              <name>OEPINT</name>
              <description>OUT endpoints interrupt mask</description>
              <bitRange>[19:19]</bitRange>
            </field>
            <field>
              <name>IISOIXFRM</name>
              <description>Incomplete isochronous IN transfer mask</description>
              <bitRange>[20:20]</bitRange>
            </field>
            <field>
              <name>IPXFRM_IISOOXFRM</name>
              <description>Incomplete periodic transfer mask(Host mode)/Incomplete isochronous OUT transfer mask(Device mode)</description>
              <bitRange>[21:21]</bitRange>
            </field>
            <field>
              <name>PRTIM</name>
              <description>Host port interrupt mask</description>
              <bitRange>[24:24]</bitRange>
              <access>read-only</access>
            </field>
            <field>
              <name>HCIM</name>
              <description>Host channels interrupt mask</description>
              <bitRange>[25:25]</bitRange>
            </field>
            <field>
              <name>PTXFEM</name>
              <description>Periodic TxFIFO empty mask</description>
              <bitRange>[26:26]</bitRange>
            </field>
            <field>
              <name>CIDSCHGM</name>
              <description>Connector ID status change mask</description>
              <bitRange>[28:28]</bitRange>
            </field>
            <field>
              <name>DISCINT</name>
              <description>Disconnect detected interrupt mask</description>
              <bitRange>[29:29]</bitRange>
            </field>
            <field>
              <name>SRQIM</name>
              <description>Session request/new session detected interrupt mask</description>
              <bitRange>[30:30]</bitRange>
            </field>
            <field>
              <name>WUIM</name>
              <description>Resume/remote wakeup detected interrupt mask</description>
              <bitRange>[31:31]</bitRange>
            </field>
          </fields>
        </register>
        <register>
          <name>FS_GRXSTSR_DEVICE</name>
          <addressOffset>0x1C</addressOffset>
          <fields>
            <field>
              <name>EPNUM</name>
              <description>Endpoint number</description>
              <bitRange>[3:0]</bitRange>
              <access>read-only</access>
            </field>
            <field>
              <name>BCNT</name>
              <description>Byte count</description>
              <bitRange>[14:4]</bitRange>
              <access>read-only</access>
            </field>
            <field>
              <name>DPID</name>
              <description>Data PID</description>
              <bitRange>[16:15]</bitRange>
              <access>read-only</access>
            </field>
            <field>
              <name>PKTSTS</name>
              <description>Packet status</description>
              <bitRange>[20:17]</bitRange>
              <access>read-only</access>
            </field>
            <field>
              <name>FRMNUM</name>
              <description>Frame number</description>
              <bitRange>[24:21]</bitRange>
              <access>read-only</access>
            </field>
          </fields>
        </register>
        <register>
          <name>FS_GRXSTSR_HOST</name>
          <alternateRegister>FS_GRXSTSR_DEVICE</alternateRegister>
          <addressOffset>0x1C</addressOffset>
          <fields>
            <field>
              <name>EPNUM</name>
              <description>Endpoint number</description>
              <bitRange>[3:0]</bitRange>
              <access>read-only</access>
            </field>
            <field>
              <name>BCNT</name>
              <description>Byte count</description>
              <bitRange>[14:4]</bitRange>
              <access>read-only</access>
            </field>
            <field>
              <name>DPID</name>
              <description>Data PID</description>
              <bitRange>[16:15]</bitRange>
              <access>read-only</access>
            </field>
            <field>
              <name>PKTSTS</name>
              <description>Packet status</description>
              <bitRange>[20:17]</bitRange>
              <access>read-only</access>
            </field>
            <field>
              <name>FRMNUM</name>
              <description>Frame number</description>
              <bitRange>[24:21]</bitRange>
              <access>read-only</access>
            </field>
          </fields>
        </register>
        <register>
          <name>FS_GRXFSIZ</name>
          <description>OTG_FS Receive FIFO size register (OTG_FS_GRXFSIZ)</description>
          <addressOffset>0x24</addressOffset>
          <fields>
            <field>
              <name>RXFD</name>
              <description>RxFIFO depth</description>
              <bitRange>[15:0]</bitRange>
            </field>
          </fields>
        </register>
        <register>
          <name>FS_GNPTXFSIZ_DEVICE</name>
          <addressOffset>0x28</addressOffset>
          <fields>
            <field>
              <name>TX0FSA</name>
              <description>Endpoint 0 transmit RAM start address</description>
              <bitRange>[15:0]</bitRange>
            </field>
            <field>
              <name>TX0FD</name>
              <description>Endpoint 0 TxFIFO depth</description>
              <bitRange>[31:16]</bitRange>
            </field>
          </fields>
        </register>
        <register>
          <name>FS_GNPTXFSIZ_HOST</name>
          <alternateRegister>FS_GNPTXFSIZ_DEVICE</alternateRegister>
          <addressOffset>0x28</addressOffset>
          <fields>
            <field>
              <name>NPTXFSA</name>
              <description>Non-periodic transmit RAM start address</description>
              <bitRange>[15:0]</bitRange>
            </field>
            <field>
              <name>NPTXFD</name>
              <description>Non-periodic TxFIFO depth</description>
              <bitRange>[31:16]</bitRange>
            </field>
          </fields>
        </register>
        <register>
          <name>FS_GNPTXSTS</name>
          <description>OTG_FS non-periodic transmit FIFO/queue status register (OTG_FS_GNPTXSTS)</description>
          <addressOffset>0x2C</addressOffset>
          <fields>
            <field>
              <name>NPTXFSAV</name>
              <description>Non-periodic TxFIFO space available</description>
              <bitRange>[15:0]</bitRange>
              <access>read-only</access>
            </field>
            <field>
              <name>NPTQXSAV</name>
              <description>Non-periodic transmit request queue space available</description>
              <bitRange>[23:16]</bitRange>
              <access>read-only</access>
            </field>
            <field>
              <name>NPTXQTOP</name>
              <description>Top of the non-periodic transmit request queue</description>
              <bitRange>[30:24]</bitRange>
              <access>read-only</access>
            </field>
          </fields>
        </register>
        <register>
          <name>FS_GCCFG</name>
          <description>OTG_FS general core configuration register (OTG_FS_GCCFG)</description>
          <addressOffset>0x38</addressOffset>
          <fields>
            <field>
              <name>PWRDWN</name>
              <description>Power down</description>
              <bitRange>[16:16]</bitRange>
            </field>
            <field>
              <name>VBUSASEN</name>
              <description>Enable the VBUS sensing device</description>
              <bitRange>[18:18]</bitRange>
            </field>
            <field>
              <name>VBUSBSEN</name>
              <description>Enable the VBUS sensing device</description>
              <bitRange>[19:19]</bitRange>
            </field>
            <field>
              <name>SOFOUTEN</name>
              <description>SOF output enable</description>
              <bitRange>[20:20]</bitRange>
            </field>
          </fields>
        </register>
        <register>
          <name>FS_CID</name>
          <description>core ID register</description>
          <addressOffset>0x3C</addressOffset>
          <fields>
            <field>
              <name>PRODUCT_ID</name>
              <description>Product ID field</description>
              <bitRange>[31:0]</bitRange>
            </field>
          </fields>
        </register>
        <register>
          <name>FS_HPTXFSIZ</name>
          <description>OTG_FS Host periodic transmit FIFO size register (OTG_FS_HPTXFSIZ)</description>
          <addressOffset>0x100</addressOffset>
          <fields>
            <field>
              <name>PTXSA</name>
              <description>Host periodic TxFIFO start address</description>
              <bitRange>[15:0]</bitRange>
            </field>
            <field>
              <name>PTXFSIZ</name>
              <description>Host periodic TxFIFO depth</description>
              <bitRange>[31:16]</bitRange>
            </field>
          </fields>
        </register>
        <register>
          <name>FS_DIEPTXF1</name>
          <description>OTG_FS device IN endpoint transmit FIFO size register (OTG_FS_DIEPTXF2)</description>
          <addressOffset>0x104</addressOffset>
          <fields>
            <field>
              <name>INEPTXSA</name>
              <description>IN endpoint FIFO2 transmit RAM start address</description>
              <bitRange>[15:0]</bitRange>
            </field>
            <field>
              <name>INEPTXFD</name>
              <description>IN endpoint TxFIFO depth</description>
              <bitRange>[31:16]</bitRange>
            </field>
          </fields>
        </register>
        <register>
          <name>FS_DIEPTXF2</name>
          <description>OTG_FS device IN endpoint transmit FIFO size register (OTG_FS_DIEPTXF3)</description>
          <addressOffset>0x108</addressOffset>
          <fields>
            <field>
              <name>INEPTXSA</name>
              <description>IN endpoint FIFO3 transmit RAM start address</description>
              <bitRange>[15:0]</bitRange>
            </field>
            <field>
              <name>INEPTXFD</name>
              <description>IN endpoint TxFIFO depth</description>
              <bitRange>[31:16]</bitRange>
            </field>
          </fields>
        </register>
        <register>
          <name>FS_DIEPTXF3</name>
          <description>OTG_FS device IN endpoint transmit FIFO size register (OTG_FS_DIEPTXF4)</description>
          <addressOffset>0x10C</addressOffset>
          <fields>
            <field>
              <name>INEPTXSA</name>
              <description>IN endpoint FIFO4 transmit RAM start address</description>
              <bitRange>[15:0]</bitRange>
            </field>
            <field>
              <name>INEPTXFD</name>
              <description>IN endpoint TxFIFO depth</description>
              <bitRange>[31:16]</bitRange>
            </field>
          </fields>
        </register>
      </registers>
    </peripheral>
    <peripheral>
      <name>USB1_OTG_HOST</name>
      <description>USB on the go full speed</description>
      <baseAddress>0x48040400</baseAddress>
      <addressBlock>
        <offset>0x0</offset>
        <size>0x400</size>
        <usage>registers</usage>
      </addressBlock>
      <registers>
        <register>
          <name>FS_HCFG</name>
          <description>OTG_FS host configuration register (OTG_FS_HCFG)</description>
          <addressOffset>0x0</addressOffset>
          <fields>
            <field>
              <name>FSLSPCS</name>
              <description>FS/LS PHY clock select</description>
              <bitRange>[1:0]</bitRange>
            </field>
            <field>
              <name>FSLSS</name>
              <description>FS- and LS-only support</description>
              <bitRange>[2:2]</bitRange>
              <access>read-only</access>
            </field>
          </fields>
        </register>
        <register>
          <name>HFIR</name>
          <description>OTG_FS Host frame interval register</description>
          <addressOffset>0x4</addressOffset>
          <fields>
            <field>
              <name>FRIVL</name>
              <description>Frame interval</description>
              <bitRange>[15:0]</bitRange>
            </field>
          </fields>
        </register>
        <register>
          <name>FS_HFNUM</name>
          <description>OTG_FS host frame number/frame time remaining register (OTG_FS_HFNUM)</description>
          <addressOffset>0x8</addressOffset>
          <fields>
            <field>
              <name>FRNUM</name>
              <description>Frame number</description>
              <bitRange>[15:0]</bitRange>
              <access>read-only</access>
            </field>
            <field>
              <name>FTREM</name>
              <description>Frame time remaining</description>
              <bitRange>[31:16]</bitRange>
              <access>read-only</access>
            </field>
          </fields>
        </register>
        <register>
          <name>FS_HPTXSTS</name>
          <description>OTG_FS_Host periodic transmit FIFO/queue status register (OTG_FS_HPTXSTS)</description>
          <addressOffset>0x10</addressOffset>
          <fields>
            <field>
              <name>PTXFSAVL</name>
              <description>Periodic transmit data FIFO space available</description>
              <bitRange>[15:0]</bitRange>
            </field>
            <field>
              <name>PTXQSAV</name>
              <description>Periodic transmit request queue space available</description>
              <bitRange>[23:16]</bitRange>
              <access>read-only</access>
            </field>
            <field>
              <name>PTXQTOP</name>
              <description>Top of the periodic transmit request queue</description>
              <bitRange>[31:24]</bitRange>
              <access>read-only</access>
            </field>
          </fields>
        </register>
        <register>
          <name>HAINT</name>
          <description>OTG_FS Host all channels interrupt register</description>
          <addressOffset>0x14</addressOffset>
          <fields>
            <field>
              <name>HAINT</name>
              <description>Channel interrupts</description>
              <bitRange>[15:0]</bitRange>
              <access>read-only</access>
            </field>
          </fields>
        </register>
        <register>
          <name>HAINTMSK</name>
          <description>OTG_FS host all channels interrupt mask register</description>
          <addressOffset>0x18</addressOffset>
          <fields>
            <field>
              <name>HAINTM</name>
              <description>Channel interrupt mask</description>
              <bitRange>[15:0]</bitRange>
            </field>
          </fields>
        </register>
        <register>
          <name>FS_HPRT</name>
          <description>OTG_FS host port control and status register (OTG_FS_HPRT)</description>
          <addressOffset>0x40</addressOffset>
          <fields>
            <field>
              <name>PCSTS</name>
              <description>Port connect status</description>
              <bitRange>[0:0]</bitRange>
              <access>read-only</access>
            </field>
            <field>
              <name>PCDET</name>
              <description>Port connect detected</description>
              <bitRange>[1:1]</bitRange>
            </field>
            <field>
              <name>PENA</name>
              <description>Port enable</description>
              <bitRange>[2:2]</bitRange>
            </field>
            <field>
              <name>PENCHNG</name>
              <description>Port enable/disable change</description>
              <bitRange>[3:3]</bitRange>
            </field>
            <field>
              <name>POCA</name>
              <description>Port overcurrent active</description>
              <bitRange>[4:4]</bitRange>
              <access>read-only</access>
            </field>
            <field>
              <name>POCCHNG</name>
              <description>Port overcurrent change</description>
              <bitRange>[5:5]</bitRange>
            </field>
            <field>
              <name>PRES</name>
              <description>Port resume</description>
              <bitRange>[6:6]</bitRange>
            </field>
            <field>
              <name>PSUSP</name>
              <description>Port suspend</description>
              <bitRange>[7:7]</bitRange>
            </field>
            <field>
              <name>PRST</name>
              <description>Port reset</description>
              <bitRange>[8:8]</bitRange>
            </field>
            <field>
              <name>PLSTS</name>
              <description>Port line status</description>
              <bitRange>[11:10]</bitRange>
              <access>read-only</access>
            </field>
            <field>
              <name>PPWR</name>
              <description>Port power</description>
              <bitRange>[12:12]</bitRange>
            </field>
            <field>
              <name>PTCTL</name>
              <description>Port test control</description>
              <bitRange>[16:13]</bitRange>
            </field>
            <field>
              <name>PSPD</name>
              <description>Port speed</description>
              <bitRange>[18:17]</bitRange>
              <access>read-only</access>
            </field>
          </fields>
        </register>
        <register>
          <name>FS_HCCHAR0</name>
          <description>OTG_FS host channel-0 characteristics register (OTG_FS_HCCHAR0)</description>
          <addressOffset>0x100</addressOffset>
          <fields>
            <field>
              <name>MPSIZ</name>
              <description>Maximum packet size</description>
              <bitRange>[10:0]</bitRange>
            </field>
            <field>
              <name>EPNUM</name>
              <description>Endpoint number</description>
              <bitRange>[14:11]</bitRange>
            </field>
            <field>
              <name>EPDIR</name>
              <description>Endpoint direction</description>
              <bitRange>[15:15]</bitRange>
            </field>
            <field>
              <name>LSDEV</name>
              <description>Low-speed device</description>
              <bitRange>[17:17]</bitRange>
            </field>
            <field>
              <name>EPTYP</name>
              <description>Endpoint type</description>
              <bitRange>[19:18]</bitRange>
            </field>
            <field>
              <name>MCNT</name>
              <description>Multicount</description>
              <bitRange>[21:20]</bitRange>
            </field>
            <field>
              <name>DAD</name>
              <description>Device address</description>
              <bitRange>[28:22]</bitRange>
            </field>
            <field>
              <name>ODDFRM</name>
              <description>Odd frame</description>
              <bitRange>[29:29]</bitRange>
            </field>
            <field>
              <name>CHDIS</name>
              <description>Channel disable</description>
              <bitRange>[30:30]</bitRange>
            </field>
            <field>
              <name>CHENA</name>
              <description>Channel enable</description>
              <bitRange>[31:31]</bitRange>
            </field>
          </fields>
        </register>
        <register>
          <name>FS_HCINT0</name>
          <description>OTG_FS host channel-0 interrupt register (OTG_FS_HCINT0)</description>
          <addressOffset>0x108</addressOffset>
          <fields>
            <field>
              <name>XFRC</name>
              <description>Transfer completed</description>
              <bitRange>[0:0]</bitRange>
            </field>
            <field>
              <name>CHH</name>
              <description>Channel halted</description>
              <bitRange>[1:1]</bitRange>
            </field>
            <field>
              <name>STALL</name>
              <description>STALL response received interrupt</description>
              <bitRange>[3:3]</bitRange>
            </field>
            <field>
              <name>NAK</name>
              <description>NAK response received interrupt</description>
              <bitRange>[4:4]</bitRange>
            </field>
            <field>
              <name>ACK</name>
              <description>ACK response received/transmitted interrupt</description>
              <bitRange>[5:5]</bitRange>
            </field>
            <field>
              <name>TXERR</name>
              <description>Transaction error</description>
              <bitRange>[7:7]</bitRange>
            </field>
            <field>
              <name>BBERR</name>
              <description>Babble error</description>
              <bitRange>[8:8]</bitRange>
            </field>
            <field>
              <name>FRMOR</name>
              <description>Frame overrun</description>
              <bitRange>[9:9]</bitRange>
            </field>
            <field>
              <name>DTERR</name>
              <description>Data toggle error</description>
              <bitRange>[10:10]</bitRange>
            </field>
          </fields>
        </register>
        <register>
          <name>FS_HCINTMSK0</name>
          <description>OTG_FS host channel-0 mask register (OTG_FS_HCINTMSK0)</description>
          <addressOffset>0x10C</addressOffset>
          <fields>
            <field>
              <name>XFRCM</name>
              <description>Transfer completed mask</description>
              <bitRange>[0:0]</bitRange>
            </field>
            <field>
              <name>CHHM</name>
              <description>Channel halted mask</description>
              <bitRange>[1:1]</bitRange>
            </field>
            <field>
              <name>STALLM</name>
              <description>STALL response received interrupt mask</description>
              <bitRange>[3:3]</bitRange>
            </field>
            <field>
              <name>NAKM</name>
              <description>NAK response received interrupt mask</description>
              <bitRange>[4:4]</bitRange>
            </field>
            <field>
              <name>ACKM</name>
              <description>ACK response received/transmitted interrupt mask</description>
              <bitRange>[5:5]</bitRange>
            </field>
            <field>
              <name>NYET</name>
              <description>response received interrupt mask</description>
              <bitRange>[6:6]</bitRange>
            </field>
            <field>
              <name>TXERRM</name>
              <description>Transaction error mask</description>
              <bitRange>[7:7]</bitRange>
            </field>
            <field>
              <name>BBERRM</name>
              <description>Babble error mask</description>
              <bitRange>[8:8]</bitRange>
            </field>
            <field>
              <name>FRMORM</name>
              <description>Frame overrun mask</description>
              <bitRange>[9:9]</bitRange>
            </field>
            <field>
              <name>DTERRM</name>
              <description>Data toggle error mask</description>
              <bitRange>[10:10]</bitRange>
            </field>
          </fields>
        </register>
        <register>
          <name>FS_HCTSIZ0</name>
          <description>OTG_FS host channel-0 transfer size register</description>
          <addressOffset>0x110</addressOffset>
          <fields>
            <field>
              <name>XFRSIZ</name>
              <description>Transfer size</description>
              <bitRange>[18:0]</bitRange>
            </field>
            <field>
              <name>PKTCNT</name>
              <description>Packet count</description>
              <bitRange>[28:19]</bitRange>
            </field>
            <field>
              <name>DPID</name>
              <description>Data PID</description>
              <bitRange>[30:29]</bitRange>
            </field>
          </fields>
        </register>
        <register>
          <name>FS_HCCHAR1</name>
          <description>OTG_FS host channel-1 characteristics register (OTG_FS_HCCHAR1)</description>
          <addressOffset>0x120</addressOffset>
          <fields>
            <field>
              <name>MPSIZ</name>
              <description>Maximum packet size</description>
              <bitRange>[10:0]</bitRange>
            </field>
            <field>
              <name>EPNUM</name>
              <description>Endpoint number</description>
              <bitRange>[14:11]</bitRange>
            </field>
            <field>
              <name>EPDIR</name>
              <description>Endpoint direction</description>
              <bitRange>[15:15]</bitRange>
            </field>
            <field>
              <name>LSDEV</name>
              <description>Low-speed device</description>
              <bitRange>[17:17]</bitRange>
            </field>
            <field>
              <name>EPTYP</name>
              <description>Endpoint type</description>
              <bitRange>[19:18]</bitRange>
            </field>
            <field>
              <name>MCNT</name>
              <description>Multicount</description>
              <bitRange>[21:20]</bitRange>
            </field>
            <field>
              <name>DAD</name>
              <description>Device address</description>
              <bitRange>[28:22]</bitRange>
            </field>
            <field>
              <name>ODDFRM</name>
              <description>Odd frame</description>
              <bitRange>[29:29]</bitRange>
            </field>
            <field>
              <name>CHDIS</name>
              <description>Channel disable</description>
              <bitRange>[30:30]</bitRange>
            </field>
            <field>
              <name>CHENA</name>
              <description>Channel enable</description>
              <bitRange>[31:31]</bitRange>
            </field>
          </fields>
        </register>
        <register>
          <name>FS_HCINT1</name>
          <description>OTG_FS host channel-1 interrupt register (OTG_FS_HCINT1)</description>
          <addressOffset>0x128</addressOffset>
          <fields>
            <field>
              <name>XFRC</name>
              <description>Transfer completed</description>
              <bitRange>[0:0]</bitRange>
            </field>
            <field>
              <name>CHH</name>
              <description>Channel halted</description>
              <bitRange>[1:1]</bitRange>
            </field>
            <field>
              <name>STALL</name>
              <description>STALL response received interrupt</description>
              <bitRange>[3:3]</bitRange>
            </field>
            <field>
              <name>NAK</name>
              <description>NAK response received interrupt</description>
              <bitRange>[4:4]</bitRange>
            </field>
            <field>
              <name>ACK</name>
              <description>ACK response received/transmitted interrupt</description>
              <bitRange>[5:5]</bitRange>
            </field>
            <field>
              <name>TXERR</name>
              <description>Transaction error</description>
              <bitRange>[7:7]</bitRange>
            </field>
            <field>
              <name>BBERR</name>
              <description>Babble error</description>
              <bitRange>[8:8]</bitRange>
            </field>
            <field>
              <name>FRMOR</name>
              <description>Frame overrun</description>
              <bitRange>[9:9]</bitRange>
            </field>
            <field>
              <name>DTERR</name>
              <description>Data toggle error</description>
              <bitRange>[10:10]</bitRange>
            </field>
          </fields>
        </register>
        <register>
          <name>FS_HCINTMSK1</name>
          <description>OTG_FS host channel-1 mask register (OTG_FS_HCINTMSK1)</description>
          <addressOffset>0x12C</addressOffset>
          <fields>
            <field>
              <name>XFRCM</name>
              <description>Transfer completed mask</description>
              <bitRange>[0:0]</bitRange>
            </field>
            <field>
              <name>CHHM</name>
              <description>Channel halted mask</description>
              <bitRange>[1:1]</bitRange>
            </field>
            <field>
              <name>STALLM</name>
              <description>STALL response received interrupt mask</description>
              <bitRange>[3:3]</bitRange>
            </field>
            <field>
              <name>NAKM</name>
              <description>NAK response received interrupt mask</description>
              <bitRange>[4:4]</bitRange>
            </field>
            <field>
              <name>ACKM</name>
              <description>ACK response received/transmitted interrupt mask</description>
              <bitRange>[5:5]</bitRange>
            </field>
            <field>
              <name>NYET</name>
              <description>response received interrupt mask</description>
              <bitRange>[6:6]</bitRange>
            </field>
            <field>
              <name>TXERRM</name>
              <description>Transaction error mask</description>
              <bitRange>[7:7]</bitRange>
            </field>
            <field>
              <name>BBERRM</name>
              <description>Babble error mask</description>
              <bitRange>[8:8]</bitRange>
            </field>
            <field>
              <name>FRMORM</name>
              <description>Frame overrun mask</description>
              <bitRange>[9:9]</bitRange>
            </field>
            <field>
              <name>DTERRM</name>
              <description>Data toggle error mask</description>
              <bitRange>[10:10]</bitRange>
            </field>
          </fields>
        </register>
        <register>
          <name>FS_HCTSIZ1</name>
          <description>OTG_FS host channel-1 transfer size register</description>
          <addressOffset>0x130</addressOffset>
          <fields>
            <field>
              <name>XFRSIZ</name>
              <description>Transfer size</description>
              <bitRange>[18:0]</bitRange>
            </field>
            <field>
              <name>PKTCNT</name>
              <description>Packet count</description>
              <bitRange>[28:19]</bitRange>
            </field>
            <field>
              <name>DPID</name>
              <description>Data PID</description>
              <bitRange>[30:29]</bitRange>
            </field>
          </fields>
        </register>
        <register>
          <name>FS_HCCHAR2</name>
          <description>OTG_FS host channel-2 characteristics register (OTG_FS_HCCHAR2)</description>
          <addressOffset>0x140</addressOffset>
          <fields>
            <field>
              <name>MPSIZ</name>
              <description>Maximum packet size</description>
              <bitRange>[10:0]</bitRange>
            </field>
            <field>
              <name>EPNUM</name>
              <description>Endpoint number</description>
              <bitRange>[14:11]</bitRange>
            </field>
            <field>
              <name>EPDIR</name>
              <description>Endpoint direction</description>
              <bitRange>[15:15]</bitRange>
            </field>
            <field>
              <name>LSDEV</name>
              <description>Low-speed device</description>
              <bitRange>[17:17]</bitRange>
            </field>
            <field>
              <name>EPTYP</name>
              <description>Endpoint type</description>
              <bitRange>[19:18]</bitRange>
            </field>
            <field>
              <name>MCNT</name>
              <description>Multicount</description>
              <bitRange>[21:20]</bitRange>
            </field>
            <field>
              <name>DAD</name>
              <description>Device address</description>
              <bitRange>[28:22]</bitRange>
            </field>
            <field>
              <name>ODDFRM</name>
              <description>Odd frame</description>
              <bitRange>[29:29]</bitRange>
            </field>
            <field>
              <name>CHDIS</name>
              <description>Channel disable</description>
              <bitRange>[30:30]</bitRange>
            </field>
            <field>
              <name>CHENA</name>
              <description>Channel enable</description>
              <bitRange>[31:31]</bitRange>
            </field>
          </fields>
        </register>
        <register>
          <name>FS_HCINT2</name>
          <description>OTG_FS host channel-2 interrupt register (OTG_FS_HCINT2)</description>
          <addressOffset>0x148</addressOffset>
          <fields>
            <field>
              <name>XFRC</name>
              <description>Transfer completed</description>
              <bitRange>[0:0]</bitRange>
            </field>
            <field>
              <name>CHH</name>
              <description>Channel halted</description>
              <bitRange>[1:1]</bitRange>
            </field>
            <field>
              <name>STALL</name>
              <description>STALL response received interrupt</description>
              <bitRange>[3:3]</bitRange>
            </field>
            <field>
              <name>NAK</name>
              <description>NAK response received interrupt</description>
              <bitRange>[4:4]</bitRange>
            </field>
            <field>
              <name>ACK</name>
              <description>ACK response received/transmitted interrupt</description>
              <bitRange>[5:5]</bitRange>
            </field>
            <field>
              <name>TXERR</name>
              <description>Transaction error</description>
              <bitRange>[7:7]</bitRange>
            </field>
            <field>
              <name>BBERR</name>
              <description>Babble error</description>
              <bitRange>[8:8]</bitRange>
            </field>
            <field>
              <name>FRMOR</name>
              <description>Frame overrun</description>
              <bitRange>[9:9]</bitRange>
            </field>
            <field>
              <name>DTERR</name>
              <description>Data toggle error</description>
              <bitRange>[10:10]</bitRange>
            </field>
          </fields>
        </register>
        <register>
          <name>FS_HCINTMSK2</name>
          <description>OTG_FS host channel-2 mask register (OTG_FS_HCINTMSK2)</description>
          <addressOffset>0x14C</addressOffset>
          <fields>
            <field>
              <name>XFRCM</name>
              <description>Transfer completed mask</description>
              <bitRange>[0:0]</bitRange>
            </field>
            <field>
              <name>CHHM</name>
              <description>Channel halted mask</description>
              <bitRange>[1:1]</bitRange>
            </field>
            <field>
              <name>STALLM</name>
              <description>STALL response received interrupt mask</description>
              <bitRange>[3:3]</bitRange>
            </field>
            <field>
              <name>NAKM</name>
              <description>NAK response received interrupt mask</description>
              <bitRange>[4:4]</bitRange>
            </field>
            <field>
              <name>ACKM</name>
              <description>ACK response received/transmitted interrupt mask</description>
              <bitRange>[5:5]</bitRange>
            </field>
            <field>
              <name>NYET</name>
              <description>response received interrupt mask</description>
              <bitRange>[6:6]</bitRange>
            </field>
            <field>
              <name>TXERRM</name>
              <description>Transaction error mask</description>
              <bitRange>[7:7]</bitRange>
            </field>
            <field>
              <name>BBERRM</name>
              <description>Babble error mask</description>
              <bitRange>[8:8]</bitRange>
            </field>
            <field>
              <name>FRMORM</name>
              <description>Frame overrun mask</description>
              <bitRange>[9:9]</bitRange>
            </field>
            <field>
              <name>DTERRM</name>
              <description>Data toggle error mask</description>
              <bitRange>[10:10]</bitRange>
            </field>
          </fields>
        </register>
        <register>
          <name>FS_HCTSIZ2</name>
          <description>OTG_FS host channel-2 transfer size register</description>
          <addressOffset>0x150</addressOffset>
          <fields>
            <field>
              <name>XFRSIZ</name>
              <description>Transfer size</description>
              <bitRange>[18:0]</bitRange>
            </field>
            <field>
              <name>PKTCNT</name>
              <description>Packet count</description>
              <bitRange>[28:19]</bitRange>
            </field>
            <field>
              <name>DPID</name>
              <description>Data PID</description>
              <bitRange>[30:29]</bitRange>
            </field>
          </fields>
        </register>
        <register>
          <name>FS_HCCHAR3</name>
          <description>OTG_FS host channel-3 characteristics register (OTG_FS_HCCHAR3)</description>
          <addressOffset>0x160</addressOffset>
          <fields>
            <field>
              <name>MPSIZ</name>
              <description>Maximum packet size</description>
              <bitRange>[10:0]</bitRange>
            </field>
            <field>
              <name>EPNUM</name>
              <description>Endpoint number</description>
              <bitRange>[14:11]</bitRange>
            </field>
            <field>
              <name>EPDIR</name>
              <description>Endpoint direction</description>
              <bitRange>[15:15]</bitRange>
            </field>
            <field>
              <name>LSDEV</name>
              <description>Low-speed device</description>
              <bitRange>[17:17]</bitRange>
            </field>
            <field>
              <name>EPTYP</name>
              <description>Endpoint type</description>
              <bitRange>[19:18]</bitRange>
            </field>
            <field>
              <name>MCNT</name>
              <description>Multicount</description>
              <bitRange>[21:20]</bitRange>
            </field>
            <field>
              <name>DAD</name>
              <description>Device address</description>
              <bitRange>[28:22]</bitRange>
            </field>
            <field>
              <name>ODDFRM</name>
              <description>Odd frame</description>
              <bitRange>[29:29]</bitRange>
            </field>
            <field>
              <name>CHDIS</name>
              <description>Channel disable</description>
              <bitRange>[30:30]</bitRange>
            </field>
            <field>
              <name>CHENA</name>
              <description>Channel enable</description>
              <bitRange>[31:31]</bitRange>
            </field>
          </fields>
        </register>
        <register>
          <name>FS_HCINT3</name>
          <description>OTG_FS host channel-3 interrupt register (OTG_FS_HCINT3)</description>
          <addressOffset>0x168</addressOffset>
          <fields>
            <field>
              <name>XFRC</name>
              <description>Transfer completed</description>
              <bitRange>[0:0]</bitRange>
            </field>
            <field>
              <name>CHH</name>
              <description>Channel halted</description>
              <bitRange>[1:1]</bitRange>
            </field>
            <field>
              <name>STALL</name>
              <description>STALL response received interrupt</description>
              <bitRange>[3:3]</bitRange>
            </field>
            <field>
              <name>NAK</name>
              <description>NAK response received interrupt</description>
              <bitRange>[4:4]</bitRange>
            </field>
            <field>
              <name>ACK</name>
              <description>ACK response received/transmitted interrupt</description>
              <bitRange>[5:5]</bitRange>
            </field>
            <field>
              <name>TXERR</name>
              <description>Transaction error</description>
              <bitRange>[7:7]</bitRange>
            </field>
            <field>
              <name>BBERR</name>
              <description>Babble error</description>
              <bitRange>[8:8]</bitRange>
            </field>
            <field>
              <name>FRMOR</name>
              <description>Frame overrun</description>
              <bitRange>[9:9]</bitRange>
            </field>
            <field>
              <name>DTERR</name>
              <description>Data toggle error</description>
              <bitRange>[10:10]</bitRange>
            </field>
          </fields>
        </register>
        <register>
          <name>FS_HCINTMSK3</name>
          <description>OTG_FS host channel-3 mask register (OTG_FS_HCINTMSK3)</description>
          <addressOffset>0x16C</addressOffset>
          <fields>
            <field>
              <name>XFRCM</name>
              <description>Transfer completed mask</description>
              <bitRange>[0:0]</bitRange>
            </field>
            <field>
              <name>CHHM</name>
              <description>Channel halted mask</description>
              <bitRange>[1:1]</bitRange>
            </field>
            <field>
              <name>STALLM</name>
              <description>STALL response received interrupt mask</description>
              <bitRange>[3:3]</bitRange>
            </field>
            <field>
              <name>NAKM</name>
              <description>NAK response received interrupt mask</description>
              <bitRange>[4:4]</bitRange>
            </field>
            <field>
              <name>ACKM</name>
              <description>ACK response received/transmitted interrupt mask</description>
              <bitRange>[5:5]</bitRange>
            </field>
            <field>
              <name>NYET</name>
              <description>response received interrupt mask</description>
              <bitRange>[6:6]</bitRange>
            </field>
            <field>
              <name>TXERRM</name>
              <description>Transaction error mask</description>
              <bitRange>[7:7]</bitRange>
            </field>
            <field>
              <name>BBERRM</name>
              <description>Babble error mask</description>
              <bitRange>[8:8]</bitRange>
            </field>
            <field>
              <name>FRMORM</name>
              <description>Frame overrun mask</description>
              <bitRange>[9:9]</bitRange>
            </field>
            <field>
              <name>DTERRM</name>
              <description>Data toggle error mask</description>
              <bitRange>[10:10]</bitRange>
            </field>
          </fields>
        </register>
        <register>
          <name>FS_HCTSIZ3</name>
          <description>OTG_FS host channel-3 transfer size register</description>
          <addressOffset>0x170</addressOffset>
          <fields>
            <field>
              <name>XFRSIZ</name>
              <description>Transfer size</description>
              <bitRange>[18:0]</bitRange>
            </field>
            <field>
              <name>PKTCNT</name>
              <description>Packet count</description>
              <bitRange>[28:19]</bitRange>
            </field>
            <field>
              <name>DPID</name>
              <description>Data PID</description>
              <bitRange>[30:29]</bitRange>
            </field>
          </fields>
        </register>
        <register>
          <name>FS_HCCHAR4</name>
          <description>OTG_FS host channel-4 characteristics register (OTG_FS_HCCHAR4)</description>
          <addressOffset>0x180</addressOffset>
          <fields>
            <field>
              <name>MPSIZ</name>
              <description>Maximum packet size</description>
              <bitRange>[10:0]</bitRange>
            </field>
            <field>
              <name>EPNUM</name>
              <description>Endpoint number</description>
              <bitRange>[14:11]</bitRange>
            </field>
            <field>
              <name>EPDIR</name>
              <description>Endpoint direction</description>
              <bitRange>[15:15]</bitRange>
            </field>
            <field>
              <name>LSDEV</name>
              <description>Low-speed device</description>
              <bitRange>[17:17]</bitRange>
            </field>
            <field>
              <name>EPTYP</name>
              <description>Endpoint type</description>
              <bitRange>[19:18]</bitRange>
            </field>
            <field>
              <name>MCNT</name>
              <description>Multicount</description>
              <bitRange>[21:20]</bitRange>
            </field>
            <field>
              <name>DAD</name>
              <description>Device address</description>
              <bitRange>[28:22]</bitRange>
            </field>
            <field>
              <name>ODDFRM</name>
              <description>Odd frame</description>
              <bitRange>[29:29]</bitRange>
            </field>
            <field>
              <name>CHDIS</name>
              <description>Channel disable</description>
              <bitRange>[30:30]</bitRange>
            </field>
            <field>
              <name>CHENA</name>
              <description>Channel enable</description>
              <bitRange>[31:31]</bitRange>
            </field>
          </fields>
        </register>
        <register>
          <name>FS_HCINT4</name>
          <description>OTG_FS host channel-4 interrupt register (OTG_FS_HCINT4)</description>
          <addressOffset>0x188</addressOffset>
          <fields>
            <field>
              <name>XFRC</name>
              <description>Transfer completed</description>
              <bitRange>[0:0]</bitRange>
            </field>
            <field>
              <name>CHH</name>
              <description>Channel halted</description>
              <bitRange>[1:1]</bitRange>
            </field>
            <field>
              <name>STALL</name>
              <description>STALL response received interrupt</description>
              <bitRange>[3:3]</bitRange>
            </field>
            <field>
              <name>NAK</name>
              <description>NAK response received interrupt</description>
              <bitRange>[4:4]</bitRange>
            </field>
            <field>
              <name>ACK</name>
              <description>ACK response received/transmitted interrupt</description>
              <bitRange>[5:5]</bitRange>
            </field>
            <field>
              <name>TXERR</name>
              <description>Transaction error</description>
              <bitRange>[7:7]</bitRange>
            </field>
            <field>
              <name>BBERR</name>
              <description>Babble error</description>
              <bitRange>[8:8]</bitRange>
            </field>
            <field>
              <name>FRMOR</name>
              <description>Frame overrun</description>
              <bitRange>[9:9]</bitRange>
            </field>
            <field>
              <name>DTERR</name>
              <description>Data toggle error</description>
              <bitRange>[10:10]</bitRange>
            </field>
          </fields>
        </register>
        <register>
          <name>FS_HCINTMSK4</name>
          <description>OTG_FS host channel-4 mask register (OTG_FS_HCINTMSK4)</description>
          <addressOffset>0x18C</addressOffset>
          <fields>
            <field>
              <name>XFRCM</name>
              <description>Transfer completed mask</description>
              <bitRange>[0:0]</bitRange>
            </field>
            <field>
              <name>CHHM</name>
              <description>Channel halted mask</description>
              <bitRange>[1:1]</bitRange>
            </field>
            <field>
              <name>STALLM</name>
              <description>STALL response received interrupt mask</description>
              <bitRange>[3:3]</bitRange>
            </field>
            <field>
              <name>NAKM</name>
              <description>NAK response received interrupt mask</description>
              <bitRange>[4:4]</bitRange>
            </field>
            <field>
              <name>ACKM</name>
              <description>ACK response received/transmitted interrupt mask</description>
              <bitRange>[5:5]</bitRange>
            </field>
            <field>
              <name>NYET</name>
              <description>response received interrupt mask</description>
              <bitRange>[6:6]</bitRange>
            </field>
            <field>
              <name>TXERRM</name>
              <description>Transaction error mask</description>
              <bitRange>[7:7]</bitRange>
            </field>
            <field>
              <name>BBERRM</name>
              <description>Babble error mask</description>
              <bitRange>[8:8]</bitRange>
            </field>
            <field>
              <name>FRMORM</name>
              <description>Frame overrun mask</description>
              <bitRange>[9:9]</bitRange>
            </field>
            <field>
              <name>DTERRM</name>
              <description>Data toggle error mask</description>
              <bitRange>[10:10]</bitRange>
            </field>
          </fields>
        </register>
        <register>
          <name>FS_HCTSIZ4</name>
          <description>OTG_FS host channel-x transfer size register</description>
          <addressOffset>0x190</addressOffset>
          <fields>
            <field>
              <name>XFRSIZ</name>
              <description>Transfer size</description>
              <bitRange>[18:0]</bitRange>
            </field>
            <field>
              <name>PKTCNT</name>
              <description>Packet count</description>
              <bitRange>[28:19]</bitRange>
            </field>
            <field>
              <name>DPID</name>
              <description>Data PID</description>
              <bitRange>[30:29]</bitRange>
            </field>
          </fields>
        </register>
        <register>
          <name>FS_HCCHAR5</name>
          <description>OTG_FS host channel-5 characteristics register (OTG_FS_HCCHAR5)</description>
          <addressOffset>0x1A0</addressOffset>
          <fields>
            <field>
              <name>MPSIZ</name>
              <description>Maximum packet size</description>
              <bitRange>[10:0]</bitRange>
            </field>
            <field>
              <name>EPNUM</name>
              <description>Endpoint number</description>
              <bitRange>[14:11]</bitRange>
            </field>
            <field>
              <name>EPDIR</name>
              <description>Endpoint direction</description>
              <bitRange>[15:15]</bitRange>
            </field>
            <field>
              <name>LSDEV</name>
              <description>Low-speed device</description>
              <bitRange>[17:17]</bitRange>
            </field>
            <field>
              <name>EPTYP</name>
              <description>Endpoint type</description>
              <bitRange>[19:18]</bitRange>
            </field>
            <field>
              <name>MCNT</name>
              <description>Multicount</description>
              <bitRange>[21:20]</bitRange>
            </field>
            <field>
              <name>DAD</name>
              <description>Device address</description>
              <bitRange>[28:22]</bitRange>
            </field>
            <field>
              <name>ODDFRM</name>
              <description>Odd frame</description>
              <bitRange>[29:29]</bitRange>
            </field>
            <field>
              <name>CHDIS</name>
              <description>Channel disable</description>
              <bitRange>[30:30]</bitRange>
            </field>
            <field>
              <name>CHENA</name>
              <description>Channel enable</description>
              <bitRange>[31:31]</bitRange>
            </field>
          </fields>
        </register>
        <register>
          <name>FS_HCINT5</name>
          <description>OTG_FS host channel-5 interrupt register (OTG_FS_HCINT5)</description>
          <addressOffset>0x1A8</addressOffset>
          <fields>
            <field>
              <name>XFRC</name>
              <description>Transfer completed</description>
              <bitRange>[0:0]</bitRange>
            </field>
            <field>
              <name>CHH</name>
              <description>Channel halted</description>
              <bitRange>[1:1]</bitRange>
            </field>
            <field>
              <name>STALL</name>
              <description>STALL response received interrupt</description>
              <bitRange>[3:3]</bitRange>
            </field>
            <field>
              <name>NAK</name>
              <description>NAK response received interrupt</description>
              <bitRange>[4:4]</bitRange>
            </field>
            <field>
              <name>ACK</name>
              <description>ACK response received/transmitted interrupt</description>
              <bitRange>[5:5]</bitRange>
            </field>
            <field>
              <name>TXERR</name>
              <description>Transaction error</description>
              <bitRange>[7:7]</bitRange>
            </field>
            <field>
              <name>BBERR</name>
              <description>Babble error</description>
              <bitRange>[8:8]</bitRange>
            </field>
            <field>
              <name>FRMOR</name>
              <description>Frame overrun</description>
              <bitRange>[9:9]</bitRange>
            </field>
            <field>
              <name>DTERR</name>
              <description>Data toggle error</description>
              <bitRange>[10:10]</bitRange>
            </field>
          </fields>
        </register>
        <register>
          <name>FS_HCINTMSK5</name>
          <description>OTG_FS host channel-5 mask register (OTG_FS_HCINTMSK5)</description>
          <addressOffset>0x1AC</addressOffset>
          <fields>
            <field>
              <name>XFRCM</name>
              <description>Transfer completed mask</description>
              <bitRange>[0:0]</bitRange>
            </field>
            <field>
              <name>CHHM</name>
              <description>Channel halted mask</description>
              <bitRange>[1:1]</bitRange>
            </field>
            <field>
              <name>STALLM</name>
              <description>STALL response received interrupt mask</description>
              <bitRange>[3:3]</bitRange>
            </field>
            <field>
              <name>NAKM</name>
              <description>NAK response received interrupt mask</description>
              <bitRange>[4:4]</bitRange>
            </field>
            <field>
              <name>ACKM</name>
              <description>ACK response received/transmitted interrupt mask</description>
              <bitRange>[5:5]</bitRange>
            </field>
            <field>
              <name>NYET</name>
              <description>response received interrupt mask</description>
              <bitRange>[6:6]</bitRange>
            </field>
            <field>
              <name>TXERRM</name>
              <description>Transaction error mask</description>
              <bitRange>[7:7]</bitRange>
            </field>
            <field>
              <name>BBERRM</name>
              <description>Babble error mask</description>
              <bitRange>[8:8]</bitRange>
            </field>
            <field>
              <name>FRMORM</name>
              <description>Frame overrun mask</description>
              <bitRange>[9:9]</bitRange>
            </field>
            <field>
              <name>DTERRM</name>
              <description>Data toggle error mask</description>
              <bitRange>[10:10]</bitRange>
            </field>
          </fields>
        </register>
        <register>
          <name>FS_HCTSIZ5</name>
          <description>OTG_FS host channel-5 transfer size register</description>
          <addressOffset>0x1B0</addressOffset>
          <fields>
            <field>
              <name>XFRSIZ</name>
              <description>Transfer size</description>
              <bitRange>[18:0]</bitRange>
            </field>
            <field>
              <name>PKTCNT</name>
              <description>Packet count</description>
              <bitRange>[28:19]</bitRange>
            </field>
            <field>
              <name>DPID</name>
              <description>Data PID</description>
              <bitRange>[30:29]</bitRange>
            </field>
          </fields>
        </register>
        <register>
          <name>FS_HCCHAR6</name>
          <description>OTG_FS host channel-6 characteristics register (OTG_FS_HCCHAR6)</description>
          <addressOffset>0x1C0</addressOffset>
          <fields>
            <field>
              <name>MPSIZ</name>
              <description>Maximum packet size</description>
              <bitRange>[10:0]</bitRange>
            </field>
            <field>
              <name>EPNUM</name>
              <description>Endpoint number</description>
              <bitRange>[14:11]</bitRange>
            </field>
            <field>
              <name>EPDIR</name>
              <description>Endpoint direction</description>
              <bitRange>[15:15]</bitRange>
            </field>
            <field>
              <name>LSDEV</name>
              <description>Low-speed device</description>
              <bitRange>[17:17]</bitRange>
            </field>
            <field>
              <name>EPTYP</name>
              <description>Endpoint type</description>
              <bitRange>[19:18]</bitRange>
            </field>
            <field>
              <name>MCNT</name>
              <description>Multicount</description>
              <bitRange>[21:20]</bitRange>
            </field>
            <field>
              <name>DAD</name>
              <description>Device address</description>
              <bitRange>[28:22]</bitRange>
            </field>
            <field>
              <name>ODDFRM</name>
              <description>Odd frame</description>
              <bitRange>[29:29]</bitRange>
            </field>
            <field>
              <name>CHDIS</name>
              <description>Channel disable</description>
              <bitRange>[30:30]</bitRange>
            </field>
            <field>
              <name>CHENA</name>
              <description>Channel enable</description>
              <bitRange>[31:31]</bitRange>
            </field>
          </fields>
        </register>
        <register>
          <name>FS_HCINT6</name>
          <description>OTG_FS host channel-6 interrupt register (OTG_FS_HCINT6)</description>
          <addressOffset>0x1C8</addressOffset>
          <fields>
            <field>
              <name>XFRC</name>
              <description>Transfer completed</description>
              <bitRange>[0:0]</bitRange>
            </field>
            <field>
              <name>CHH</name>
              <description>Channel halted</description>
              <bitRange>[1:1]</bitRange>
            </field>
            <field>
              <name>STALL</name>
              <description>STALL response received interrupt</description>
              <bitRange>[3:3]</bitRange>
            </field>
            <field>
              <name>NAK</name>
              <description>NAK response received interrupt</description>
              <bitRange>[4:4]</bitRange>
            </field>
            <field>
              <name>ACK</name>
              <description>ACK response received/transmitted interrupt</description>
              <bitRange>[5:5]</bitRange>
            </field>
            <field>
              <name>TXERR</name>
              <description>Transaction error</description>
              <bitRange>[7:7]</bitRange>
            </field>
            <field>
              <name>BBERR</name>
              <description>Babble error</description>
              <bitRange>[8:8]</bitRange>
            </field>
            <field>
              <name>FRMOR</name>
              <description>Frame overrun</description>
              <bitRange>[9:9]</bitRange>
            </field>
            <field>
              <name>DTERR</name>
              <description>Data toggle error</description>
              <bitRange>[10:10]</bitRange>
            </field>
          </fields>
        </register>
        <register>
          <name>FS_HCINTMSK6</name>
          <description>OTG_FS host channel-6 mask register (OTG_FS_HCINTMSK6)</description>
          <addressOffset>0x1CC</addressOffset>
          <fields>
            <field>
              <name>XFRCM</name>
              <description>Transfer completed mask</description>
              <bitRange>[0:0]</bitRange>
            </field>
            <field>
              <name>CHHM</name>
              <description>Channel halted mask</description>
              <bitRange>[1:1]</bitRange>
            </field>
            <field>
              <name>STALLM</name>
              <description>STALL response received interrupt mask</description>
              <bitRange>[3:3]</bitRange>
            </field>
            <field>
              <name>NAKM</name>
              <description>NAK response received interrupt mask</description>
              <bitRange>[4:4]</bitRange>
            </field>
            <field>
              <name>ACKM</name>
              <description>ACK response received/transmitted interrupt mask</description>
              <bitRange>[5:5]</bitRange>
            </field>
            <field>
              <name>NYET</name>
              <description>response received interrupt mask</description>
              <bitRange>[6:6]</bitRange>
            </field>
            <field>
              <name>TXERRM</name>
              <description>Transaction error mask</description>
              <bitRange>[7:7]</bitRange>
            </field>
            <field>
              <name>BBERRM</name>
              <description>Babble error mask</description>
              <bitRange>[8:8]</bitRange>
            </field>
            <field>
              <name>FRMORM</name>
              <description>Frame overrun mask</description>
              <bitRange>[9:9]</bitRange>
            </field>
            <field>
              <name>DTERRM</name>
              <description>Data toggle error mask</description>
              <bitRange>[10:10]</bitRange>
            </field>
          </fields>
        </register>
        <register>
          <name>FS_HCTSIZ6</name>
          <description>OTG_FS host channel-6 transfer size register</description>
          <addressOffset>0x1D0</addressOffset>
          <fields>
            <field>
              <name>XFRSIZ</name>
              <description>Transfer size</description>
              <bitRange>[18:0]</bitRange>
            </field>
            <field>
              <name>PKTCNT</name>
              <description>Packet count</description>
              <bitRange>[28:19]</bitRange>
            </field>
            <field>
              <name>DPID</name>
              <description>Data PID</description>
              <bitRange>[30:29]</bitRange>
            </field>
          </fields>
        </register>
        <register>
          <name>FS_HCCHAR7</name>
          <description>OTG_FS host channel-7 characteristics register (OTG_FS_HCCHAR7)</description>
          <addressOffset>0x1E0</addressOffset>
          <fields>
            <field>
              <name>MPSIZ</name>
              <description>Maximum packet size</description>
              <bitRange>[10:0]</bitRange>
            </field>
            <field>
              <name>EPNUM</name>
              <description>Endpoint number</description>
              <bitRange>[14:11]</bitRange>
            </field>
            <field>
              <name>EPDIR</name>
              <description>Endpoint direction</description>
              <bitRange>[15:15]</bitRange>
            </field>
            <field>
              <name>LSDEV</name>
              <description>Low-speed device</description>
              <bitRange>[17:17]</bitRange>
            </field>
            <field>
              <name>EPTYP</name>
              <description>Endpoint type</description>
              <bitRange>[19:18]</bitRange>
            </field>
            <field>
              <name>MCNT</name>
              <description>Multicount</description>
              <bitRange>[21:20]</bitRange>
            </field>
            <field>
              <name>DAD</name>
              <description>Device address</description>
              <bitRange>[28:22]</bitRange>
            </field>
            <field>
              <name>ODDFRM</name>
              <description>Odd frame</description>
              <bitRange>[29:29]</bitRange>
            </field>
            <field>
              <name>CHDIS</name>
              <description>Channel disable</description>
              <bitRange>[30:30]</bitRange>
            </field>
            <field>
              <name>CHENA</name>
              <description>Channel enable</description>
              <bitRange>[31:31]</bitRange>
            </field>
          </fields>
        </register>
        <register>
          <name>FS_HCINT7</name>
          <description>OTG_FS host channel-7 interrupt register (OTG_FS_HCINT7)</description>
          <addressOffset>0x1E8</addressOffset>
          <fields>
            <field>
              <name>XFRC</name>
              <description>Transfer completed</description>
              <bitRange>[0:0]</bitRange>
            </field>
            <field>
              <name>CHH</name>
              <description>Channel halted</description>
              <bitRange>[1:1]</bitRange>
            </field>
            <field>
              <name>STALL</name>
              <description>STALL response received interrupt</description>
              <bitRange>[3:3]</bitRange>
            </field>
            <field>
              <name>NAK</name>
              <description>NAK response received interrupt</description>
              <bitRange>[4:4]</bitRange>
            </field>
            <field>
              <name>ACK</name>
              <description>ACK response received/transmitted interrupt</description>
              <bitRange>[5:5]</bitRange>
            </field>
            <field>
              <name>TXERR</name>
              <description>Transaction error</description>
              <bitRange>[7:7]</bitRange>
            </field>
            <field>
              <name>BBERR</name>
              <description>Babble error</description>
              <bitRange>[8:8]</bitRange>
            </field>
            <field>
              <name>FRMOR</name>
              <description>Frame overrun</description>
              <bitRange>[9:9]</bitRange>
            </field>
            <field>
              <name>DTERR</name>
              <description>Data toggle error</description>
              <bitRange>[10:10]</bitRange>
            </field>
          </fields>
        </register>
        <register>
          <name>FS_HCINTMSK7</name>
          <description>OTG_FS host channel-7 mask register (OTG_FS_HCINTMSK7)</description>
          <addressOffset>0x1EC</addressOffset>
          <fields>
            <field>
              <name>XFRCM</name>
              <description>Transfer completed mask</description>
              <bitRange>[0:0]</bitRange>
            </field>
            <field>
              <name>CHHM</name>
              <description>Channel halted mask</description>
              <bitRange>[1:1]</bitRange>
            </field>
            <field>
              <name>STALLM</name>
              <description>STALL response received interrupt mask</description>
              <bitRange>[3:3]</bitRange>
            </field>
            <field>
              <name>NAKM</name>
              <description>NAK response received interrupt mask</description>
              <bitRange>[4:4]</bitRange>
            </field>
            <field>
              <name>ACKM</name>
              <description>ACK response received/transmitted interrupt mask</description>
              <bitRange>[5:5]</bitRange>
            </field>
            <field>
              <name>NYET</name>
              <description>response received interrupt mask</description>
              <bitRange>[6:6]</bitRange>
            </field>
            <field>
              <name>TXERRM</name>
              <description>Transaction error mask</description>
              <bitRange>[7:7]</bitRange>
            </field>
            <field>
              <name>BBERRM</name>
              <description>Babble error mask</description>
              <bitRange>[8:8]</bitRange>
            </field>
            <field>
              <name>FRMORM</name>
              <description>Frame overrun mask</description>
              <bitRange>[9:9]</bitRange>
            </field>
            <field>
              <name>DTERRM</name>
              <description>Data toggle error mask</description>
              <bitRange>[10:10]</bitRange>
            </field>
          </fields>
        </register>
        <register>
          <name>FS_HCTSIZ7</name>
          <description>OTG_FS host channel-7 transfer size register</description>
          <addressOffset>0x1F0</addressOffset>
          <fields>
            <field>
              <name>XFRSIZ</name>
              <description>Transfer size</description>
              <bitRange>[18:0]</bitRange>
            </field>
            <field>
              <name>PKTCNT</name>
              <description>Packet count</description>
              <bitRange>[28:19]</bitRange>
            </field>
            <field>
              <name>DPID</name>
              <description>Data PID</description>
              <bitRange>[30:29]</bitRange>
            </field>
          </fields>
        </register>
      </registers>
    </peripheral>
    <peripheral>
      <name>USB1_OTG_PWRCLK</name>
      <description>USB on the go full speed</description>
      <baseAddress>0x48040E00</baseAddress>
      <addressBlock>
        <offset>0x0</offset>
        <size>0x400</size>
        <usage>registers</usage>
      </addressBlock>
      <registers>
        <register>
          <name>FS_PCGCCTL</name>
          <description>OTG_FS power and clock gating control register (OTG_FS_PCGCCTL)</description>
          <addressOffset>0x0</addressOffset>
          <fields>
            <field>
              <name>STPPCLK</name>
              <description>Stop PHY clock</description>
              <bitRange>[0:0]</bitRange>
            </field>
            <field>
              <name>GATEHCLK</name>
              <description>Gate HCLK</description>
              <bitRange>[1:1]</bitRange>
            </field>
            <field>
              <name>PHYSUSP</name>
              <description>PHY Suspended</description>
              <bitRange>[4:4]</bitRange>
            </field>
          </fields>
        </register>
      </registers>
    </peripheral>
    <peripheral derivedFrom="USB1_OTG_DEVICE">
      <name>USB2_OTG_DEVICE</name>
      <baseAddress>0x48080800</baseAddress>
    </peripheral>
    <peripheral derivedFrom="USB1_OTG_GLOBAL">
      <name>USB2_OTG_GLOBAL</name>
      <baseAddress>0x48080000</baseAddress>
    </peripheral>
    <peripheral derivedFrom="USB1_OTG_HOST">
      <name>USB2_OTG_HOST</name>
      <baseAddress>0x48080400</baseAddress>
      <interrupt>
        <name>OTG2_FS_WKUP</name>
        <value>81</value>
      </interrupt>
      <interrupt>
        <name>OTG2_FS</name>
        <value>82</value>
      </interrupt>
    </peripheral>
    <peripheral derivedFrom="USB1_OTG_PWRCLK">
      <name>USB2_OTG_PWRCLK</name>
      <baseAddress>0x48080E00</baseAddress>
    </peripheral>
    <peripheral>
      <name>WWDG</name>
      <baseAddress>0x40002C00</baseAddress>
      <addressBlock>
        <offset>0x0</offset>
        <size>0x400</size>
        <usage>registers</usage>
      </addressBlock>
      <interrupt>
        <name>WWDG</name>
        <description>Window Watchdog global interrupt</description>
        <value>0</value>
      </interrupt>
      <registers>
        <register>
          <name>CR</name>
          <addressOffset>0x0</addressOffset>
          <fields>
            <field>
              <name>T</name>
              <description>wwdg 7-bit counter</description>
              <bitRange>[6:0]</bitRange>
            </field>
            <field>
              <name>WDGA</name>
              <description>WWDG Activation</description>
              <bitRange>[7:7]</bitRange>
            </field>
          </fields>
        </register>
        <register>
          <name>CFR</name>
          <addressOffset>0x4</addressOffset>
          <fields>
            <field>
              <name>W</name>
              <description>window value</description>
              <bitRange>[6:0]</bitRange>
            </field>
            <field>
              <name>WDGTB</name>
              <description>time base</description>
              <bitRange>[8:7]</bitRange>
            </field>
            <field>
              <name>EWI</name>
              <description>Early wakeup interrupt</description>
              <bitRange>[9:9]</bitRange>
            </field>
          </fields>
        </register>
        <register>
          <name>SR</name>
          <addressOffset>0x8</addressOffset>
          <size>16</size>
          <fields>
            <field>
              <name>EWIF</name>
              <description>Early wakeup interrupt flag</description>
              <bitRange>[0:0]</bitRange>
            </field>
          </fields>
        </register>
      </registers>
    </peripheral>
  </peripherals>
</device>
